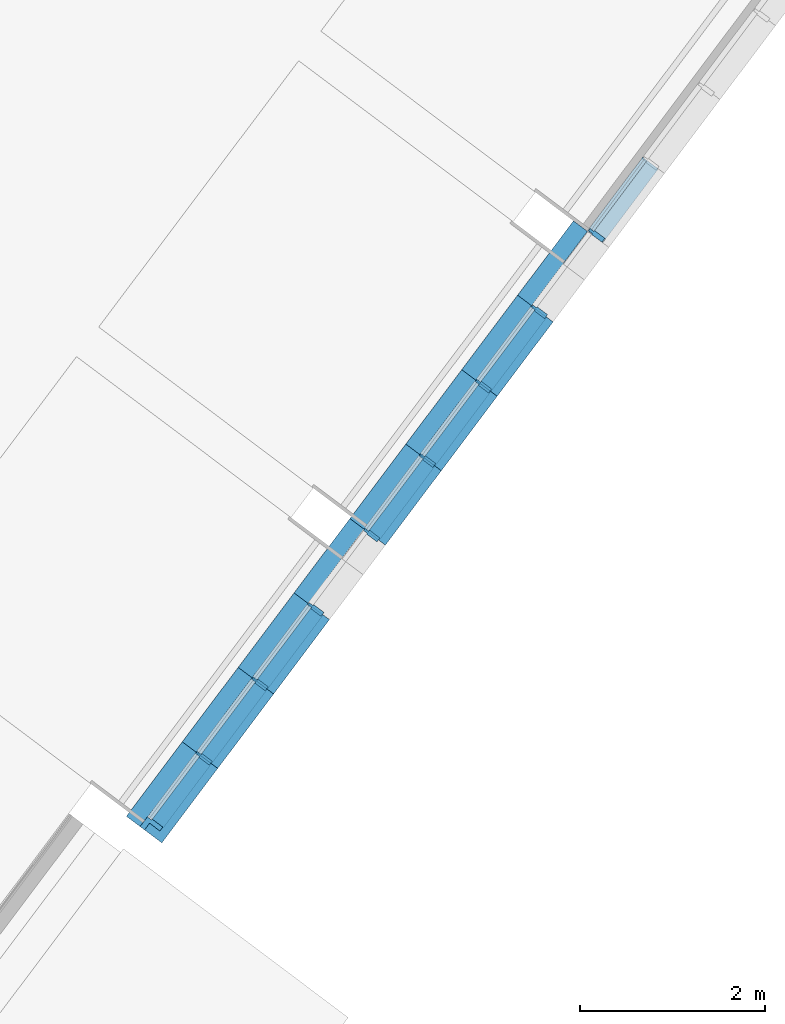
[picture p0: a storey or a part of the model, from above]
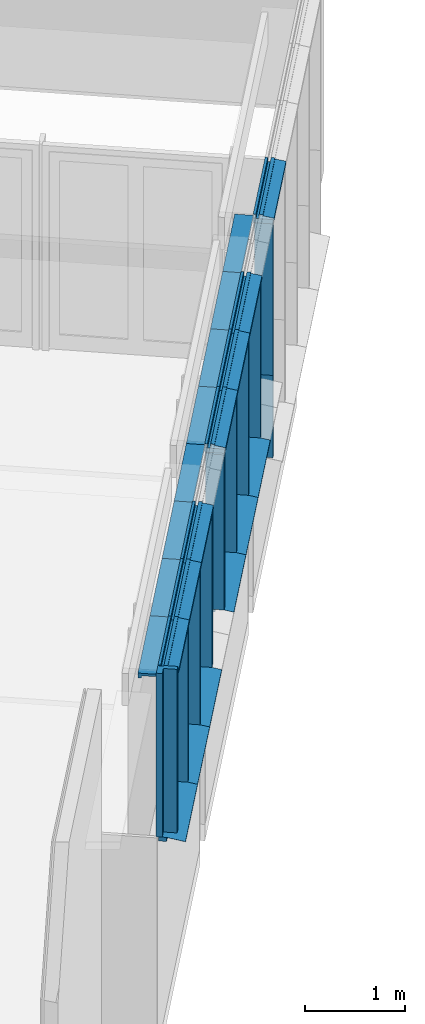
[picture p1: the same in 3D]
Properties of the parts of a building model (IFC2X3), part 1 of 6

# File
Description: ViewDefinition [CoordinationView_V2.0], RevitIdentifiers [VersionGUID: b3ee0134-e129-4b76-bc58-69f363ad4fec, NumberOfSaves: 221], CoordinateReference [CoordinateBase: Coordenadas compartidas, ProjectSite: Interna]
File name: 0001
Time: 2024-03-04T15:58:22
Written by: ODA IFC SDK 22.8
Made in: 22.1.50.17 - Exporter 22.6.2.0 - IU alternativa 22.6.2.0

# IfcProject, 0001
LongName: TÍTOL DEL PROJECTE; Phase: Estado de proyecto

# IfcSite, Default
RefLatitude: 40, 24, 0, 5493; RefLongitude: -3, -40, -59, -880065; RefElevation: 0 m

# IfcBuilding
Pset_BuildingCommon - NumberOfStoreys: 4

# IfcBuildingStorey: Nivel:A- Nivell (4)
Name | LongName | Elevation (m)
PS1- Gimnàs | PS1- Gimnàs | -5.45
PS1- Vestuari | PS1- Vestuari | -4.46
P0- Escola | P0- Escola | 0
PC- Coberta STR | PC- Coberta STR | 3.4

# IfcBeam: STR- V- Acer- RHS- Rectangular- T1:100x50RHS (57)
In: PC- Coberta STR
Type - Pset_BeamCommon - IsExternal: no; LoadBearing: yes
Material: Metal - Acero - 345 MPa
Pset_BeamCommon - Reference: 100x50RHS
Pset_QuantityTakeOff - Reference: 100x50RHS; sets with these values: 2
Name (STR- V- Acer- RHS- Rectangular- T1:100x50RHS:...) | Span (m) | Slope (deg) | Group
5302511 | 1.26 | 0 | Grupo de modelo:BADALOT 1 (elementos excluidos):5302593
5302515 | 0.454 | 0 | Grupo de modelo:BADALOT 1 (elementos excluidos):5302593
5302517 | 1.26 | 0 | Grupo de modelo:BADALOT 1 (elementos excluidos):5302593
5302522 | 0.454 | 0 | Grupo de modelo:BADALOT 1 (elementos excluidos):5302593
5302526 | 1.26 | 0 | Grupo de modelo:BADALOT 1 (elementos excluidos):5302593
5302528 | 0.454 | 0 | Grupo de modelo:BADALOT 1 (elementos excluidos):5302593
5302530 | 0.454 | 0 | Grupo de modelo:BADALOT 1 (elementos excluidos):5302593
5302534 | 1.479 | 0 | Grupo de modelo:BADALOT 1 (elementos excluidos):5302593
5307034 | 1.26 | 0 | Grupo de modelo:BADALOT 1 (elementos excluidos):5302593
5309079 | 1.26 | 0 | Grupo de modelo:BADALOT 2:5309104
5309083 | 0.454 | 0 | Grupo de modelo:BADALOT 2:5309104
5309085 | 1.279 | 0 | Grupo de modelo:BADALOT 2:5309104
5309090 | 0.454 | 0 | Grupo de modelo:BADALOT 2:5309104
5309094 | 1.26 | 0 | Grupo de modelo:BADALOT 2:5309104
5309096 | 0.454 | 0 | Grupo de modelo:BADALOT 2:5309104
5309098 | 0.454 | 0 | Grupo de modelo:BADALOT 2:5309104
5309102 | 1.26 | 0 | Grupo de modelo:BADALOT 2:5309104
5309427 | 1.26 | 0 | Grupo de modelo:BADALOT 2:5309452
5309431 | 0.454 | 0 | Grupo de modelo:BADALOT 2:5309452
5309433 | 1.279 | 0 | Grupo de modelo:BADALOT 2:5309452
5309438 | 0.454 | 0 | Grupo de modelo:BADALOT 2:5309452
5309442 | 1.26 | 0 | Grupo de modelo:BADALOT 2:5309452
5309444 | 0.454 | 0 | Grupo de modelo:BADALOT 2:5309452
5309446 | 0.454 | 0 | Grupo de modelo:BADALOT 2:5309452
5309450 | 1.26 | 0 | Grupo de modelo:BADALOT 2:5309452
5309613 | 1.26 | 0 | Grupo de modelo:BADALOT 2:5309638
5309617 | 0.454 | 0 | Grupo de modelo:BADALOT 2:5309638
5309619 | 1.279 | 0 | Grupo de modelo:BADALOT 2:5309638
5309624 | 0.454 | 0 | Grupo de modelo:BADALOT 2:5309638
5309628 | 1.26 | 0 | Grupo de modelo:BADALOT 2:5309638
5309630 | 0.454 | 0 | Grupo de modelo:BADALOT 2:5309638
5309632 | 0.454 | 0 | Grupo de modelo:BADALOT 2:5309638
5309636 | 1.26 | 0 | Grupo de modelo:BADALOT 2:5309638
5310923 | 1.26 | 0 | Grupo de modelo:BADALOT 2:5309104
5311217 | 1.26 | 0 | Grupo de modelo:BADALOT 2:5309452
5311237 | 1.26 | 0 | Grupo de modelo:BADALOT 2:5309638
5425147 | 1.26 | 0 | Grupo de modelo:BADALOT 3:5425172
5425151 | 0.454 | 0 | Grupo de modelo:BADALOT 3:5425172
5425153 | 1.26 | 0 | Grupo de modelo:BADALOT 3:5425172
5425158 | 0.454 | 0 | Grupo de modelo:BADALOT 3:5425172
5425162 | 1.26 | 0 | Grupo de modelo:BADALOT 3:5425172
5425164 | 0.454 | 0 | Grupo de modelo:BADALOT 3:5425172
5425166 | 0.454 | 0 | Grupo de modelo:BADALOT 3:5425172
5425170 | 1.479 | 0 | Grupo de modelo:BADALOT 3:5425172
5425182 | 1.26 | 0 | Grupo de modelo:BADALOT 3:5425172
5440108 | 4.097 | 0
5440140 | 3.139 | 3.653
5440886 | 5.24 | 2.08348
5440999 | 0.872 | 3.68981
5441164 | 2.229 | 3.68964
5442137 | 1.552 | 3.68611
5442275 | 3.734 | 0
5442300 | 3.535 | 3.24312
5442342 | 5.241 | 2.08871
5442374 | 0.986 | 3.27685
5442399 | 1.752 | 3.27625
5442435 | 2.518 | 3.27601

# IfcBuildingElementProxy: SER- Xemeneia revestiment:SER- Xemeneia revestiment (2)
In: PC- Coberta STR
Type - Material: <Unnamed>
Pset_BuildingElementProxyCommon - Reference: SER- Xemeneia revestiment; sets with these values: 2
Name (SER- Xemeneia revestiment:SER- Xemeneia revestiment:...)
5313121
5313976

# IfcBuildingElementProxy: SOS- fals sostre biblio:SOS- fals sostre biblio, SOS- fals sostre biblio:SOS- fals sostre biblio:4920332
In: P0- Escola
Type - Material: <Unnamed>
Pset_BuildingElementProxyCommon - Reference: SOS- fals sostre biblio; sets with these values: 2

# IfcColumn: STR- P- Acer- RHS- Rectangular- T1:100 x 50RHS (84)
In: PC- Coberta STR
Type - PredefinedType: COLUMN; Material: Metal - Acero - 345 MPa
Type - Pset_ColumnCommon - IsExternal: no; LoadBearing: yes
Pset_ColumnCommon - Reference: 100 x 50RHS
Pset_QuantityTakeOff - Reference: 100 x 50RHS; sets with these values: 2
Name (STR- P- Acer- RHS- Rectangular- T1:100 x 50RHS:...) | Group
5302475 | Grupo de modelo:BADALOT 1 (elementos excluidos):5302593
5302477 | Grupo de modelo:BADALOT 1 (elementos excluidos):5302593
5302479 | Grupo de modelo:BADALOT 1 (elementos excluidos):5302593
5302481 | Grupo de modelo:BADALOT 1 (elementos excluidos):5302593
5302483 | Grupo de modelo:BADALOT 1 (elementos excluidos):5302593
5302485 | Grupo de modelo:BADALOT 1 (elementos excluidos):5302593
5302487 | Grupo de modelo:BADALOT 1 (elementos excluidos):5302593
5302489 | Grupo de modelo:BADALOT 1 (elementos excluidos):5302593
5302491 | Grupo de modelo:BADALOT 1 (elementos excluidos):5302593
5302493 | Grupo de modelo:BADALOT 1 (elementos excluidos):5302593
5302495 | Grupo de modelo:BADALOT 1 (elementos excluidos):5302593
5302497 | Grupo de modelo:BADALOT 1 (elementos excluidos):5302593
5302499 | Grupo de modelo:BADALOT 1 (elementos excluidos):5302593
5302501 | Grupo de modelo:BADALOT 1 (elementos excluidos):5302593
5302503 | Grupo de modelo:BADALOT 1 (elementos excluidos):5302593
5302505 | Grupo de modelo:BADALOT 1 (elementos excluidos):5302593
5302507 | Grupo de modelo:BADALOT 1 (elementos excluidos):5302593
5302509 | Grupo de modelo:BADALOT 1 (elementos excluidos):5302593
5309047 | Grupo de modelo:BADALOT 2:5309104
5309049 | Grupo de modelo:BADALOT 2:5309104
5309051 | Grupo de modelo:BADALOT 2:5309104
5309053 | Grupo de modelo:BADALOT 2:5309104
5309055 | Grupo de modelo:BADALOT 2:5309104
5309057 | Grupo de modelo:BADALOT 2:5309104
5309059 | Grupo de modelo:BADALOT 2:5309104
5309061 | Grupo de modelo:BADALOT 2:5309104
5309063 | Grupo de modelo:BADALOT 2:5309104
5309065 | Grupo de modelo:BADALOT 2:5309104
5309067 | Grupo de modelo:BADALOT 2:5309104
5309069 | Grupo de modelo:BADALOT 2:5309104
5309071 | Grupo de modelo:BADALOT 2:5309104
5309073 | Grupo de modelo:BADALOT 2:5309104
5309075 | Grupo de modelo:BADALOT 2:5309104
5309077 | Grupo de modelo:BADALOT 2:5309104
5309395 | Grupo de modelo:BADALOT 2:5309452
5309397 | Grupo de modelo:BADALOT 2:5309452
5309399 | Grupo de modelo:BADALOT 2:5309452
5309401 | Grupo de modelo:BADALOT 2:5309452
5309403 | Grupo de modelo:BADALOT 2:5309452
5309405 | Grupo de modelo:BADALOT 2:5309452
5309407 | Grupo de modelo:BADALOT 2:5309452
5309409 | Grupo de modelo:BADALOT 2:5309452
5309411 | Grupo de modelo:BADALOT 2:5309452
5309413 | Grupo de modelo:BADALOT 2:5309452
5309415 | Grupo de modelo:BADALOT 2:5309452
5309417 | Grupo de modelo:BADALOT 2:5309452
5309419 | Grupo de modelo:BADALOT 2:5309452
5309421 | Grupo de modelo:BADALOT 2:5309452
5309423 | Grupo de modelo:BADALOT 2:5309452
5309425 | Grupo de modelo:BADALOT 2:5309452
5309581 | Grupo de modelo:BADALOT 2:5309638
5309583 | Grupo de modelo:BADALOT 2:5309638
5309585 | Grupo de modelo:BADALOT 2:5309638
5309587 | Grupo de modelo:BADALOT 2:5309638
5309589 | Grupo de modelo:BADALOT 2:5309638
5309591 | Grupo de modelo:BADALOT 2:5309638
5309593 | Grupo de modelo:BADALOT 2:5309638
5309595 | Grupo de modelo:BADALOT 2:5309638
5309597 | Grupo de modelo:BADALOT 2:5309638
5309599 | Grupo de modelo:BADALOT 2:5309638
5309601 | Grupo de modelo:BADALOT 2:5309638
5309603 | Grupo de modelo:BADALOT 2:5309638
5309605 | Grupo de modelo:BADALOT 2:5309638
5309607 | Grupo de modelo:BADALOT 2:5309638
5309609 | Grupo de modelo:BADALOT 2:5309638
5309611 | Grupo de modelo:BADALOT 2:5309638
5425111 | Grupo de modelo:BADALOT 3:5425172
5425113 | Grupo de modelo:BADALOT 3:5425172
5425115 | Grupo de modelo:BADALOT 3:5425172
5425117 | Grupo de modelo:BADALOT 3:5425172
5425119 | Grupo de modelo:BADALOT 3:5425172
5425121 | Grupo de modelo:BADALOT 3:5425172
5425123 | Grupo de modelo:BADALOT 3:5425172
5425125 | Grupo de modelo:BADALOT 3:5425172
5425127 | Grupo de modelo:BADALOT 3:5425172
5425129 | Grupo de modelo:BADALOT 3:5425172
5425131 | Grupo de modelo:BADALOT 3:5425172
5425133 | Grupo de modelo:BADALOT 3:5425172
5425135 | Grupo de modelo:BADALOT 3:5425172
5425137 | Grupo de modelo:BADALOT 3:5425172
5425139 | Grupo de modelo:BADALOT 3:5425172
5425141 | Grupo de modelo:BADALOT 3:5425172
5425143 | Grupo de modelo:BADALOT 3:5425172
5425145 | Grupo de modelo:BADALOT 3:5425172

# IfcCovering: Techo compuesto:SOS- Fusta- Revestiment- 6 cm (16)
In: P0- Escola
Type - PredefinedType: CEILING
Type - Pset_CoveringCommon - TotalThickness: 0.06 m
Material: _Fusta massisa- T1 0.06 m
Pset_CoveringCommon - Reference: SOS- Fusta- Revestiment- 6 cm; sets with these values: 2
Name (Techo compuesto:SOS- Fusta- Revestiment- 6 cm:...) | Group
102032
102040
102047 | Grupo de modelo:FUS- Conjunt divisoria aules infantil:337545
102054
115284 | Grupo de modelo:SOS- fusta- despatxos:115317
115290 | Grupo de modelo:SOS- fusta- despatxos:115317
115297 | Grupo de modelo:SOS- fusta- despatxos:115317
115304 | Grupo de modelo:SOS- fusta- despatxos:115317
115311 | Grupo de modelo:SOS- fusta- despatxos:115317
342692 | Grupo de modelo:FUS- Conjunt divisoria aules infantil:337581
470245 | Grupo de modelo:Grup aula:4934097
3335595 | Grupo de modelo:Grup aula:4934097
4940526 | Grupo de modelo:Grup aula:4940566
4940549 | Grupo de modelo:Grup aula:4940566
4940782 | Grupo de modelo:Grup aula:4940822
4940805 | Grupo de modelo:Grup aula:4940822

# IfcCovering: Techo compuesto:SOS- Guix Laminat Acústic- Aillament- 6,5 cm 2 (9)
Type - PredefinedType: CEILING
Type - Pset_CoveringCommon - TotalThickness: 0.065 m
Material: _Aillament 0.05 m, _PYL- SOS 0.015 m
Pset_CoveringCommon - Reference: SOS- Guix Laminat Acústic- Aillament- 6,5 cm 2; sets with these values: 2
Name (Techo compuesto:SOS- Guix Laminat Acústic- Aillament- 6,5 cm 2:...) | In | Group
101186 | PS1- Gimnàs | Grupo de modelo:SOS- grup sostre i tabica gimnàs:101203
101219 | PS1- Gimnàs | Grupo de modelo:SOS- grup sostre i tabica gimnàs:101232
101235 | PS1- Gimnàs | Grupo de modelo:SOS- grup sostre i tabica gimnàs:101248
101253 | PS1- Gimnàs
114977 | PS1- Vestuari | Grupo de modelo:SOS- Planta pista:115104
115002 | PS1- Vestuari | Grupo de modelo:SOS- Planta pista:115104
115026 | PS1- Vestuari | Grupo de modelo:SOS- Planta pista:115104
115050 | PS1- Vestuari | Grupo de modelo:SOS- Planta pista:115104
115074 | PS1- Vestuari | Grupo de modelo:SOS- Planta pista:115104

# IfcCovering: Techo compuesto:SOS- Guix Laminat- Aillament- 10 cm (2)
In: P0- Escola
Type - PredefinedType: CEILING
Type - Pset_CoveringCommon - TotalThickness: 0.1 m
Material: _Aillament 0.085 m, _PYL- SOS 0.015 m
Pset_CoveringCommon - Reference: SOS- Guix Laminat- Aillament- 10 cm; sets with these values: 2
Name (Techo compuesto:SOS- Guix Laminat- Aillament- 10 cm:...)
4915247
4915999

# IfcCovering: Techo compuesto:SOS- Guix Laminat- Aillament- 3,5 cm (13)
Type - PredefinedType: CEILING
Type - Pset_CoveringCommon - TotalThickness: 0.035 m
Material: _Aillament 0.02 m, _PYL- SOS 0.015 m
Pset_CoveringCommon - Reference: SOS- Guix Laminat- Aillament- 3,5 cm; sets with these values: 2
Name (Techo compuesto:SOS- Guix Laminat- Aillament- 3,5 cm:...) | In | Group
101071 | P0- Escola
101078 | P0- Escola | Grupo de modelo:REV- Acabats interiors modul:100748
101085 | P0- Escola | Grupo de modelo:REV- Acabats interiors modul:100819
114992 | PS1- Vestuari | Grupo de modelo:SOS- Planta pista:115104
115017 | PS1- Vestuari | Grupo de modelo:SOS- Planta pista:115104
115041 | PS1- Vestuari | Grupo de modelo:SOS- Planta pista:115104
115065 | PS1- Vestuari | Grupo de modelo:SOS- Planta pista:115104
115089 | PS1- Vestuari | Grupo de modelo:SOS- Planta pista:115104
115220 | P0- Escola | Grupo de modelo:SOS- MODUL INFAINTIL I MENJADOR:115116
115227 | P0- Escola | Grupo de modelo:SOS- MODUL INFAINTIL I MENJADOR:115116
5387460 | P0- Escola
5403830 | P0- Escola
5404382 | P0- Escola

# IfcCovering: Techo compuesto:SOS- Guix Laminat- Aillament- 5 cm (5)
In: PS1- Gimnàs
Type - PredefinedType: CEILING
Type - Pset_CoveringCommon - TotalThickness: 0.05 m
Material: _Aillament 0.035 m, _PYL- SOS 0.015 m; Group: Grupo de modelo:SOS- Planta pista:115104
Pset_CoveringCommon - Reference: SOS- Guix Laminat- Aillament- 5 cm; sets with these values: 2
Name (Techo compuesto:SOS- Guix Laminat- Aillament- 5 cm:...)
114983
115008
115032
115056
115080

# IfcCovering: Techo compuesto:SOS- Guix Laminat- Aillament- 6,5 cm (57)
Type - PredefinedType: CEILING
Type - Pset_CoveringCommon - TotalThickness: 0.065 m
Material: _Aillament 0.05 m, _PYL- SOS 0.015 m
Pset_CoveringCommon - Reference: SOS- Guix Laminat- Aillament- 6,5 cm; sets with these values: 2
Name (Techo compuesto:SOS- Guix Laminat- Aillament- 6,5 cm:...) | In | Group
100559 | P0- Escola
100570 | P0- Escola
100695 | P0- Escola | Grupo de modelo:REV- Acabats interiors modul:100748
100705 | P0- Escola | Grupo de modelo:REV- Acabats interiors modul:100748
100766 | P0- Escola | Grupo de modelo:REV- Acabats interiors modul:100819
100776 | P0- Escola | Grupo de modelo:REV- Acabats interiors modul:100819
100856 | P0- Escola | Grupo de modelo:REV- Acabats interiors modul:100748
100863 | P0- Escola | Grupo de modelo:REV- Acabats interiors modul:100819
100945 | P0- Escola
100955 | P0- Escola
101018 | P0- Escola
101192 | PS1- Gimnàs | Grupo de modelo:SOS- grup sostre i tabica gimnàs:101203
101212 | PS1- Gimnàs
101225 | PS1- Gimnàs | Grupo de modelo:SOS- grup sostre i tabica gimnàs:101232
101241 | PS1- Gimnàs | Grupo de modelo:SOS- grup sostre i tabica gimnàs:101248
101367 | P0- Escola
101390 | P0- Escola
101583 | P0- Escola
101592 | P0- Escola
101599 | P0- Escola
101606 | P0- Escola
101613 | P0- Escola
101715 | P0- Escola
102026 | P0- Escola
115111 | P0- Escola | Grupo de modelo:SOS- MODUL INFAINTIL I MENJADOR:115116
115119 | P0- Escola | Grupo de modelo:SOS- MODUL INFAINTIL I MENJADOR:115116
115134 | P0- Escola | Grupo de modelo:SOS- MODUL INFAINTIL I MENJADOR:115116
115141 | P0- Escola | Grupo de modelo:SOS- MODUL INFAINTIL I MENJADOR:115116
115148 | P0- Escola | Grupo de modelo:SOS- MODUL INFAINTIL I MENJADOR:115116
115156 | P0- Escola | Grupo de modelo:SOS- MODUL INFAINTIL I MENJADOR:115116
115165 | P0- Escola | Grupo de modelo:SOS- MODUL INFAINTIL I MENJADOR:115116
115172 | P0- Escola | Grupo de modelo:SOS- MODUL INFAINTIL I MENJADOR:115116
115179 | P0- Escola | Grupo de modelo:SOS- MODUL INFAINTIL I MENJADOR:115116
115186 | P0- Escola | Grupo de modelo:SOS- MODUL INFAINTIL I MENJADOR:115116
115193 | P0- Escola | Grupo de modelo:SOS- MODUL INFAINTIL I MENJADOR:115116
115204 | P0- Escola | Grupo de modelo:SOS- MODUL INFAINTIL I MENJADOR:115116
115213 | P0- Escola | Grupo de modelo:SOS- MODUL INFAINTIL I MENJADOR:115116
115234 | P0- Escola | Grupo de modelo:SOS- MODUL INFAINTIL I MENJADOR:115116
115241 | P0- Escola | Grupo de modelo:SOS- MODUL INFAINTIL I MENJADOR:115116
115248 | P0- Escola | Grupo de modelo:SOS- MODUL INFAINTIL I MENJADOR:115116
115255 | P0- Escola | Grupo de modelo:SOS- MODUL INFAINTIL I MENJADOR:115116
115270 | P0- Escola | Grupo de modelo:SOS- MODUL INFAINTIL I MENJADOR:115116
115277 | P0- Escola | Grupo de modelo:SOS- MODUL INFAINTIL I MENJADOR:115116
1253167 | P0- Escola
1352866 | P0- Escola
4915733 | P0- Escola
4925135 | P0- Escola
4940842 | P0- Escola | Grupo de modelo:Grup aula:4934097
4941253 | P0- Escola | Grupo de modelo:Grup aula:4940566
4941303 | P0- Escola | Grupo de modelo:Grup aula:4940822
5389637 | P0- Escola
5406528 | P0- Escola | Grupo de modelo:Modul Banys 2:100913
5406683 | P0- Escola | Grupo de modelo:Modul Banys 2:100913
5406933 | P0- Escola | Grupo de modelo:Modul Banys (elementos excluidos):100597
5406947 | P0- Escola | Grupo de modelo:Modul Banys (elementos excluidos):100597
5413137 | P0- Escola | Grupo de modelo:SOS- MODUL INFAINTIL I MENJADOR:115116
5413163 | P0- Escola | Grupo de modelo:SOS- MODUL INFAINTIL I MENJADOR:115116

# IfcCurtainWall: Muro básico:ENV- Ceràmic- 9 cm (3)
In: P0- Escola
Type - Material: _Ceràmica- ENV 0.09 m
Type - Pset_CurtainWallCommon - IsExternal: yes
Pset_CurtainWallCommon - Reference: ENV- Ceràmic- 9 cm
Pset_QuantityTakeOff - Reference: ENV- Ceràmic- 9 cm
Name (Muro básico:ENV- Ceràmic- 9 cm:...) | Group
2141167 | Grupo de modelo:BANY1:2141168
2334015 | Grupo de modelo:BANY1:2334016
2334665 | Grupo de modelo:BANY1:2334666

# IfcCurtainWall: Muro básico:REV- Fusta- T1- 3,5 cm (11)
In: P0- Escola
Type - Material: _Fusta massisa- T1- REV- PAV 0.015 m, _Genèric perfils, muntants, rastrells 0.02 m
Type - Pset_CurtainWallCommon - IsExternal: no; ThermalTransmittance: 1.25 kg/K/s3
Pset_CurtainWallCommon - Reference: REV- Fusta- T1- 3,5 cm
Pset_QuantityTakeOff - Reference: REV- Fusta- T1- 3,5 cm
Name (Muro básico:REV- Fusta- T1- 3,5 cm:...) | Group
373448
373449
462916 | Grupo de modelo:Grup aula:4934097
2141159 | Grupo de modelo:BANY1:2141168
2141160 | Grupo de modelo:BANY1:2141168
2334007 | Grupo de modelo:BANY1:2334016
2334008 | Grupo de modelo:BANY1:2334016
2334657 | Grupo de modelo:BANY1:2334666
2334658 | Grupo de modelo:BANY1:2334666
4940524 | Grupo de modelo:Grup aula:4940566
4940780 | Grupo de modelo:Grup aula:4940822

# IfcCurtainWall: Muro cortina:MC- EXT- AL1- Fa porxo (9)
In: P0- Escola
Type - Pset_CurtainWallCommon - IsExternal: yes
Pset_CurtainWallCommon - Reference: MC- EXT- AL1- Fa porxo
Pset_QuantityTakeOff - Reference: MC- EXT- AL1- Fa porxo
Group: Grupo de modelo:Fa-:4013115
Name (Muro cortina:MC- EXT- AL1- Fa porxo:...)
4009178
4510528
4816952
4825851
4935185
4935323
4935594
4935732
4943344

# IfcCurtainWall: Muro cortina:MC- EXT- AL3 (3)
In: P0- Escola
Type - Pset_CurtainWallCommon - IsExternal: yes
Pset_CurtainWallCommon - Reference: MC- EXT- AL3
Pset_QuantityTakeOff - Reference: MC- EXT- AL3
Name (Muro cortina:MC- EXT- AL3:...)
895046
5131475
5410565

# IfcCurtainWall: Muro cortina:MC- EXT- AL4a (2)
In: P0- Escola
Type - Pset_CurtainWallCommon - IsExternal: yes
Pset_CurtainWallCommon - Reference: MC- EXT- AL4a
Pset_QuantityTakeOff - Reference: MC- EXT- AL4a
Name (Muro cortina:MC- EXT- AL4a:...)
4810601
4889902

# IfcCurtainWall: Muro cortina:MC- EXT- AL5b (2)
In: P0- Escola
Type - Pset_CurtainWallCommon - IsExternal: yes
Pset_CurtainWallCommon - Reference: MC- EXT- AL5b
Pset_QuantityTakeOff - Reference: MC- EXT- AL5b
Name (Muro cortina:MC- EXT- AL5b:...)
4898266
4899970

# IfcCurtainWall: Muro cortina:MC- EXT- AL6 (8)
In: PS1- Vestuari
Type - Pset_CurtainWallCommon - IsExternal: yes
Pset_CurtainWallCommon - Reference: MC- EXT- AL6
Pset_QuantityTakeOff - Reference: MC- EXT- AL6
Name (Muro cortina:MC- EXT- AL6:...)
102148
102313
102319
102326
102332
102338
5323810
5323961

# IfcCurtainWall: Muro cortina:MC- EXT- AL7a (3)
In: P0- Escola
Type - Pset_CurtainWallCommon - IsExternal: yes
Pset_CurtainWallCommon - Reference: MC- EXT- AL7a
Pset_QuantityTakeOff - Reference: MC- EXT- AL7a
Group: Grupo de modelo:Fa-:4013115
Name (Muro cortina:MC- EXT- AL7a:...)
5381533
5401885
5401914

# IfcCurtainWall: Muro cortina:MC- EXT- Al4b (3)
In: P0- Escola
Type - Pset_CurtainWallCommon - IsExternal: yes
Pset_CurtainWallCommon - Reference: MC- EXT- Al4b
Pset_QuantityTakeOff - Reference: MC- EXT- Al4b
Name (Muro cortina:MC- EXT- Al4b:...)
4792293
4809763
4810606

# IfcCurtainWall: Muro cortina:MC- EXT- MC2 (7)
In: P0- Escola
Type - Pset_CurtainWallCommon - IsExternal: yes
Pset_CurtainWallCommon - Reference: MC- EXT- MC2
Pset_QuantityTakeOff - Reference: MC- EXT- MC2
Group: Grupo de modelo:Fa-:4013115
Name (Muro cortina:MC- EXT- MC2:...)
2564638
3336758
4816830
4820767
4825035
6029251
6029575

# IfcCurtainWall: Muro cortina:MC- EXT- MC5 (4)
In: P0- Escola
Type - Pset_CurtainWallCommon - IsExternal: yes
Pset_CurtainWallCommon - Reference: MC- EXT- MC5
Pset_QuantityTakeOff - Reference: MC- EXT- MC5
Group: Grupo de modelo:Fa-:4013115
Name (Muro cortina:MC- EXT- MC5:...)
4468966
4935647
4943381
6029327

# IfcCurtainWall: Muro cortina:MC- EXT- MC6 (4)
In: P0- Escola
Type - Pset_CurtainWallCommon - IsExternal: yes
Pset_CurtainWallCommon - Reference: MC- EXT- MC6
Pset_QuantityTakeOff - Reference: MC- EXT- MC6
Name (Muro cortina:MC- EXT- MC6:...)
4774200
4791940
4865601
4873584

# IfcCurtainWall: Muro cortina:MC- EXT- MC7 (2)
In: P0- Escola
Type - Pset_CurtainWallCommon - IsExternal: yes
Pset_CurtainWallCommon - Reference: MC- EXT- MC7
Pset_QuantityTakeOff - Reference: MC- EXT- MC7
Name (Muro cortina:MC- EXT- MC7:...)
4908964
4909148

# IfcCurtainWall: Muro cortina:MC- EXT- MC8- Biblio, Muro cortina:MC- EXT- MC8- Biblio:4924527
In: PC- Coberta STR
Type - Pset_CurtainWallCommon - IsExternal: yes
Pset_CurtainWallCommon - Reference: MC- EXT- MC8- Biblio
Pset_QuantityTakeOff - Reference: MC- EXT- MC8- Biblio

# IfcCurtainWall: Muro cortina:MC- EXT- MC9, Muro cortina:MC- EXT- MC9:4868636
In: P0- Escola
Type - Pset_CurtainWallCommon - IsExternal: yes
Pset_CurtainWallCommon - Reference: MC- EXT- MC9
Pset_QuantityTakeOff - Reference: MC- EXT- MC9

# IfcCurtainWall: Muro cortina:MC- EXT- MCv1- Portes (4)
In: PS1- Gimnàs
Type - Pset_CurtainWallCommon - IsExternal: yes
Pset_CurtainWallCommon - Reference: MC- EXT- MCv1- Portes
Pset_QuantityTakeOff - Reference: MC- EXT- MCv1- Portes
Name (Muro cortina:MC- EXT- MCv1- Portes:...)
4666957
4685242
4704293
4718935

# IfcCurtainWall: Muro cortina:MC- EXT- MCv1- frontal, Muro cortina:MC- EXT- MCv1- frontal:4694275
In: PS1- Gimnàs
Type - Pset_CurtainWallCommon - IsExternal: yes
Pset_CurtainWallCommon - Reference: MC- EXT- MCv1- frontal
Pset_QuantityTakeOff - Reference: MC- EXT- MCv1- frontal

# IfcCurtainWall: Muro cortina:MC- EXT- MCv1- lateral (2)
In: PS1- Gimnàs
Type - Pset_CurtainWallCommon - IsExternal: yes
Pset_CurtainWallCommon - Reference: MC- EXT- MCv1- lateral
Pset_QuantityTakeOff - Reference: MC- EXT- MCv1- lateral
Name (Muro cortina:MC- EXT- MCv1- lateral:...)
4667045
4756194

# IfcCurtainWall: Muro cortina:MC- EXT- MCv1- lateral 2, Muro cortina:MC- EXT- MCv1- lateral 2:4667071
In: PS1- Gimnàs
Type - Pset_CurtainWallCommon - IsExternal: yes
Pset_CurtainWallCommon - Reference: MC- EXT- MCv1- lateral 2
Pset_QuantityTakeOff - Reference: MC- EXT- MCv1- lateral 2

# IfcCurtainWall: Muro cortina:MC- INT- C1, Muro cortina:MC- INT- C1:4901822
In: P0- Escola
Type - Pset_CurtainWallCommon - IsExternal: yes
Pset_CurtainWallCommon - Reference: MC- INT- C1
Pset_QuantityTakeOff - Reference: MC- INT- C1

# IfcCurtainWall: Muro cortina:MC- INT- C2, Muro cortina:MC- INT- C2:5092651
In: P0- Escola
Type - Pset_CurtainWallCommon - IsExternal: yes
Pset_CurtainWallCommon - Reference: MC- INT- C2
Pset_QuantityTakeOff - Reference: MC- INT- C2

# IfcCurtainWall: Muro cortina:MC- INT- Fa Pista (2)
In: P0- Escola
Type - Pset_CurtainWallCommon - IsExternal: yes
Pset_CurtainWallCommon - Reference: MC- INT- Fa Pista
Pset_QuantityTakeOff - Reference: MC- INT- Fa Pista
Name (Muro cortina:MC- INT- Fa Pista:...)
4865596
4868010

# IfcCurtainWall: Muro cortina:MC- INT- K3a- Fa Biblio (2)
In: P0- Escola
Type - Pset_CurtainWallCommon - IsExternal: yes
Pset_CurtainWallCommon - Reference: MC- INT- K3a- Fa Biblio
Pset_QuantityTakeOff - Reference: MC- INT- K3a- Fa Biblio
Name (Muro cortina:MC- INT- K3a- Fa Biblio:...)
4913482
4914954

# IfcCurtainWall: Muro cortina:MC- INT- K3a- Fa Pista (2)
In: P0- Escola
Type - Pset_CurtainWallCommon - IsExternal: yes
Pset_CurtainWallCommon - Reference: MC- INT- K3a- Fa Pista
Pset_QuantityTakeOff - Reference: MC- INT- K3a- Fa Pista
Name (Muro cortina:MC- INT- K3a- Fa Pista:...)
4892050
4928468

# IfcCurtainWall: Muro cortina:MC- INT- a1 (3)
In: P0- Escola
Type - Pset_CurtainWallCommon - IsExternal: yes
Pset_CurtainWallCommon - Reference: MC- INT- a1
Pset_QuantityTakeOff - Reference: MC- INT- a1
Name (Muro cortina:MC- INT- a1:...) | Group
462851 | Grupo de modelo:Grup aula:4934097
4940459 | Grupo de modelo:Grup aula:4940566
4940715 | Grupo de modelo:Grup aula:4940822

# IfcCurtainWall: Muro cortina:MC- INT- a2, Muro cortina:MC- INT- a2:360232
In: P0- Escola
Type - Pset_CurtainWallCommon - IsExternal: yes
Pset_CurtainWallCommon - Reference: MC- INT- a2
Pset_QuantityTakeOff - Reference: MC- INT- a2

# IfcCurtainWall: Muro cortina:MC- INT- a3, Muro cortina:MC- INT- a3:338958
In: P0- Escola
Type - Pset_CurtainWallCommon - IsExternal: yes
Pset_CurtainWallCommon - Reference: MC- INT- a3
Pset_QuantityTakeOff - Reference: MC- INT- a3

# IfcCurtainWall: Muro cortina:MC- INT- a4 (2)
In: P0- Escola
Type - Pset_CurtainWallCommon - IsExternal: yes
Pset_CurtainWallCommon - Reference: MC- INT- a4
Pset_QuantityTakeOff - Reference: MC- INT- a4
Name (Muro cortina:MC- INT- a4:...)
211473
369614

# IfcCurtainWall: Muro cortina:MC- INT- a4- 5cm (2)
In: P0- Escola
Type - Pset_CurtainWallCommon - IsExternal: yes
Pset_CurtainWallCommon - Reference: MC- INT- a4- 5cm
Pset_QuantityTakeOff - Reference: MC- INT- a4- 5cm
Name (Muro cortina:MC- INT- a4- 5cm:...)
371275
372966

# IfcCurtainWall: Muro cortina:MC- INT- b3, Muro cortina:MC- INT- b3:5100338
In: P0- Escola
Type - Pset_CurtainWallCommon - IsExternal: yes
Pset_CurtainWallCommon - Reference: MC- INT- b3
Pset_QuantityTakeOff - Reference: MC- INT- b3

# IfcCurtainWall: Muro cortina:MC- INT- k1- Bany infantil (3)
In: P0- Escola
Type - Pset_CurtainWallCommon - IsExternal: yes
Pset_CurtainWallCommon - Reference: MC- INT- k1- Bany infantil
Pset_QuantityTakeOff - Reference: MC- INT- k1- Bany infantil
Name (Muro cortina:MC- INT- k1- Bany infantil:...) | Group
2141140 | Grupo de modelo:BANY1:2141168
2333993 | Grupo de modelo:BANY1:2334016
2334643 | Grupo de modelo:BANY1:2334666

# IfcCurtainWall: Muro cortina:MC- INT- k1- Bany infantil- Peprendicular (3)
In: P0- Escola
Type - Pset_CurtainWallCommon - IsExternal: yes
Pset_CurtainWallCommon - Reference: MC- INT- k1- Bany infantil- Peprendicular
Pset_QuantityTakeOff - Reference: MC- INT- k1- Bany infantil- Peprendicular
Name (Muro cortina:MC- INT- k1- Bany infantil- Peprendicular:...) | Group
2141161 | Grupo de modelo:BANY1:2141168
2334009 | Grupo de modelo:BANY1:2334016
2334659 | Grupo de modelo:BANY1:2334666

# IfcCurtainWall: Muro cortina:MC- INT- k10- Pati passadís (2)
In: P0- Escola
Type - Pset_CurtainWallCommon - IsExternal: yes
Pset_CurtainWallCommon - Reference: MC- INT- k10- Pati passadís
Pset_QuantityTakeOff - Reference: MC- INT- k10- Pati passadís
Group: Grupo de modelo:Fusteries interior (elementos excluidos):3262893
Name (Muro cortina:MC- INT- k10- Pati passadís:...)
3299908
3300245

# IfcCurtainWall: Muro cortina:MC- INT- k2- Pati passadís (4)
In: P0- Escola
Type - Pset_CurtainWallCommon - IsExternal: yes
Pset_CurtainWallCommon - Reference: MC- INT- k2- Pati passadís
Pset_QuantityTakeOff - Reference: MC- INT- k2- Pati passadís
Group: Grupo de modelo:Fusteries interior (elementos excluidos):3262893
Name (Muro cortina:MC- INT- k2- Pati passadís:...)
3283211
3283535
5393540
5405264

# IfcCurtainWall: Muro cortina:MC- INT- k2- Pati passadís curt (3)
In: P0- Escola
Type - Pset_CurtainWallCommon - IsExternal: yes
Pset_CurtainWallCommon - Reference: MC- INT- k2- Pati passadís curt
Pset_QuantityTakeOff - Reference: MC- INT- k2- Pati passadís curt
Group: Grupo de modelo:Fusteries interior (elementos excluidos):3262893
Name (Muro cortina:MC- INT- k2- Pati passadís curt:...)
5379421
5393649
5405373

# IfcCurtainWall: Muro cortina:MC- INT- k7- Aules infantil (9)
In: P0- Escola
Type - Pset_CurtainWallCommon - IsExternal: yes
Pset_CurtainWallCommon - Reference: MC- INT- k7- Aules infantil
Pset_QuantityTakeOff - Reference: MC- INT- k7- Aules infantil
Name (Muro cortina:MC- INT- k7- Aules infantil:...) | Group
2564810
3277907 | Grupo de modelo:Fusteries interior (elementos excluidos):3262893
3278063 | Grupo de modelo:Fusteries interior (elementos excluidos):3262893
3298244 | Grupo de modelo:Fusteries interior (elementos excluidos):3262893
3298452 | Grupo de modelo:Fusteries interior (elementos excluidos):3262893
3298845 | Grupo de modelo:Fusteries interior (elementos excluidos):3262893
3299130 | Grupo de modelo:Fusteries interior (elementos excluidos):3262893
5256155 | Grupo de modelo:Fusteries interior (elementos excluidos):3262893
5256242 | Grupo de modelo:Fusteries interior (elementos excluidos):3262893

# IfcCurtainWall: Muro cortina:MC- fusta- prestage gimnàs (3)
In: PS1- Vestuari
Type - Pset_CurtainWallCommon - IsExternal: yes
Pset_CurtainWallCommon - Reference: MC- fusta- prestage gimnàs
Pset_QuantityTakeOff - Reference: MC- fusta- prestage gimnàs
Name (Muro cortina:MC- fusta- prestage gimnàs:...)
4768717
4768722
4768898

# IfcDoor: EnvaMobil_AulaInfantil_F1:EnvaMobil_AulaInfantil_F1 (2)
In: P0- Escola
Type - ParameterTakesPrecedence: no; Sizeable: no; Material: _Vidre, _Fusta massisa- T1
Type - Pset_DoorCommon - IsExternal: no
OverallHeight: 2.565 m; OverallWidth: 3.258 m
Pset_DoorCommon - Reference: EnvaMobil_AulaInfantil_F1
Pset_QuantityTakeOff - Reference: EnvaMobil_AulaInfantil_F1
Name (EnvaMobil_AulaInfantil_F1:EnvaMobil_AulaInfantil_F1:...) | Group
139861 | Grupo de modelo:FUS- Conjunt divisoria aules infantil:337545
337577 | Grupo de modelo:FUS- Conjunt divisoria aules infantil:337581

# IfcDoor: FUS- Alu- Fulla porta opaca:FUS- Alu- Fulla porta opaca- 2,505X0,85, FUS- Alu- Fulla porta opaca:FUS- Alu- Fulla porta opaca- 2,505X0,85:5135024
In: P0- Escola
Type - ParameterTakesPrecedence: no; Sizeable: no; Material: _Alumini- T1- Perfil
Type - Pset_DoorCommon - IsExternal: no
OverallHeight: 2.574 m; OverallWidth: 0.9966 m
Pset_DoorCommon - Reference: FUS- Alu- Fulla porta opaca- 2,505X0,85
Pset_QuantityTakeOff - Reference: FUS- Alu- Fulla porta opaca- 2,505X0,85

# IfcDoor: FUS- Cancela- C3:FUS- Cancela- C3, FUS- Cancela- C3:FUS- Cancela- C3:5541895
In: P0- Escola
Type - ParameterTakesPrecedence: no; Sizeable: no; Material: _Fusta massisa- T1- REV- PAV, _Vidre
Type - Pset_DoorCommon - IsExternal: no
OverallHeight: 2.505 m; OverallWidth: 2.382 m
Pset_DoorCommon - Reference: FUS- Cancela- C3
Pset_QuantityTakeOff - Reference: FUS- Cancela- C3

# IfcDoor: FUS- Fusta- Porta corredera aules:FUS- Fusta- Porta corredera aules (3)
In: P0- Escola
Type - ParameterTakesPrecedence: no; Sizeable: no; Material: _Genèric perfils, muntants, rastrells, _Fusta massisa- T1
Type - Pset_DoorCommon - IsExternal: no
OverallHeight: 2.56 m; OverallWidth: 5.48161 m
Pset_DoorCommon - Reference: FUS- Fusta- Porta corredera aules
Pset_QuantityTakeOff - Reference: FUS- Fusta- Porta corredera aules
Name (FUS- Fusta- Porta corredera aules:FUS- Fusta- Porta corredera aules:...) | Group
5240804 | Grupo de modelo:Grup aula:4940566
5245991 | Grupo de modelo:Grup aula:4934097
5245995 | Grupo de modelo:Grup aula:4940822

# IfcDoor: FUS- Fusta- envà mobil 3 fulles:FUS- Fusta- envà mobil 3 fulles, FUS- Fusta- envà mobil 3 fulles:FUS- Fusta- envà mobil 3 fulles:5295227
In: P0- Escola
Type - ParameterTakesPrecedence: no; Sizeable: no; Material: _Fusta massisa- T1
Type - Pset_DoorCommon - IsExternal: no
OverallHeight: 2.56 m; OverallWidth: 6.108 m
Pset_DoorCommon - Reference: FUS- Fusta- envà mobil 3 fulles
Pset_QuantityTakeOff - Reference: FUS- Fusta- envà mobil 3 fulles

# IfcDoor: FUS- Marc Fusta- marc ocult variable- remat ascensor:FUS- Porta Fusta- marc ocult- 90x250,5 cm, FUS- Marc Fusta- marc ocult variable- remat ascensor:FUS- Porta Fusta- marc ocult- 90x250,5 cm:5371570
In: P0- Escola
Type - ParameterTakesPrecedence: no; Sizeable: no; Material: _Fusta massisa- T1
Type - Pset_DoorCommon - IsExternal: no
OverallHeight: 2.545 m; OverallWidth: 0.98 m; Group: Grupo de modelo:REV- MODUL Magatzem+ ascensor:101023
Pset_DoorCommon - Reference: FUS- Porta Fusta- marc ocult- 90x250,5 cm
Pset_QuantityTakeOff - Reference: FUS- Porta Fusta- marc ocult- 90x250,5 cm

# IfcDoor: FUS- Porta Fusta- Tancament passadis:FUS- Porta Fusta- Tancament passadis, FUS- Porta Fusta- Tancament passadis:FUS- Porta Fusta- Tancament passadis:5390933
In: P0- Escola
Type - OperationType: SINGLE_SWING_LEFT; ParameterTakesPrecedence: no; Sizeable: no; Material: _Fusta massisa- T1
Type - FUS- Porta Fusta- Tancament passadis:FUS- Porta Fusta- Tancament passadis:5390933:1 - PanelOperation: SWINGING
Type - Pset_DoorCommon - IsExternal: no
OverallHeight: 2.565 m; OverallWidth: 1.83862 m
Pset_DoorCommon - Reference: FUS- Porta Fusta- Tancament passadis
Pset_QuantityTakeOff - Reference: FUS- Porta Fusta- Tancament passadis

# IfcDoor: FUS- Porta Fusta- Tancament passadis:FUS- Porta Fusta- Tancament passadis, FUS- Porta Fusta- Tancament passadis:FUS- Porta Fusta- Tancament passadis:5403311
In: P0- Escola
Type - OperationType: SINGLE_SWING_LEFT; ParameterTakesPrecedence: no; Sizeable: no; Material: _Fusta massisa- T1
Type - FUS- Porta Fusta- Tancament passadis:FUS- Porta Fusta- Tancament passadis:5403311:1 - PanelOperation: SWINGING
Type - Pset_DoorCommon - IsExternal: no
OverallHeight: 2.505 m; OverallWidth: 1.83862 m
Pset_DoorCommon - Reference: FUS- Porta Fusta- Tancament passadis
Pset_QuantityTakeOff - Reference: FUS- Porta Fusta- Tancament passadis

# IfcDoor: FUS- Porta Fusta- Tancament passadis:FUS- Porta Fusta- Tancament passadis, FUS- Porta Fusta- Tancament passadis:FUS- Porta Fusta- Tancament passadis:5404703
In: P0- Escola
Type - OperationType: SINGLE_SWING_LEFT; ParameterTakesPrecedence: no; Sizeable: no; Material: _Fusta massisa- T1
Type - FUS- Porta Fusta- Tancament passadis:FUS- Porta Fusta- Tancament passadis:5404703:1 - PanelOperation: SWINGING
Type - Pset_DoorCommon - IsExternal: no
OverallHeight: 2.505 m; OverallWidth: 1.51312 m
Pset_DoorCommon - Reference: FUS- Porta Fusta- Tancament passadis
Pset_QuantityTakeOff - Reference: FUS- Porta Fusta- Tancament passadis

# IfcDoor: FUS- Porta Fusta- marc ocult variable- obertura interior:FUS- Porta Fusta- marc ocult- 90x250,5 cm, FUS- Porta Fusta- marc ocult variable- obertura interior:FUS- Porta Fusta- marc ocult- 90x250,5 cm:5367172
In: P0- Escola
Type - ParameterTakesPrecedence: no; Sizeable: no; Material: _Fusta massisa- T1
Type - Pset_DoorCommon - IsExternal: no
OverallHeight: 2.545 m; OverallWidth: 0.87 m; Group: Grupo de modelo:REV- MODUL Magatzem+ ascensor:101023
Pset_DoorCommon - Reference: FUS- Porta Fusta- marc ocult- 90x250,5 cm
Pset_QuantityTakeOff - Reference: FUS- Porta Fusta- marc ocult- 90x250,5 cm

# IfcDoor: FUS- Porta Fusta- marc ocult- obertura corredera:FUS- Porta Fusta- marc ocult- 90x250,5 cm (2)
In: P0- Escola
Type - ParameterTakesPrecedence: no; Sizeable: no; Material: _Fusta tecnològica- REV- PAV, _Fusta massisa- T1- REV- PAV
Type - Pset_DoorCommon - IsExternal: no
OverallHeight: 2.545 m; OverallWidth: 1.02 m
Pset_DoorCommon - Reference: FUS- Porta Fusta- marc ocult- 90x250,5 cm
Pset_QuantityTakeOff - Reference: FUS- Porta Fusta- marc ocult- 90x250,5 cm
Name (FUS- Porta Fusta- marc ocult- obertura corredera:FUS- Porta Fusta- marc ocult- 90x250,5 cm:...) | Group
811527 | Grupo de modelo:Modul Banys (elementos excluidos):100597
811775 | Grupo de modelo:Modul Banys 2:100913

# IfcDoor: FUS- Porta Fusta- marc ocult- obertura exterior:FUS- Porta Fusta- marc ocult- 90x250,5 cm, FUS- Porta Fusta- marc ocult- obertura exterior:FUS- Porta Fusta- marc ocult- 90x250,5 cm:5089163
In: P0- Escola
Type - OperationType: SINGLE_SWING_LEFT; ParameterTakesPrecedence: no; Sizeable: no; Material: _Fusta massisa- T1- REV- PAV
Type - FUS- Porta Fusta- marc ocult- obertura exterior:FUS- Porta Fusta- marc ocult- 90x250,5 cm:5089163:1 - PanelOperation: SWINGING
Type - Pset_DoorCommon - IsExternal: no
OverallHeight: 2.545 m; OverallWidth: 1.02 m
Pset_DoorCommon - Reference: FUS- Porta Fusta- marc ocult- 90x250,5 cm
Pset_QuantityTakeOff - Reference: FUS- Porta Fusta- marc ocult- 90x250,5 cm

# IfcDoor: FUS- Porta Fusta- marc ocult- obertura exterior:FUS- Porta Fusta- marc ocult- 90x250,5 cm, FUS- Porta Fusta- marc ocult- obertura exterior:FUS- Porta Fusta- marc ocult- 90x250,5 cm:5093221
In: P0- Escola
Type - OperationType: SINGLE_SWING_RIGHT; ParameterTakesPrecedence: no; Sizeable: no; Material: _Fusta massisa- T1- REV- PAV
Type - FUS- Porta Fusta- marc ocult- obertura exterior:FUS- Porta Fusta- marc ocult- 90x250,5 cm:5093221:1 - PanelOperation: SWINGING
Type - Pset_DoorCommon - IsExternal: no
OverallHeight: 2.545 m; OverallWidth: 1.02 m
Pset_DoorCommon - Reference: FUS- Porta Fusta- marc ocult- 90x250,5 cm
Pset_QuantityTakeOff - Reference: FUS- Porta Fusta- marc ocult- 90x250,5 cm

# IfcDoor: FUS- Porta Fusta- marc ocult- obertura interior:FUS- Porta Fusta- marc ocult- 90x250,5 cm (2)
In: P0- Escola
Type - ParameterTakesPrecedence: no; Sizeable: no; Material: _Fusta massisa- T1
Type - Pset_DoorCommon - IsExternal: no
OverallHeight: 2.545 m; OverallWidth: 1.02 m
Pset_DoorCommon - Reference: FUS- Porta Fusta- marc ocult- 90x250,5 cm
Pset_QuantityTakeOff - Reference: FUS- Porta Fusta- marc ocult- 90x250,5 cm
Name (FUS- Porta Fusta- marc ocult- obertura interior:FUS- Porta Fusta- marc ocult- 90x250,5 cm:...) | Group
5402705 | Grupo de modelo:Modul Banys (elementos excluidos):100597
5403009 | Grupo de modelo:Modul Banys 2:100913

# IfcDoor: FUS- Porta Fusta- marc ocult- obertura interior:FUS- Porta Fusta- marc ocult- 90x250,5 cm (9)
In: P0- Escola
Type - ParameterTakesPrecedence: no; Sizeable: no; Material: _Fusta massisa- T1- REV- PAV
Type - Pset_DoorCommon - IsExternal: no
OverallHeight: 2.545 m; OverallWidth: 1.02 m
Pset_DoorCommon - Reference: FUS- Porta Fusta- marc ocult- 90x250,5 cm
Pset_QuantityTakeOff - Reference: FUS- Porta Fusta- marc ocult- 90x250,5 cm
Name (FUS- Porta Fusta- marc ocult- obertura interior:FUS- Porta Fusta- marc ocult- 90x250,5 cm:...)
777949
778104
778155
810852 | Group: Grupo de modelo:REV- MODUL Magatzem+ ascensor:101023
811238 | Group: Grupo de modelo:REV- MODUL Magatzem+ ascensor:101023
812424
5094717
5096547
5096606

# IfcDoor: FUS- Porta fusta- Corredera- 3 fulles:FUS- Porta fusta- Corredera- 3 fulles (3)
In: P0- Escola
Type - ParameterTakesPrecedence: no; Sizeable: no; Material: _Fusta massisa- T1
Type - Pset_DoorCommon - IsExternal: no
OverallHeight: 2.56 m; OverallWidth: 5.81517 m
Pset_DoorCommon - Reference: FUS- Porta fusta- Corredera- 3 fulles
Pset_QuantityTakeOff - Reference: FUS- Porta fusta- Corredera- 3 fulles
Name (FUS- Porta fusta- Corredera- 3 fulles:FUS- Porta fusta- Corredera- 3 fulles:...) | Group
5110538 | Grupo de modelo:Grup aula:4934097
6043367 | Grupo de modelo:Grup aula:4940566
6043380 | Grupo de modelo:Grup aula:4940822

# IfcDoor: MC- Alu- Conjunt doble porta- 70x60 cm- +15cm- obertura ext- amplada variable:MC- Alu- Conjunt doble porta- 70x60 cm- +15cm- obertura ext- amplada variable, MC- Alu- Conjunt doble porta- 70x60 cm- +15cm- obertura ext- amplada variable:MC- Alu- Conjunt doble porta- 70x60 cm- +15cm- obertura ext- amplada variable:5131476
In: P0- Escola
Type - OperationType: DOUBLE_DOOR_SINGLE_SWING; ParameterTakesPrecedence: no; Sizeable: no; Material: _Vidre, _Alumini- T1- Perfil
Type - MC- Alu- Conjunt doble porta- 70x60 cm- +15cm- obertura ext- amplada variable:MC- Alu- Conjunt doble porta- 70x60 cm- +15cm- obertura ext- amplada variable:5131476:1 - PanelOperation: SWINGING
Type - Pset_DoorCommon - IsExternal: no
OverallHeight: 2.4175 m; OverallWidth: 1.709 m
Pset_DoorCommon - Reference: MC- Alu- Conjunt doble porta- 70x60 cm- +15cm- obertura ext- amplada variable
Pset_QuantityTakeOff - Reference: MC- Alu- Conjunt doble porta- 70x60 cm- +15cm- obertura ext- amplada variable

# IfcDoor: MC- Alu- Conjunt doble porta- 70x60 cm- +15cm- obertura ext:MC- Alu- Conjunt doble porta- 70x60 cm- +15cm- obertura ext, MC- Alu- Conjunt doble porta- 70x60 cm- +15cm- obertura ext:MC- Alu- Conjunt doble porta- 70x60 cm- +15cm- obertura ext:4687989
In: PS1- Gimnàs
Type - OperationType: DOUBLE_DOOR_SINGLE_SWING; ParameterTakesPrecedence: no; Sizeable: no; Material: _Alumini- T1- Perfil, _Vidre
Type - MC- Alu- Conjunt doble porta- 70x60 cm- +15cm- obertura ext:MC- Alu- Conjunt doble porta- 70x60 cm- +15cm- obertura ext:4687989:1 - PanelOperation: SWINGING
Type - Pset_DoorCommon - IsExternal: no
OverallHeight: 2.5 m; OverallWidth: 2.32599 m
Pset_DoorCommon - Reference: MC- Alu- Conjunt doble porta- 70x60 cm- +15cm- obertura ext
Pset_QuantityTakeOff - Reference: MC- Alu- Conjunt doble porta- 70x60 cm- +15cm- obertura ext

# IfcDoor: MC- Alu- Conjunt doble porta- 70x60 cm- +15cm- obertura ext:MC- Alu- Conjunt doble porta- 70x60 cm- +15cm- obertura ext, MC- Alu- Conjunt doble porta- 70x60 cm- +15cm- obertura ext:MC- Alu- Conjunt doble porta- 70x60 cm- +15cm- obertura ext:4718936
In: PS1- Gimnàs
Type - OperationType: DOUBLE_DOOR_SINGLE_SWING; ParameterTakesPrecedence: no; Sizeable: no; Material: _Alumini- T1- Perfil, _Vidre
Type - MC- Alu- Conjunt doble porta- 70x60 cm- +15cm- obertura ext:MC- Alu- Conjunt doble porta- 70x60 cm- +15cm- obertura ext:4718936:1 - PanelOperation: SWINGING
Type - Pset_DoorCommon - IsExternal: no
OverallHeight: 2.5 m; OverallWidth: 1.76786 m
Pset_DoorCommon - Reference: MC- Alu- Conjunt doble porta- 70x60 cm- +15cm- obertura ext
Pset_QuantityTakeOff - Reference: MC- Alu- Conjunt doble porta- 70x60 cm- +15cm- obertura ext

# IfcDoor: MC- Alu- Conjunt doble porta- 70x60 cm- +15cm- obertura ext:MC- Alu- Conjunt doble porta- 70x60 cm- +15cm- obertura ext, MC- Alu- Conjunt doble porta- 70x60 cm- +15cm- obertura ext:MC- Alu- Conjunt doble porta- 70x60 cm- +15cm- obertura ext:4719261
In: PS1- Gimnàs
Type - OperationType: DOUBLE_DOOR_SINGLE_SWING; ParameterTakesPrecedence: no; Sizeable: no; Material: _Alumini- T1- Perfil, _Vidre
Type - MC- Alu- Conjunt doble porta- 70x60 cm- +15cm- obertura ext:MC- Alu- Conjunt doble porta- 70x60 cm- +15cm- obertura ext:4719261:1 - PanelOperation: SWINGING
Type - Pset_DoorCommon - IsExternal: no
OverallHeight: 2.5 m; OverallWidth: 1.87989 m
Pset_DoorCommon - Reference: MC- Alu- Conjunt doble porta- 70x60 cm- +15cm- obertura ext
Pset_QuantityTakeOff - Reference: MC- Alu- Conjunt doble porta- 70x60 cm- +15cm- obertura ext

# IfcDoor: MC- Alu- Conjunt doble porta- 70x60 cm- +15cm- obertura ext:MC- Alu- Conjunt doble porta- 70x60 cm- +15cm- obertura ext, MC- Alu- Conjunt doble porta- 70x60 cm- +15cm- obertura ext:MC- Alu- Conjunt doble porta- 70x60 cm- +15cm- obertura ext:4719442
In: PS1- Gimnàs
Type - OperationType: DOUBLE_DOOR_SINGLE_SWING; ParameterTakesPrecedence: no; Sizeable: no; Material: _Alumini- T1- Perfil, _Vidre
Type - MC- Alu- Conjunt doble porta- 70x60 cm- +15cm- obertura ext:MC- Alu- Conjunt doble porta- 70x60 cm- +15cm- obertura ext:4719442:1 - PanelOperation: SWINGING
Type - Pset_DoorCommon - IsExternal: no
OverallHeight: 2.5 m; OverallWidth: 1.882 m
Pset_DoorCommon - Reference: MC- Alu- Conjunt doble porta- 70x60 cm- +15cm- obertura ext
Pset_QuantityTakeOff - Reference: MC- Alu- Conjunt doble porta- 70x60 cm- +15cm- obertura ext

# IfcDoor: MC- Alu- Conjunt doble porta- 70x60 cm- +15cm- obertura int:MC- Alu- Conjunt doble porta- 70x60 cm- +15cm- obertura int (2)
In: P0- Escola
Type - ParameterTakesPrecedence: no; Sizeable: no; Material: _Alumini- T1- Perfil, _Vidre
Type - Pset_DoorCommon - IsExternal: no
OverallHeight: 2.5843 m; OverallWidth: 2.1315 m
Pset_DoorCommon - Reference: MC- Alu- Conjunt doble porta- 70x60 cm- +15cm- obertura int
Pset_QuantityTakeOff - Reference: MC- Alu- Conjunt doble porta- 70x60 cm- +15cm- obertura int
Name (MC- Alu- Conjunt doble porta- 70x60 cm- +15cm- obertura int:MC- Alu- Conjunt doble porta- 70x60 cm- +15cm- obertura int:...)
4810602
4889903

# IfcDoor: MC- Alu- Conjunt doble porta- 70x60 cm- opaca- obertura ext:MC- Alu- Conjunt doble porta- 70x60 cm- opaca- obertura ext, MC- Alu- Conjunt doble porta- 70x60 cm- opaca- obertura ext:MC- Alu- Conjunt doble porta- 70x60 cm- opaca- obertura ext:5323811
In: PS1- Vestuari
Type - OperationType: DOUBLE_DOOR_SINGLE_SWING; ParameterTakesPrecedence: no; Sizeable: no; Material: _Alumini- T1- Perfil
Type - MC- Alu- Conjunt doble porta- 70x60 cm- opaca- obertura ext:MC- Alu- Conjunt doble porta- 70x60 cm- opaca- obertura ext:5323811:1 - PanelOperation: SWINGING
Type - Pset_DoorCommon - IsExternal: no
OverallHeight: 2.22994 m; OverallWidth: 1.9 m
Pset_DoorCommon - Reference: MC- Alu- Conjunt doble porta- 70x60 cm- opaca- obertura ext
Pset_QuantityTakeOff - Reference: MC- Alu- Conjunt doble porta- 70x60 cm- opaca- obertura ext

# IfcDoor: MC- Alu- Conjunt porta- 70x60 cm- +15cm- obertura int:MC- Alu- Conjunt porta- 70x60 cm- +15cm- obertura int (22)
In: P0- Escola
Type - ParameterTakesPrecedence: no; Sizeable: no; Material: _Alumini- T1- Perfil, _Vidre
Type - Pset_DoorCommon - IsExternal: no
Pset_DoorCommon - Reference: MC- Alu- Conjunt porta- 70x60 cm- +15cm- obertura int
Pset_QuantityTakeOff - Reference: MC- Alu- Conjunt porta- 70x60 cm- +15cm- obertura int
Group: Grupo de modelo:Fa-:4013115
Name (MC- Alu- Conjunt porta- 70x60 cm- +15cm- obertura int:MC- Alu- Conjunt porta- 70x60 cm- +15cm- obertura int:...) | OverallHeight (m) | OverallWidth (m)
2564642 | 2.46375 | 0.97
2564648 | 2.45145 | 0.97
2564680 | 2.46375 | 0.97
2564690 | 2.45145 | 0.97
2564720 | 2.46375 | 0.97
2564730 | 2.45145 | 0.97
6022584 | 2.48375 | 0.97
4451385 | 2.48375 | 0.97
3336815 | 2.48375 | 0.97
4011779 | 2.47125 | 0.9435
4820833 | 2.48375 | 0.97
4821425 | 2.47145 | 0.97
4825876 | 2.47125 | 1.1985
4935210 | 2.47125 | 0.9435
4935619 | 2.47125 | 0.9435
4943369 | 2.47125 | 0.9435
6029514 | 2.48375 | 0.97
6029317 | 2.48375 | 0.97
6029303 | 2.48375 | 0.97
6029730 | 2.48375 | 0.97
6029641 | 2.48375 | 0.97
6029627 | 2.48375 | 0.97

# IfcDoor: MC- Alu- Conjunt porta- 70x60 cm- +15cm:MC- Alu- Conjunt porta- 70x60 cm- +15cm, MC- Alu- Conjunt porta- 70x60 cm- +15cm:MC- Alu- Conjunt porta- 70x60 cm- +15cm:4899971
In: P0- Escola
Type - OperationType: SINGLE_SWING_LEFT; ParameterTakesPrecedence: no; Sizeable: no; Material: _Vidre, _Alumini- T1- Perfil
Type - MC- Alu- Conjunt porta- 70x60 cm- +15cm:MC- Alu- Conjunt porta- 70x60 cm- +15cm:4899971:1 - PanelOperation: SWINGING
Type - Pset_DoorCommon - IsExternal: no
OverallHeight: 2.4175 m; OverallWidth: 0.879998 m
Pset_DoorCommon - Reference: MC- Alu- Conjunt porta- 70x60 cm- +15cm
Pset_QuantityTakeOff - Reference: MC- Alu- Conjunt porta- 70x60 cm- +15cm

# IfcDoor: MC- Alu- Conjunt porta- 70x60 cm- +15cm:MC- Alu- Conjunt porta- 70x60 cm- +15cm (2)
In: P0- Escola
Type - OperationType: SINGLE_SWING_RIGHT; ParameterTakesPrecedence: no; Sizeable: no; Material: _Alumini- T1- Perfil, _Vidre
Type - MC- Alu- Conjunt porta- 70x60 cm- +15cm:MC- Alu- Conjunt porta- 70x60 cm- +15cm:4469028:1 - PanelOperation: SWINGING
Type - Pset_DoorCommon - IsExternal: no
OverallHeight: 2.48375 m; OverallWidth: 0.969948 m; Group: Grupo de modelo:Fa-:4013115
Pset_DoorCommon - Reference: MC- Alu- Conjunt porta- 70x60 cm- +15cm
Pset_QuantityTakeOff - Reference: MC- Alu- Conjunt porta- 70x60 cm- +15cm
Name (MC- Alu- Conjunt porta- 70x60 cm- +15cm:MC- Alu- Conjunt porta- 70x60 cm- +15cm:...)
4469028
6029385

# IfcDoor: MC- Alu- Conjunt porta- 70x60 cm- +15cm:MC- Alu- Conjunt porta- 70x60 cm- +15cm, MC- Alu- Conjunt porta- 70x60 cm- +15cm:MC- Alu- Conjunt porta- 70x60 cm- +15cm:4943442
In: P0- Escola
Type - OperationType: SINGLE_SWING_RIGHT; ParameterTakesPrecedence: no; Sizeable: no; Material: _Alumini- T1- Perfil, _Vidre
Type - MC- Alu- Conjunt porta- 70x60 cm- +15cm:MC- Alu- Conjunt porta- 70x60 cm- +15cm:4943442:1 - PanelOperation: SWINGING
Type - Pset_DoorCommon - IsExternal: no
OverallHeight: 2.48375 m; OverallWidth: 0.969948 m; Group: Grupo de modelo:Fa-:4013115
Pset_DoorCommon - Reference: MC- Alu- Conjunt porta- 70x60 cm- +15cm
Pset_QuantityTakeOff - Reference: MC- Alu- Conjunt porta- 70x60 cm- +15cm

# IfcDoor: MC- Alu- Conjunt porta- 70x60 cm- opacat:MC- Alu- Conjunt porta- 70x60 cm- opacat (6)
In: PS1- Vestuari
Type - ParameterTakesPrecedence: no; Sizeable: no; Material: _Alumini- T1- Perfil
Type - Pset_DoorCommon - IsExternal: no
OverallHeight: 2.20994 m
Pset_DoorCommon - Reference: MC- Alu- Conjunt porta- 70x60 cm- opacat
Pset_QuantityTakeOff - Reference: MC- Alu- Conjunt porta- 70x60 cm- opacat
Name (MC- Alu- Conjunt porta- 70x60 cm- opacat:MC- Alu- Conjunt porta- 70x60 cm- opacat:...) | OverallWidth (m)
102314 | 0.99755
102320 | 0.99755
102330 | 0.907
102336 | 0.876
102342 | 0.979
5323962 | 0.97

# IfcDoor: MC- Alu- Remats panell opac sostre:MC- Alu- Remats panell opac sostre, MC- Alu- Remats panell opac sostre:MC- Alu- Remats panell opac sostre:4717619
In: PS1- Vestuari
Type - ParameterTakesPrecedence: no; Sizeable: no; Material: _Aillament, _Alumini- T1- Perfil
Type - Pset_DoorCommon - IsExternal: no
OverallHeight: 2.71478 m; OverallWidth: 6.446 m
Pset_DoorCommon - Reference: MC- Alu- Remats panell opac sostre
Pset_QuantityTakeOff - Reference: MC- Alu- Remats panell opac sostre

# IfcDoor: MC- Alu- Remats panell opac:MC- Alu- Remats panell opac (2)
In: PS1- Gimnàs
Type - ParameterTakesPrecedence: no; Sizeable: no; Material: _Aillament, _Alumini- T1- Perfil
Type - Pset_DoorCommon - IsExternal: no
OverallWidth: 0.09 m
Pset_DoorCommon - Reference: MC- Alu- Remats panell opac
Pset_QuantityTakeOff - Reference: MC- Alu- Remats panell opac
Name (MC- Alu- Remats panell opac:MC- Alu- Remats panell opac:...) | OverallHeight (m)
4712601 | 5.03
4718145 | 3.01

# IfcDoor: MC- Alu- panell especific cuina:MC- Alu- panell especific cuina, MC- Alu- panell especific cuina:MC- Alu- panell especific cuina:4825852
In: P0- Escola
Type - ParameterTakesPrecedence: no; Sizeable: no; Material: _Fusta massisa- T1, _Aillament, _Alumini- T1- Perfil
Type - Pset_DoorCommon - IsExternal: no
OverallHeight: 2.47125 m; OverallWidth: 0.7795 m; Group: Grupo de modelo:Fa-:4013115
Pset_DoorCommon - IsExternal: yes; Reference: MC- Alu- panell especific cuina
Pset_QuantityTakeOff - Reference: MC- Alu- panell especific cuina

# IfcDoor: MC- Alu- panell especific xapa:MC- Alu- panell especific xapa (38)
Type - ParameterTakesPrecedence: no; Sizeable: no; Material: _Alumini- T1- Perfil, _Aillament
Type - Pset_DoorCommon - IsExternal: no
Pset_DoorCommon - Reference: MC- Alu- panell especific xapa
Pset_QuantityTakeOff - Reference: MC- Alu- panell especific xapa
Name (MC- Alu- panell especific xapa:MC- Alu- panell especific xapa:...) | In | OverallHeight (m) | OverallWidth (m) | Group
102268 | PS1- Vestuari | 1.5475 | 0.306 | Pset_DoorCommon - IsExternal: yes
102223 | PS1- Vestuari | 1.5475 | 0.3 | Pset_DoorCommon - IsExternal: yes
102208 | PS1- Vestuari | 1.5475 | 0.14 | Pset_DoorCommon - IsExternal: yes
5318209 | PS1- Vestuari | 1.5475 | 0.3 | Pset_DoorCommon - IsExternal: yes
6034516 | P0- Escola | 2.45145 | 0.345417 | Grupo de modelo:Fa-:4013115
6034517 | P0- Escola | 2.45145 | 0.435 | Grupo de modelo:Fa-:4013115
6034518 | P0- Escola | 2.45145 | 0.38285 | Grupo de modelo:Fa-:4013115
5786645 | P0- Escola | 2.47145 | 0.324126 | Grupo de modelo:Fa-:4013115
5786328 | P0- Escola | 2.47145 | 0.47695 | Grupo de modelo:Fa-:4013115
4510529 | P0- Escola | 2.47125 | 0.253 | Grupo de modelo:Fa-:4013115
4809764 | P0- Escola | 0.6 | 0.15
4810607 | P0- Escola | 0.6 | 0.15
5784900 | P0- Escola | 2.47145 | 0.350532 | Grupo de modelo:Fa-:4013115
5784904 | P0- Escola | 2.47145 | 0.328333 | Grupo de modelo:Fa-:4013115
5784908 | P0- Escola | 2.47145 | 0.318333 | Grupo de modelo:Fa-:4013115
5785789 | P0- Escola | 2.47145 | 0.3735 | Grupo de modelo:Fa-:4013115
5784915 | P0- Escola | 2.47145 | 0.3465 | Grupo de modelo:Fa-:4013115
4816953 | P0- Escola | 2.47125 | 0.253 | Grupo de modelo:Fa-:4013115
4820851 | P0- Escola | 2.47145 | 0.97 | Grupo de modelo:Fa-:4013115
4820773 | P0- Escola | 2.47145 | 0.97 | Grupo de modelo:Fa-:4013115
4820778 | P0- Escola | 2.47145 | 0.97 | Grupo de modelo:Fa-:4013115
4820783 | P0- Escola | 2.47145 | 0.97 | Grupo de modelo:Fa-:4013115
4820838 | P0- Escola | 1.9227 | 0.97 | Grupo de modelo:Fa-:4013115
4820793 | P0- Escola | 1.9227 | 0.97 | Grupo de modelo:Fa-:4013115
4820798 | P0- Escola | 1.9227 | 0.97 | Grupo de modelo:Fa-:4013115
4820803 | P0- Escola | 1.9227 | 0.97 | Grupo de modelo:Fa-:4013115
4821627 | P0- Escola | 2.47145 | 0.972796 | Grupo de modelo:Fa-:4013115
4898267 | P0- Escola | 1.3 | 1.141
4898919 | P0- Escola | 1.3 | 1.102
4898968 | P0- Escola | 1.3 | 0.607651
6042351 | P0- Escola | 1.0875 | 0.607651
4900862 | P0- Escola | 2.4175 | 0.579945
4935324 | P0- Escola | 2.47125 | 0.253 | Grupo de modelo:Fa-:4013115
4935733 | P0- Escola | 2.47125 | 0.253 | Grupo de modelo:Fa-:4013115
6029441 | P0- Escola | 2.47145 | 0.324126 | Grupo de modelo:Fa-:4013115
6029438 | P0- Escola | 2.47145 | 0.47695 | Grupo de modelo:Fa-:4013115
6029693 | P0- Escola | 2.47145 | 0.324126 | Grupo de modelo:Fa-:4013115
6029690 | P0- Escola | 2.47145 | 0.47695 | Grupo de modelo:Fa-:4013115

# IfcDoor: MC- Alu- panell especific:MC- Alu- panell especific (4)
In: P0- Escola
Type - ParameterTakesPrecedence: no; Sizeable: no; Material: _Fusta massisa- T1, _Aillament, _Alumini- T1- Perfil
Type - Pset_DoorCommon - IsExternal: no
OverallHeight: 2.47125 m; OverallWidth: 0.7385 m; Group: Grupo de modelo:Fa-:4013115
Pset_DoorCommon - Reference: MC- Alu- panell especific
Pset_QuantityTakeOff - Reference: MC- Alu- panell especific
Name (MC- Alu- panell especific:MC- Alu- panell especific:...)
4009179 | Pset_DoorCommon - IsExternal: yes
4935186
4935595
4943345

# IfcDoor: MC- Fusta- Finestra ventilacio interior- Enva:MC- Fusta- Finestra ventilacio interior- Enva (3)
In: P0- Escola
Type - ParameterTakesPrecedence: no; Sizeable: no; Material: _Fusta massisa- T1- REV- PAV, _Aillament
Type - Pset_DoorCommon - IsExternal: no
OverallHeight: 2.505 m; OverallWidth: 0.94 m
Pset_DoorCommon - Reference: MC- Fusta- Finestra ventilacio interior- Enva
Pset_QuantityTakeOff - Reference: MC- Fusta- Finestra ventilacio interior- Enva
Name (MC- Fusta- Finestra ventilacio interior- Enva:MC- Fusta- Finestra ventilacio interior- Enva:...) | Group
462905 | Grupo de modelo:Grup aula:4934097 | Pset_DoorCommon - IsExternal: yes
4940513 | Grupo de modelo:Grup aula:4940566
4940769 | Grupo de modelo:Grup aula:4940822

# IfcDoor: MC- Fusta- conjunt porta:MC- Fusta- conjunt Porta aules (21)
In: P0- Escola
Type - ParameterTakesPrecedence: no; Sizeable: no; Material: _Fusta massisa- T1, _Vidre
Type - Pset_DoorCommon - IsExternal: no
Pset_DoorCommon - Reference: MC- Fusta- conjunt Porta aules
Pset_QuantityTakeOff - Reference: MC- Fusta- conjunt Porta aules
Name (MC- Fusta- conjunt porta:MC- Fusta- conjunt Porta aules:...) | OverallHeight (m) | OverallWidth (m)
211474 | 2.52 | 0.9425
364837 | 2.505 | 0.94
365275 | 2.505 | 0.94
365713 | 2.505 | 0.94
361710 | 2.505 | 0.94
361880 | 2.505 | 0.94
362007 | 2.505 | 0.94
362091 | 2.505 | 0.94
362213 | 2.505 | 0.94
369911 | 2.505 | 0.942501
462909 | 2.505 | 0.94 | Group: Grupo de modelo:Grup aula:4934097
462897 | 2.52 | 0.94 | Group: Grupo de modelo:Grup aula:4934097
462865 | 2.505 | 0.94 | Group: Grupo de modelo:Grup aula:4934097
4902320 | 2.47726 | 1.01
4940517 | 2.505 | 0.94 | Group: Grupo de modelo:Grup aula:4940566
4940505 | 2.52 | 0.94 | Group: Grupo de modelo:Grup aula:4940566
4940473 | 2.505 | 0.94 | Group: Grupo de modelo:Grup aula:4940566
4940773 | 2.505 | 0.94 | Group: Grupo de modelo:Grup aula:4940822
4940761 | 2.52 | 0.94 | Group: Grupo de modelo:Grup aula:4940822
4940729 | 2.505 | 0.94 | Group: Grupo de modelo:Grup aula:4940822
5092652 | 2.52 | 0.97

# IfcDoor: Ser Ext- Porta i Fix- Barana:Ser Ext- Porta i Fix- Barana, Ser Ext- Porta i Fix- Barana:Ser Ext- Porta i Fix- Barana:5899559
In: P0- Escola
Type - ParameterTakesPrecedence: no; Sizeable: no; Material: <Unnamed>
Type - Pset_DoorCommon - IsExternal: no
OverallHeight: 2.6 m; OverallWidth: 2.73 m
Pset_DoorCommon - Reference: Ser Ext- Porta i Fix- Barana
Pset_QuantityTakeOff - Reference: Ser Ext- Porta i Fix- Barana

# IfcFlowSegment: Canalón:COB- Remat xapa coberta- Mur Installacions:5417239 (13)
In: PC- Coberta STR
Type - ElementType: Canalón:COB- Remat xapa coberta- Mur Installacions:5417239; PredefinedType: GUTTER
Pset_DistributionFlowElementCommon - Reference: COB- Remat xapa coberta- Mur Installacions; sets with these values: 2
Pset_PipeSegmentTypeGutter - Slope: 3.97236 deg
Name (Canalón:COB- Remat xapa coberta- Mur Installacions:...) | Group
5416826 | Grupo de modelo:BADALOT 1 (elementos excluidos):5302593
5418225 | Grupo de modelo:BADALOT 1 (elementos excluidos):5302593 | Pset_FlowSegmentDuctSegment - Length: 2.687 m; sets with these values: 2
5419155 | Grupo de modelo:BADALOT 2:5309104
5419159 | Grupo de modelo:BADALOT 2:5309104 | Pset_FlowSegmentDuctSegment - Length: 2.687 m; sets with these values: 2
5419526 | Grupo de modelo:BADALOT 2:5309452
5419529 | Grupo de modelo:BADALOT 2:5309452 | Pset_FlowSegmentDuctSegment - Length: 2.687 m; sets with these values: 2
5419542 | Grupo de modelo:BADALOT 2:5309638
5419545 | Grupo de modelo:BADALOT 2:5309638 | Pset_FlowSegmentDuctSegment - Length: 2.687 m; sets with these values: 2
5423096 | Grupo de modelo:BADALOT 2:5309104
5423227 | Grupo de modelo:BADALOT 2:5309452
5423233 | Grupo de modelo:BADALOT 2:5309638
5425203 | Grupo de modelo:BADALOT 3:5425172
5425208 | Grupo de modelo:BADALOT 3:5425172 | Pset_FlowSegmentDuctSegment - Length: 2.687 m; sets with these values: 2

# IfcFlowSegment: Canalón:COB- Remat xapa coberta- Remats 15 cm:5423606 (2)
In: PC- Coberta STR
Type - ElementType: Canalón:COB- Remat xapa coberta- Remats 15 cm:5423606; PredefinedType: GUTTER
Pset_DistributionFlowElementCommon - Reference: COB- Remat xapa coberta- Remats 15 cm; sets with these values: 2
Pset_PipeSegmentTypeGutter - Slope: 3.97236 deg
Name (Canalón:COB- Remat xapa coberta- Remats 15 cm:...) | Group
5424867 | Grupo de modelo:BADALOT 1 (elementos excluidos):5302593
5425236 | Grupo de modelo:BADALOT 3:5425172

# IfcFlowSegment: Canalón:COB- Remat xapa coberta:5414553 (2)
In: PC- Coberta STR
Type - ElementType: Canalón:COB- Remat xapa coberta:5414553; PredefinedType: GUTTER
Pset_DistributionFlowElementCommon - Reference: COB- Remat xapa coberta; sets with these values: 2
Pset_PipeSegmentTypeGutter - Slope: 3.97236 deg
Group: Grupo de modelo:REMATS COBERTA:5414998
Name (Canalón:COB- Remat xapa coberta:...)
5415017
6095239

# IfcFurnishingElement: Mobiliario 1:Mobiliario 3, Mobiliario 1:Mobiliario 3:4940423
In: P0- Escola
Type - Material: _Fusta massisa- T1
Pset_QuantityTakeOff - Reference: Mobiliario 3

# IfcFurnishingElement: Mobiliario 3:Mobiliario 3, Mobiliario 3:Mobiliario 3:462679
In: P0- Escola
Type - Material: _Fusta massisa- T1
Pset_QuantityTakeOff - Reference: Mobiliario 3

# IfcFurnishingElement: Mobiliario 4:Mobiliario 3, Mobiliario 4:Mobiliario 3:4940679
In: P0- Escola
Type - Material: _Fusta massisa- T1
Pset_QuantityTakeOff - Reference: Mobiliario 3

# IfcFurnishingElement: Mobiliario 6:Mobiliario 3, Mobiliario 6:Mobiliario 3:5096007
In: P0- Escola
Type - Material: _Fusta massisa- T1
Pset_QuantityTakeOff - Reference: Mobiliario 3

# IfcFurnishingElement: Prestatge banys:Prestatge banys (9)
In: P0- Escola
Type - Material: _silestone
Pset_QuantityTakeOff - Reference: Prestatge banys
Name (Prestatge banys:Prestatge banys:...)
2328911 | Group: Grupo de modelo:BANY PRESTATGE (elementos excluidos):2334870
2335965 | Group: Grupo de modelo:BANY PRESTATGE (elementos excluidos):2334870
2337257 | Group: Grupo de modelo:BANY PRESTATGE (elementos excluidos):2334870
5411354
5411357
5411359
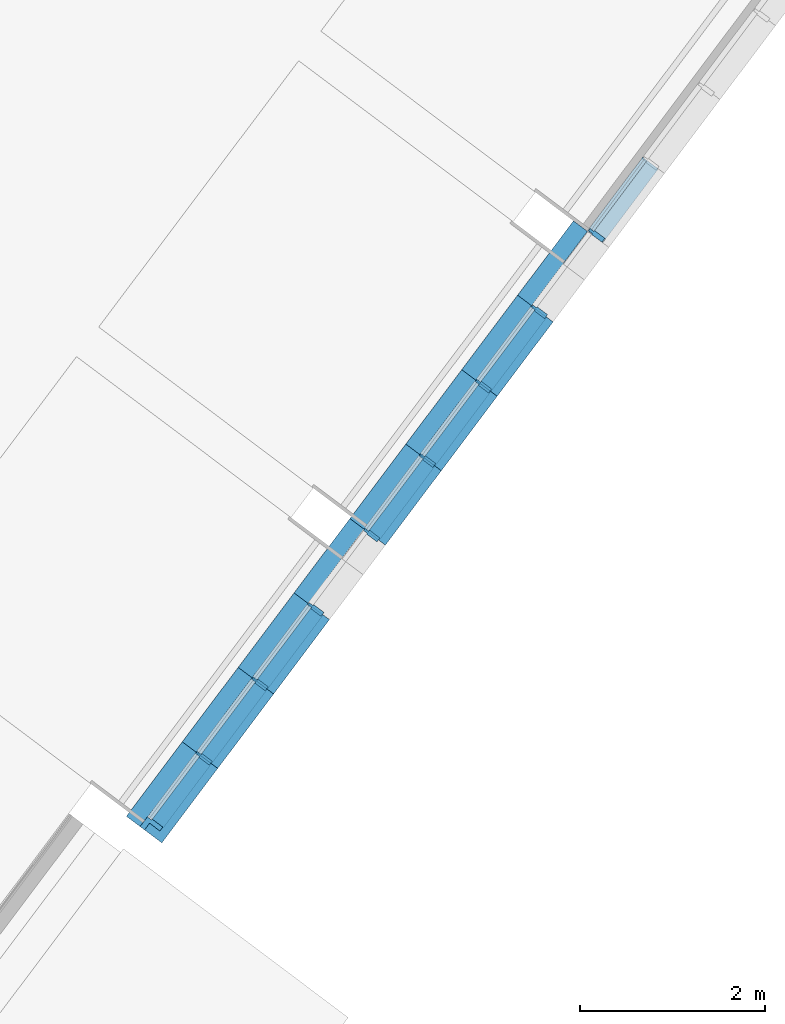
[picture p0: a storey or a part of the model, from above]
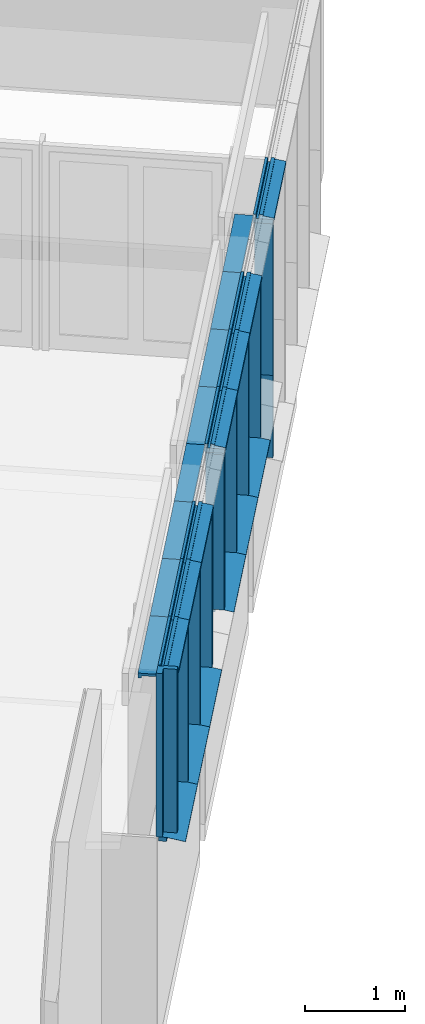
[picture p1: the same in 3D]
Properties of the parts of a building model (IFC2X3), part 2 of 6

# IfcFurnishingElement: Prestatge banys:Prestatge banys (9)
Name (Prestatge banys:Prestatge banys:...)
5411597
5411600
5411602

# IfcFurnishingElement: SIMPLE HANDWASH:PICA- (3)
In: P0- Escola
Type - Material: <Unnamed>
Pset_QuantityTakeOff - Reference: PICA-
Name (SIMPLE HANDWASH:PICA-:...)
2484678 | Group: Grupo de modelo:BANY PRESTATGE (elementos excluidos):2334870
5411362
5411605

# IfcFurnishingElement: prestatge fusta remat:prestatge fusta remat (2)
In: P0- Escola
Type - Material: _Fusta massisa- T1
Pset_QuantityTakeOff - Reference: prestatge fusta remat
Name (prestatge fusta remat:prestatge fusta remat:...)
4896476
4897498

# IfcMember: Montante rectangular:MC- Alu- 140x52,5 cm- Fa patis- Cantonada (25)
In: P0- Escola
Type - PredefinedType: MULLION; Material: _Alumini- T1- Perfil
Type - Pset_MemberCommon - IsExternal: no
Pset_MemberCommon - Reference: MC- Alu- 140x52,5 cm- Fa patis- Cantonada
Pset_QuantityTakeOff - Reference: MC- Alu- 140x52,5 cm- Fa patis- Cantonada
Group: Grupo de modelo:Fa-:4013115
Name (Montante rectangular:MC- Alu- 140x52,5 cm- Fa patis- Cantonada:...) | Span (m)
5786599 | 0.84 | Pset_MemberCommon - IsExternal: yes
5786600 | 0.7975 | Pset_MemberCommon - IsExternal: yes
6018079 | 0.875 | Pset_MemberCommon - IsExternal: yes
5792271 | 0.84
5792272 | 0.7975
6028728 | 0.875
5785500 | 0.84
5785501 | 0.7975
6008277 | 0.875
4820770 | 0.5375
4824552 | 1.975
5791461 | 0.84
5791462 | 0.7975
6032875 | 0.875
5793219 | 1
5793220 | 1.5125
6029439 | 0.84
6029440 | 0.7975
6029498 | 0.875
6029476 | 0.84
6029477 | 0.7975
6029548 | 0.875
6029691 | 0.84
6029692 | 0.7975
6029714 | 0.875

# IfcMember: Montante rectangular:MC- Alu- 140x52,5 cm- Fa patis- Centre (533)
Type - PredefinedType: MULLION; Material: _Alumini- T1- Perfil
Type - Pset_MemberCommon - IsExternal: no
Pset_MemberCommon - Reference: MC- Alu- 140x52,5 cm- Fa patis- Centre
Pset_QuantityTakeOff - Reference: MC- Alu- 140x52,5 cm- Fa patis- Centre
Name (Montante rectangular:MC- Alu- 140x52,5 cm- Fa patis- Centre:...) | In | Span (m) | Group
2564662 | P0- Escola | 0.84 | Grupo de modelo:Fa-:4013115 | Pset_MemberCommon - IsExternal: yes
2564663 | P0- Escola | 0.84 | Grupo de modelo:Fa-:4013115 | Pset_MemberCommon - IsExternal: yes
2564664 | P0- Escola | 0.785 | Grupo de modelo:Fa-:4013115 | Pset_MemberCommon - IsExternal: yes
2564665 | P0- Escola | 0.785 | Grupo de modelo:Fa-:4013115 | Pset_MemberCommon - IsExternal: yes
2564666 | P0- Escola | 0.785 | Grupo de modelo:Fa-:4013115 | Pset_MemberCommon - IsExternal: yes
2564667 | P0- Escola | 0.785 | Grupo de modelo:Fa-:4013115 | Pset_MemberCommon - IsExternal: yes
2564668 | P0- Escola | 0.785 | Grupo de modelo:Fa-:4013115 | Pset_MemberCommon - IsExternal: yes
2564677 | P0- Escola | 0.7775 | Grupo de modelo:Fa-:4013115 | Pset_MemberCommon - IsExternal: yes
2564678 | P0- Escola | 0.785 | Grupo de modelo:Fa-:4013115 | Pset_MemberCommon - IsExternal: yes
2564683 | P0- Escola | 0.84 | Grupo de modelo:Fa-:4013115 | Pset_MemberCommon - IsExternal: yes
2564688 | P0- Escola | 0.84 | Grupo de modelo:Fa-:4013115 | Pset_MemberCommon - IsExternal: yes
2564693 | P0- Escola | 0.785 | Grupo de modelo:Fa-:4013115 | Pset_MemberCommon - IsExternal: yes
2564698 | P0- Escola | 0.785 | Grupo de modelo:Fa-:4013115 | Pset_MemberCommon - IsExternal: yes
2564703 | P0- Escola | 0.785 | Grupo de modelo:Fa-:4013115 | Pset_MemberCommon - IsExternal: yes
2564708 | P0- Escola | 0.785 | Grupo de modelo:Fa-:4013115 | Pset_MemberCommon - IsExternal: yes
2564713 | P0- Escola | 0.785 | Grupo de modelo:Fa-:4013115 | Pset_MemberCommon - IsExternal: yes
2564718 | P0- Escola | 0.785 | Grupo de modelo:Fa-:4013115 | Pset_MemberCommon - IsExternal: yes
2564723 | P0- Escola | 0.84 | Grupo de modelo:Fa-:4013115 | Pset_MemberCommon - IsExternal: yes
2564728 | P0- Escola | 0.84 | Grupo de modelo:Fa-:4013115 | Pset_MemberCommon - IsExternal: yes
2564733 | P0- Escola | 0.785 | Grupo de modelo:Fa-:4013115 | Pset_MemberCommon - IsExternal: yes
2564738 | P0- Escola | 0.785 | Grupo de modelo:Fa-:4013115 | Pset_MemberCommon - IsExternal: yes
2564743 | P0- Escola | 0.785 | Grupo de modelo:Fa-:4013115 | Pset_MemberCommon - IsExternal: yes
2564748 | P0- Escola | 0.785 | Grupo de modelo:Fa-:4013115 | Pset_MemberCommon - IsExternal: yes
2564801 | P0- Escola | 0.785 | Grupo de modelo:Fa-:4013115 | Pset_MemberCommon - IsExternal: yes
2564808 | P0- Escola | 0.785 | Grupo de modelo:Fa-:4013115 | Pset_MemberCommon - IsExternal: yes
5780784 | P0- Escola | 0.83 | Grupo de modelo:Fa-:4013115 | Pset_MemberCommon - IsExternal: yes
5780785 | P0- Escola | 0.875 | Grupo de modelo:Fa-:4013115 | Pset_MemberCommon - IsExternal: yes
5780787 | P0- Escola | 0.7775 | Grupo de modelo:Fa-:4013115 | Pset_MemberCommon - IsExternal: yes
5780788 | P0- Escola | 0.7775 | Grupo de modelo:Fa-:4013115 | Pset_MemberCommon - IsExternal: yes
5780789 | P0- Escola | 0.7775 | Grupo de modelo:Fa-:4013115 | Pset_MemberCommon - IsExternal: yes
5780790 | P0- Escola | 0.7775 | Grupo de modelo:Fa-:4013115 | Pset_MemberCommon - IsExternal: yes
5780791 | P0- Escola | 0.7775 | Grupo de modelo:Fa-:4013115 | Pset_MemberCommon - IsExternal: yes
5780792 | P0- Escola | 0.7775 | Grupo de modelo:Fa-:4013115 | Pset_MemberCommon - IsExternal: yes
5780793 | P0- Escola | 0.7775 | Grupo de modelo:Fa-:4013115 | Pset_MemberCommon - IsExternal: yes
5780794 | P0- Escola | 0.7775 | Grupo de modelo:Fa-:4013115 | Pset_MemberCommon - IsExternal: yes
5780796 | P0- Escola | 0.7775 | Grupo de modelo:Fa-:4013115 | Pset_MemberCommon - IsExternal: yes
5780797 | P0- Escola | 0.7775 | Grupo de modelo:Fa-:4013115 | Pset_MemberCommon - IsExternal: yes
5780798 | P0- Escola | 0.7775 | Grupo de modelo:Fa-:4013115 | Pset_MemberCommon - IsExternal: yes
5780799 | P0- Escola | 0.7775 | Grupo de modelo:Fa-:4013115 | Pset_MemberCommon - IsExternal: yes
5780800 | P0- Escola | 0.7775 | Grupo de modelo:Fa-:4013115 | Pset_MemberCommon - IsExternal: yes
5780801 | P0- Escola | 0.7775 | Grupo de modelo:Fa-:4013115 | Pset_MemberCommon - IsExternal: yes
5780802 | P0- Escola | 0.7775 | Grupo de modelo:Fa-:4013115 | Pset_MemberCommon - IsExternal: yes
5780803 | P0- Escola | 0.7775 | Grupo de modelo:Fa-:4013115 | Pset_MemberCommon - IsExternal: yes
5780805 | P0- Escola | 0.7775 | Grupo de modelo:Fa-:4013115 | Pset_MemberCommon - IsExternal: yes
5780806 | P0- Escola | 0.7775 | Grupo de modelo:Fa-:4013115 | Pset_MemberCommon - IsExternal: yes
5780807 | P0- Escola | 0.7775 | Grupo de modelo:Fa-:4013115 | Pset_MemberCommon - IsExternal: yes
5780808 | P0- Escola | 0.7775 | Grupo de modelo:Fa-:4013115 | Pset_MemberCommon - IsExternal: yes
5780809 | P0- Escola | 0.7775 | Grupo de modelo:Fa-:4013115 | Pset_MemberCommon - IsExternal: yes
5780810 | P0- Escola | 0.7775 | Grupo de modelo:Fa-:4013115 | Pset_MemberCommon - IsExternal: yes
5780811 | P0- Escola | 0.7775 | Grupo de modelo:Fa-:4013115 | Pset_MemberCommon - IsExternal: yes
6034468 | P0- Escola | 0.875 | Grupo de modelo:Fa-:4013115 | Pset_MemberCommon - IsExternal: yes
6034469 | P0- Escola | 0.875 | Grupo de modelo:Fa-:4013115 | Pset_MemberCommon - IsExternal: yes
6034470 | P0- Escola | 0.875 | Grupo de modelo:Fa-:4013115 | Pset_MemberCommon - IsExternal: yes
6034471 | P0- Escola | 0.875 | Grupo de modelo:Fa-:4013115 | Pset_MemberCommon - IsExternal: yes
6034472 | P0- Escola | 0.875 | Grupo de modelo:Fa-:4013115 | Pset_MemberCommon - IsExternal: yes
6034473 | P0- Escola | 0.875 | Grupo de modelo:Fa-:4013115 | Pset_MemberCommon - IsExternal: yes
6034474 | P0- Escola | 0.875 | Grupo de modelo:Fa-:4013115 | Pset_MemberCommon - IsExternal: yes
6034475 | P0- Escola | 0.875 | Grupo de modelo:Fa-:4013115 | Pset_MemberCommon - IsExternal: yes
6034476 | P0- Escola | 0.875 | Grupo de modelo:Fa-:4013115 | Pset_MemberCommon - IsExternal: yes
6034477 | P0- Escola | 0.875 | Grupo de modelo:Fa-:4013115 | Pset_MemberCommon - IsExternal: yes
6034478 | P0- Escola | 0.875 | Grupo de modelo:Fa-:4013115 | Pset_MemberCommon - IsExternal: yes
6034479 | P0- Escola | 0.875 | Grupo de modelo:Fa-:4013115 | Pset_MemberCommon - IsExternal: yes
6034480 | P0- Escola | 0.875 | Grupo de modelo:Fa-:4013115 | Pset_MemberCommon - IsExternal: yes
6034481 | P0- Escola | 0.875 | Grupo de modelo:Fa-:4013115 | Pset_MemberCommon - IsExternal: yes
6034482 | P0- Escola | 0.875 | Grupo de modelo:Fa-:4013115 | Pset_MemberCommon - IsExternal: yes
6034483 | P0- Escola | 0.875 | Grupo de modelo:Fa-:4013115 | Pset_MemberCommon - IsExternal: yes
6034484 | P0- Escola | 0.875 | Grupo de modelo:Fa-:4013115 | Pset_MemberCommon - IsExternal: yes
6034485 | P0- Escola | 0.875 | Grupo de modelo:Fa-:4013115 | Pset_MemberCommon - IsExternal: yes
6034486 | P0- Escola | 0.875 | Grupo de modelo:Fa-:4013115 | Pset_MemberCommon - IsExternal: yes
6034487 | P0- Escola | 0.875 | Grupo de modelo:Fa-:4013115 | Pset_MemberCommon - IsExternal: yes
6034488 | P0- Escola | 0.875 | Grupo de modelo:Fa-:4013115 | Pset_MemberCommon - IsExternal: yes
6034489 | P0- Escola | 0.875 | Grupo de modelo:Fa-:4013115 | Pset_MemberCommon - IsExternal: yes
6034490 | P0- Escola | 0.875 | Grupo de modelo:Fa-:4013115 | Pset_MemberCommon - IsExternal: yes
6034491 | P0- Escola | 0.875 | Grupo de modelo:Fa-:4013115 | Pset_MemberCommon - IsExternal: yes
6034492 | P0- Escola | 0.84 | Grupo de modelo:Fa-:4013115 | Pset_MemberCommon - IsExternal: yes
3336761 | P0- Escola | 0.785 | Grupo de modelo:Fa-:4013115
3336768 | P0- Escola | 0.84 | Grupo de modelo:Fa-:4013115
3336773 | P0- Escola | 0.785 | Grupo de modelo:Fa-:4013115
3336778 | P0- Escola | 0.785 | Grupo de modelo:Fa-:4013115
3336783 | P0- Escola | 0.84 | Grupo de modelo:Fa-:4013115
3336788 | P0- Escola | 0.84 | Grupo de modelo:Fa-:4013115
3336793 | P0- Escola | 0.785 | Grupo de modelo:Fa-:4013115
3336798 | P0- Escola | 0.785 | Grupo de modelo:Fa-:4013115
3336803 | P0- Escola | 0.84 | Grupo de modelo:Fa-:4013115
3336808 | P0- Escola | 0.84 | Grupo de modelo:Fa-:4013115
3336813 | P0- Escola | 0.785 | Grupo de modelo:Fa-:4013115
3336818 | P0- Escola | 0.785 | Grupo de modelo:Fa-:4013115
3336823 | P0- Escola | 0.84 | Grupo de modelo:Fa-:4013115
3336828 | P0- Escola | 0.84 | Grupo de modelo:Fa-:4013115
4451396 | P0- Escola | 0.84 | Grupo de modelo:Fa-:4013115
4459702 | P0- Escola | 0.84 | Grupo de modelo:Fa-:4013115
5786230 | P0- Escola | 0.875 | Grupo de modelo:Fa-:4013115
5786232 | P0- Escola | 0.875 | Grupo de modelo:Fa-:4013115
5786233 | P0- Escola | 0.875 | Grupo de modelo:Fa-:4013115
5786234 | P0- Escola | 0.875 | Grupo de modelo:Fa-:4013115
5786236 | P0- Escola | 0.875 | Grupo de modelo:Fa-:4013115
5786237 | P0- Escola | 0.875 | Grupo de modelo:Fa-:4013115
5786238 | P0- Escola | 0.875 | Grupo de modelo:Fa-:4013115
5786239 | P0- Escola | 0.875 | Grupo de modelo:Fa-:4013115
5786240 | P0- Escola | 0.875 | Grupo de modelo:Fa-:4013115
5786241 | P0- Escola | 0.875 | Grupo de modelo:Fa-:4013115
5786242 | P0- Escola | 0.875 | Grupo de modelo:Fa-:4013115
5786243 | P0- Escola | 0.875 | Grupo de modelo:Fa-:4013115
5786244 | P0- Escola | 0.875 | Grupo de modelo:Fa-:4013115
5786245 | P0- Escola | 0.875 | Grupo de modelo:Fa-:4013115
5786246 | P0- Escola | 0.875 | Grupo de modelo:Fa-:4013115
5786247 | P0- Escola | 0.875 | Grupo de modelo:Fa-:4013115
6018078 | P0- Escola | 0.7975 | Grupo de modelo:Fa-:4013115
6018080 | P0- Escola | 0.7975 | Grupo de modelo:Fa-:4013115
6018081 | P0- Escola | 0.7975 | Grupo de modelo:Fa-:4013115
6018082 | P0- Escola | 0.7975 | Grupo de modelo:Fa-:4013115
6018084 | P0- Escola | 0.7975 | Grupo de modelo:Fa-:4013115
6018085 | P0- Escola | 0.7975 | Grupo de modelo:Fa-:4013115
6018086 | P0- Escola | 0.7975 | Grupo de modelo:Fa-:4013115
6018087 | P0- Escola | 0.7975 | Grupo de modelo:Fa-:4013115
6018088 | P0- Escola | 0.7975 | Grupo de modelo:Fa-:4013115
6018089 | P0- Escola | 0.7975 | Grupo de modelo:Fa-:4013115
6018090 | P0- Escola | 0.7975 | Grupo de modelo:Fa-:4013115
6018091 | P0- Escola | 0.7975 | Grupo de modelo:Fa-:4013115
6018092 | P0- Escola | 0.7975 | Grupo de modelo:Fa-:4013115
6018093 | P0- Escola | 0.7975 | Grupo de modelo:Fa-:4013115
6018094 | P0- Escola | 0.7975 | Grupo de modelo:Fa-:4013115
6018095 | P0- Escola | 0.7975 | Grupo de modelo:Fa-:4013115
4468969 | P0- Escola | 0.84 | Grupo de modelo:Fa-:4013115
4468976 | P0- Escola | 0.84 | Grupo de modelo:Fa-:4013115
4468981 | P0- Escola | 0.785 | Grupo de modelo:Fa-:4013115
4468986 | P0- Escola | 0.785 | Grupo de modelo:Fa-:4013115
4468991 | P0- Escola | 0.84 | Grupo de modelo:Fa-:4013115
4468996 | P0- Escola | 0.84 | Grupo de modelo:Fa-:4013115
4469001 | P0- Escola | 0.785 | Grupo de modelo:Fa-:4013115
4469006 | P0- Escola | 0.785 | Grupo de modelo:Fa-:4013115
4469011 | P0- Escola | 0.84 | Grupo de modelo:Fa-:4013115
4469016 | P0- Escola | 0.84 | Grupo de modelo:Fa-:4013115
4469021 | P0- Escola | 0.785 | Grupo de modelo:Fa-:4013115
4469026 | P0- Escola | 0.785 | Grupo de modelo:Fa-:4013115
4469036 | P0- Escola | 0.84 | Grupo de modelo:Fa-:4013115
4469041 | P0- Escola | 0.84 | Grupo de modelo:Fa-:4013115
4469046 | P0- Escola | 0.84 | Grupo de modelo:Fa-:4013115
5792077 | P0- Escola | 0.875 | Grupo de modelo:Fa-:4013115
5792080 | P0- Escola | 0.875 | Grupo de modelo:Fa-:4013115
5792081 | P0- Escola | 0.875 | Grupo de modelo:Fa-:4013115
5792082 | P0- Escola | 0.875 | Grupo de modelo:Fa-:4013115
5792083 | P0- Escola | 0.875 | Grupo de modelo:Fa-:4013115
5792084 | P0- Escola | 0.875 | Grupo de modelo:Fa-:4013115
5792085 | P0- Escola | 0.875 | Grupo de modelo:Fa-:4013115
5792086 | P0- Escola | 0.875 | Grupo de modelo:Fa-:4013115
5792087 | P0- Escola | 0.875 | Grupo de modelo:Fa-:4013115
5792088 | P0- Escola | 0.875 | Grupo de modelo:Fa-:4013115
5792089 | P0- Escola | 0.875 | Grupo de modelo:Fa-:4013115
5792090 | P0- Escola | 0.875 | Grupo de modelo:Fa-:4013115
5792091 | P0- Escola | 0.875 | Grupo de modelo:Fa-:4013115
5792092 | P0- Escola | 0.875 | Grupo de modelo:Fa-:4013115
5792093 | P0- Escola | 0.875 | Grupo de modelo:Fa-:4013115
5792189 | P0- Escola | 0.875 | Grupo de modelo:Fa-:4013115
5792190 | P0- Escola | 0.84 | Grupo de modelo:Fa-:4013115
6028712 | P0- Escola | 0.7975 | Grupo de modelo:Fa-:4013115
6028713 | P0- Escola | 0.7975 | Grupo de modelo:Fa-:4013115
6028714 | P0- Escola | 0.7975 | Grupo de modelo:Fa-:4013115
6028715 | P0- Escola | 0.7975 | Grupo de modelo:Fa-:4013115
6028716 | P0- Escola | 0.7975 | Grupo de modelo:Fa-:4013115
6028717 | P0- Escola | 0.7975 | Grupo de modelo:Fa-:4013115
6028718 | P0- Escola | 0.7975 | Grupo de modelo:Fa-:4013115
6028719 | P0- Escola | 0.7975 | Grupo de modelo:Fa-:4013115
6028720 | P0- Escola | 0.7975 | Grupo de modelo:Fa-:4013115
6028721 | P0- Escola | 0.7975 | Grupo de modelo:Fa-:4013115
6028722 | P0- Escola | 0.7975 | Grupo de modelo:Fa-:4013115
6028723 | P0- Escola | 0.7975 | Grupo de modelo:Fa-:4013115
6028724 | P0- Escola | 0.7975 | Grupo de modelo:Fa-:4013115
6028725 | P0- Escola | 0.7975 | Grupo de modelo:Fa-:4013115
6028726 | P0- Escola | 0.7975 | Grupo de modelo:Fa-:4013115
6028727 | P0- Escola | 0.7975 | Grupo de modelo:Fa-:4013115
4667151 | PS1- Gimnàs | 1.8915
4667152 | PS1- Gimnàs | 1.8915
4667153 | PS1- Gimnàs | 1.8915
4667154 | PS1- Gimnàs | 1.8915
4667155 | PS1- Gimnàs | 1.8915
4667156 | PS1- Gimnàs | 1.8915
4667157 | PS1- Gimnàs | 1.8915
4696978 | PS1- Gimnàs | 2.33125
4697187 | PS1- Gimnàs | 2.33125
4697263 | PS1- Gimnàs | 2.33125
4697345 | PS1- Gimnàs | 2.33125
4697421 | PS1- Gimnàs | 2.33125
4697956 | PS1- Gimnàs | 2.49145
4698031 | PS1- Gimnàs | 1.1685
4698032 | PS1- Gimnàs | 0.7745
4698033 | PS1- Gimnàs | 0.98
4698034 | PS1- Gimnàs | 0.98
4698035 | PS1- Gimnàs | 0.98
4698036 | PS1- Gimnàs | 0.98
4756199 | PS1- Gimnàs | 1.004
4763322 | PS1- Gimnàs | 1.004
4763955 | PS1- Gimnàs | 1.004
4764308 | PS1- Gimnàs | 1.004
4766220 | PS1- Gimnàs | 1.8475
4766226 | PS1- Gimnàs | 1.8475
4766227 | PS1- Gimnàs | 1.8475
4766228 | PS1- Gimnàs | 1.8475
4816833 | P0- Escola | 0.84 | Grupo de modelo:Fa-:4013115
4816840 | P0- Escola | 0.84 | Grupo de modelo:Fa-:4013115
4816845 | P0- Escola | 0.785 | Grupo de modelo:Fa-:4013115
4816850 | P0- Escola | 0.785 | Grupo de modelo:Fa-:4013115
4816855 | P0- Escola | 0.84 | Grupo de modelo:Fa-:4013115
4816860 | P0- Escola | 0.785 | Grupo de modelo:Fa-:4013115
4816865 | P0- Escola | 0.785 | Grupo de modelo:Fa-:4013115
4816870 | P0- Escola | 0.785 | Grupo de modelo:Fa-:4013115
4816875 | P0- Escola | 0.84 | Grupo de modelo:Fa-:4013115
4816880 | P0- Escola | 0.785 | Grupo de modelo:Fa-:4013115
4816885 | P0- Escola | 0.785 | Grupo de modelo:Fa-:4013115
4816890 | P0- Escola | 0.785 | Grupo de modelo:Fa-:4013115
4816895 | P0- Escola | 0.84 | Grupo de modelo:Fa-:4013115
4816900 | P0- Escola | 0.84 | Grupo de modelo:Fa-:4013115
4816905 | P0- Escola | 0.84 | Grupo de modelo:Fa-:4013115
4816910 | P0- Escola | 0.84 | Grupo de modelo:Fa-:4013115
4816915 | P0- Escola | 0.785 | Grupo de modelo:Fa-:4013115
5784723 | P0- Escola | 0.875 | Grupo de modelo:Fa-:4013115
5784725 | P0- Escola | 0.875 | Grupo de modelo:Fa-:4013115
5784726 | P0- Escola | 0.875 | Grupo de modelo:Fa-:4013115
5784728 | P0- Escola | 0.875 | Grupo de modelo:Fa-:4013115
5784729 | P0- Escola | 0.875 | Grupo de modelo:Fa-:4013115
5784730 | P0- Escola | 0.875 | Grupo de modelo:Fa-:4013115
5784731 | P0- Escola | 0.875 | Grupo de modelo:Fa-:4013115
5784732 | P0- Escola | 0.875 | Grupo de modelo:Fa-:4013115
5784734 | P0- Escola | 0.875 | Grupo de modelo:Fa-:4013115
5784735 | P0- Escola | 0.875 | Grupo de modelo:Fa-:4013115
5784736 | P0- Escola | 0.875 | Grupo de modelo:Fa-:4013115
5784738 | P0- Escola | 0.875 | Grupo de modelo:Fa-:4013115
5784740 | P0- Escola | 0.875 | Grupo de modelo:Fa-:4013115
5784741 | P0- Escola | 0.875 | Grupo de modelo:Fa-:4013115
5784742 | P0- Escola | 0.875 | Grupo de modelo:Fa-:4013115
5784743 | P0- Escola | 0.875 | Grupo de modelo:Fa-:4013115
5784744 | P0- Escola | 0.875 | Grupo de modelo:Fa-:4013115
6008276 | P0- Escola | 0.7975 | Grupo de modelo:Fa-:4013115
6008278 | P0- Escola | 0.7975 | Grupo de modelo:Fa-:4013115
6008279 | P0- Escola | 0.7975 | Grupo de modelo:Fa-:4013115
6008281 | P0- Escola | 0.7975 | Grupo de modelo:Fa-:4013115
6008282 | P0- Escola | 0.7975 | Grupo de modelo:Fa-:4013115
6008283 | P0- Escola | 0.7975 | Grupo de modelo:Fa-:4013115
6008284 | P0- Escola | 0.7975 | Grupo de modelo:Fa-:4013115
6008285 | P0- Escola | 0.7975 | Grupo de modelo:Fa-:4013115
6008287 | P0- Escola | 0.7975 | Grupo de modelo:Fa-:4013115
6008288 | P0- Escola | 0.7975 | Grupo de modelo:Fa-:4013115
6008289 | P0- Escola | 0.7975 | Grupo de modelo:Fa-:4013115
6008291 | P0- Escola | 0.7975 | Grupo de modelo:Fa-:4013115
6008293 | P0- Escola | 0.7975 | Grupo de modelo:Fa-:4013115
6008294 | P0- Escola | 0.7975 | Grupo de modelo:Fa-:4013115
6008295 | P0- Escola | 0.7975 | Grupo de modelo:Fa-:4013115
6008296 | P0- Escola | 0.7975 | Grupo de modelo:Fa-:4013115
6008297 | P0- Escola | 0.7975 | Grupo de modelo:Fa-:4013115
4820776 | P0- Escola | 1.975 | Grupo de modelo:Fa-:4013115
4820781 | P0- Escola | 1.92 | Grupo de modelo:Fa-:4013115
4820786 | P0- Escola | 1.92 | Grupo de modelo:Fa-:4013115
4820791 | P0- Escola | 1.92 | Grupo de modelo:Fa-:4013115
4820796 | P0- Escola | 1.975 | Grupo de modelo:Fa-:4013115
4820801 | P0- Escola | 1.92 | Grupo de modelo:Fa-:4013115
4820806 | P0- Escola | 1.92 | Grupo de modelo:Fa-:4013115
4820841 | P0- Escola | 1.975 | Grupo de modelo:Fa-:4013115
4824554 | P0- Escola | 0.5375 | Grupo de modelo:Fa-:4013115
4824555 | P0- Escola | 0.5375 | Grupo de modelo:Fa-:4013115
4824556 | P0- Escola | 0.5375 | Grupo de modelo:Fa-:4013115
4824557 | P0- Escola | 0.5375 | Grupo de modelo:Fa-:4013115
4824558 | P0- Escola | 0.5375 | Grupo de modelo:Fa-:4013115
4824559 | P0- Escola | 0.5375 | Grupo de modelo:Fa-:4013115
4824560 | P0- Escola | 0.5375 | Grupo de modelo:Fa-:4013115
4824561 | P0- Escola | 0.5375 | Grupo de modelo:Fa-:4013115
4825502 | P0- Escola | 1.92 | Grupo de modelo:Fa-:4013115
4825503 | P0- Escola | 0.5375 | Grupo de modelo:Fa-:4013115
4820769 | P0- Escola | 0.84 | Grupo de modelo:Fa-:4013115
4820816 | P0- Escola | 0.84 | Grupo de modelo:Fa-:4013115
4820821 | P0- Escola | 0.785 | Grupo de modelo:Fa-:4013115
4820826 | P0- Escola | 0.785 | Grupo de modelo:Fa-:4013115
4820831 | P0- Escola | 0.785 | Grupo de modelo:Fa-:4013115
4820836 | P0- Escola | 0.84 | Grupo de modelo:Fa-:4013115
4820846 | P0- Escola | 0.84 | Grupo de modelo:Fa-:4013115
4821436 | P0- Escola | 0.785 | Grupo de modelo:Fa-:4013115
4821527 | P0- Escola | 0.785 | Grupo de modelo:Fa-:4013115
4821634 | P0- Escola | 0.785 | Grupo de modelo:Fa-:4013115
5783975 | P0- Escola | 0.875 | Grupo de modelo:Fa-:4013115
5783977 | P0- Escola | 0.875 | Grupo de modelo:Fa-:4013115
5783978 | P0- Escola | 0.875 | Grupo de modelo:Fa-:4013115
5783979 | P0- Escola | 0.875 | Grupo de modelo:Fa-:4013115
5783980 | P0- Escola | 0.875 | Grupo de modelo:Fa-:4013115
5783981 | P0- Escola | 0.875 | Grupo de modelo:Fa-:4013115
5783982 | P0- Escola | 0.875 | Grupo de modelo:Fa-:4013115
5783983 | P0- Escola | 0.875 | Grupo de modelo:Fa-:4013115
5783984 | P0- Escola | 0.875 | Grupo de modelo:Fa-:4013115
5783985 | P0- Escola | 0.875 | Grupo de modelo:Fa-:4013115
6036082 | P0- Escola | 0.7975 | Grupo de modelo:Fa-:4013115
6036083 | P0- Escola | 0.7975 | Grupo de modelo:Fa-:4013115
6036084 | P0- Escola | 0.7975 | Grupo de modelo:Fa-:4013115
6036085 | P0- Escola | 0.7975 | Grupo de modelo:Fa-:4013115
6036086 | P0- Escola | 0.7975 | Grupo de modelo:Fa-:4013115
6036087 | P0- Escola | 0.7975 | Grupo de modelo:Fa-:4013115
6036088 | P0- Escola | 0.7975 | Grupo de modelo:Fa-:4013115
6036089 | P0- Escola | 0.7975 | Grupo de modelo:Fa-:4013115
6036090 | P0- Escola | 0.7975 | Grupo de modelo:Fa-:4013115
6036091 | P0- Escola | 0.7975 | Grupo de modelo:Fa-:4013115
6042454 | P0- Escola | 0.607651
6042455 | P0- Escola | 1.102
6042456 | P0- Escola | 1.141
4935649 | P0- Escola | 0.785 | Grupo de modelo:Fa-:4013115
4935656 | P0- Escola | 0.84 | Grupo de modelo:Fa-:4013115
4935661 | P0- Escola | 0.785 | Grupo de modelo:Fa-:4013115
4935666 | P0- Escola | 0.785 | Grupo de modelo:Fa-:4013115
4935671 | P0- Escola | 0.84 | Grupo de modelo:Fa-:4013115
4935676 | P0- Escola | 0.84 | Grupo de modelo:Fa-:4013115
4935681 | P0- Escola | 0.785 | Grupo de modelo:Fa-:4013115
4935686 | P0- Escola | 0.785 | Grupo de modelo:Fa-:4013115
4935691 | P0- Escola | 0.84 | Grupo de modelo:Fa-:4013115
4935696 | P0- Escola | 0.84 | Grupo de modelo:Fa-:4013115
4935701 | P0- Escola | 0.785 | Grupo de modelo:Fa-:4013115
4935706 | P0- Escola | 0.785 | Grupo de modelo:Fa-:4013115
4935711 | P0- Escola | 0.84 | Grupo de modelo:Fa-:4013115
4935716 | P0- Escola | 0.84 | Grupo de modelo:Fa-:4013115
4935721 | P0- Escola | 0.84 | Grupo de modelo:Fa-:4013115
4935726 | P0- Escola | 0.84 | Grupo de modelo:Fa-:4013115
4937872 | P0- Escola | 0.785 | Grupo de modelo:Fa-:4013115
4937974 | P0- Escola | 0.785 | Grupo de modelo:Fa-:4013115
4938056 | P0- Escola | 0.785 | Grupo de modelo:Fa-:4013115
5791271 | P0- Escola | 0.875 | Grupo de modelo:Fa-:4013115
5791274 | P0- Escola | 0.875 | Grupo de modelo:Fa-:4013115
5791275 | P0- Escola | 0.875 | Grupo de modelo:Fa-:4013115
5791276 | P0- Escola | 0.875 | Grupo de modelo:Fa-:4013115
5791277 | P0- Escola | 0.875 | Grupo de modelo:Fa-:4013115
5791278 | P0- Escola | 0.875 | Grupo de modelo:Fa-:4013115
5791279 | P0- Escola | 0.875 | Grupo de modelo:Fa-:4013115
5791280 | P0- Escola | 0.875 | Grupo de modelo:Fa-:4013115
5791281 | P0- Escola | 0.875 | Grupo de modelo:Fa-:4013115
5791282 | P0- Escola | 0.875 | Grupo de modelo:Fa-:4013115
5791283 | P0- Escola | 0.875 | Grupo de modelo:Fa-:4013115
5791284 | P0- Escola | 0.875 | Grupo de modelo:Fa-:4013115
5791285 | P0- Escola | 0.875 | Grupo de modelo:Fa-:4013115
5791286 | P0- Escola | 0.875 | Grupo de modelo:Fa-:4013115
5791287 | P0- Escola | 0.875 | Grupo de modelo:Fa-:4013115
5791288 | P0- Escola | 0.875 | Grupo de modelo:Fa-:4013115
5791289 | P0- Escola | 0.875 | Grupo de modelo:Fa-:4013115
5791290 | P0- Escola | 0.875 | Grupo de modelo:Fa-:4013115
5791291 | P0- Escola | 0.875 | Grupo de modelo:Fa-:4013115
6032856 | P0- Escola | 0.7975 | Grupo de modelo:Fa-:4013115
6032857 | P0- Escola | 0.7975 | Grupo de modelo:Fa-:4013115
6032858 | P0- Escola | 0.7975 | Grupo de modelo:Fa-:4013115
6032859 | P0- Escola | 0.7975 | Grupo de modelo:Fa-:4013115
6032860 | P0- Escola | 0.7975 | Grupo de modelo:Fa-:4013115
6032861 | P0- Escola | 0.7975 | Grupo de modelo:Fa-:4013115
6032862 | P0- Escola | 0.7975 | Grupo de modelo:Fa-:4013115
6032863 | P0- Escola | 0.7975 | Grupo de modelo:Fa-:4013115
6032864 | P0- Escola | 0.7975 | Grupo de modelo:Fa-:4013115
6032865 | P0- Escola | 0.7975 | Grupo de modelo:Fa-:4013115
6032866 | P0- Escola | 0.7975 | Grupo de modelo:Fa-:4013115
6032867 | P0- Escola | 0.7975 | Grupo de modelo:Fa-:4013115
6032868 | P0- Escola | 0.7975 | Grupo de modelo:Fa-:4013115
6032869 | P0- Escola | 0.7975 | Grupo de modelo:Fa-:4013115
6032870 | P0- Escola | 0.7975 | Grupo de modelo:Fa-:4013115
6032871 | P0- Escola | 0.7975 | Grupo de modelo:Fa-:4013115
6032872 | P0- Escola | 0.7975 | Grupo de modelo:Fa-:4013115
6032873 | P0- Escola | 0.7975 | Grupo de modelo:Fa-:4013115
6032874 | P0- Escola | 0.7975 | Grupo de modelo:Fa-:4013115
4943383 | P0- Escola | 1 | Grupo de modelo:Fa-:4013115
4943390 | P0- Escola | 1 | Grupo de modelo:Fa-:4013115
4943395 | P0- Escola | 0.945 | Grupo de modelo:Fa-:4013115
4943400 | P0- Escola | 0.945 | Grupo de modelo:Fa-:4013115
4943405 | P0- Escola | 1 | Grupo de modelo:Fa-:4013115
4943410 | P0- Escola | 1 | Grupo de modelo:Fa-:4013115
4943415 | P0- Escola | 0.945 | Grupo de modelo:Fa-:4013115
4943420 | P0- Escola | 0.945 | Grupo de modelo:Fa-:4013115
4943425 | P0- Escola | 1 | Grupo de modelo:Fa-:4013115
4943430 | P0- Escola | 1 | Grupo de modelo:Fa-:4013115
4943435 | P0- Escola | 0.945 | Grupo de modelo:Fa-:4013115
4943440 | P0- Escola | 0.945 | Grupo de modelo:Fa-:4013115
4943450 | P0- Escola | 1 | Grupo de modelo:Fa-:4013115
4943455 | P0- Escola | 1 | Grupo de modelo:Fa-:4013115
4943460 | P0- Escola | 1 | Grupo de modelo:Fa-:4013115
5793099 | P0- Escola | 1.5125 | Grupo de modelo:Fa-:4013115
5793102 | P0- Escola | 1.5125 | Grupo de modelo:Fa-:4013115
5793103 | P0- Escola | 1.5125 | Grupo de modelo:Fa-:4013115
5793104 | P0- Escola | 1.5125 | Grupo de modelo:Fa-:4013115
5793105 | P0- Escola | 1.5125 | Grupo de modelo:Fa-:4013115
5793106 | P0- Escola | 1.5125 | Grupo de modelo:Fa-:4013115
5793107 | P0- Escola | 1.5125 | Grupo de modelo:Fa-:4013115
5793108 | P0- Escola | 1.5125 | Grupo de modelo:Fa-:4013115
5793109 | P0- Escola | 1.5125 | Grupo de modelo:Fa-:4013115
5793110 | P0- Escola | 1.5125 | Grupo de modelo:Fa-:4013115
5793111 | P0- Escola | 1.5125 | Grupo de modelo:Fa-:4013115
5793112 | P0- Escola | 1.5125 | Grupo de modelo:Fa-:4013115
5793113 | P0- Escola | 1.5125 | Grupo de modelo:Fa-:4013115
5793114 | P0- Escola | 1.5125 | Grupo de modelo:Fa-:4013115
5793115 | P0- Escola | 1.5125 | Grupo de modelo:Fa-:4013115
5793269 | P0- Escola | 1.5125 | Grupo de modelo:Fa-:4013115
5793270 | P0- Escola | 1 | Grupo de modelo:Fa-:4013115
6029253 | P0- Escola | 0.785 | Grupo de modelo:Fa-:4013115
6029259 | P0- Escola | 0.84 | Grupo de modelo:Fa-:4013115
6029264 | P0- Escola | 0.785 | Grupo de modelo:Fa-:4013115
6029268 | P0- Escola | 0.785 | Grupo de modelo:Fa-:4013115
6029272 | P0- Escola | 0.84 | Grupo de modelo:Fa-:4013115
6029277 | P0- Escola | 0.84 | Grupo de modelo:Fa-:4013115
6029282 | P0- Escola | 0.785 | Grupo de modelo:Fa-:4013115
6029287 | P0- Escola | 0.785 | Grupo de modelo:Fa-:4013115
6029291 | P0- Escola | 0.84 | Grupo de modelo:Fa-:4013115
6029296 | P0- Escola | 0.84 | Grupo de modelo:Fa-:4013115
6029301 | P0- Escola | 0.785 | Grupo de modelo:Fa-:4013115
6029306 | P0- Escola | 0.785 | Grupo de modelo:Fa-:4013115
6029311 | P0- Escola | 0.84 | Grupo de modelo:Fa-:4013115
6029315 | P0- Escola | 0.84 | Grupo de modelo:Fa-:4013115
6029319 | P0- Escola | 0.84 | Grupo de modelo:Fa-:4013115
6029323 | P0- Escola | 0.84 | Grupo de modelo:Fa-:4013115
6029422 | P0- Escola | 0.875 | Grupo de modelo:Fa-:4013115
6029423 | P0- Escola | 0.875 | Grupo de modelo:Fa-:4013115
6029424 | P0- Escola | 0.875 | Grupo de modelo:Fa-:4013115
6029425 | P0- Escola | 0.875 | Grupo de modelo:Fa-:4013115
6029426 | P0- Escola | 0.875 | Grupo de modelo:Fa-:4013115
6029427 | P0- Escola | 0.875 | Grupo de modelo:Fa-:4013115
6029428 | P0- Escola | 0.875 | Grupo de modelo:Fa-:4013115
6029429 | P0- Escola | 0.875 | Grupo de modelo:Fa-:4013115
6029430 | P0- Escola | 0.875 | Grupo de modelo:Fa-:4013115
6029431 | P0- Escola | 0.875 | Grupo de modelo:Fa-:4013115
6029432 | P0- Escola | 0.875 | Grupo de modelo:Fa-:4013115
6029433 | P0- Escola | 0.875 | Grupo de modelo:Fa-:4013115
6029434 | P0- Escola | 0.875 | Grupo de modelo:Fa-:4013115
6029435 | P0- Escola | 0.875 | Grupo de modelo:Fa-:4013115
6029436 | P0- Escola | 0.875 | Grupo de modelo:Fa-:4013115
6029437 | P0- Escola | 0.875 | Grupo de modelo:Fa-:4013115
6029497 | P0- Escola | 0.7975 | Grupo de modelo:Fa-:4013115
6029499 | P0- Escola | 0.7975 | Grupo de modelo:Fa-:4013115
6029500 | P0- Escola | 0.7975 | Grupo de modelo:Fa-:4013115
6029501 | P0- Escola | 0.7975 | Grupo de modelo:Fa-:4013115
6029502 | P0- Escola | 0.7975 | Grupo de modelo:Fa-:4013115
6029503 | P0- Escola | 0.7975 | Grupo de modelo:Fa-:4013115
6029504 | P0- Escola | 0.7975 | Grupo de modelo:Fa-:4013115
6029505 | P0- Escola | 0.7975 | Grupo de modelo:Fa-:4013115
6029506 | P0- Escola | 0.7975 | Grupo de modelo:Fa-:4013115
6029507 | P0- Escola | 0.7975 | Grupo de modelo:Fa-:4013115
6029508 | P0- Escola | 0.7975 | Grupo de modelo:Fa-:4013115
6029509 | P0- Escola | 0.7975 | Grupo de modelo:Fa-:4013115
6029510 | P0- Escola | 0.7975 | Grupo de modelo:Fa-:4013115
6029511 | P0- Escola | 0.7975 | Grupo de modelo:Fa-:4013115
6029512 | P0- Escola | 0.7975 | Grupo de modelo:Fa-:4013115
6029513 | P0- Escola | 0.7975 | Grupo de modelo:Fa-:4013115
6029329 | P0- Escola | 0.84 | Grupo de modelo:Fa-:4013115
6029335 | P0- Escola | 0.84 | Grupo de modelo:Fa-:4013115
6029340 | P0- Escola | 0.785 | Grupo de modelo:Fa-:4013115
6029345 | P0- Escola | 0.785 | Grupo de modelo:Fa-:4013115
6029349 | P0- Escola | 0.84 | Grupo de modelo:Fa-:4013115
6029354 | P0- Escola | 0.84 | Grupo de modelo:Fa-:4013115
6029359 | P0- Escola | 0.785 | Grupo de modelo:Fa-:4013115
6029364 | P0- Escola | 0.785 | Grupo de modelo:Fa-:4013115
6029368 | P0- Escola | 0.84 | Grupo de modelo:Fa-:4013115
6029373 | P0- Escola | 0.84 | Grupo de modelo:Fa-:4013115
6029378 | P0- Escola | 0.785 | Grupo de modelo:Fa-:4013115
6029383 | P0- Escola | 0.785 | Grupo de modelo:Fa-:4013115
6029390 | P0- Escola | 0.84 | Grupo de modelo:Fa-:4013115
6029394 | P0- Escola | 0.84 | Grupo de modelo:Fa-:4013115
6029398 | P0- Escola | 0.84 | Grupo de modelo:Fa-:4013115
6029459 | P0- Escola | 0.875 | Grupo de modelo:Fa-:4013115
6029460 | P0- Escola | 0.875 | Grupo de modelo:Fa-:4013115
6029461 | P0- Escola | 0.875 | Grupo de modelo:Fa-:4013115
6029462 | P0- Escola | 0.875 | Grupo de modelo:Fa-:4013115
6029463 | P0- Escola | 0.875 | Grupo de modelo:Fa-:4013115
6029464 | P0- Escola | 0.875 | Grupo de modelo:Fa-:4013115
6029465 | P0- Escola | 0.875 | Grupo de modelo:Fa-:4013115
6029466 | P0- Escola | 0.875 | Grupo de modelo:Fa-:4013115
6029467 | P0- Escola | 0.875 | Grupo de modelo:Fa-:4013115
6029468 | P0- Escola | 0.875 | Grupo de modelo:Fa-:4013115
6029469 | P0- Escola | 0.875 | Grupo de modelo:Fa-:4013115
6029470 | P0- Escola | 0.875 | Grupo de modelo:Fa-:4013115
6029471 | P0- Escola | 0.875 | Grupo de modelo:Fa-:4013115
6029472 | P0- Escola | 0.875 | Grupo de modelo:Fa-:4013115
6029473 | P0- Escola | 0.875 | Grupo de modelo:Fa-:4013115
6029474 | P0- Escola | 0.875 | Grupo de modelo:Fa-:4013115
6029475 | P0- Escola | 0.84 | Grupo de modelo:Fa-:4013115
6029532 | P0- Escola | 0.7975 | Grupo de modelo:Fa-:4013115
6029533 | P0- Escola | 0.7975 | Grupo de modelo:Fa-:4013115
6029534 | P0- Escola | 0.7975 | Grupo de modelo:Fa-:4013115
6029535 | P0- Escola | 0.7975 | Grupo de modelo:Fa-:4013115
6029536 | P0- Escola | 0.7975 | Grupo de modelo:Fa-:4013115
6029537 | P0- Escola | 0.7975 | Grupo de modelo:Fa-:4013115
6029538 | P0- Escola | 0.7975 | Grupo de modelo:Fa-:4013115
6029539 | P0- Escola | 0.7975 | Grupo de modelo:Fa-:4013115
6029540 | P0- Escola | 0.7975 | Grupo de modelo:Fa-:4013115
6029541 | P0- Escola | 0.7975 | Grupo de modelo:Fa-:4013115
6029542 | P0- Escola | 0.7975 | Grupo de modelo:Fa-:4013115
6029543 | P0- Escola | 0.7975 | Grupo de modelo:Fa-:4013115
6029544 | P0- Escola | 0.7975 | Grupo de modelo:Fa-:4013115
6029545 | P0- Escola | 0.7975 | Grupo de modelo:Fa-:4013115
6029546 | P0- Escola | 0.7975 | Grupo de modelo:Fa-:4013115
6029547 | P0- Escola | 0.7975 | Grupo de modelo:Fa-:4013115
6029577 | P0- Escola | 0.785 | Grupo de modelo:Fa-:4013115
6029583 | P0- Escola | 0.84 | Grupo de modelo:Fa-:4013115
6029588 | P0- Escola | 0.785 | Grupo de modelo:Fa-:4013115
6029592 | P0- Escola | 0.785 | Grupo de modelo:Fa-:4013115
6029596 | P0- Escola | 0.84 | Grupo de modelo:Fa-:4013115
6029601 | P0- Escola | 0.84 | Grupo de modelo:Fa-:4013115
6029606 | P0- Escola | 0.785 | Grupo de modelo:Fa-:4013115
6029611 | P0- Escola | 0.785 | Grupo de modelo:Fa-:4013115
6029615 | P0- Escola | 0.84 | Grupo de modelo:Fa-:4013115
6029620 | P0- Escola | 0.84 | Grupo de modelo:Fa-:4013115
6029625 | P0- Escola | 0.785 | Grupo de modelo:Fa-:4013115
6029630 | P0- Escola | 0.785 | Grupo de modelo:Fa-:4013115
6029635 | P0- Escola | 0.84 | Grupo de modelo:Fa-:4013115
6029639 | P0- Escola | 0.84 | Grupo de modelo:Fa-:4013115
6029643 | P0- Escola | 0.84 | Grupo de modelo:Fa-:4013115
6029647 | P0- Escola | 0.84 | Grupo de modelo:Fa-:4013115
6029674 | P0- Escola | 0.875 | Grupo de modelo:Fa-:4013115
6029675 | P0- Escola | 0.875 | Grupo de modelo:Fa-:4013115
6029676 | P0- Escola | 0.875 | Grupo de modelo:Fa-:4013115
6029677 | P0- Escola | 0.875 | Grupo de modelo:Fa-:4013115
6029678 | P0- Escola | 0.875 | Grupo de modelo:Fa-:4013115
6029679 | P0- Escola | 0.875 | Grupo de modelo:Fa-:4013115
6029680 | P0- Escola | 0.875 | Grupo de modelo:Fa-:4013115
6029681 | P0- Escola | 0.875 | Grupo de modelo:Fa-:4013115
6029682 | P0- Escola | 0.875 | Grupo de modelo:Fa-:4013115
6029683 | P0- Escola | 0.875 | Grupo de modelo:Fa-:4013115
6029684 | P0- Escola | 0.875 | Grupo de modelo:Fa-:4013115
6029685 | P0- Escola | 0.875 | Grupo de modelo:Fa-:4013115
6029686 | P0- Escola | 0.875 | Grupo de modelo:Fa-:4013115
6029687 | P0- Escola | 0.875 | Grupo de modelo:Fa-:4013115
6029688 | P0- Escola | 0.875 | Grupo de modelo:Fa-:4013115
6029689 | P0- Escola | 0.875 | Grupo de modelo:Fa-:4013115
6029713 | P0- Escola | 0.7975 | Grupo de modelo:Fa-:4013115
6029715 | P0- Escola | 0.7975 | Grupo de modelo:Fa-:4013115
6029716 | P0- Escola | 0.7975 | Grupo de modelo:Fa-:4013115
6029717 | P0- Escola | 0.7975 | Grupo de modelo:Fa-:4013115
6029718 | P0- Escola | 0.7975 | Grupo de modelo:Fa-:4013115
6029719 | P0- Escola | 0.7975 | Grupo de modelo:Fa-:4013115
6029720 | P0- Escola | 0.7975 | Grupo de modelo:Fa-:4013115
6029721 | P0- Escola | 0.7975 | Grupo de modelo:Fa-:4013115
6029722 | P0- Escola | 0.7975 | Grupo de modelo:Fa-:4013115
6029723 | P0- Escola | 0.7975 | Grupo de modelo:Fa-:4013115
6029724 | P0- Escola | 0.7975 | Grupo de modelo:Fa-:4013115
6029725 | P0- Escola | 0.7975 | Grupo de modelo:Fa-:4013115
6029726 | P0- Escola | 0.7975 | Grupo de modelo:Fa-:4013115
6029727 | P0- Escola | 0.7975 | Grupo de modelo:Fa-:4013115
6029728 | P0- Escola | 0.7975 | Grupo de modelo:Fa-:4013115
6029729 | P0- Escola | 0.7975 | Grupo de modelo:Fa-:4013115

# IfcMember: Montante rectangular:MC- Alu- 140x52,5 cm- Fa patis- Superior (183)
In: P0- Escola
Type - PredefinedType: MULLION; Material: _Alumini- T1- Perfil
Type - Pset_MemberCommon - IsExternal: no
Pset_MemberCommon - Reference: MC- Alu- 140x52,5 cm- Fa patis- Superior
Pset_QuantityTakeOff - Reference: MC- Alu- 140x52,5 cm- Fa patis- Superior
Group: Grupo de modelo:Fa-:4013115
Name (Montante rectangular:MC- Alu- 140x52,5 cm- Fa patis- Superior:...) | Span (m)
2564640 | 0.937498 | Pset_MemberCommon - IsExternal: yes
2564643 | 0.563335 | Pset_MemberCommon - IsExternal: yes
2564646 | 1 | Pset_MemberCommon - IsExternal: yes
2564649 | 1 | Pset_MemberCommon - IsExternal: yes
2564652 | 1 | Pset_MemberCommon - IsExternal: yes
2564655 | 1 | Pset_MemberCommon - IsExternal: yes
2564658 | 1 | Pset_MemberCommon - IsExternal: yes
2564661 | 1 | Pset_MemberCommon - IsExternal: yes
2564681 | 0.55 | Pset_MemberCommon - IsExternal: yes
2564686 | 1 | Pset_MemberCommon - IsExternal: yes
2564691 | 1 | Pset_MemberCommon - IsExternal: yes
2564696 | 1 | Pset_MemberCommon - IsExternal: yes
2564701 | 1 | Pset_MemberCommon - IsExternal: yes
2564706 | 1 | Pset_MemberCommon - IsExternal: yes
2564711 | 1 | Pset_MemberCommon - IsExternal: yes
2564716 | 1 | Pset_MemberCommon - IsExternal: yes
2564721 | 0.60215 | Pset_MemberCommon - IsExternal: yes
2564726 | 1 | Pset_MemberCommon - IsExternal: yes
2564731 | 1 | Pset_MemberCommon - IsExternal: yes
2564736 | 1 | Pset_MemberCommon - IsExternal: yes
2564741 | 1 | Pset_MemberCommon - IsExternal: yes
2564746 | 1 | Pset_MemberCommon - IsExternal: yes
2564799 | 1 | Pset_MemberCommon - IsExternal: yes
2564806 | 1 | Pset_MemberCommon - IsExternal: yes
4643001 | 0.39785 | Pset_MemberCommon - IsExternal: yes
4643402 | 0.45 | Pset_MemberCommon - IsExternal: yes
4643806 | 0.386667 | Pset_MemberCommon - IsExternal: yes
3336760 | 0.5182
3336766 | 1.12625
3336771 | 1
3336776 | 1
3336781 | 0.687124
3336786 | 1.02625
3336791 | 1
3336796 | 1
3336801 | 1.02625
3336806 | 1.02625
3336811 | 1
3336816 | 1
3336821 | 1
4459700 | 1
4459764 | 0.507998
4587344 | 0.339126
4468968 | 1.05245
4468974 | 1.12625
4468979 | 1
4468984 | 1
4468989 | 1.02625
4468994 | 1.02625
4468999 | 1
4469004 | 1
4469009 | 1.02625
4469014 | 1.02625
4469019 | 1
4469024 | 1
4469044 | 1.02625
4816832 | 0.38775
4816838 | 1.12625
4816843 | 1
4816848 | 0.634468
4816853 | 1.02625
4816858 | 1.02625
4816863 | 1
4816868 | 0.656667
4816873 | 1.02625
4816878 | 0.333333
4816883 | 0.6115
4816888 | 1
4816908 | 1.02625
4816913 | 1.02549
4817106 | 0.639264
4817686 | 0.692917
4817827 | 0.3885
4817953 | 0.343333
4819023 | 0.365532
4820774 | 1.12625
4820779 | 1
4820784 | 1
4820789 | 1.02625
4820794 | 1.02625
4820799 | 1
4820804 | 1
4825442 | 1.02625
4820768 | 1.02625
4820814 | 1.02625
4820819 | 1
4820824 | 1
4820829 | 1.02905
4820844 | 1.02625
4821434 | 1
4821525 | 0.997204
4935648 | 0.9
4935654 | 1.12625
4935659 | 1
4935664 | 1
4935669 | 1.02625
4935674 | 1.02625
4935679 | 1
4935684 | 1
4935689 | 1.02625
4935694 | 1.02625
4935699 | 1
4935704 | 1
4935724 | 1.02625
4937870 | 1.02625
4937972 | 1
4938054 | 1
4943382 | 1.02625
4943388 | 1.12625
4943393 | 1
4943398 | 1
4943403 | 1
4943408 | 1
4943413 | 1
4943418 | 1
4943423 | 1
4943428 | 1
4943433 | 1
4943438 | 1
4943443 | 1
4943448 | 1
4943453 | 1
4943458 | 1
5381535 | 0.8858
5385695 | 0.8858
5385696 | 0.8328
5385697 | 0.8328
5385698 | 0.8328
5401887 | 0.8858
5401899 | 0.8858
5401900 | 0.8328
5401901 | 0.8328
5401902 | 0.8328
5401916 | 0.8858
5401928 | 0.8858
5401929 | 0.8328
5401930 | 0.8328
5401931 | 0.8328
6029252 | 0.5182
6029257 | 1.12625
6029262 | 1
6029266 | 1
6029271 | 0.687124
6029275 | 1.02625
6029280 | 1
6029285 | 1
6029290 | 1.02625
6029294 | 1.02625
6029299 | 1
6029304 | 1
6029309 | 1
6029322 | 1
6029325 | 0.507998
6029401 | 0.339126
6029328 | 1.05245
6029333 | 1.12625
6029338 | 1
6029343 | 1
6029348 | 1.02625
6029352 | 1.02625
6029357 | 1
6029362 | 1
6029367 | 1.02625
6029371 | 1.02625
6029376 | 1
6029381 | 1
6029397 | 1.02625
6029576 | 0.5182
6029581 | 1.12625
6029586 | 1
6029590 | 1
6029595 | 0.687124
6029599 | 1.02625
6029604 | 1
6029609 | 1
6029614 | 1.02625
6029618 | 1.02625
6029623 | 1
6029628 | 1
6029633 | 1
6029646 | 1
6029649 | 0.507998
6029653 | 0.339126

# IfcMember: Montante rectangular:MC- Alu- 140x52,5 cm- Fa patis- inferior (148)
In: P0- Escola
Type - PredefinedType: MULLION; Material: _Alumini- T1- Perfil
Type - Pset_MemberCommon - IsExternal: no
Pset_MemberCommon - Reference: MC- Alu- 140x52,5 cm- Fa patis- inferior
Pset_QuantityTakeOff - Reference: MC- Alu- 140x52,5 cm- Fa patis- inferior
Group: Grupo de modelo:Fa-:4013115
Name (Montante rectangular:MC- Alu- 140x52,5 cm- Fa patis- inferior:...) | Span (m)
2564669 | 0.334167 | Pset_MemberCommon - IsExternal: yes
2564671 | 0.97375 | Pset_MemberCommon - IsExternal: yes
2564672 | 1 | Pset_MemberCommon - IsExternal: yes
2564673 | 1 | Pset_MemberCommon - IsExternal: yes
2564674 | 1 | Pset_MemberCommon - IsExternal: yes
2564675 | 1 | Pset_MemberCommon - IsExternal: yes
2564676 | 0.45 | Pset_MemberCommon - IsExternal: yes
2564687 | 0.97375 | Pset_MemberCommon - IsExternal: yes
2564692 | 1 | Pset_MemberCommon - IsExternal: yes
2564697 | 1 | Pset_MemberCommon - IsExternal: yes
2564702 | 1 | Pset_MemberCommon - IsExternal: yes
2564707 | 1 | Pset_MemberCommon - IsExternal: yes
2564712 | 1 | Pset_MemberCommon - IsExternal: yes
2564717 | 0.39785 | Pset_MemberCommon - IsExternal: yes
2564727 | 0.97375 | Pset_MemberCommon - IsExternal: yes
2564732 | 1 | Pset_MemberCommon - IsExternal: yes
2564737 | 1 | Pset_MemberCommon - IsExternal: yes
2564742 | 1 | Pset_MemberCommon - IsExternal: yes
2564747 | 1 | Pset_MemberCommon - IsExternal: yes
2564800 | 0.989998 | Pset_MemberCommon - IsExternal: yes
2564807 | 1 | Pset_MemberCommon - IsExternal: yes
4643002 | 0.5759 | Pset_MemberCommon - IsExternal: yes
4643403 | 0.52375 | Pset_MemberCommon - IsExternal: yes
4643807 | 0.537085 | Pset_MemberCommon - IsExternal: yes
3336767 | 0.97375
3336772 | 1
3336777 | 0.339126
3336787 | 0.97375
3336792 | 1
3336797 | 0.97375
3336807 | 0.97375
3336812 | 1
3336822 | 0.481748
3336827 | 0.9475
4459765 | 0.5182
4587345 | 0.634624
4468971 | 0.9475
4468975 | 0.97375
4468980 | 1
4468985 | 0.97375
4468995 | 0.97375
4469000 | 1
4469005 | 0.97375
4469015 | 0.97375
4469020 | 1
4469025 | 0.97375
4469035 | 0.9475
4469040 | 0.9475
4816835 | 0.9475
4816839 | 0.97375
4816844 | 0.365532
4816849 | 0.97375
4816859 | 1
4816864 | 0.343333
4816869 | 0.97375
4816874 | 0.9475
4816879 | 0.3885
4816884 | 1
4816889 | 0.97375
4816894 | 0.972986
4816899 | 0.640417
4816904 | 0.97375
4816909 | 0.9475
4816914 | 0.639264
4817107 | 0.33525
4817687 | 0.333333
4817828 | 0.6115
4817954 | 0.656667
4819024 | 0.634468
4820771 | 0.9475
4820775 | 0.97375
4820780 | 1
4820785 | 1.02625
4820795 | 0.97375
4820800 | 1
4820805 | 1.02625
4820840 | 0.9475
4820815 | 0.97375
4820820 | 1
4820825 | 0.97375
4820830 | 0.997204
4821435 | 0.97375
4821526 | 1
4821633 | 1.02905
4935651 | 0.9475
4935655 | 0.97375
4935660 | 1
4935665 | 0.97375
4935675 | 0.97375
4935680 | 1
4935685 | 0.97375
4935695 | 0.97375
4935700 | 1
4935705 | 0.97375
4935710 | 0.97375
4935715 | 0.9475
4935720 | 0.9475
4937871 | 1
4937973 | 1
4938055 | 0.9
4943385 | 0.9475
4943389 | 0.97375
4943394 | 1
4943399 | 0.97375
4943409 | 0.97375
4943414 | 1
4943419 | 0.97375
4943429 | 0.97375
4943434 | 1
4943439 | 0.97375
4943449 | 0.9475
4943454 | 0.9475
6029258 | 0.97375
6029263 | 1
6029267 | 0.339126
6029276 | 0.97375
6029281 | 1
6029286 | 0.97375
6029295 | 0.97375
6029300 | 1
6029310 | 0.481748
6029314 | 0.9475
6029326 | 0.5182
6029402 | 0.634624
6029330 | 0.9475
6029334 | 0.97375
6029339 | 1
6029344 | 0.97375
6029353 | 0.97375
6029358 | 1
6029363 | 0.97375
6029372 | 0.97375
6029377 | 1
6029382 | 0.97375
6029389 | 0.9475
6029393 | 0.9475
6029582 | 0.97375
6029587 | 1
6029591 | 0.339126
6029600 | 0.97375
6029605 | 1
6029610 | 0.97375
6029619 | 0.97375
6029624 | 1
6029634 | 0.481748
6029638 | 0.9475
6029650 | 0.5182
6029654 | 0.634624

# IfcMember: Montante rectangular:MC- Alu- 140x52,5 cm- Fa patis- inferior porta (12)
In: P0- Escola
Type - PredefinedType: MULLION; Material: _Alumini- T1- Perfil
Type - Pset_MemberCommon - IsExternal: no
Pset_MemberCommon - Reference: MC- Alu- 140x52,5 cm- Fa patis- inferior porta
Pset_QuantityTakeOff - Reference: MC- Alu- 140x52,5 cm- Fa patis- inferior porta
Group: Grupo de modelo:Fa-:4013115
Name (Montante rectangular:MC- Alu- 140x52,5 cm- Fa patis- inferior porta:...) | Span (m)
3336763 | 0.9475 | Pset_MemberCommon - IsExternal: yes
3336817 | 0.97375 | Pset_MemberCommon - IsExternal: yes
4451395 | 0.9475 | Pset_MemberCommon - IsExternal: yes
4469030 | 0.947448
4943444 | 0.947448
6029254 | 0.9475
6029305 | 0.97375
6029318 | 0.9475
6029386 | 0.947448
6029578 | 0.9475
6029629 | 0.97375
6029642 | 0.9475

# IfcMember: Montante rectangular:MC- Alu- 140x52,5 cm- Fa patis- inferior porta reixa (4)
In: P0- Escola
Type - PredefinedType: MULLION; Material: _Alumini- T1- Perfil
Type - Pset_MemberCommon - IsExternal: no
Pset_MemberCommon - Reference: MC- Alu- 140x52,5 cm- Fa patis- inferior porta reixa; Span: 0.9475 m
Pset_QuantityTakeOff - Reference: MC- Alu- 140x52,5 cm- Fa patis- inferior porta reixa
Group: Grupo de modelo:Fa-:4013115
Name (Montante rectangular:MC- Alu- 140x52,5 cm- Fa patis- inferior porta reixa:...) | IsExternal
2564670 | yes
2564682 | yes
2564722 | yes
4820835

# IfcMember: Montante rectangular:MC- Alu- 140x52,5 cm- Fa pista- Superior (89)
Type - PredefinedType: MULLION; Material: _Alumini- T1- Perfil
Type - Pset_MemberCommon - IsExternal: no
Pset_MemberCommon - Reference: MC- Alu- 140x52,5 cm- Fa pista- Superior
Pset_QuantityTakeOff - Reference: MC- Alu- 140x52,5 cm- Fa pista- Superior
Name (Montante rectangular:MC- Alu- 140x52,5 cm- Fa pista- Superior:...) | In | Span (m)
102150 | PS1- Vestuari | 0.985 | Pset_MemberCommon - IsExternal: yes
102153 | PS1- Vestuari | 0.966 | Pset_MemberCommon - IsExternal: yes
102157 | PS1- Vestuari | 0.954 | Pset_MemberCommon - IsExternal: yes
102161 | PS1- Vestuari | 0.954 | Pset_MemberCommon - IsExternal: yes
102170 | PS1- Vestuari | 0.954 | Pset_MemberCommon - IsExternal: yes
102176 | PS1- Vestuari | 0.954 | Pset_MemberCommon - IsExternal: yes
102181 | PS1- Vestuari | 0.954 | Pset_MemberCommon - IsExternal: yes
102186 | PS1- Vestuari | 0.954 | Pset_MemberCommon - IsExternal: yes
102201 | PS1- Vestuari | 1.04 | Pset_MemberCommon - IsExternal: yes
102206 | PS1- Vestuari | 0.19 | Pset_MemberCommon - IsExternal: yes
102211 | PS1- Vestuari | 1.05 | Pset_MemberCommon - IsExternal: yes
102215 | PS1- Vestuari | 1.03 | Pset_MemberCommon - IsExternal: yes
102220 | PS1- Vestuari | 0.35 | Pset_MemberCommon - IsExternal: yes
102225 | PS1- Vestuari | 0.966 | Pset_MemberCommon - IsExternal: yes
102230 | PS1- Vestuari | 0.954 | Pset_MemberCommon - IsExternal: yes
102235 | PS1- Vestuari | 0.954 | Pset_MemberCommon - IsExternal: yes
102240 | PS1- Vestuari | 0.954 | Pset_MemberCommon - IsExternal: yes
102245 | PS1- Vestuari | 0.954 | Pset_MemberCommon - IsExternal: yes
102250 | PS1- Vestuari | 0.954 | Pset_MemberCommon - IsExternal: yes
102255 | PS1- Vestuari | 0.954 | Pset_MemberCommon - IsExternal: yes
102260 | PS1- Vestuari | 0.954 | Pset_MemberCommon - IsExternal: yes
102265 | PS1- Vestuari | 0.356 | Pset_MemberCommon - IsExternal: yes
102270 | PS1- Vestuari | 0.957 | Pset_MemberCommon - IsExternal: yes
102275 | PS1- Vestuari | 0.84 | Pset_MemberCommon - IsExternal: yes
102279 | PS1- Vestuari | 0.982 | Pset_MemberCommon - IsExternal: yes
102285 | PS1- Vestuari | 0.929 | Pset_MemberCommon - IsExternal: yes
102290 | PS1- Vestuari | 0.642 | Pset_MemberCommon - IsExternal: yes
102295 | PS1- Vestuari | 0.35 | Pset_MemberCommon - IsExternal: yes
102300 | PS1- Vestuari | 0.642 | Pset_MemberCommon - IsExternal: yes
102305 | PS1- Vestuari | 1.0275 | Pset_MemberCommon - IsExternal: yes
102310 | PS1- Vestuari | 6.3355 | Pset_MemberCommon - IsExternal: yes
5318218 | PS1- Vestuari | 1.04 | Pset_MemberCommon - IsExternal: yes
5318340 | PS1- Vestuari | 0.35 | Pset_MemberCommon - IsExternal: yes
895048 | P0- Escola | 0.8
6040137 | P0- Escola | 1.384
6041667 | P0- Escola | 1.384
4774204 | P0- Escola | 2.06434
4776984 | P0- Escola | 2.117
4783343 | P0- Escola | 2.117
4784052 | P0- Escola | 2.117
4784195 | P0- Escola | 2.117
4784306 | P0- Escola | 2.117
4784390 | P0- Escola | 2.117
4784466 | P0- Escola | 2.117
4784528 | P0- Escola | 2.117
4784600 | P0- Escola | 2.117
4784728 | P0- Escola | 2.117
4784872 | P0- Escola | 2.171
4791946 | P0- Escola | 2.09
4865603 | P0- Escola | 0.32
4865609 | P0- Escola | 2.117
4865614 | P0- Escola | 2.117
4865619 | P0- Escola | 2.15936
4865634 | P0- Escola | 3.22628
4866121 | P0- Escola | 1.62
4868298 | P0- Escola | 2.34036
4868641 | P0- Escola | 2.083
4869252 | P0- Escola | 1.909
4869363 | P0- Escola | 2.177
4869435 | P0- Escola | 2.177
4869478 | P0- Escola | 2.177
4869517 | P0- Escola | 2.177
4873586 | P0- Escola | 1.24659
4873632 | P0- Escola | 2.117
4873637 | P0- Escola | 2.117
4873642 | P0- Escola | 2.52641
4898270 | P0- Escola | 0.657651
4898928 | P0- Escola | 1.191
4898977 | P0- Escola | 1.102
4899972 | P0- Escola | 0.654945
4899978 | P0- Escola | 0.954998
4899983 | P0- Escola | 1.432
4900869 | P0- Escola | 1.402
4908970 | P0- Escola | 1.44
4909153 | P0- Escola | 0.634
4911246 | P0- Escola | 1.219
4911298 | P0- Escola | 1.218
4911352 | P0- Escola | 1.218
4911430 | P0- Escola | 1.218
4911488 | P0- Escola | 1.243
4924533 | PC- Coberta STR | 1.2
5316596 | PC- Coberta STR | 1.175
5316597 | PC- Coberta STR | 1.175
5316598 | PC- Coberta STR | 1.175
5316599 | PC- Coberta STR | 1.175
5316684 | PC- Coberta STR | 1.2
5131480 | P0- Escola | 1.809
5410570 | P0- Escola | 1.5
6041491 | P0- Escola | 1.55

# IfcMember: Montante rectangular:MC- Alu- 140x52,5 cm- Fa pista- Superior simple (7)
In: P0- Escola
Type - PredefinedType: MULLION; Material: _Alumini- T1- Perfil
Type - Pset_MemberCommon - IsExternal: no
Pset_MemberCommon - Reference: MC- Alu- 140x52,5 cm- Fa pista- Superior simple
Pset_QuantityTakeOff - Reference: MC- Alu- 140x52,5 cm- Fa pista- Superior simple
Name (Montante rectangular:MC- Alu- 140x52,5 cm- Fa pista- Superior simple:...) | Span (m)
4792298 | 1.2575 | Pset_MemberCommon - IsExternal: yes
4804575 | 2.56 | Pset_MemberCommon - IsExternal: yes
4865357 | 1.2575 | Pset_MemberCommon - IsExternal: yes
4809767 | 0.24
5989858 | 0.15
4810608 | 0.24
5990244 | 0.15

# IfcMember: Montante rectangular:MC- Alu- 140x52,5 cm- Gimnas- Inferior (6)
In: PS1- Gimnàs
Type - PredefinedType: MULLION; Material: _Alumini- T1- Perfil
Type - Pset_MemberCommon - IsExternal: no
Pset_MemberCommon - IsExternal: yes; Reference: MC- Alu- 140x52,5 cm- Gimnas- Inferior
Pset_QuantityTakeOff - Reference: MC- Alu- 140x52,5 cm- Gimnas- Inferior
Name (Montante rectangular:MC- Alu- 140x52,5 cm- Gimnas- Inferior:...) | Span (m)
4694279 | 1.1685
4696976 | 0.7745
4697185 | 0.98
4697261 | 0.98
4697343 | 0.98
4697419 | 0.98

# IfcMember: Montante rectangular:MC- Alu- 140x52,5 cm- Porta- Esquerra (4)
In: P0- Escola
Type - PredefinedType: MULLION; Material: _Alumini- T1- Perfil
Type - Pset_MemberCommon - IsExternal: no
Pset_MemberCommon - Reference: MC- Alu- 140x52,5 cm- Porta- Esquerra
Pset_QuantityTakeOff - Reference: MC- Alu- 140x52,5 cm- Porta- Esquerra
Name (Montante rectangular:MC- Alu- 140x52,5 cm- Porta- Esquerra:...) | Span (m)
4810605 | 0.592 | Pset_MemberCommon - IsExternal: yes
4874242 | 2.505 | Pset_MemberCommon - IsExternal: yes
4889906 | 0.592
4889924 | 2.505

# IfcMember: Montante rectangular:MC- Alu- 140x52,5 cm- Porta- dreta (4)
In: P0- Escola
Type - PredefinedType: MULLION; Material: _Alumini- T1- Perfil
Type - Pset_MemberCommon - IsExternal: no
Pset_MemberCommon - Reference: MC- Alu- 140x52,5 cm- Porta- dreta
Pset_QuantityTakeOff - Reference: MC- Alu- 140x52,5 cm- Porta- dreta
Name (Montante rectangular:MC- Alu- 140x52,5 cm- Porta- dreta:...) | Span (m)
4810604 | 2.505 | Pset_MemberCommon - IsExternal: yes
4874241 | 0.592 | Pset_MemberCommon - IsExternal: yes
4889905 | 2.505
4889923 | 0.592

# IfcMember: Montante rectangular:MC- Alu- 210x50 cm- Gimnas- Cantonada (2)
In: PS1- Gimnàs
Type - PredefinedType: MULLION; Material: _Alumini- T1- Perfil
Type - Pset_MemberCommon - IsExternal: no
Pset_MemberCommon - IsExternal: yes; Reference: MC- Alu- 210x50 cm- Gimnas- Cantonada
Pset_QuantityTakeOff - Reference: MC- Alu- 210x50 cm- Gimnas- Cantonada
Name (Montante rectangular:MC- Alu- 210x50 cm- Gimnas- Cantonada:...) | Span (m)
4694280 | 2.55
4696818 | 2.46

# IfcMember: Montante rectangular:MC- Alu- 210x50 cm- Gimnas- Centre (7)
In: PS1- Gimnàs
Type - PredefinedType: MULLION; Material: _Alumini- T1- Perfil
Type - Pset_MemberCommon - IsExternal: no
Pset_MemberCommon - Reference: MC- Alu- 210x50 cm- Gimnas- Centre
Pset_QuantityTakeOff - Reference: MC- Alu- 210x50 cm- Gimnas- Centre
Name (Montante rectangular:MC- Alu- 210x50 cm- Gimnas- Centre:...) | Span (m)
4687998 | 2.5 | Pset_MemberCommon - IsExternal: yes
4691701 | 1.54556 | Pset_MemberCommon - IsExternal: yes
4694281 | 2.46
4696819 | 2.55
4719264 | 2.5
4719445 | 2.5
4719491 | 2.5

# IfcMember: Montante rectangular:MC- Alu- 210x50 cm- Gimnas- Centre inferior (6)
In: PS1- Gimnàs
Type - PredefinedType: MULLION; Material: _Alumini- T1- Perfil
Type - Pset_MemberCommon - IsExternal: no
Pset_MemberCommon - Reference: MC- Alu- 210x50 cm- Gimnas- Centre inferior
Pset_QuantityTakeOff - Reference: MC- Alu- 210x50 cm- Gimnas- Centre inferior
Name (Montante rectangular:MC- Alu- 210x50 cm- Gimnas- Centre inferior:...) | Span (m)
4666959 | 2.946 | Pset_MemberCommon - IsExternal: yes
4704450 | 2.946 | Pset_MemberCommon - IsExternal: yes
4704295 | 3.504
4704312 | 3.504
4756200 | 1.8475
4766221 | 1.054

# IfcMember: Montante rectangular:MC- Alu- 210x50 cm- Gimnas- Dreta (3)
In: PS1- Gimnàs
Type - PredefinedType: MULLION; Material: _Alumini- T1- Perfil
Type - Pset_MemberCommon - IsExternal: no
Pset_MemberCommon - Reference: MC- Alu- 210x50 cm- Gimnas- Dreta
Pset_QuantityTakeOff - Reference: MC- Alu- 210x50 cm- Gimnas- Dreta
Name (Montante rectangular:MC- Alu- 210x50 cm- Gimnas- Dreta:...) | IsExternal | Span (m)
4685248 | yes | 1.54556
4691700 | yes | 2.5
4718941 |  | 2.5

# IfcMember: Montante rectangular:MC- Alu- 210x50 cm- Gimnas- Esquerra (4)
In: PS1- Gimnàs
Type - PredefinedType: MULLION; Material: _Alumini- T1- Perfil
Type - Pset_MemberCommon - IsExternal: no
Pset_MemberCommon - Reference: MC- Alu- 210x50 cm- Gimnas- Esquerra
Pset_QuantityTakeOff - Reference: MC- Alu- 210x50 cm- Gimnas- Esquerra
Name (Montante rectangular:MC- Alu- 210x50 cm- Gimnas- Esquerra:...) | Span (m)
4667172 | 1.994 | Pset_MemberCommon - IsExternal: yes
4685247 | 2.5
4691699 | 1.54556
4718940 | 2.5

# IfcMember: Montante rectangular:MC- Alu- 210x50 cm- Gimnas- Superior (20)
In: PS1- Gimnàs
Type - PredefinedType: MULLION; Material: _Alumini- T1- Perfil
Type - Pset_MemberCommon - IsExternal: no
Pset_MemberCommon - Reference: MC- Alu- 210x50 cm- Gimnas- Superior
Pset_QuantityTakeOff - Reference: MC- Alu- 210x50 cm- Gimnas- Superior
Name (Montante rectangular:MC- Alu- 210x50 cm- Gimnas- Superior:...) | Span (m)
4667047 | 0.863775 | Pset_MemberCommon - IsExternal: yes
4667050 | 1.00628 | Pset_MemberCommon - IsExternal: yes
4667053 | 1.00628 | Pset_MemberCommon - IsExternal: yes
4667056 | 1.00628 | Pset_MemberCommon - IsExternal: yes
4667060 | 1.00628 | Pset_MemberCommon - IsExternal: yes
4667063 | 0.606275 | Pset_MemberCommon - IsExternal: yes
4667066 | 1.00628 | Pset_MemberCommon - IsExternal: yes
4667069 | 0.566275 | Pset_MemberCommon - IsExternal: yes
4762236 | 0.4925 | Pset_MemberCommon - IsExternal: yes
4762496 | 0.4 | Pset_MemberCommon - IsExternal: yes
4694278 | 0.7745
4696975 | 0.98
4697184 | 0.98
4697260 | 0.98
4697342 | 0.98
4697418 | 1.1685
4756197 | 1
4763320 | 0.999519
4763953 | 0.999519
4764306 | 0.999519

# IfcMember: Montante rectangular:MC- Alu- 50x60 cm- Fa pista- Centre (162)
Type - PredefinedType: MULLION; Material: _Alumini- T1- Perfil
Type - Pset_MemberCommon - IsExternal: no
Pset_MemberCommon - Reference: MC- Alu- 50x60 cm- Fa pista- Centre
Pset_QuantityTakeOff - Reference: MC- Alu- 50x60 cm- Fa pista- Centre
Name (Montante rectangular:MC- Alu- 50x60 cm- Fa pista- Centre:...) | In | Span (m)
102154 | PS1- Vestuari | 1.5475 | Pset_MemberCommon - IsExternal: yes
102158 | PS1- Vestuari | 1.5475 | Pset_MemberCommon - IsExternal: yes
102162 | PS1- Vestuari | 1.5475 | Pset_MemberCommon - IsExternal: yes
102169 | PS1- Vestuari | 1.5475 | Pset_MemberCommon - IsExternal: yes
102174 | PS1- Vestuari | 1.5475 | Pset_MemberCommon - IsExternal: yes
102179 | PS1- Vestuari | 1.5475 | Pset_MemberCommon - IsExternal: yes
102184 | PS1- Vestuari | 1.5475 | Pset_MemberCommon - IsExternal: yes
102199 | PS1- Vestuari | 1.5475 | Pset_MemberCommon - IsExternal: yes
102204 | PS1- Vestuari | 1.5475 | Pset_MemberCommon - IsExternal: yes
102209 | PS1- Vestuari | 1.5475 | Pset_MemberCommon - IsExternal: yes
102216 | PS1- Vestuari | 1.5475 | Pset_MemberCommon - IsExternal: yes
102221 | PS1- Vestuari | 1.5475 | Pset_MemberCommon - IsExternal: yes
102226 | PS1- Vestuari | 1.5475 | Pset_MemberCommon - IsExternal: yes
102231 | PS1- Vestuari | 1.5475 | Pset_MemberCommon - IsExternal: yes
102236 | PS1- Vestuari | 1.5475 | Pset_MemberCommon - IsExternal: yes
102241 | PS1- Vestuari | 1.5475 | Pset_MemberCommon - IsExternal: yes
102246 | PS1- Vestuari | 1.5475 | Pset_MemberCommon - IsExternal: yes
102251 | PS1- Vestuari | 1.5475 | Pset_MemberCommon - IsExternal: yes
102256 | PS1- Vestuari | 1.5475 | Pset_MemberCommon - IsExternal: yes
102261 | PS1- Vestuari | 1.5475 | Pset_MemberCommon - IsExternal: yes
102266 | PS1- Vestuari | 1.5475 | Pset_MemberCommon - IsExternal: yes
102271 | PS1- Vestuari | 1.5475 | Pset_MemberCommon - IsExternal: yes
102276 | PS1- Vestuari | 1.5475 | Pset_MemberCommon - IsExternal: yes
102281 | PS1- Vestuari | 1.5475 | Pset_MemberCommon - IsExternal: yes
102286 | PS1- Vestuari | 1.5475 | Pset_MemberCommon - IsExternal: yes
102291 | PS1- Vestuari | 1.5475 | Pset_MemberCommon - IsExternal: yes
102296 | PS1- Vestuari | 1.5475 | Pset_MemberCommon - IsExternal: yes
102301 | PS1- Vestuari | 1.5475 | Pset_MemberCommon - IsExternal: yes
102306 | PS1- Vestuari | 1.5475 | Pset_MemberCommon - IsExternal: yes
102311 | PS1- Vestuari | 1.5475 | Pset_MemberCommon - IsExternal: yes
102312 | PS1- Vestuari | 1.5475 | Pset_MemberCommon - IsExternal: yes
5316947 | PS1- Vestuari | 1.5475 | Pset_MemberCommon - IsExternal: yes
5318220 | PS1- Vestuari | 1.5475 | Pset_MemberCommon - IsExternal: yes
5318342 | PS1- Vestuari | 1.5475 | Pset_MemberCommon - IsExternal: yes
102318 | PS1- Vestuari | 2.20994
5318631 | PS1- Vestuari | 2.20994
102324 | PS1- Vestuari | 2.20994
5323544 | PS1- Vestuari | 2.20994
102328 | PS1- Vestuari | 2.20994
102331 | PS1- Vestuari | 2.20994
5323631 | PS1- Vestuari | 2.20994
102337 | PS1- Vestuari | 2.20994
5323646 | PS1- Vestuari | 2.20994
102340 | PS1- Vestuari | 2.20994
102343 | PS1- Vestuari | 2.20994
5323658 | PS1- Vestuari | 2.20994
895050 | P0- Escola | 0.735
895051 | P0- Escola | 1.2525
6040749 | P0- Escola | 0.735
6041107 | P0- Escola | 1.2525
6041108 | P0- Escola | 0.735
6041109 | P0- Escola | 1.2525
6041669 | P0- Escola | 0.735
6041670 | P0- Escola | 1.2525
4774206 | P0- Escola | 0.77
4774207 | P0- Escola | 1.0475
4776986 | P0- Escola | 0.77
4783345 | P0- Escola | 0.77
4784054 | P0- Escola | 0.77
4784197 | P0- Escola | 0.77
4784308 | P0- Escola | 0.77
4784392 | P0- Escola | 0.77
4784468 | P0- Escola | 0.77
4784530 | P0- Escola | 0.77
4784602 | P0- Escola | 0.77
4784730 | P0- Escola | 0.77
4784874 | P0- Escola | 0.77
4791373 | P0- Escola | 1.0475
4791374 | P0- Escola | 0.77
4791376 | P0- Escola | 1.0475
4791377 | P0- Escola | 1.0475
4791378 | P0- Escola | 1.0475
4791379 | P0- Escola | 1.0475
4791380 | P0- Escola | 1.0475
4791381 | P0- Escola | 1.0475
4791382 | P0- Escola | 1.0475
4791383 | P0- Escola | 1.0475
4791384 | P0- Escola | 1.0475
4791385 | P0- Escola | 1.0475
4791386 | P0- Escola | 1.0475
4791948 | P0- Escola | 1.9025
4791949 | P0- Escola | 2
4792300 | P0- Escola | 2.415
4792301 | P0- Escola | 2.415
4804577 | P0- Escola | 2.415
4865359 | P0- Escola | 2.415
4865605 | P0- Escola | 0.77
4865606 | P0- Escola | 1.0475
4865611 | P0- Escola | 0.77
4865616 | P0- Escola | 0.77
4865621 | P0- Escola | 0.77
4865626 | P0- Escola | 0.77
4865636 | P0- Escola | 0.77
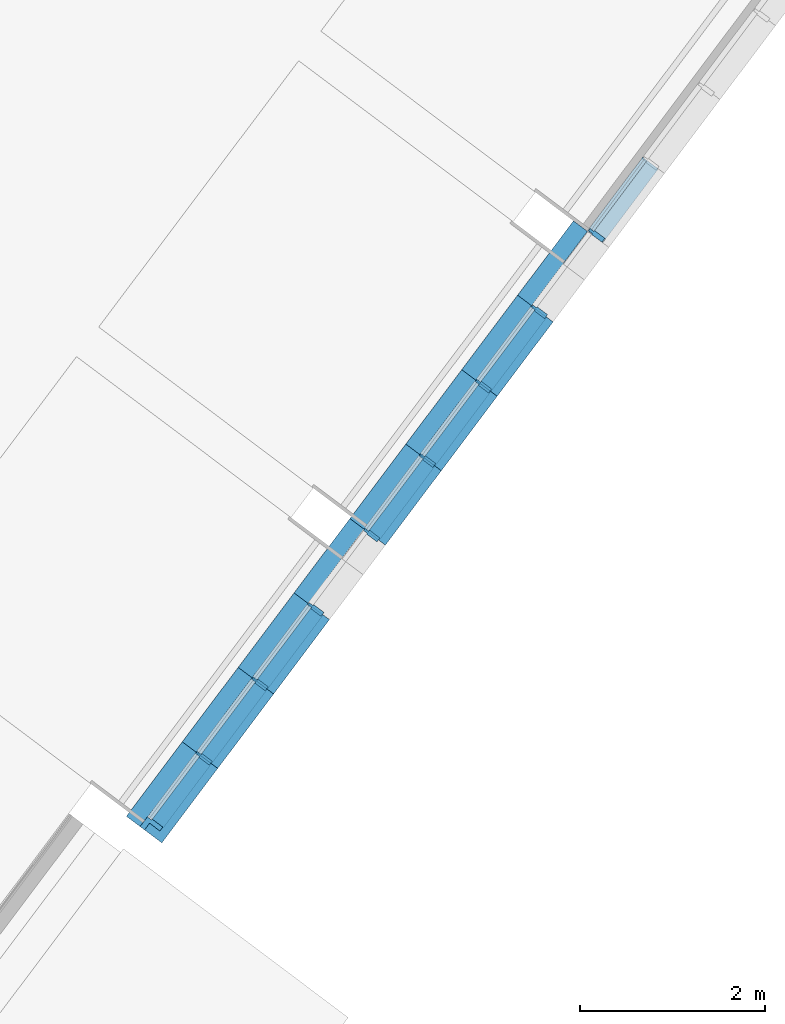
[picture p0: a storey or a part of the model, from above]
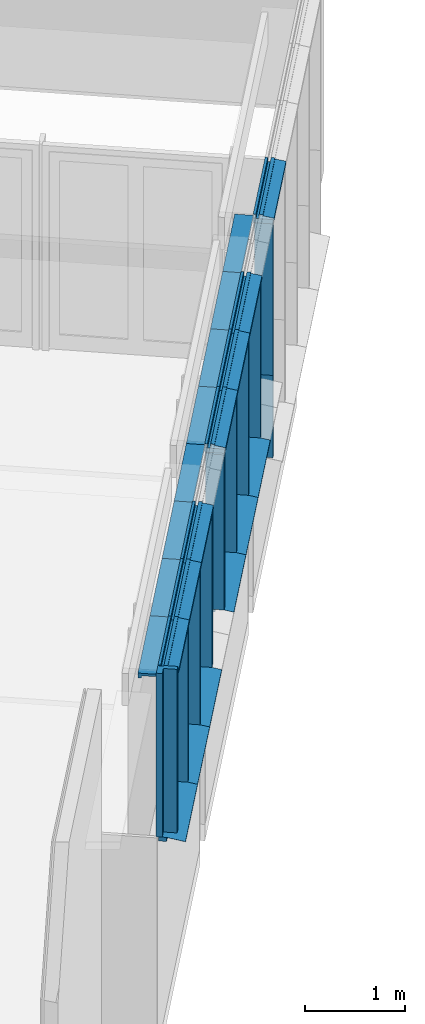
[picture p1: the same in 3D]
Properties of the parts of a building model (IFC2X3), part 3 of 6

# IfcMember: Montante rectangular:MC- Alu- 50x60 cm- Fa pista- Centre (162)
Name (Montante rectangular:MC- Alu- 50x60 cm- Fa pista- Centre:...) | In | Span (m)
4865681 | P0- Escola | 1.0475
4865682 | P0- Escola | 0.77
4865689 | P0- Escola | 1.0475
4865691 | P0- Escola | 1.0475
4865692 | P0- Escola | 1.0475
4865693 | P0- Escola | 1.0475
4865694 | P0- Escola | 1.0475
4866123 | P0- Escola | 0.77
4866124 | P0- Escola | 1.0475
4868643 | P0- Escola | 0.765
4868644 | P0- Escola | 1.0525
4869254 | P0- Escola | 0.765
4869365 | P0- Escola | 0.765
4869437 | P0- Escola | 0.765
4869480 | P0- Escola | 0.765
4869519 | P0- Escola | 0.765
4869685 | P0- Escola | 1.0525
4869686 | P0- Escola | 0.765
4869687 | P0- Escola | 1.0525
4869688 | P0- Escola | 1.0525
4869689 | P0- Escola | 1.0525
4869690 | P0- Escola | 1.0525
4869691 | P0- Escola | 1.0525
4873588 | P0- Escola | 0.77
4873589 | P0- Escola | 1.0475
4873634 | P0- Escola | 0.77
4873639 | P0- Escola | 0.77
4873644 | P0- Escola | 0.77
4873664 | P0- Escola | 1.0475
4873665 | P0- Escola | 0.77
4873667 | P0- Escola | 1.0475
4873668 | P0- Escola | 1.0475
4873669 | P0- Escola | 1.0475
4898272 | P0- Escola | 1.315
4898273 | P0- Escola | 1.1025
6042365 | P0- Escola | 1.1025
6042366 | P0- Escola | 1.315
4899974 | P0- Escola | 2.4175
4899975 | P0- Escola | 2.4175
4899980 | P0- Escola | 2.4175
4899985 | P0- Escola | 2.4175
4900871 | P0- Escola | 2.4175
4908973 | P0- Escola | 1.0525
4909155 | P0- Escola | 0.9675
4909156 | P0- Escola | 0.9675
4911248 | P0- Escola | 0.9675
4911300 | P0- Escola | 0.9675
4911354 | P0- Escola | 0.9675
4911432 | P0- Escola | 0.9675
4911490 | P0- Escola | 0.9675
4924535 | PC- Coberta STR | 1.8675
4924536 | PC- Coberta STR | 1.8675
5316604 | PC- Coberta STR | 1.8675
5316605 | PC- Coberta STR | 1.8675
5316606 | PC- Coberta STR | 1.8675
5316607 | PC- Coberta STR | 1.8675
5316685 | PC- Coberta STR | 1.8675
5131482 | P0- Escola | 2.5025
5131483 | P0- Escola | 2.5025
5323812 | PS1- Vestuari | 2.22994
5323817 | PS1- Vestuari | 2.22994
5323963 | PS1- Vestuari | 2.20994
5323966 | PS1- Vestuari | 2.20994
5410572 | P0- Escola | 0.735
5410573 | P0- Escola | 1.6825
6040576 | P0- Escola | 1.78
6040577 | P0- Escola | 0.82
6041493 | P0- Escola | 0.735
6041494 | P0- Escola | 1.6825

# IfcMember: Montante rectangular:MC- Alu- 52x80 cm- Fa pista- inferior (107)
Type - PredefinedType: MULLION; Material: _Alumini- T1- Perfil
Type - Pset_MemberCommon - IsExternal: no
Pset_MemberCommon - Reference: MC- Alu- 52x80 cm- Fa pista- inferior
Pset_QuantityTakeOff - Reference: MC- Alu- 52x80 cm- Fa pista- inferior
Name (Montante rectangular:MC- Alu- 52x80 cm- Fa pista- inferior:...) | In | Span (m)
102163 | PS1- Vestuari | 6.3355 | Pset_MemberCommon - IsExternal: yes
102164 | PS1- Vestuari | 0.954 | Pset_MemberCommon - IsExternal: yes
102165 | PS1- Vestuari | 0.954 | Pset_MemberCommon - IsExternal: yes
102166 | PS1- Vestuari | 0.954 | Pset_MemberCommon - IsExternal: yes
102171 | PS1- Vestuari | 0.985 | Pset_MemberCommon - IsExternal: yes
102175 | PS1- Vestuari | 0.954 | Pset_MemberCommon - IsExternal: yes
102180 | PS1- Vestuari | 0.954 | Pset_MemberCommon - IsExternal: yes
102185 | PS1- Vestuari | 0.954 | Pset_MemberCommon - IsExternal: yes
102200 | PS1- Vestuari | 1.04 | Pset_MemberCommon - IsExternal: yes
102205 | PS1- Vestuari | 1.04 | Pset_MemberCommon - IsExternal: yes
102210 | PS1- Vestuari | 0.19 | Pset_MemberCommon - IsExternal: yes
102214 | PS1- Vestuari | 1.05 | Pset_MemberCommon - IsExternal: yes
102219 | PS1- Vestuari | 1.03 | Pset_MemberCommon - IsExternal: yes
102224 | PS1- Vestuari | 0.35 | Pset_MemberCommon - IsExternal: yes
102229 | PS1- Vestuari | 0.966 | Pset_MemberCommon - IsExternal: yes
102234 | PS1- Vestuari | 0.954 | Pset_MemberCommon - IsExternal: yes
102239 | PS1- Vestuari | 0.954 | Pset_MemberCommon - IsExternal: yes
102244 | PS1- Vestuari | 0.954 | Pset_MemberCommon - IsExternal: yes
102249 | PS1- Vestuari | 0.954 | Pset_MemberCommon - IsExternal: yes
102254 | PS1- Vestuari | 0.954 | Pset_MemberCommon - IsExternal: yes
102259 | PS1- Vestuari | 0.954 | Pset_MemberCommon - IsExternal: yes
102264 | PS1- Vestuari | 0.954 | Pset_MemberCommon - IsExternal: yes
102269 | PS1- Vestuari | 0.356 | Pset_MemberCommon - IsExternal: yes
102274 | PS1- Vestuari | 0.982 | Pset_MemberCommon - IsExternal: yes
102280 | PS1- Vestuari | 0.957 | Pset_MemberCommon - IsExternal: yes
102284 | PS1- Vestuari | 0.84 | Pset_MemberCommon - IsExternal: yes
102289 | PS1- Vestuari | 0.929 | Pset_MemberCommon - IsExternal: yes
102294 | PS1- Vestuari | 0.642 | Pset_MemberCommon - IsExternal: yes
102299 | PS1- Vestuari | 0.35 | Pset_MemberCommon - IsExternal: yes
102304 | PS1- Vestuari | 0.642 | Pset_MemberCommon - IsExternal: yes
102309 | PS1- Vestuari | 1.0275 | Pset_MemberCommon - IsExternal: yes
5318219 | PS1- Vestuari | 0.35 | Pset_MemberCommon - IsExternal: yes
5318341 | PS1- Vestuari | 0.966 | Pset_MemberCommon - IsExternal: yes
895049 | P0- Escola | 1.384
6040138 | P0- Escola | 0.8
6041668 | P0- Escola | 1.384
4774205 | P0- Escola | 2.171
4776985 | P0- Escola | 2.06434
4783344 | P0- Escola | 2.117
4784053 | P0- Escola | 2.117
4784196 | P0- Escola | 2.117
4784307 | P0- Escola | 2.117
4784391 | P0- Escola | 2.117
4784467 | P0- Escola | 2.117
4784529 | P0- Escola | 2.117
4784601 | P0- Escola | 2.117
4784729 | P0- Escola | 2.117
4784873 | P0- Escola | 2.117
4791947 | P0- Escola | 2.04
4792299 | P0- Escola | 2.56
4804576 | P0- Escola | 1.2575
4865358 | P0- Escola | 1.2575
4865604 | P0- Escola | 3.22628
4865610 | P0- Escola | 1.62
4865615 | P0- Escola | 2.117
4865620 | P0- Escola | 2.117
4865625 | P0- Escola | 2.15936
4865635 | P0- Escola | 2.34036
4866122 | P0- Escola | 0.32
4868642 | P0- Escola | 1.909
4869253 | P0- Escola | 2.177
4869364 | P0- Escola | 2.177
4869436 | P0- Escola | 2.177
4869479 | P0- Escola | 2.177
4869518 | P0- Escola | 2.083
4873587 | P0- Escola | 2.52641
4873633 | P0- Escola | 1.24659
4873638 | P0- Escola | 2.117
4873643 | P0- Escola | 2.117
4898271 | P0- Escola | 1.191
4898929 | P0- Escola | 1.102
4898978 | P0- Escola | 0.657651
4899973 | P0- Escola | 0.954998
4899979 | P0- Escola | 1.432
4899984 | P0- Escola | 1.402
4900870 | P0- Escola | 0.654945
4908971 | P0- Escola | 1.39
4909154 | P0- Escola | 1.243
4911247 | P0- Escola | 0.634
4911299 | P0- Escola | 1.219
4911353 | P0- Escola | 1.218
4911431 | P0- Escola | 1.218
4911489 | P0- Escola | 1.218
4924534 | PC- Coberta STR | 1.2
5316600 | PC- Coberta STR | 1.175
5316601 | PC- Coberta STR | 1.175
5316602 | PC- Coberta STR | 1.175
5316603 | PC- Coberta STR | 1.2
5316683 | PC- Coberta STR | 1.175
5131481 | P0- Escola | 1.709
5381536 | P0- Escola | 0.8858 | Group: Grupo de modelo:Fa-:4013115
5385699 | P0- Escola | 0.8328 | Group: Grupo de modelo:Fa-:4013115
5385700 | P0- Escola | 0.8328 | Group: Grupo de modelo:Fa-:4013115
5385701 | P0- Escola | 0.8328 | Group: Grupo de modelo:Fa-:4013115
5385702 | P0- Escola | 0.8858 | Group: Grupo de modelo:Fa-:4013115
5401888 | P0- Escola | 0.8858 | Group: Grupo de modelo:Fa-:4013115
5401903 | P0- Escola | 0.8328 | Group: Grupo de modelo:Fa-:4013115
5401904 | P0- Escola | 0.8328 | Group: Grupo de modelo:Fa-:4013115
5401905 | P0- Escola | 0.8328 | Group: Grupo de modelo:Fa-:4013115
5401906 | P0- Escola | 0.8858 | Group: Grupo de modelo:Fa-:4013115
5401917 | P0- Escola | 0.8858 | Group: Grupo de modelo:Fa-:4013115
5401932 | P0- Escola | 0.8328 | Group: Grupo de modelo:Fa-:4013115
5401933 | P0- Escola | 0.8328 | Group: Grupo de modelo:Fa-:4013115
5401934 | P0- Escola | 0.8328 | Group: Grupo de modelo:Fa-:4013115
5401935 | P0- Escola | 0.8858 | Group: Grupo de modelo:Fa-:4013115
5410571 | P0- Escola | 1.5
6041492 | P0- Escola | 1.55

# IfcMember: Montante rectangular:MC- Alu- 65x41 cm- Fa Porxo- Centre (89)
In: P0- Escola
Type - PredefinedType: MULLION; Material: _Alumini- T1- Perfil
Type - Pset_MemberCommon - IsExternal: no
Pset_MemberCommon - Reference: MC- Alu- 65x41 cm- Fa Porxo- Centre
Pset_QuantityTakeOff - Reference: MC- Alu- 65x41 cm- Fa Porxo- Centre
Group: Grupo de modelo:Fa-:4013115
Name (Montante rectangular:MC- Alu- 65x41 cm- Fa Porxo- Centre:...) | Span (m)
4009184 | 0.964 | Pset_MemberCommon - IsExternal: yes
4009185 | 0.225667 | Pset_MemberCommon - IsExternal: yes
4009186 | 2.49775 | Pset_MemberCommon - IsExternal: yes
4011577 | 0.63125 | Pset_MemberCommon - IsExternal: yes
4011578 | 2.51225 | Pset_MemberCommon - IsExternal: yes
4011803 | 0.553833 | Pset_MemberCommon - IsExternal: yes
4011804 | 1.005 | Pset_MemberCommon - IsExternal: yes
4011806 | 2.47125 | Pset_MemberCommon - IsExternal: yes
4012166 | 0.533333 | Pset_MemberCommon - IsExternal: yes
4012169 | 0.56375 | Pset_MemberCommon - IsExternal: yes
4510530 | 1.5145
4510531 | 0.225667
4510532 | 2.49775
4510549 | 0.63125
4510550 | 2.51225
4510555 | 0.0683333
4510556 | 1.5555
4510558 | 2.47125
4510562 | 0.0478333
4510564 | 0.56375
4816954 | 1.5145
4816955 | 0.225667
4816956 | 2.49775
4816973 | 0.63125
4816974 | 2.51225
4816979 | 0.0683333
4816980 | 1.5555
4816982 | 2.47125
4816986 | 0.0478333
4816988 | 0.56375
4825853 | 1.219
4825854 | 0.266667
4825855 | 2.49775
4825872 | 0.63125
4825878 | 0.553833
4825879 | 1.26
4825881 | 2.47125
4825885 | 0.533333
4825887 | 0.56375
4935187 | 0.964
4935188 | 0.225667
4935189 | 2.49775
4935206 | 0.63125
4935207 | 2.51225
4935212 | 0.553833
4935213 | 1.005
4935215 | 2.47125
4935219 | 0.533333
4935221 | 0.56375
4935325 | 1.5145
4935326 | 0.225667
4935327 | 2.49775
4935344 | 0.63125
4935345 | 2.51225
4935350 | 0.0683333
4935351 | 1.5555
4935353 | 2.47125
4935357 | 0.0478333
4935359 | 0.56375
4935596 | 0.964
4935597 | 0.225667
4935598 | 2.49775
4935615 | 0.63125
4935616 | 2.51225
4935621 | 0.553833
4935622 | 1.005
4935624 | 2.47125
4935628 | 0.533333
4935630 | 0.56375
4935734 | 1.5145
4935735 | 0.225667
4935736 | 2.49775
4935753 | 0.63125
4935754 | 2.51225
4935759 | 0.0683333
4935760 | 1.5555
4935762 | 2.47125
4935766 | 0.0478333
4935768 | 0.56375
4943346 | 0.964
4943347 | 0.225667
4943348 | 2.49775
4943365 | 0.63125
4943366 | 2.51225
4943371 | 0.553833
4943372 | 1.005
4943374 | 2.47125
4943378 | 0.533333
4943380 | 0.56375

# IfcMember: Montante rectangular:MC- Alu- 65x52,5 cm- Fa Pati- Porta (6)
In: P0- Escola
Type - PredefinedType: MULLION; Material: _Alumini- T1- Perfil
Type - Pset_MemberCommon - IsExternal: no
Pset_MemberCommon - Reference: MC- Alu- 65x52,5 cm- Fa Pati- Porta; Span: 2.4275 m
Pset_QuantityTakeOff - Reference: MC- Alu- 65x52,5 cm- Fa Pati- Porta
Group: Grupo de modelo:Fa-:4013115
Name (Montante rectangular:MC- Alu- 65x52,5 cm- Fa Pati- Porta:...)
5381537 | Pset_MemberCommon - IsExternal: yes
5381538 | Pset_MemberCommon - IsExternal: yes
5401889
5401890
5401918
5401919

# IfcMember: Montante rectangular:MC- Alu- 65x52,5 cm- Fa Porxo- Centre (29)
In: P0- Escola
Type - PredefinedType: MULLION; Material: _Alumini- T1- Perfil
Type - Pset_MemberCommon - IsExternal: no
Pset_MemberCommon - Reference: MC- Alu- 65x52,5 cm- Fa Porxo- Centre
Pset_QuantityTakeOff - Reference: MC- Alu- 65x52,5 cm- Fa Porxo- Centre
Name (Montante rectangular:MC- Alu- 65x52,5 cm- Fa Porxo- Centre:...) | Span (m) | Group
4011579 | 0.266667 | Grupo de modelo:Fa-:4013115 | Pset_MemberCommon - IsExternal: yes
4011805 | 0.964 | Grupo de modelo:Fa-:4013115 | Pset_MemberCommon - IsExternal: yes
4012167 | 0.533333 | Grupo de modelo:Fa-:4013115 | Pset_MemberCommon - IsExternal: yes
4510551 | 0.266667 | Grupo de modelo:Fa-:4013115
4510557 | 1.5145 | Grupo de modelo:Fa-:4013115
4510563 | 0.0478333 | Grupo de modelo:Fa-:4013115
4810603 | 2.334
4816975 | 0.266667 | Grupo de modelo:Fa-:4013115
4816981 | 1.5145 | Grupo de modelo:Fa-:4013115
4816987 | 0.0478333 | Grupo de modelo:Fa-:4013115
4825874 | 0.266667 | Grupo de modelo:Fa-:4013115
4825880 | 1.219 | Grupo de modelo:Fa-:4013115
4825886 | 0.533333 | Grupo de modelo:Fa-:4013115
4889904 | 2.334
4935208 | 0.266667 | Grupo de modelo:Fa-:4013115
4935214 | 0.964 | Grupo de modelo:Fa-:4013115
4935220 | 0.533333 | Grupo de modelo:Fa-:4013115
4935346 | 0.266667 | Grupo de modelo:Fa-:4013115
4935352 | 1.5145 | Grupo de modelo:Fa-:4013115
4935358 | 0.0478333 | Grupo de modelo:Fa-:4013115
4935617 | 0.266667 | Grupo de modelo:Fa-:4013115
4935623 | 0.964 | Grupo de modelo:Fa-:4013115
4935629 | 0.533333 | Grupo de modelo:Fa-:4013115
4935755 | 0.266667 | Grupo de modelo:Fa-:4013115
4935761 | 1.5145 | Grupo de modelo:Fa-:4013115
4935767 | 0.0478333 | Grupo de modelo:Fa-:4013115
4943367 | 0.266667 | Grupo de modelo:Fa-:4013115
4943373 | 0.964 | Grupo de modelo:Fa-:4013115
4943379 | 0.533333 | Grupo de modelo:Fa-:4013115

# IfcMember: Montante rectangular:MC- Alu- gimnàs inferior lateral (14)
In: PS1- Gimnàs
Type - PredefinedType: MULLION; Material: _Alumini- T1- Perfil
Type - Pset_MemberCommon - IsExternal: no
Pset_MemberCommon - Reference: MC- Alu- gimnàs inferior lateral
Pset_QuantityTakeOff - Reference: MC- Alu- gimnàs inferior lateral
Name (Montante rectangular:MC- Alu- gimnàs inferior lateral:...) | IsExternal | Span (m)
4667162 | yes | 0.44
4667163 | yes | 1.00628
4667164 | yes | 0.4
4667165 | yes | 1.00628
4667166 | yes | 1.00628
4667167 | yes | 1.00628
4667168 | yes | 1.00628
4667169 | yes | 1.00628
4762237 | yes | 0.566275
4762497 | yes | 0.606275
4756198 |  | 0.947019
4763321 |  | 1
4763954 |  | 0.999519
4764307 |  | 0.999519

# IfcMember: Montante rectangular:MC- Fusta- 15x6 cm- Neutre (4)
In: P0- Escola
Type - PredefinedType: MULLION; Material: _Fusta massisa- T1
Type - Pset_MemberCommon - IsExternal: no
Pset_MemberCommon - Reference: MC- Fusta- 15x6 cm- Neutre
Pset_QuantityTakeOff - Reference: MC- Fusta- 15x6 cm- Neutre
Name (Montante rectangular:MC- Fusta- 15x6 cm- Neutre:...) | Span (m)
371278 | 1.285 | Pset_MemberCommon - IsExternal: yes
1355197 | 10.6925 | Pset_MemberCommon - IsExternal: yes
372969 | 1.945
5447471 | 0.35

# IfcMember: Montante rectangular:MC- Fusta- 15x7- Esquerra (3)
In: P0- Escola
Type - PredefinedType: MULLION; Material: _Fusta massisa- T1
Type - Pset_MemberCommon - IsExternal: no
Pset_MemberCommon - Reference: MC- Fusta- 15x7- Esquerra; Span: 1.665 m
Pset_QuantityTakeOff - Reference: MC- Fusta- 15x7- Esquerra
Name (Montante rectangular:MC- Fusta- 15x7- Esquerra:...) | Group
2141166 | Grupo de modelo:BANY1:2141168 | Pset_MemberCommon - IsExternal: yes
2334014 | Grupo de modelo:BANY1:2334016
2334664 | Grupo de modelo:BANY1:2334666

# IfcMember: Montante rectangular:MC- Fusta- 15x7- Neutre (3)
In: P0- Escola
Type - PredefinedType: MULLION; Material: _Fusta massisa- T1
Type - Pset_MemberCommon - IsExternal: no
Pset_MemberCommon - Reference: MC- Fusta- 15x7- Neutre; Span: 0.84 m
Pset_QuantityTakeOff - Reference: MC- Fusta- 15x7- Neutre
Name (Montante rectangular:MC- Fusta- 15x7- Neutre:...) | Group
2141163 | Grupo de modelo:BANY1:2141168 | Pset_MemberCommon - IsExternal: yes
2334011 | Grupo de modelo:BANY1:2334016
2334661 | Grupo de modelo:BANY1:2334666

# IfcMember: Montante rectangular:MC- Fusta- 20x6 cm- Centre (24)
In: P0- Escola
Type - PredefinedType: MULLION; Material: _Fusta massisa- T1
Type - Pset_MemberCommon - IsExternal: no
Pset_MemberCommon - Reference: MC- Fusta- 20x6 cm- Centre; Span: 2.505 m
Pset_QuantityTakeOff - Reference: MC- Fusta- 20x6 cm- Centre
Name (Montante rectangular:MC- Fusta- 20x6 cm- Centre:...)
364691 | Pset_MemberCommon - IsExternal: yes
364756 | Pset_MemberCommon - IsExternal: yes
364904 | Pset_MemberCommon - IsExternal: yes
364963 | Pset_MemberCommon - IsExternal: yes
365105 | Pset_MemberCommon - IsExternal: yes
365154 | Pset_MemberCommon - IsExternal: yes
365189 | Pset_MemberCommon - IsExternal: yes
365454 | Pset_MemberCommon - IsExternal: yes
365493 | Pset_MemberCommon - IsExternal: yes
365530 | Pset_MemberCommon - IsExternal: yes
365579 | Pset_MemberCommon - IsExternal: yes
361665
462871 | Group: Grupo de modelo:Grup aula:4934097
462875 | Group: Grupo de modelo:Grup aula:4934097
462887 | Group: Grupo de modelo:Grup aula:4934097
462891 | Group: Grupo de modelo:Grup aula:4934097
4940479 | Group: Grupo de modelo:Grup aula:4940566
4940483 | Group: Grupo de modelo:Grup aula:4940566
4940495 | Group: Grupo de modelo:Grup aula:4940566
4940499 | Group: Grupo de modelo:Grup aula:4940566
4940735 | Group: Grupo de modelo:Grup aula:4940822
4940739 | Group: Grupo de modelo:Grup aula:4940822
4940751 | Group: Grupo de modelo:Grup aula:4940822
4940755 | Group: Grupo de modelo:Grup aula:4940822

# IfcMember: Montante rectangular:MC- Fusta- 20x6 cm- Dreta (17)
In: P0- Escola
Type - PredefinedType: MULLION; Material: _Fusta massisa- T1
Type - Pset_MemberCommon - IsExternal: no
Pset_MemberCommon - Reference: MC- Fusta- 20x6 cm- Dreta; Span: 2.505 m
Pset_QuantityTakeOff - Reference: MC- Fusta- 20x6 cm- Dreta
Name (Montante rectangular:MC- Fusta- 20x6 cm- Dreta:...) | Group
365391 | Pset_MemberCommon - IsExternal: yes
360249
361764
361927
362152
462863 | Grupo de modelo:Grup aula:4934097
462879 | Grupo de modelo:Grup aula:4934097
462895 | Grupo de modelo:Grup aula:4934097
462915 | Grupo de modelo:Grup aula:4934097
4940471 | Grupo de modelo:Grup aula:4940566
4940487 | Grupo de modelo:Grup aula:4940566
4940503 | Grupo de modelo:Grup aula:4940566
4940523 | Grupo de modelo:Grup aula:4940566
4940727 | Grupo de modelo:Grup aula:4940822
4940743 | Grupo de modelo:Grup aula:4940822
4940759 | Grupo de modelo:Grup aula:4940822
4940779 | Grupo de modelo:Grup aula:4940822

# IfcMember: Montante rectangular:MC- Fusta- 20x6 cm- Esquerra (75)
In: P0- Escola
Type - PredefinedType: MULLION; Material: _Fusta massisa- T1
Type - Pset_MemberCommon - IsExternal: no
Pset_MemberCommon - Reference: MC- Fusta- 20x6 cm- Esquerra
Pset_QuantityTakeOff - Reference: MC- Fusta- 20x6 cm- Esquerra
Name (Montante rectangular:MC- Fusta- 20x6 cm- Esquerra:...) | Span (m) | Group
364690 | 1.03 | Pset_MemberCommon - IsExternal: yes
364755 | 1 | Pset_MemberCommon - IsExternal: yes
364805 | 1 | Pset_MemberCommon - IsExternal: yes
364806 | 2.505 | Pset_MemberCommon - IsExternal: yes
364842 | 1 | Pset_MemberCommon - IsExternal: yes
364903 | 1 | Pset_MemberCommon - IsExternal: yes
364962 | 1 | Pset_MemberCommon - IsExternal: yes
365104 | 1 | Pset_MemberCommon - IsExternal: yes
365153 | 1 | Pset_MemberCommon - IsExternal: yes
365188 | 1 | Pset_MemberCommon - IsExternal: yes
365245 | 1 | Pset_MemberCommon - IsExternal: yes
365246 | 2.505 | Pset_MemberCommon - IsExternal: yes
365280 | 1 | Pset_MemberCommon - IsExternal: yes
365453 | 1 | Pset_MemberCommon - IsExternal: yes
365492 | 1 | Pset_MemberCommon - IsExternal: yes
365529 | 1 | Pset_MemberCommon - IsExternal: yes
365578 | 1 | Pset_MemberCommon - IsExternal: yes
365645 | 1 | Pset_MemberCommon - IsExternal: yes
365646 | 2.505 | Pset_MemberCommon - IsExternal: yes
365718 | 1 | Pset_MemberCommon - IsExternal: yes
360248 | 2.505
360693 | 1.03
361664 | 1.03
361715 | 1
361716 | 2.505
361846 | 1
361885 | 1
361886 | 2.505
361969 | 1
362012 | 1
362013 | 2.505
362096 | 1
362218 | 1
462858 | 1 | Grupo de modelo:Grup aula:4934097
462859 | 2.505 | Grupo de modelo:Grup aula:4934097
462866 | 1 | Grupo de modelo:Grup aula:4934097
462867 | 2.505 | Grupo de modelo:Grup aula:4934097
462870 | 1 | Grupo de modelo:Grup aula:4934097
462874 | 1 | Grupo de modelo:Grup aula:4934097
462882 | 1 | Grupo de modelo:Grup aula:4934097
462883 | 2.505 | Grupo de modelo:Grup aula:4934097
462886 | 1 | Grupo de modelo:Grup aula:4934097
462894 | 1 | Grupo de modelo:Grup aula:4934097
462899 | 2.505 | Grupo de modelo:Grup aula:4934097
462910 | 1 | Grupo de modelo:Grup aula:4934097
462911 | 2.505 | Grupo de modelo:Grup aula:4934097
462914 | 1.03 | Grupo de modelo:Grup aula:4934097
4940466 | 1 | Grupo de modelo:Grup aula:4940566
4940467 | 2.505 | Grupo de modelo:Grup aula:4940566
4940474 | 1 | Grupo de modelo:Grup aula:4940566
4940475 | 2.505 | Grupo de modelo:Grup aula:4940566
4940478 | 1 | Grupo de modelo:Grup aula:4940566
4940482 | 1 | Grupo de modelo:Grup aula:4940566
4940490 | 1 | Grupo de modelo:Grup aula:4940566
4940491 | 2.505 | Grupo de modelo:Grup aula:4940566
4940494 | 1 | Grupo de modelo:Grup aula:4940566
4940502 | 1 | Grupo de modelo:Grup aula:4940566
4940507 | 2.505 | Grupo de modelo:Grup aula:4940566
4940518 | 1 | Grupo de modelo:Grup aula:4940566
4940519 | 2.505 | Grupo de modelo:Grup aula:4940566
4940522 | 1.03 | Grupo de modelo:Grup aula:4940566
4940722 | 1 | Grupo de modelo:Grup aula:4940822
4940723 | 2.505 | Grupo de modelo:Grup aula:4940822
4940730 | 1 | Grupo de modelo:Grup aula:4940822
4940731 | 2.505 | Grupo de modelo:Grup aula:4940822
4940734 | 1 | Grupo de modelo:Grup aula:4940822
4940738 | 1 | Grupo de modelo:Grup aula:4940822
4940746 | 1 | Grupo de modelo:Grup aula:4940822
4940747 | 2.505 | Grupo de modelo:Grup aula:4940822
4940750 | 1 | Grupo de modelo:Grup aula:4940822
4940758 | 1 | Grupo de modelo:Grup aula:4940822
4940763 | 2.505 | Grupo de modelo:Grup aula:4940822
4940774 | 1 | Grupo de modelo:Grup aula:4940822
4940775 | 2.505 | Grupo de modelo:Grup aula:4940822
4940778 | 1.03 | Grupo de modelo:Grup aula:4940822

# IfcMember: Montante rectangular:MC- Fusta- 20x6 cm- Inferior (46)
In: P0- Escola
Type - PredefinedType: MULLION; Material: _Fusta massisa- T1
Type - Pset_MemberCommon - IsExternal: no
Pset_MemberCommon - Reference: MC- Fusta- 20x6 cm- Inferior; Span: 0.94 m
Pset_QuantityTakeOff - Reference: MC- Fusta- 20x6 cm- Inferior
Name (Montante rectangular:MC- Fusta- 20x6 cm- Inferior:...) | Group
5444381 | Pset_MemberCommon - IsExternal: yes
5444382 | Pset_MemberCommon - IsExternal: yes
5444385 | Pset_MemberCommon - IsExternal: yes
5444386 | Pset_MemberCommon - IsExternal: yes
5444388 | Pset_MemberCommon - IsExternal: yes
5444389 | Pset_MemberCommon - IsExternal: yes
5444390 | Pset_MemberCommon - IsExternal: yes
5444394 | Pset_MemberCommon - IsExternal: yes
5444395 | Pset_MemberCommon - IsExternal: yes
5444396 | Pset_MemberCommon - IsExternal: yes
5444397 | Pset_MemberCommon - IsExternal: yes
5444398 | Pset_MemberCommon - IsExternal: yes
5444470 | Pset_MemberCommon - IsExternal: yes
5444738
5444739
5444744
5444745
5444749
5444751
5446180 | Grupo de modelo:Grup aula:4934097
5446182 | Grupo de modelo:Grup aula:4934097
5446183 | Grupo de modelo:Grup aula:4934097
5446184 | Grupo de modelo:Grup aula:4934097
5446186 | Grupo de modelo:Grup aula:4934097
5446187 | Grupo de modelo:Grup aula:4934097
5446188 | Grupo de modelo:Grup aula:4934097
5446190 | Grupo de modelo:Grup aula:4934097
5446193 | Grupo de modelo:Grup aula:4934097
5446197 | Grupo de modelo:Grup aula:4940566
5446199 | Grupo de modelo:Grup aula:4940566
5446200 | Grupo de modelo:Grup aula:4940566
5446201 | Grupo de modelo:Grup aula:4940566
5446203 | Grupo de modelo:Grup aula:4940566
5446204 | Grupo de modelo:Grup aula:4940566
5446205 | Grupo de modelo:Grup aula:4940566
5446207 | Grupo de modelo:Grup aula:4940566
5446210 | Grupo de modelo:Grup aula:4940566
5446214 | Grupo de modelo:Grup aula:4940822
5446216 | Grupo de modelo:Grup aula:4940822
5446217 | Grupo de modelo:Grup aula:4940822
5446218 | Grupo de modelo:Grup aula:4940822
5446220 | Grupo de modelo:Grup aula:4940822
5446221 | Grupo de modelo:Grup aula:4940822
5446222 | Grupo de modelo:Grup aula:4940822
5446224 | Grupo de modelo:Grup aula:4940822
5446227 | Grupo de modelo:Grup aula:4940822

# IfcMember: Montante rectangular:MC- Fusta- 20x6 cm- Neutre (64)
In: P0- Escola
Type - PredefinedType: MULLION; Material: _Fusta massisa- T1
Type - Pset_MemberCommon - IsExternal: no
Pset_MemberCommon - Reference: MC- Fusta- 20x6 cm- Neutre
Pset_QuantityTakeOff - Reference: MC- Fusta- 20x6 cm- Neutre
Name (Montante rectangular:MC- Fusta- 20x6 cm- Neutre:...) | Span (m) | Group
338960 | 2.505 | Pset_MemberCommon - IsExternal: yes
338961 | 2.505 | Pset_MemberCommon - IsExternal: yes
338986 | 1.03 | Pset_MemberCommon - IsExternal: yes
364843 | 2.505 | Pset_MemberCommon - IsExternal: yes
365011 | 1 | Pset_MemberCommon - IsExternal: yes
365012 | 2.505 | Pset_MemberCommon - IsExternal: yes
365281 | 2.505 | Pset_MemberCommon - IsExternal: yes
365323 | 1 | Pset_MemberCommon - IsExternal: yes
365324 | 2.505 | Pset_MemberCommon - IsExternal: yes
365390 | 1 | Pset_MemberCommon - IsExternal: yes
365719 | 2.505 | Pset_MemberCommon - IsExternal: yes
5444383 | 0.94 | Pset_MemberCommon - IsExternal: yes
5444391 | 0.94 | Pset_MemberCommon - IsExternal: yes
5893621 | 0.94 | Pset_MemberCommon - IsExternal: yes
361763 | 1
361847 | 2.505
361926 | 1
361970 | 2.505
362067 | 1
362068 | 2.505
362097 | 2.505
362151 | 1
362219 | 2.505
362275 | 1
362276 | 2.505
5444741 | 0.94
5444742 | 0.94
5444747 | 0.94
462853 | 0.805 | Grupo de modelo:Grup aula:4934097
462854 | 2.505 | Grupo de modelo:Grup aula:4934097
462855 | 2.505 | Grupo de modelo:Grup aula:4934097
462862 | 1 | Grupo de modelo:Grup aula:4934097
462878 | 1 | Grupo de modelo:Grup aula:4934097
462890 | 1 | Grupo de modelo:Grup aula:4934097
462898 | 1 | Grupo de modelo:Grup aula:4934097
462902 | 1 | Grupo de modelo:Grup aula:4934097
462903 | 2.505 | Grupo de modelo:Grup aula:4934097
462906 | 1 | Grupo de modelo:Grup aula:4934097
462907 | 2.505 | Grupo de modelo:Grup aula:4934097
5446178 | 0.939998 | Grupo de modelo:Grup aula:4934097
4940461 | 0.805 | Grupo de modelo:Grup aula:4940566
4940462 | 2.505 | Grupo de modelo:Grup aula:4940566
4940463 | 2.505 | Grupo de modelo:Grup aula:4940566
4940470 | 1 | Grupo de modelo:Grup aula:4940566
4940486 | 1 | Grupo de modelo:Grup aula:4940566
4940498 | 1 | Grupo de modelo:Grup aula:4940566
4940506 | 1 | Grupo de modelo:Grup aula:4940566
4940510 | 1 | Grupo de modelo:Grup aula:4940566
4940511 | 2.505 | Grupo de modelo:Grup aula:4940566
4940514 | 1 | Grupo de modelo:Grup aula:4940566
4940515 | 2.505 | Grupo de modelo:Grup aula:4940566
5446195 | 0.939998 | Grupo de modelo:Grup aula:4940566
4940717 | 0.805 | Grupo de modelo:Grup aula:4940822
4940718 | 2.505 | Grupo de modelo:Grup aula:4940822
4940719 | 2.505 | Grupo de modelo:Grup aula:4940822
4940726 | 1 | Grupo de modelo:Grup aula:4940822
4940742 | 1 | Grupo de modelo:Grup aula:4940822
4940754 | 1 | Grupo de modelo:Grup aula:4940822
4940762 | 1 | Grupo de modelo:Grup aula:4940822
4940766 | 1 | Grupo de modelo:Grup aula:4940822
4940767 | 2.505 | Grupo de modelo:Grup aula:4940822
4940770 | 1 | Grupo de modelo:Grup aula:4940822
4940771 | 2.505 | Grupo de modelo:Grup aula:4940822
5446212 | 0.939998 | Grupo de modelo:Grup aula:4940822

# IfcMember: Montante rectangular:MC- Fusta- 21,4x7 cm- Esquerra- Bany infantil (6)
In: P0- Escola
Type - PredefinedType: MULLION; Material: _Fusta massisa- T1
Type - Pset_MemberCommon - IsExternal: no
Pset_MemberCommon - Reference: MC- Fusta- 21,4x7 cm- Esquerra- Bany infantil
Pset_QuantityTakeOff - Reference: MC- Fusta- 21,4x7 cm- Esquerra- Bany infantil
Name (Montante rectangular:MC- Fusta- 21,4x7 cm- Esquerra- Bany infantil:...) | Span (m) | Group
2141150 | 0.345 | Grupo de modelo:BANY1:2141168 | Pset_MemberCommon - IsExternal: yes
2263437 | 1.305 | Grupo de modelo:BANY1:2141168 | Pset_MemberCommon - IsExternal: yes
2334000 | 0.345 | Grupo de modelo:BANY1:2334016
2334023 | 1.305 | Grupo de modelo:BANY1:2334016
2334650 | 0.345 | Grupo de modelo:BANY1:2334666
2334673 | 1.305 | Grupo de modelo:BANY1:2334666

# IfcMember: Montante rectangular:MC- Fusta- 21,4x7 cm- Neutre- Bany infantil (12)
In: P0- Escola
Type - PredefinedType: MULLION; Material: _Fusta massisa- T1
Type - Pset_MemberCommon - IsExternal: no
Pset_MemberCommon - Reference: MC- Fusta- 21,4x7 cm- Neutre- Bany infantil
Pset_QuantityTakeOff - Reference: MC- Fusta- 21,4x7 cm- Neutre- Bany infantil
Name (Montante rectangular:MC- Fusta- 21,4x7 cm- Neutre- Bany infantil:...) | Span (m) | Group
2141144 | 0.785 | Grupo de modelo:BANY1:2141168 | Pset_MemberCommon - IsExternal: yes
2141149 | 0.785 | Grupo de modelo:BANY1:2141168 | Pset_MemberCommon - IsExternal: yes
2141153 | 0.455 | Grupo de modelo:BANY1:2141168 | Pset_MemberCommon - IsExternal: yes
2141158 | 1.801 | Grupo de modelo:BANY1:2141168 | Pset_MemberCommon - IsExternal: yes
2333996 | 0.785 | Grupo de modelo:BANY1:2334016
2333999 | 0.785 | Grupo de modelo:BANY1:2334016
2334002 | 0.455 | Grupo de modelo:BANY1:2334016
2334006 | 1.801 | Grupo de modelo:BANY1:2334016
2334646 | 0.785 | Grupo de modelo:BANY1:2334666
2334649 | 0.785 | Grupo de modelo:BANY1:2334666
2334652 | 0.455 | Grupo de modelo:BANY1:2334666
2334656 | 1.801 | Grupo de modelo:BANY1:2334666

# IfcMember: Montante rectangular:MC- Fusta- 28x3 cm- Biblio- Dreta (4)
In: P0- Escola
Type - PredefinedType: MULLION; Material: _Fusta massisa- T1
Type - Pset_MemberCommon - IsExternal: no
Pset_MemberCommon - Reference: MC- Fusta- 28x3 cm- Biblio- Dreta
Pset_QuantityTakeOff - Reference: MC- Fusta- 28x3 cm- Biblio- Dreta
Name (Montante rectangular:MC- Fusta- 28x3 cm- Biblio- Dreta:...) | Span (m)
4913484 | 6.652 | Pset_MemberCommon - IsExternal: yes
4913485 | 1.15 | Pset_MemberCommon - IsExternal: yes
4914958 | 1.402
4914959 | 1.15

# IfcMember: Montante rectangular:MC- Fusta- 28x3 cm- Biblio- Esquerra (2)
In: P0- Escola
Type - PredefinedType: MULLION; Material: _Fusta massisa- T1
Type - Pset_MemberCommon - IsExternal: no
Pset_MemberCommon - Reference: MC- Fusta- 28x3 cm- Biblio- Esquerra
Pset_QuantityTakeOff - Reference: MC- Fusta- 28x3 cm- Biblio- Esquerra
Name (Montante rectangular:MC- Fusta- 28x3 cm- Biblio- Esquerra:...) | Span (m)
4913487 | 6.652 | Pset_MemberCommon - IsExternal: yes
4915056 | 1.402

# IfcMember: Montante rectangular:MC- Fusta- 34x3 cm- Fa Pista- Pota taula (14)
In: P0- Escola
Type - PredefinedType: MULLION; Material: _Fusta massisa- T1
Type - Pset_MemberCommon - IsExternal: no
Pset_MemberCommon - Reference: MC- Fusta- 34x3 cm- Fa Pista- Pota taula; Span: 0.655 m
Pset_QuantityTakeOff - Reference: MC- Fusta- 34x3 cm- Fa Pista- Pota taula
Name (Montante rectangular:MC- Fusta- 34x3 cm- Fa Pista- Pota taula:...) | IsExternal
4892064 | yes
4892070 | yes
4892076 | yes
4892082 | yes
4892088 | yes
4892094 | yes
4892100 | yes
4892106 | yes
4892112 | yes
4892118 | yes
4892124 | yes
4928481
4928487
4928493

# IfcMember: Montante rectangular:MC- Fusta- 34x3 cm- Fa Pista- Remat Inferior (20)
In: P0- Escola
Type - PredefinedType: MULLION; Material: _Fusta massisa- T1
Type - Pset_MemberCommon - IsExternal: no
Pset_MemberCommon - Reference: MC- Fusta- 34x3 cm- Fa Pista- Remat Inferior
Pset_QuantityTakeOff - Reference: MC- Fusta- 34x3 cm- Fa Pista- Remat Inferior
Name (Montante rectangular:MC- Fusta- 34x3 cm- Fa Pista- Remat Inferior:...) | Span (m)
4865599 | 3.205 | Pset_MemberCommon - IsExternal: yes
4868012 | 7.89446
4892058 | 2.161
4892063 | 2.117
4892069 | 2.117
4892075 | 2.09434
4892081 | 2.117
4892087 | 2.117
4892093 | 2.117
4892099 | 2.117
4892105 | 2.117
4892111 | 2.117
4892117 | 2.117
4892123 | 2.117
4928480 | 2.117
4928486 | 2.117
4928492 | 2.09434
4928634 | 1.63166
4928711 | 0.655
4928712 | 1.85

# IfcMember: Montante rectangular:MC- Fusta- 34x3 cm- Fa Pista- Remat Superior (18)
In: P0- Escola
Type - PredefinedType: MULLION; Material: _Fusta massisa- T1
Type - Pset_MemberCommon - IsExternal: no
Pset_MemberCommon - Reference: MC- Fusta- 34x3 cm- Fa Pista- Remat Superior
Pset_QuantityTakeOff - Reference: MC- Fusta- 34x3 cm- Fa Pista- Remat Superior
Name (Montante rectangular:MC- Fusta- 34x3 cm- Fa Pista- Remat Superior:...) | Span (m)
4866917 | 3.205 | Pset_MemberCommon - IsExternal: yes
4868014 | 7.89446
4892052 | 2.09434
4892062 | 2.117
4892068 | 2.117
4892074 | 2.117
4892080 | 2.117
4892086 | 2.117
4892092 | 2.117
4892098 | 2.117
4892104 | 2.117
4892110 | 2.117
4892116 | 2.117
4892122 | 2.161
4928470 | 2.09434
4928479 | 1.66166
4928485 | 2.117
4928491 | 2.117

# IfcMember: Montante rectangular:MC- Fusta- 34x3 cm- Fa Pista- Remat dreta (3)
In: P0- Escola
Type - PredefinedType: MULLION; Material: _Fusta massisa- T1
Type - Pset_MemberCommon - IsExternal: no
Pset_MemberCommon - Reference: MC- Fusta- 34x3 cm- Fa Pista- Remat dreta; Span: 1.91 m
Pset_QuantityTakeOff - Reference: MC- Fusta- 34x3 cm- Fa Pista- Remat dreta
Name (Montante rectangular:MC- Fusta- 34x3 cm- Fa Pista- Remat dreta:...)
4867074 | Pset_MemberCommon - IsExternal: yes
4892056
4928474

# IfcMember: Montante rectangular:MC- Fusta- 34x3 cm- Fa Pista- Remat esquerra (3)
In: P0- Escola
Type - PredefinedType: MULLION; Material: _Fusta massisa- T1
Type - Pset_MemberCommon - IsExternal: no
Pset_MemberCommon - Reference: MC- Fusta- 34x3 cm- Fa Pista- Remat esquerra
Pset_QuantityTakeOff - Reference: MC- Fusta- 34x3 cm- Fa Pista- Remat esquerra
Name (Montante rectangular:MC- Fusta- 34x3 cm- Fa Pista- Remat esquerra:...) | IsExternal | Span (m) | Group
3283578 | yes | 1 | Grupo de modelo:Fusteries interior (elementos excluidos):3262893
3283638 | yes | 1.505 | Grupo de modelo:Fusteries interior (elementos excluidos):3262893
4866817 |  | 1.82

# IfcMember: Montante rectangular:MC- Fusta- 35x3 cm- Centre (123)
In: P0- Escola
Type - PredefinedType: MULLION; Material: _Fusta massisa- T1
Type - Pset_MemberCommon - IsExternal: no
Pset_MemberCommon - Reference: MC- Fusta- 35x3 cm- Centre
Pset_QuantityTakeOff - Reference: MC- Fusta- 35x3 cm- Centre
Name (Montante rectangular:MC- Fusta- 35x3 cm- Centre:...) | Span (m) | Group
2564818 | 2.54 | Pset_MemberCommon - IsExternal: yes
2564822 | 2.54 | Pset_MemberCommon - IsExternal: yes
2564826 | 2.54 | Pset_MemberCommon - IsExternal: yes
2564830 | 2.54 | Pset_MemberCommon - IsExternal: yes
2564834 | 2.54 | Pset_MemberCommon - IsExternal: yes
2564838 | 2.54 | Pset_MemberCommon - IsExternal: yes
2564842 | 2.54 | Pset_MemberCommon - IsExternal: yes
2564846 | 2.54 | Pset_MemberCommon - IsExternal: yes
2564850 | 2.54 | Pset_MemberCommon - IsExternal: yes
2564854 | 2.54 | Pset_MemberCommon - IsExternal: yes
2564858 | 2.54 | Pset_MemberCommon - IsExternal: yes
2564862 | 2.54 | Pset_MemberCommon - IsExternal: yes
2564866 | 2.54 | Pset_MemberCommon - IsExternal: yes
2564870 | 2.54 | Pset_MemberCommon - IsExternal: yes
2564874 | 2.54 | Pset_MemberCommon - IsExternal: yes
2564878 | 2.54 | Pset_MemberCommon - IsExternal: yes
2564882 | 2.54 | Pset_MemberCommon - IsExternal: yes
2564886 | 2.54 | Pset_MemberCommon - IsExternal: yes
2564890 | 2.54 | Pset_MemberCommon - IsExternal: yes
2564894 | 2.54 | Pset_MemberCommon - IsExternal: yes
2564898 | 2.54 | Pset_MemberCommon - IsExternal: yes
3277914 | 2.505 | Grupo de modelo:Fusteries interior (elementos excluidos):3262893
3277918 | 2.505 | Grupo de modelo:Fusteries interior (elementos excluidos):3262893
3277934 | 2.505 | Grupo de modelo:Fusteries interior (elementos excluidos):3262893
3277938 | 2.505 | Grupo de modelo:Fusteries interior (elementos excluidos):3262893
3277942 | 2.505 | Grupo de modelo:Fusteries interior (elementos excluidos):3262893
3277954 | 2.505 | Grupo de modelo:Fusteries interior (elementos excluidos):3262893
3277958 | 2.505 | Grupo de modelo:Fusteries interior (elementos excluidos):3262893
3277962 | 2.505 | Grupo de modelo:Fusteries interior (elementos excluidos):3262893
3283218 | 1 | Grupo de modelo:Fusteries interior (elementos excluidos):3262893
3283222 | 1 | Grupo de modelo:Fusteries interior (elementos excluidos):3262893
3283226 | 1 | Grupo de modelo:Fusteries interior (elementos excluidos):3262893
3283238 | 1 | Grupo de modelo:Fusteries interior (elementos excluidos):3262893
3283242 | 1 | Grupo de modelo:Fusteries interior (elementos excluidos):3262893
3283246 | 1 | Grupo de modelo:Fusteries interior (elementos excluidos):3262893
3283258 | 1 | Grupo de modelo:Fusteries interior (elementos excluidos):3262893
3283262 | 1 | Grupo de modelo:Fusteries interior (elementos excluidos):3262893
3283266 | 1 | Grupo de modelo:Fusteries interior (elementos excluidos):3262893
3283305 | 1.505 | Grupo de modelo:Fusteries interior (elementos excluidos):3262893
3283306 | 1.505 | Grupo de modelo:Fusteries interior (elementos excluidos):3262893
3283307 | 1.505 | Grupo de modelo:Fusteries interior (elementos excluidos):3262893
3283310 | 1.505 | Grupo de modelo:Fusteries interior (elementos excluidos):3262893
3283311 | 1.505 | Grupo de modelo:Fusteries interior (elementos excluidos):3262893
3283312 | 1.505 | Grupo de modelo:Fusteries interior (elementos excluidos):3262893
3283315 | 1.505 | Grupo de modelo:Fusteries interior (elementos excluidos):3262893
3283316 | 1.505 | Grupo de modelo:Fusteries interior (elementos excluidos):3262893
3283317 | 1.505 | Grupo de modelo:Fusteries interior (elementos excluidos):3262893
3283542 | 1 | Grupo de modelo:Fusteries interior (elementos excluidos):3262893
3283546 | 1 | Grupo de modelo:Fusteries interior (elementos excluidos):3262893
3283550 | 1 | Grupo de modelo:Fusteries interior (elementos excluidos):3262893
3283562 | 1 | Grupo de modelo:Fusteries interior (elementos excluidos):3262893
3283566 | 1 | Grupo de modelo:Fusteries interior (elementos excluidos):3262893
3283570 | 1 | Grupo de modelo:Fusteries interior (elementos excluidos):3262893
3283582 | 1 | Grupo de modelo:Fusteries interior (elementos excluidos):3262893
3283586 | 1 | Grupo de modelo:Fusteries interior (elementos excluidos):3262893
3283590 | 1 | Grupo de modelo:Fusteries interior (elementos excluidos):3262893
3283629 | 1.505 | Grupo de modelo:Fusteries interior (elementos excluidos):3262893
3283630 | 1.505 | Grupo de modelo:Fusteries interior (elementos excluidos):3262893
3283631 | 1.505 | Grupo de modelo:Fusteries interior (elementos excluidos):3262893
3283634 | 1.505 | Grupo de modelo:Fusteries interior (elementos excluidos):3262893
3283635 | 1.505 | Grupo de modelo:Fusteries interior (elementos excluidos):3262893
3283636 | 1.505 | Grupo de modelo:Fusteries interior (elementos excluidos):3262893
3283639 | 1.505 | Grupo de modelo:Fusteries interior (elementos excluidos):3262893
3283640 | 1.505 | Grupo de modelo:Fusteries interior (elementos excluidos):3262893
3283641 | 1.505 | Grupo de modelo:Fusteries interior (elementos excluidos):3262893
3294840 | 1 | Grupo de modelo:Fusteries interior (elementos excluidos):3262893
3294841 | 1.505 | Grupo de modelo:Fusteries interior (elementos excluidos):3262893
3296085 | 1 | Grupo de modelo:Fusteries interior (elementos excluidos):3262893
3296086 | 1.505 | Grupo de modelo:Fusteries interior (elementos excluidos):3262893
3296153 | 1 | Grupo de modelo:Fusteries interior (elementos excluidos):3262893
3296154 | 1.505 | Grupo de modelo:Fusteries interior (elementos excluidos):3262893
5256162 | 2.505 | Grupo de modelo:Fusteries interior (elementos excluidos):3262893
5256166 | 2.505 | Grupo de modelo:Fusteries interior (elementos excluidos):3262893
5256182 | 2.505 | Grupo de modelo:Fusteries interior (elementos excluidos):3262893
5256186 | 2.505 | Grupo de modelo:Fusteries interior (elementos excluidos):3262893
5256190 | 2.505 | Grupo de modelo:Fusteries interior (elementos excluidos):3262893
5256202 | 2.505 | Grupo de modelo:Fusteries interior (elementos excluidos):3262893
5256206 | 2.505 | Grupo de modelo:Fusteries interior (elementos excluidos):3262893
5256210 | 2.505 | Grupo de modelo:Fusteries interior (elementos excluidos):3262893
5256249 | 2.505 | Grupo de modelo:Fusteries interior (elementos excluidos):3262893
5256253 | 2.505 | Grupo de modelo:Fusteries interior (elementos excluidos):3262893
5256269 | 2.505 | Grupo de modelo:Fusteries interior (elementos excluidos):3262893
5256273 | 2.505 | Grupo de modelo:Fusteries interior (elementos excluidos):3262893
5256277 | 2.505 | Grupo de modelo:Fusteries interior (elementos excluidos):3262893
5256289 | 2.505 | Grupo de modelo:Fusteries interior (elementos excluidos):3262893
5256293 | 2.505 | Grupo de modelo:Fusteries interior (elementos excluidos):3262893
5256297 | 2.505 | Grupo de modelo:Fusteries interior (elementos excluidos):3262893
5393547 | 1 | Grupo de modelo:Fusteries interior (elementos excluidos):3262893
5393551 | 1 | Grupo de modelo:Fusteries interior (elementos excluidos):3262893
5393555 | 1 | Grupo de modelo:Fusteries interior (elementos excluidos):3262893
5393567 | 1 | Grupo de modelo:Fusteries interior (elementos excluidos):3262893
5393571 | 1 | Grupo de modelo:Fusteries interior (elementos excluidos):3262893
5393575 | 1 | Grupo de modelo:Fusteries interior (elementos excluidos):3262893
5393587 | 1 | Grupo de modelo:Fusteries interior (elementos excluidos):3262893
5393591 | 1 | Grupo de modelo:Fusteries interior (elementos excluidos):3262893
5393595 | 1 | Grupo de modelo:Fusteries interior (elementos excluidos):3262893
5393634 | 1.505 | Grupo de modelo:Fusteries interior (elementos excluidos):3262893
5393635 | 1.505 | Grupo de modelo:Fusteries interior (elementos excluidos):3262893
5393636 | 1.505 | Grupo de modelo:Fusteries interior (elementos excluidos):3262893
5393639 | 1.505 | Grupo de modelo:Fusteries interior (elementos excluidos):3262893
5393640 | 1.505 | Grupo de modelo:Fusteries interior (elementos excluidos):3262893
5393641 | 1.505 | Grupo de modelo:Fusteries interior (elementos excluidos):3262893
5393644 | 1.505 | Grupo de modelo:Fusteries interior (elementos excluidos):3262893
5393645 | 1.505 | Grupo de modelo:Fusteries interior (elementos excluidos):3262893
5393646 | 1.505 | Grupo de modelo:Fusteries interior (elementos excluidos):3262893
5405271 | 1 | Grupo de modelo:Fusteries interior (elementos excluidos):3262893
5405275 | 1 | Grupo de modelo:Fusteries interior (elementos excluidos):3262893
5405279 | 1 | Grupo de modelo:Fusteries interior (elementos excluidos):3262893
5405291 | 1 | Grupo de modelo:Fusteries interior (elementos excluidos):3262893
5405295 | 1 | Grupo de modelo:Fusteries interior (elementos excluidos):3262893
5405299 | 1 | Grupo de modelo:Fusteries interior (elementos excluidos):3262893
5405311 | 1 | Grupo de modelo:Fusteries interior (elementos excluidos):3262893
5405315 | 1 | Grupo de modelo:Fusteries interior (elementos excluidos):3262893
5405319 | 1 | Grupo de modelo:Fusteries interior (elementos excluidos):3262893
5405358 | 1.505 | Grupo de modelo:Fusteries interior (elementos excluidos):3262893
5405359 | 1.505 | Grupo de modelo:Fusteries interior (elementos excluidos):3262893
5405360 | 1.505 | Grupo de modelo:Fusteries interior (elementos excluidos):3262893
5405363 | 1.505 | Grupo de modelo:Fusteries interior (elementos excluidos):3262893
5405364 | 1.505 | Grupo de modelo:Fusteries interior (elementos excluidos):3262893
5405365 | 1.505 | Grupo de modelo:Fusteries interior (elementos excluidos):3262893
5405368 | 1.505 | Grupo de modelo:Fusteries interior (elementos excluidos):3262893
5405369 | 1.505 | Grupo de modelo:Fusteries interior (elementos excluidos):3262893
5405370 | 1.505 | Grupo de modelo:Fusteries interior (elementos excluidos):3262893

# IfcMember: Montante rectangular:MC- Fusta- 35x3 cm- Pati aules- Prestatge (52)
In: P0- Escola
Type - PredefinedType: MULLION; Material: _Fusta massisa- T1
Type - Pset_MemberCommon - IsExternal: no
Pset_MemberCommon - Reference: MC- Fusta- 35x3 cm- Pati aules- Prestatge
Pset_QuantityTakeOff - Reference: MC- Fusta- 35x3 cm- Pati aules- Prestatge
Group: Grupo de modelo:Fusteries interior (elementos excluidos):3262893
Name (Montante rectangular:MC- Fusta- 35x3 cm- Pati aules- Prestatge:...) | Span (m)
3283293 | 0.955 | Pset_MemberCommon - IsExternal: yes
3283294 | 0.97 | Pset_MemberCommon - IsExternal: yes
3283295 | 0.97 | Pset_MemberCommon - IsExternal: yes
3283296 | 0.97 | Pset_MemberCommon - IsExternal: yes
3283297 | 0.97 | Pset_MemberCommon - IsExternal: yes
3283298 | 0.97 | Pset_MemberCommon - IsExternal: yes
3283299 | 0.97 | Pset_MemberCommon - IsExternal: yes
3283300 | 0.97 | Pset_MemberCommon - IsExternal: yes
3283301 | 0.97 | Pset_MemberCommon - IsExternal: yes
3283302 | 0.97 | Pset_MemberCommon - IsExternal: yes
3283303 | 0.97 | Pset_MemberCommon - IsExternal: yes
3283304 | 0.97 | Pset_MemberCommon - IsExternal: yes
3283617 | 0.955
3283618 | 0.97
3283619 | 0.97
3283620 | 0.97
3283621 | 0.97
3283622 | 0.97
3283623 | 0.97
3283624 | 0.97
3283625 | 0.97
3283626 | 0.97
3283627 | 0.97
3283628 | 0.97
3294839 | 0.97
3296084 | 0.97
3296152 | 0.855
3296437 | 0.97
5393622 | 0.955
5393623 | 0.97
5393624 | 0.97
5393625 | 0.97
5393626 | 0.97
5393627 | 0.97
5393628 | 0.97
5393629 | 0.97
5393630 | 0.97
5393631 | 0.97
5393632 | 0.97
5393633 | 0.97
5405346 | 0.955
5405347 | 0.97
5405348 | 0.97
5405349 | 0.97
5405350 | 0.97
5405351 | 0.97
5405352 | 0.97
5405353 | 0.97
5405354 | 0.97
5405355 | 0.97
5405356 | 0.97
5405357 | 0.97

# IfcMember: Montante rectangular:MC- Fusta- 35x3 cm- Pati aules- Remat dreta (51)
In: P0- Escola
Type - PredefinedType: MULLION; Material: _Fusta massisa- T1
Type - Pset_MemberCommon - IsExternal: no
Pset_MemberCommon - Reference: MC- Fusta- 35x3 cm- Pati aules- Remat dreta
Pset_QuantityTakeOff - Reference: MC- Fusta- 35x3 cm- Pati aules- Remat dreta
Name (Montante rectangular:MC- Fusta- 35x3 cm- Pati aules- Remat dreta:...) | Span (m) | Group
2564813 | 2.54 | Pset_MemberCommon - IsExternal: yes
3277922 | 2.505 | Grupo de modelo:Fusteries interior (elementos excluidos):3262893
3277926 | 2.505 | Grupo de modelo:Fusteries interior (elementos excluidos):3262893
3277946 | 2.505 | Grupo de modelo:Fusteries interior (elementos excluidos):3262893
3277966 | 2.505 | Grupo de modelo:Fusteries interior (elementos excluidos):3262893
5408390 | 2.505 | Grupo de modelo:Fusteries interior (elementos excluidos):3262893
3299160 | 2.565 | Grupo de modelo:Fusteries interior (elementos excluidos):3262893
3283230 | 1 | Grupo de modelo:Fusteries interior (elementos excluidos):3262893
3283250 | 1 | Grupo de modelo:Fusteries interior (elementos excluidos):3262893
3283270 | 1 | Grupo de modelo:Fusteries interior (elementos excluidos):3262893
3283308 | 1.505 | Grupo de modelo:Fusteries interior (elementos excluidos):3262893
3283313 | 1.505 | Grupo de modelo:Fusteries interior (elementos excluidos):3262893
3283318 | 1.505 | Grupo de modelo:Fusteries interior (elementos excluidos):3262893
3283554 | 1 | Grupo de modelo:Fusteries interior (elementos excluidos):3262893
3283574 | 1 | Grupo de modelo:Fusteries interior (elementos excluidos):3262893
3283594 | 1 | Grupo de modelo:Fusteries interior (elementos excluidos):3262893
3283632 | 1.505 | Grupo de modelo:Fusteries interior (elementos excluidos):3262893
3283637 | 1.505 | Grupo de modelo:Fusteries interior (elementos excluidos):3262893
3283642 | 1.505 | Grupo de modelo:Fusteries interior (elementos excluidos):3262893
3296408 | 1.505 | Grupo de modelo:Fusteries interior (elementos excluidos):3262893
3296409 | 1 | Grupo de modelo:Fusteries interior (elementos excluidos):3262893
3278122 | 2.505 | Grupo de modelo:Fusteries interior (elementos excluidos):3262893
3298285 | 2.505 | Grupo de modelo:Fusteries interior (elementos excluidos):3262893
3278102 | 2.505 | Grupo de modelo:Fusteries interior (elementos excluidos):3262893
3298509 | 2.505 | Grupo de modelo:Fusteries interior (elementos excluidos):3262893
3298784 | 2.565 | Grupo de modelo:Fusteries interior (elementos excluidos):3262893
3298934 | 2.565 | Grupo de modelo:Fusteries interior (elementos excluidos):3262893
3300293 | 2.565 | Grupo de modelo:Fusteries interior (elementos excluidos):3262893
3299909 | 2.565 | Grupo de modelo:Fusteries interior (elementos excluidos):3262893
5256170 | 2.505 | Grupo de modelo:Fusteries interior (elementos excluidos):3262893
5256174 | 2.505 | Grupo de modelo:Fusteries interior (elementos excluidos):3262893
5256194 | 2.505 | Grupo de modelo:Fusteries interior (elementos excluidos):3262893
5256214 | 2.505 | Grupo de modelo:Fusteries interior (elementos excluidos):3262893
5408287 | 2.505 | Grupo de modelo:Fusteries interior (elementos excluidos):3262893
5256257 | 2.505 | Grupo de modelo:Fusteries interior (elementos excluidos):3262893
5256261 | 2.505 | Grupo de modelo:Fusteries interior (elementos excluidos):3262893
5256281 | 2.505 | Grupo de modelo:Fusteries interior (elementos excluidos):3262893
5256301 | 2.505 | Grupo de modelo:Fusteries interior (elementos excluidos):3262893
5408834 | 2.505 | Grupo de modelo:Fusteries interior (elementos excluidos):3262893
5393559 | 1 | Grupo de modelo:Fusteries interior (elementos excluidos):3262893
5393579 | 1 | Grupo de modelo:Fusteries interior (elementos excluidos):3262893
5393599 | 1 | Grupo de modelo:Fusteries interior (elementos excluidos):3262893
5393637 | 1.505 | Grupo de modelo:Fusteries interior (elementos excluidos):3262893
5393642 | 1.505 | Grupo de modelo:Fusteries interior (elementos excluidos):3262893
5393647 | 1.505 | Grupo de modelo:Fusteries interior (elementos excluidos):3262893
5405283 | 1 | Grupo de modelo:Fusteries interior (elementos excluidos):3262893
5405303 | 1 | Grupo de modelo:Fusteries interior (elementos excluidos):3262893
5405323 | 1 | Grupo de modelo:Fusteries interior (elementos excluidos):3262893
5405361 | 1.505 | Grupo de modelo:Fusteries interior (elementos excluidos):3262893
5405366 | 1.505 | Grupo de modelo:Fusteries interior (elementos excluidos):3262893
5405371 | 1.505 | Grupo de modelo:Fusteries interior (elementos excluidos):3262893

# IfcMember: Montante rectangular:MC- Fusta- 35x3 cm- Pati aules- Remat esquerra (55)
In: P0- Escola
Type - PredefinedType: MULLION; Material: _Fusta massisa- T1
Type - Pset_MemberCommon - IsExternal: no
Pset_MemberCommon - Reference: MC- Fusta- 35x3 cm- Pati aules- Remat esquerra
Pset_QuantityTakeOff - Reference: MC- Fusta- 35x3 cm- Pati aules- Remat esquerra
Name (Montante rectangular:MC- Fusta- 35x3 cm- Pati aules- Remat esquerra:...) | Span (m) | Group
2564814 | 2.54 | Pset_MemberCommon - IsExternal: yes
3277910 | 2.505 | Grupo de modelo:Fusteries interior (elementos excluidos):3262893
3277930 | 2.505 | Grupo de modelo:Fusteries interior (elementos excluidos):3262893
3277950 | 2.505 | Grupo de modelo:Fusteries interior (elementos excluidos):3262893
3277970 | 2.505 | Grupo de modelo:Fusteries interior (elementos excluidos):3262893
4587137 | 2.505 | Grupo de modelo:Fusteries interior (elementos excluidos):3262893
3278066 | 2.565 | Grupo de modelo:Fusteries interior (elementos excluidos):3262893
3283214 | 1.505 | Grupo de modelo:Fusteries interior (elementos excluidos):3262893
3283234 | 1 | Grupo de modelo:Fusteries interior (elementos excluidos):3262893
3283254 | 1 | Grupo de modelo:Fusteries interior (elementos excluidos):3262893
3283274 | 1 | Grupo de modelo:Fusteries interior (elementos excluidos):3262893
3283292 | 1 | Grupo de modelo:Fusteries interior (elementos excluidos):3262893
3283309 | 1.505 | Grupo de modelo:Fusteries interior (elementos excluidos):3262893
3283314 | 1.505 | Grupo de modelo:Fusteries interior (elementos excluidos):3262893
3283319 | 1.505 | Grupo de modelo:Fusteries interior (elementos excluidos):3262893
3283538 | 1.505 | Grupo de modelo:Fusteries interior (elementos excluidos):3262893
3283558 | 1 | Grupo de modelo:Fusteries interior (elementos excluidos):3262893
3283598 | 1 | Grupo de modelo:Fusteries interior (elementos excluidos):3262893
3283616 | 1 | Grupo de modelo:Fusteries interior (elementos excluidos):3262893
3283633 | 1.505 | Grupo de modelo:Fusteries interior (elementos excluidos):3262893
3283643 | 1.505 | Grupo de modelo:Fusteries interior (elementos excluidos):3262893
3278126 | 2.505 | Grupo de modelo:Fusteries interior (elementos excluidos):3262893
3298286 | 2.505 | Grupo de modelo:Fusteries interior (elementos excluidos):3262893
3278106 | 2.505 | Grupo de modelo:Fusteries interior (elementos excluidos):3262893
3298510 | 2.505 | Grupo de modelo:Fusteries interior (elementos excluidos):3262893
3298916 | 2.565 | Grupo de modelo:Fusteries interior (elementos excluidos):3262893
3299161 | 2.565 | Grupo de modelo:Fusteries interior (elementos excluidos):3262893
3299910 | 2.565 | Grupo de modelo:Fusteries interior (elementos excluidos):3262893
3300310 | 2.565 | Grupo de modelo:Fusteries interior (elementos excluidos):3262893
5256158 | 2.505 | Grupo de modelo:Fusteries interior (elementos excluidos):3262893
5256178 | 2.505 | Grupo de modelo:Fusteries interior (elementos excluidos):3262893
5256198 | 2.505 | Grupo de modelo:Fusteries interior (elementos excluidos):3262893
5256218 | 2.505 | Grupo de modelo:Fusteries interior (elementos excluidos):3262893
5256222 | 2.505 | Grupo de modelo:Fusteries interior (elementos excluidos):3262893
5256245 | 2.505 | Grupo de modelo:Fusteries interior (elementos excluidos):3262893
5256265 | 2.505 | Grupo de modelo:Fusteries interior (elementos excluidos):3262893
5256285 | 2.505 | Grupo de modelo:Fusteries interior (elementos excluidos):3262893
5256305 | 2.505 | Grupo de modelo:Fusteries interior (elementos excluidos):3262893
5256309 | 2.505 | Grupo de modelo:Fusteries interior (elementos excluidos):3262893
5393543 | 1.505 | Grupo de modelo:Fusteries interior (elementos excluidos):3262893
5393563 | 1 | Grupo de modelo:Fusteries interior (elementos excluidos):3262893
5393583 | 1 | Grupo de modelo:Fusteries interior (elementos excluidos):3262893
5393603 | 1 | Grupo de modelo:Fusteries interior (elementos excluidos):3262893
5393621 | 1 | Grupo de modelo:Fusteries interior (elementos excluidos):3262893
5393638 | 1.505 | Grupo de modelo:Fusteries interior (elementos excluidos):3262893
5393643 | 1.505 | Grupo de modelo:Fusteries interior (elementos excluidos):3262893
5393648 | 1.505 | Grupo de modelo:Fusteries interior (elementos excluidos):3262893
5405267 | 1.505 | Grupo de modelo:Fusteries interior (elementos excluidos):3262893
5405287 | 1 | Grupo de modelo:Fusteries interior (elementos excluidos):3262893
5405307 | 1 | Grupo de modelo:Fusteries interior (elementos excluidos):3262893
5405327 | 1 | Grupo de modelo:Fusteries interior (elementos excluidos):3262893
5405345 | 1 | Grupo de modelo:Fusteries interior (elementos excluidos):3262893
5405362 | 1.505 | Grupo de modelo:Fusteries interior (elementos excluidos):3262893
5405367 | 1.505 | Grupo de modelo:Fusteries interior (elementos excluidos):3262893
5405372 | 1.505 | Grupo de modelo:Fusteries interior (elementos excluidos):3262893

# IfcMember: Montante rectangular:MC- Fusta- 35x3 cm- Pati aules- Remat superior (134)
In: P0- Escola
Type - PredefinedType: MULLION; Material: _Fusta massisa- T1
Type - Pset_MemberCommon - IsExternal: no
Pset_MemberCommon - Reference: MC- Fusta- 35x3 cm- Pati aules- Remat superior
Pset_QuantityTakeOff - Reference: MC- Fusta- 35x3 cm- Pati aules- Remat superior
Name (Montante rectangular:MC- Fusta- 35x3 cm- Pati aules- Remat superior:...) | Span (m) | Group
2564812 | 0.985 | Pset_MemberCommon - IsExternal: yes
2564817 | 1 | Pset_MemberCommon - IsExternal: yes
2564821 | 1 | Pset_MemberCommon - IsExternal: yes
2564825 | 1 | Pset_MemberCommon - IsExternal: yes
2564829 | 1 | Pset_MemberCommon - IsExternal: yes
2564833 | 1 | Pset_MemberCommon - IsExternal: yes
2564837 | 1 | Pset_MemberCommon - IsExternal: yes
2564841 | 2 | Pset_MemberCommon - IsExternal: yes
2564845 | 1 | Pset_MemberCommon - IsExternal: yes
2564849 | 1 | Pset_MemberCommon - IsExternal: yes
2564853 | 1 | Pset_MemberCommon - IsExternal: yes
2564857 | 1 | Pset_MemberCommon - IsExternal: yes
2564861 | 1 | Pset_MemberCommon - IsExternal: yes
2564865 | 1 | Pset_MemberCommon - IsExternal: yes
2564869 | 2 | Pset_MemberCommon - IsExternal: yes
2564873 | 1 | Pset_MemberCommon - IsExternal: yes
2564877 | 1 | Pset_MemberCommon - IsExternal: yes
2564881 | 1 | Pset_MemberCommon - IsExternal: yes
2564885 | 1 | Pset_MemberCommon - IsExternal: yes
2564889 | 1 | Pset_MemberCommon - IsExternal: yes
2564893 | 1 | Pset_MemberCommon - IsExternal: yes
2564897 | 0.6275 | Pset_MemberCommon - IsExternal: yes
3277909 | 0.537998 | Grupo de modelo:Fusteries interior (elementos excluidos):3262893
3277913 | 1.01 | Grupo de modelo:Fusteries interior (elementos excluidos):3262893
3277917 | 1 | Grupo de modelo:Fusteries interior (elementos excluidos):3262893
3277921 | 1 | Grupo de modelo:Fusteries interior (elementos excluidos):3262893
3277925 | 0.7 | Grupo de modelo:Fusteries interior (elementos excluidos):3262893
3277933 | 1 | Grupo de modelo:Fusteries interior (elementos excluidos):3262893
3277937 | 1 | Grupo de modelo:Fusteries interior (elementos excluidos):3262893
3277941 | 1 | Grupo de modelo:Fusteries interior (elementos excluidos):3262893
3277945 | 1 | Grupo de modelo:Fusteries interior (elementos excluidos):3262893
3277953 | 1 | Grupo de modelo:Fusteries interior (elementos excluidos):3262893
3277957 | 1 | Grupo de modelo:Fusteries interior (elementos excluidos):3262893
3277961 | 1 | Grupo de modelo:Fusteries interior (elementos excluidos):3262893
3277965 | 1 | Grupo de modelo:Fusteries interior (elementos excluidos):3262893
4587136 | 0.3 | Grupo de modelo:Fusteries interior (elementos excluidos):3262893
3299228 | 1.93 | Grupo de modelo:Fusteries interior (elementos excluidos):3262893
3283213 | 1.465 | Grupo de modelo:Fusteries interior (elementos excluidos):3262893
3283217 | 1 | Grupo de modelo:Fusteries interior (elementos excluidos):3262893
3283221 | 1 | Grupo de modelo:Fusteries interior (elementos excluidos):3262893
3283225 | 1 | Grupo de modelo:Fusteries interior (elementos excluidos):3262893
3283229 | 1 | Grupo de modelo:Fusteries interior (elementos excluidos):3262893
3283237 | 1 | Grupo de modelo:Fusteries interior (elementos excluidos):3262893
3283241 | 1 | Grupo de modelo:Fusteries interior (elementos excluidos):3262893
3283245 | 1 | Grupo de modelo:Fusteries interior (elementos excluidos):3262893
3283249 | 1 | Grupo de modelo:Fusteries interior (elementos excluidos):3262893
3283257 | 1 | Grupo de modelo:Fusteries interior (elementos excluidos):3262893
3283261 | 1 | Grupo de modelo:Fusteries interior (elementos excluidos):3262893
3283265 | 1 | Grupo de modelo:Fusteries interior (elementos excluidos):3262893
3283269 | 1 | Grupo de modelo:Fusteries interior (elementos excluidos):3262893
3283537 | 0.9 | Grupo de modelo:Fusteries interior (elementos excluidos):3262893
3283541 | 1 | Grupo de modelo:Fusteries interior (elementos excluidos):3262893
3283545 | 1 | Grupo de modelo:Fusteries interior (elementos excluidos):3262893
3283549 | 1 | Grupo de modelo:Fusteries interior (elementos excluidos):3262893
3283553 | 1 | Grupo de modelo:Fusteries interior (elementos excluidos):3262893
3283561 | 1 | Grupo de modelo:Fusteries interior (elementos excluidos):3262893
3283565 | 1 | Grupo de modelo:Fusteries interior (elementos excluidos):3262893
3283569 | 1 | Grupo de modelo:Fusteries interior (elementos excluidos):3262893
3283573 | 1 | Grupo de modelo:Fusteries interior (elementos excluidos):3262893
3283581 | 1 | Grupo de modelo:Fusteries interior (elementos excluidos):3262893
3283585 | 1 | Grupo de modelo:Fusteries interior (elementos excluidos):3262893
3283589 | 1 | Grupo de modelo:Fusteries interior (elementos excluidos):3262893
3283593 | 1 | Grupo de modelo:Fusteries interior (elementos excluidos):3262893
3294838 | 1 | Grupo de modelo:Fusteries interior (elementos excluidos):3262893
3296083 | 1 | Grupo de modelo:Fusteries interior (elementos excluidos):3262893
3296151 | 1 | Grupo de modelo:Fusteries interior (elementos excluidos):3262893
3278065 | 1.669 | Grupo de modelo:Fusteries interior (elementos excluidos):3262893
3278121 | 2.6415 | Grupo de modelo:Fusteries interior (elementos excluidos):3262893
3278101 | 1.686 | Grupo de modelo:Fusteries interior (elementos excluidos):3262893
3298343 | 0.685 | Grupo de modelo:Fusteries interior (elementos excluidos):3262893
3298448 | 1.98 | Grupo de modelo:Fusteries interior (elementos excluidos):3262893
3298842 | 1.625 | Grupo de modelo:Fusteries interior (elementos excluidos):3262893
3300242 | 4.02 | Grupo de modelo:Fusteries interior (elementos excluidos):3262893
3299898 | 2.972 | Grupo de modelo:Fusteries interior (elementos excluidos):3262893
5256157 | 0.537998 | Grupo de modelo:Fusteries interior (elementos excluidos):3262893
5256161 | 1.01 | Grupo de modelo:Fusteries interior (elementos excluidos):3262893
5256165 | 1 | Grupo de modelo:Fusteries interior (elementos excluidos):3262893
5256169 | 1 | Grupo de modelo:Fusteries interior (elementos excluidos):3262893
5256173 | 0.7 | Grupo de modelo:Fusteries interior (elementos excluidos):3262893
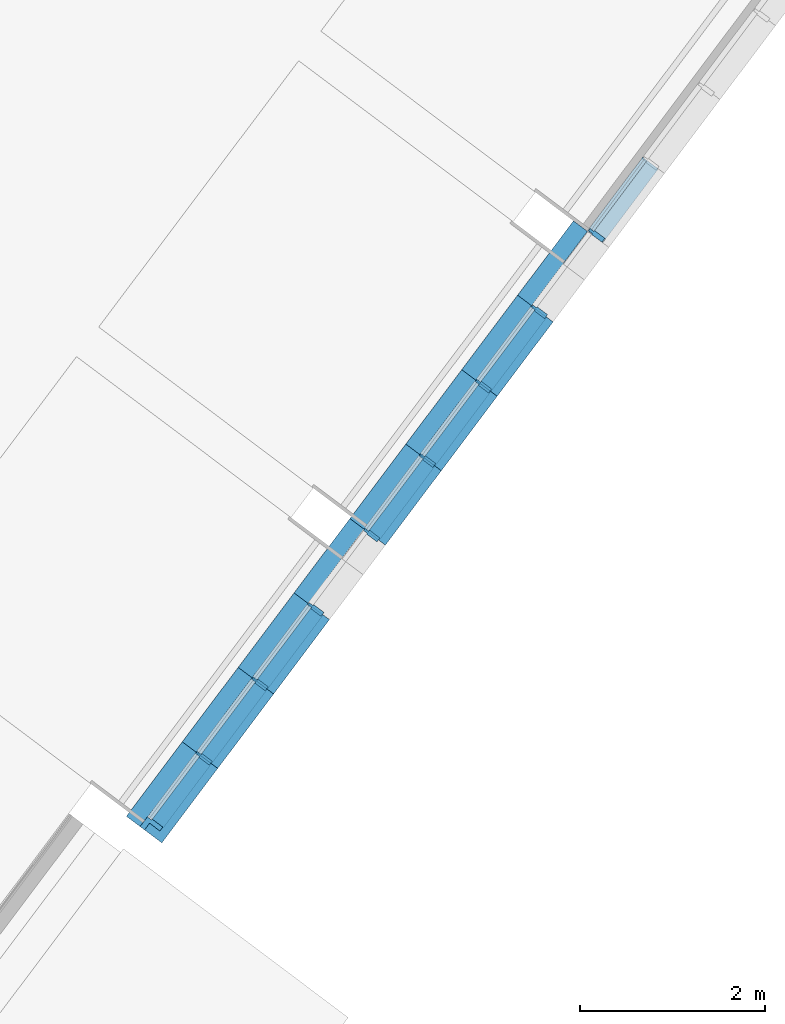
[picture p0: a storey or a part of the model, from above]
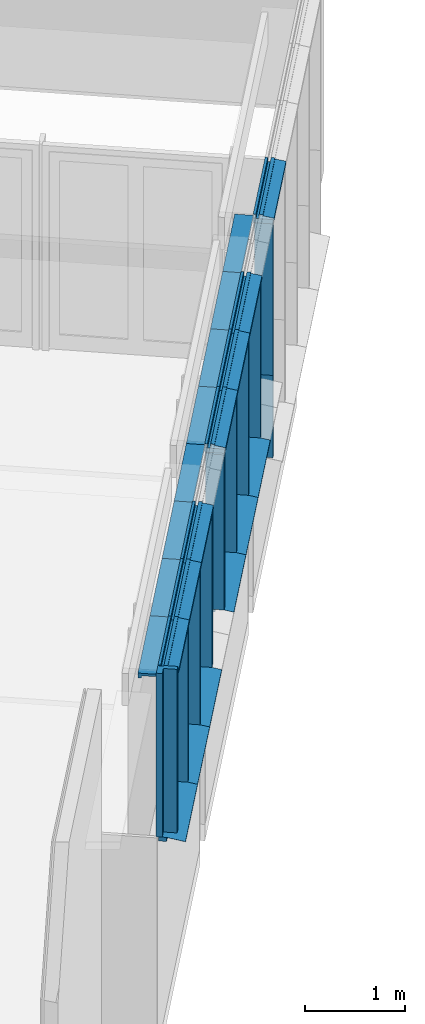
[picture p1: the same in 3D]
Properties of the parts of a building model (IFC2X3), part 4 of 6

# IfcMember: Montante rectangular:MC- Fusta- 35x3 cm- Pati aules- Remat superior (134)
Name (Montante rectangular:MC- Fusta- 35x3 cm- Pati aules- Remat superior:...) | Span (m) | Group
5256181 | 1 | Grupo de modelo:Fusteries interior (elementos excluidos):3262893
5256185 | 1 | Grupo de modelo:Fusteries interior (elementos excluidos):3262893
5256189 | 1 | Grupo de modelo:Fusteries interior (elementos excluidos):3262893
5256193 | 1 | Grupo de modelo:Fusteries interior (elementos excluidos):3262893
5256201 | 1 | Grupo de modelo:Fusteries interior (elementos excluidos):3262893
5256205 | 1 | Grupo de modelo:Fusteries interior (elementos excluidos):3262893
5256209 | 1 | Grupo de modelo:Fusteries interior (elementos excluidos):3262893
5256213 | 1 | Grupo de modelo:Fusteries interior (elementos excluidos):3262893
5256221 | 0.3 | Grupo de modelo:Fusteries interior (elementos excluidos):3262893
5256244 | 0.537998 | Grupo de modelo:Fusteries interior (elementos excluidos):3262893
5256248 | 1.01 | Grupo de modelo:Fusteries interior (elementos excluidos):3262893
5256252 | 1 | Grupo de modelo:Fusteries interior (elementos excluidos):3262893
5256256 | 1 | Grupo de modelo:Fusteries interior (elementos excluidos):3262893
5256260 | 0.7 | Grupo de modelo:Fusteries interior (elementos excluidos):3262893
5256268 | 1 | Grupo de modelo:Fusteries interior (elementos excluidos):3262893
5256272 | 1 | Grupo de modelo:Fusteries interior (elementos excluidos):3262893
5256276 | 1 | Grupo de modelo:Fusteries interior (elementos excluidos):3262893
5256280 | 1 | Grupo de modelo:Fusteries interior (elementos excluidos):3262893
5256288 | 1 | Grupo de modelo:Fusteries interior (elementos excluidos):3262893
5256292 | 1 | Grupo de modelo:Fusteries interior (elementos excluidos):3262893
5256296 | 1 | Grupo de modelo:Fusteries interior (elementos excluidos):3262893
5256300 | 1 | Grupo de modelo:Fusteries interior (elementos excluidos):3262893
5256308 | 0.3 | Grupo de modelo:Fusteries interior (elementos excluidos):3262893
5379426 | 4.39 | Grupo de modelo:Fusteries interior (elementos excluidos):3262893
5379813 | 0.34 | Grupo de modelo:Fusteries interior (elementos excluidos):3262893
5393542 | 1.465 | Grupo de modelo:Fusteries interior (elementos excluidos):3262893
5393546 | 1 | Grupo de modelo:Fusteries interior (elementos excluidos):3262893
5393550 | 1 | Grupo de modelo:Fusteries interior (elementos excluidos):3262893
5393554 | 1 | Grupo de modelo:Fusteries interior (elementos excluidos):3262893
5393558 | 1 | Grupo de modelo:Fusteries interior (elementos excluidos):3262893
5393566 | 1 | Grupo de modelo:Fusteries interior (elementos excluidos):3262893
5393570 | 1 | Grupo de modelo:Fusteries interior (elementos excluidos):3262893
5393574 | 1 | Grupo de modelo:Fusteries interior (elementos excluidos):3262893
5393578 | 1 | Grupo de modelo:Fusteries interior (elementos excluidos):3262893
5393586 | 1 | Grupo de modelo:Fusteries interior (elementos excluidos):3262893
5393590 | 1 | Grupo de modelo:Fusteries interior (elementos excluidos):3262893
5393594 | 1 | Grupo de modelo:Fusteries interior (elementos excluidos):3262893
5393598 | 1 | Grupo de modelo:Fusteries interior (elementos excluidos):3262893
5393651 | 4.39 | Grupo de modelo:Fusteries interior (elementos excluidos):3262893
5393654 | 0.34 | Grupo de modelo:Fusteries interior (elementos excluidos):3262893
5405266 | 1.465 | Grupo de modelo:Fusteries interior (elementos excluidos):3262893
5405270 | 1 | Grupo de modelo:Fusteries interior (elementos excluidos):3262893
5405274 | 1 | Grupo de modelo:Fusteries interior (elementos excluidos):3262893
5405278 | 1 | Grupo de modelo:Fusteries interior (elementos excluidos):3262893
5405282 | 1 | Grupo de modelo:Fusteries interior (elementos excluidos):3262893
5405290 | 1 | Grupo de modelo:Fusteries interior (elementos excluidos):3262893
5405294 | 1 | Grupo de modelo:Fusteries interior (elementos excluidos):3262893
5405298 | 1 | Grupo de modelo:Fusteries interior (elementos excluidos):3262893
5405302 | 1 | Grupo de modelo:Fusteries interior (elementos excluidos):3262893
5405310 | 1 | Grupo de modelo:Fusteries interior (elementos excluidos):3262893
5405314 | 1 | Grupo de modelo:Fusteries interior (elementos excluidos):3262893
5405318 | 1 | Grupo de modelo:Fusteries interior (elementos excluidos):3262893
5405322 | 1 | Grupo de modelo:Fusteries interior (elementos excluidos):3262893
5405375 | 4.39 | Grupo de modelo:Fusteries interior (elementos excluidos):3262893
5405378 | 0.34 | Grupo de modelo:Fusteries interior (elementos excluidos):3262893

# IfcMember: Montante rectangular:MC- Fusta- 35x3 cm- Pati aules- Remat superior pilar (23)
In: P0- Escola
Type - PredefinedType: MULLION; Material: _Fusta massisa- T1
Type - Pset_MemberCommon - IsExternal: no
Pset_MemberCommon - Reference: MC- Fusta- 35x3 cm- Pati aules- Remat superior pilar; Span: 1 m
Pset_QuantityTakeOff - Reference: MC- Fusta- 35x3 cm- Pati aules- Remat superior pilar
Group: Grupo de modelo:Fusteries interior (elementos excluidos):3262893
Name (Montante rectangular:MC- Fusta- 35x3 cm- Pati aules- Remat superior pilar:...)
3277929 | Pset_MemberCommon - IsExternal: yes
3277949 | Pset_MemberCommon - IsExternal: yes
3277969 | Pset_MemberCommon - IsExternal: yes
3283233
3283253
3283273
3283557
3283577
3283597
3278125
3278105
5256177
5256197
5256217
5256264
5256284
5256304
5393562
5393582
5393602
5405286
5405306
5405326

# IfcMember: Montante rectangular:MC- Fusta- 35x6 cm- Centre, Montante rectangular:MC- Fusta- 35x6 cm- Centre:369789
In: P0- Escola
Type - PredefinedType: MULLION; Material: _Fusta massisa- T1
Type - Pset_MemberCommon - IsExternal: no
Pset_MemberCommon - IsExternal: yes; Reference: MC- Fusta- 35x6 cm- Centre; Span: 2.505 m
Pset_QuantityTakeOff - Reference: MC- Fusta- 35x6 cm- Centre

# IfcMember: Montante rectangular:MC- Fusta- 35x6 cm- Dreta (2)
In: P0- Escola
Type - PredefinedType: MULLION; Material: _Fusta massisa- T1
Type - Pset_MemberCommon - IsExternal: no
Pset_MemberCommon - Reference: MC- Fusta- 35x6 cm- Dreta; Span: 2.505 m
Pset_QuantityTakeOff - Reference: MC- Fusta- 35x6 cm- Dreta
Name (Montante rectangular:MC- Fusta- 35x6 cm- Dreta:...)
369359 | Pset_MemberCommon - IsExternal: yes
369621

# IfcMember: Montante rectangular:MC- Fusta- 35x6 cm- Esquerra (2)
In: P0- Escola
Type - PredefinedType: MULLION; Material: _Fusta massisa- T1
Type - Pset_MemberCommon - IsExternal: no
Pset_MemberCommon - Reference: MC- Fusta- 35x6 cm- Esquerra; Span: 2.505 m
Pset_QuantityTakeOff - Reference: MC- Fusta- 35x6 cm- Esquerra
Name (Montante rectangular:MC- Fusta- 35x6 cm- Esquerra:...)
211497 | Pset_MemberCommon - IsExternal: yes
369838

# IfcMember: Montante rectangular:MC- Fusta- 35x6 cm- Inferior (3)
In: P0- Escola
Type - PredefinedType: MULLION; Material: _Fusta massisa- T1
Type - Pset_MemberCommon - IsExternal: no
Pset_MemberCommon - Reference: MC- Fusta- 35x6 cm- Inferior
Pset_QuantityTakeOff - Reference: MC- Fusta- 35x6 cm- Inferior
Name (Montante rectangular:MC- Fusta- 35x6 cm- Inferior:...) | Span (m)
5778923 | 0.9375 | Pset_MemberCommon - IsExternal: yes
5447013 | 0.91
5447014 | 0.967499

# IfcMember: Montante rectangular:MC- Fusta- 35x6 cm- Neutre (6)
In: P0- Escola
Type - PredefinedType: MULLION; Material: _Fusta massisa- T1
Type - Pset_MemberCommon - IsExternal: no
Pset_MemberCommon - Reference: MC- Fusta- 35x6 cm- Neutre
Pset_QuantityTakeOff - Reference: MC- Fusta- 35x6 cm- Neutre
Name (Montante rectangular:MC- Fusta- 35x6 cm- Neutre:...) | Span (m)
211498 | 2.505 | Pset_MemberCommon - IsExternal: yes
369298 | 2.505 | Pset_MemberCommon - IsExternal: yes
5447011 | 0.94 | Pset_MemberCommon - IsExternal: yes
369620 | 2.505
369917 | 2.505
5447015 | 0.94

# IfcMember: Montante rectangular:MC- Fusta- 38x5 cm- Menjador- neutre.rfa (8)
In: P0- Escola
Type - PredefinedType: MULLION; Material: _Fusta massisa- T1
Type - Pset_MemberCommon - IsExternal: no
Pset_MemberCommon - IsExternal: yes; Reference: MC- Fusta- 38x5 cm- Menjador- neutre.rfa
Pset_QuantityTakeOff - Reference: MC- Fusta- 38x5 cm- Menjador- neutre.rfa
Name (Montante rectangular:MC- Fusta- 38x5 cm- Menjador- neutre.rfa:...) | Span (m)
5100340 | 1.2425
5100343 | 2.409
5100344 | 0.855
5100347 | 2.3955
5100348 | 0.855
5100353 | 1.66
5100354 | 1.66
5100355 | 2.3455

# IfcMember: Montante rectangular:MC- Fusta- 45x3 cm- Pati aules- Cantonada (3)
In: P0- Escola
Type - PredefinedType: MULLION; Material: _Fusta massisa- T1
Type - Pset_MemberCommon - IsExternal: no
Pset_MemberCommon - Reference: MC- Fusta- 45x3 cm- Pati aules- Cantonada; Span: 2.505 m
Pset_QuantityTakeOff - Reference: MC- Fusta- 45x3 cm- Pati aules- Cantonada
Group: Grupo de modelo:Fusteries interior (elementos excluidos):3262893
Name (Montante rectangular:MC- Fusta- 45x3 cm- Pati aules- Cantonada:...)
5379814 | Pset_MemberCommon - IsExternal: yes
5393655
5405379

# IfcMember: Montante rectangular:MC- Fusta- 45x6 cm- Superior porta (2)
In: P0- Escola
Type - PredefinedType: MULLION; Material: _Fusta massisa- T1
Type - Pset_MemberCommon - IsExternal: no
Pset_MemberCommon - Reference: MC- Fusta- 45x6 cm- Superior porta
Pset_QuantityTakeOff - Reference: MC- Fusta- 45x6 cm- Superior porta
Name (Montante rectangular:MC- Fusta- 45x6 cm- Superior porta:...) | Span (m)
211487 | 1.0275 | Pset_MemberCommon - IsExternal: yes
369619 | 1.0325

# IfcMember: Montante rectangular:MC- Fusta- 45x6 cm- Superior vidre (5)
In: P0- Escola
Type - PredefinedType: MULLION; Material: _Fusta massisa- T1
Type - Pset_MemberCommon - IsExternal: no
Pset_MemberCommon - Reference: MC- Fusta- 45x6 cm- Superior vidre
Pset_QuantityTakeOff - Reference: MC- Fusta- 45x6 cm- Superior vidre
Name (Montante rectangular:MC- Fusta- 45x6 cm- Superior vidre:...) | Span (m)
369297 | 1.0325 | Pset_MemberCommon - IsExternal: yes
369358 | 1 | Pset_MemberCommon - IsExternal: yes
369788 | 1
369837 | 1.0275
369916 | 1

# IfcMember: Montante rectangular:MC- Fusta- 57,5x3 cm- Fa Pista- Remat extrem (4)
In: P0- Escola
Type - PredefinedType: MULLION; Material: _Fusta massisa- T1
Type - Pset_MemberCommon - IsExternal: no
Pset_MemberCommon - Reference: MC- Fusta- 57,5x3 cm- Fa Pista- Remat extrem
Pset_QuantityTakeOff - Reference: MC- Fusta- 57,5x3 cm- Fa Pista- Remat extrem
Name (Montante rectangular:MC- Fusta- 57,5x3 cm- Fa Pista- Remat extrem:...) | Span (m)
4868013 | 1.82 | Pset_MemberCommon - IsExternal: yes
4868015 | 1.91 | Pset_MemberCommon - IsExternal: yes
4892053 | 0.655
4928471 | 0.655

# IfcMember: Montante rectangular:MC- Fusta- 6,5x9- Biblio- Centre (2)
In: P0- Escola
Type - PredefinedType: MULLION; Material: _Fusta massisa- T1
Type - Pset_MemberCommon - IsExternal: no
Pset_MemberCommon - IsExternal: yes; Reference: MC- Fusta- 6,5x9- Biblio- Centre; Span: 2.47726 m
Pset_QuantityTakeOff - Reference: MC- Fusta- 6,5x9- Biblio- Centre
Name (Montante rectangular:MC- Fusta- 6,5x9- Biblio- Centre:...)
4907972
4908045

# IfcMember: Montante rectangular:MC- Fusta- 6,5x9- Biblio- Dreta (2)
In: P0- Escola
Type - PredefinedType: MULLION; Material: _Fusta massisa- T1
Type - Pset_MemberCommon - IsExternal: no
Pset_MemberCommon - Reference: MC- Fusta- 6,5x9- Biblio- Dreta
Pset_QuantityTakeOff - Reference: MC- Fusta- 6,5x9- Biblio- Dreta
Name (Montante rectangular:MC- Fusta- 6,5x9- Biblio- Dreta:...) | Span (m)
4901827 | 2.47726 | Pset_MemberCommon - IsExternal: yes
5092987 | 2.505

# IfcMember: Montante rectangular:MC- Fusta- 6,5x9- Biblio- Esquerra (7)
In: P0- Escola
Type - PredefinedType: MULLION; Material: _Fusta massisa- T1
Type - Pset_MemberCommon - IsExternal: no
Pset_MemberCommon - Reference: MC- Fusta- 6,5x9- Biblio- Esquerra
Pset_QuantityTakeOff - Reference: MC- Fusta- 6,5x9- Biblio- Esquerra
Name (Montante rectangular:MC- Fusta- 6,5x9- Biblio- Esquerra:...) | IsExternal | Span (m)
4902326 | yes | 1.08466
4902327 | yes | 2.47726
4907971 | yes | 1.07
4908044 | yes | 1.013
5092655 |  | 0.44
5092656 |  | 2.505
5092986 |  | 1.06

# IfcMember: Montante rectangular:MC- Fusta- 6,5x9- Biblio- Inferior (3)
In: P0- Escola
Type - PredefinedType: MULLION; Material: _Fusta massisa- T1
Type - Pset_MemberCommon - IsExternal: no
Pset_MemberCommon - IsExternal: yes; Reference: MC- Fusta- 6,5x9- Biblio- Inferior
Pset_QuantityTakeOff - Reference: MC- Fusta- 6,5x9- Biblio- Inferior
Name (Montante rectangular:MC- Fusta- 6,5x9- Biblio- Inferior:...) | Span (m)
5447205 | 0.98
5447207 | 0.953
5447208 | 1.02466

# IfcMember: Montante rectangular:MC- Fusta- 6,5x9- Biblio- Neutre (3)
In: P0- Escola
Type - PredefinedType: MULLION; Material: _Fusta massisa- T1
Type - Pset_MemberCommon - IsExternal: no
Pset_MemberCommon - Reference: MC- Fusta- 6,5x9- Biblio- Neutre
Pset_QuantityTakeOff - Reference: MC- Fusta- 6,5x9- Biblio- Neutre
Name (Montante rectangular:MC- Fusta- 6,5x9- Biblio- Neutre:...) | IsExternal | Span (m)
4901825 | yes | 1.1
4901826 | yes | 2.47726
5092657 |  | 2.505

# IfcMember: Montante rectangular:MC- Fusta- pefil prestatge gimnàs (3)
In: PS1- Vestuari
Type - PredefinedType: MULLION; Material: _Fusta massisa- T1
Type - Pset_MemberCommon - IsExternal: no
Pset_MemberCommon - Reference: MC- Fusta- pefil prestatge gimnàs
Pset_QuantityTakeOff - Reference: MC- Fusta- pefil prestatge gimnàs
Name (Montante rectangular:MC- Fusta- pefil prestatge gimnàs:...) | Span (m)
4768721 | 3.565 | Pset_MemberCommon - IsExternal: yes
4768726 | 3.6
4768902 | 3.565

# IfcMember: Montante rectangular:MC- fusta- prestage (8)
In: PS1- Gimnàs
Type - PredefinedType: MULLION; Material: _Fusta massisa- T1
Type - Pset_MemberCommon - IsExternal: no
Pset_MemberCommon - IsExternal: yes; Reference: MC- fusta- prestage; Span: 1.00628 m
Pset_QuantityTakeOff - Reference: MC- fusta- prestage
Name (Montante rectangular:MC- fusta- prestage:...)
4667075
4667079
4667083
4667087
4667092
4667096
4667100
4667104

# IfcMember: Montante rectangular:Muntant53x 60 mm (3)
In: PS1- Vestuari
Type - PredefinedType: MULLION; Material: _Alumini- T1- Perfil
Type - Pset_MemberCommon - IsExternal: no
Pset_MemberCommon - Reference: Muntant53x 60 mm; Span: 2.20994 m
Pset_QuantityTakeOff - Reference: Muntant53x 60 mm
Name (Montante rectangular:Muntant53x 60 mm:...)
102315 | Pset_MemberCommon - IsExternal: yes
102321
102334

# IfcMember: Montante rectangular:PerfilBany-Dreta (6)
In: P0- Escola
Type - PredefinedType: MULLION; Material: _Fusta massisa- T1
Type - Pset_MemberCommon - IsExternal: no
Pset_MemberCommon - Reference: PerfilBany-Dreta
Pset_QuantityTakeOff - Reference: PerfilBany-Dreta
Name (Montante rectangular:PerfilBany-Dreta:...) | Span (m) | Group
2141157 | 0.345 | Grupo de modelo:BANY1:2141168 | Pset_MemberCommon - IsExternal: yes
2263436 | 1.305 | Grupo de modelo:BANY1:2141168 | Pset_MemberCommon - IsExternal: yes
2334005 | 0.345 | Grupo de modelo:BANY1:2334016
2334022 | 1.305 | Grupo de modelo:BANY1:2334016
2334655 | 0.345 | Grupo de modelo:BANY1:2334666
2334672 | 1.305 | Grupo de modelo:BANY1:2334666

# IfcOpeningElement: Opening (51)
Name | In
Muro básico:REV- Guix Laminat Extradossat- Aillament- T1- 6,5 cm:101419:1 | P0- Escola | Pset_OpeningElementCommon - Reference: REV- Guix Laminat Extradossat- Aillament- T1- 6,5 cm; sets with these values: 2
Muro básico:ENV- Ceràmic- 14 cm:101977:1 | P0- Escola | Pset_OpeningElementCommon - Reference: ENV- Ceràmic- 14 cm; sets with these values: 2
Cubierta básica:COB- Coberta invertida- Graves- No transitable:5300306:1 | PC- Coberta STR | Pset_OpeningElementCommon - Reference: COB- Coberta invertida- Graves- No transitable; sets with these values: 2
Cubierta básica:COB- Coberta invertida- Graves- No transitable:5300306:2 | PC- Coberta STR | Pset_OpeningElementCommon - Reference: COB- Coberta invertida- Graves- No transitable; sets with these values: 2
Cubierta básica:COB- Coberta invertida- Graves- No transitable:5300306:3 | PC- Coberta STR | Pset_OpeningElementCommon - Reference: COB- Coberta invertida- Graves- No transitable; sets with these values: 2
Cubierta básica:COB- Coberta invertida- Graves- No transitable:5300306:4 | PC- Coberta STR | Pset_OpeningElementCommon - Reference: COB- Coberta invertida- Graves- No transitable; sets with these values: 2
Cubierta básica:COB- Coberta invertida- Graves- No transitable:5300306:5 | PC- Coberta STR | Pset_OpeningElementCommon - Reference: COB- Coberta invertida- Graves- No transitable; sets with these values: 2
Cubierta básica:COB- Coberta invertida- Graves- No transitable:5300306:6 | PC- Coberta STR | Pset_OpeningElementCommon - Reference: COB- Coberta invertida- Graves- No transitable; sets with these values: 2
Cubierta básica:COB- Coberta invertida- Graves- No transitable:5300306:7 | PC- Coberta STR | Pset_OpeningElementCommon - Reference: COB- Coberta invertida- Graves- No transitable; sets with these values: 2
Cubierta básica:COB- Coberta invertida- Formigó- Installacions:5419951:1 | PC- Coberta STR | Pset_OpeningElementCommon - Reference: COB- Coberta invertida- Formigó- Installacions; sets with these values: 2; Group: Grupo de modelo:BADALOT 2:5309104
Cubierta básica:COB- Coberta invertida- Formigó- Installacions:5420074:1 | PC- Coberta STR | Pset_OpeningElementCommon - Reference: COB- Coberta invertida- Formigó- Installacions; sets with these values: 2; Group: Grupo de modelo:BADALOT 2:5309452
Cubierta básica:COB- Coberta invertida- Formigó- Installacions:5420084:1 | PC- Coberta STR | Pset_OpeningElementCommon - Reference: COB- Coberta invertida- Formigó- Installacions; sets with these values: 2; Group: Grupo de modelo:BADALOT 2:5309638
Cubierta básica:COB- Coberta invertida- Formigó- Installacions:5420351:1 | PC- Coberta STR | Pset_OpeningElementCommon - Reference: COB- Coberta invertida- Formigó- Installacions; sets with these values: 2; Group: Grupo de modelo:BADALOT 1 (elementos excluidos):5302593
Cubierta básica:COB- Coberta invertida- Formigó- Installacions:5425218:1 | PC- Coberta STR | Pset_OpeningElementCommon - Reference: COB- Coberta invertida- Formigó- Installacions; sets with these values: 2; Group: Grupo de modelo:BADALOT 3:5425172
Muro básico:ENV- Ceràmic- 5,5 cm:5993233 | P0- Escola | Pset_OpeningElementCommon - Reference: FUS- Porta Fusta- marc ocult- 90x250,5 cm; sets with these values: 2; Group: Grupo de modelo:Modul Banys (elementos excluidos):100597
Muro básico:ENV- Ceràmic- 7 cm 3:6000048 | P0- Escola | Pset_OpeningElementCommon - Reference: FUS- Porta Fusta- marc ocult- 90x250,5 cm; sets with these values: 2; Group: Grupo de modelo:Modul Banys 2:100913
FUS- Porta Fusta- marc ocult- obertura interior:FUS- Porta Fusta- marc ocult- 90x250,5 cm:810852:1 | P0- Escola
FUS- Porta Fusta- marc ocult- obertura interior:FUS- Porta Fusta- marc ocult- 90x250,5 cm:811238:1 | P0- Escola
2 x Muro básico:REV- Fusta- T1- 3,5 cm:100498 | P0- Escola
2 x Muro básico:REV- Fusta- T1- 3,5 cm:100587 | P0- Escola
FUS- Porta Fusta- marc ocult variable- obertura interior:FUS- Porta Fusta- marc ocult- 90x250,5 cm:5367172:1 | P0- Escola
FUS- Marc Fusta- marc ocult variable- remat ascensor:FUS- Porta Fusta- marc ocult- 90x250,5 cm:5371570:1 | P0- Escola
Muro básico:REV- Fusta- T1- 13,5 cm:100603 | P0- Escola
FUS- Porta Fusta- marc ocult- obertura corredera:FUS- Porta Fusta- marc ocult- 90x250,5 cm:811527:1 | P0- Escola
FUS- Porta Fusta- marc ocult- obertura interior:FUS- Porta Fusta- marc ocult- 90x250,5 cm:5402705:1 | P0- Escola
2 x Muro básico:REV- Fusta- T1- 3,5 cm:100903 | P0- Escola
FUS- Porta Fusta- marc ocult- obertura corredera:FUS- Porta Fusta- marc ocult- 90x250,5 cm:811775:1 | P0- Escola
FUS- Porta Fusta- marc ocult- obertura interior:FUS- Porta Fusta- marc ocult- 90x250,5 cm:5403009:1 | P0- Escola
FUS- Alu- Fulla porta opaca:FUS- Alu- Fulla porta opaca- 2,505X0,85:5135024:1 | P0- Escola
Muro básico:REV- Guix Laminat Extradossat- Aillament- T1- 6,5 cm:101643 | P0- Escola
Muro básico:REV- Enrajolat peces pasta vitrea- T1- int- 2,5 cm:101644 | P0- Escola
FUS- Porta Fusta- marc ocult- obertura interior:FUS- Porta Fusta- marc ocult- 90x250,5 cm:777949:1 | P0- Escola
FUS- Porta Fusta- marc ocult- obertura interior:FUS- Porta Fusta- marc ocult- 90x250,5 cm:812424:1 | P0- Escola
Muro básico:ENV- REV- Ceràmic- 14 cm + peces pasta vitrea 2 caras:101670 | P0- Escola
FUS- Porta Fusta- marc ocult- obertura exterior:FUS- Porta Fusta- marc ocult- 90x250,5 cm:5093221:1 | P0- Escola
FUS- Porta Fusta- marc ocult- obertura interior:FUS- Porta Fusta- marc ocult- 90x250,5 cm:5094717:1 | P0- Escola
FUS- Porta Fusta- marc ocult- obertura interior:FUS- Porta Fusta- marc ocult- 90x250,5 cm:778104:1 | P0- Escola
FUS- Porta Fusta- marc ocult- obertura interior:FUS- Porta Fusta- marc ocult- 90x250,5 cm:778155:1 | P0- Escola
FUS- Porta Fusta- marc ocult- obertura interior:FUS- Porta Fusta- marc ocult- 90x250,5 cm:5096547:1 | P0- Escola
FUS- Porta Fusta- marc ocult- obertura interior:FUS- Porta Fusta- marc ocult- 90x250,5 cm:5096606:1 | P0- Escola
Muro básico:ENV- REV- Ceràmic- 14 cm + peces pasta vitrea:101705 | P0- Escola
FUS- Porta Fusta- marc ocult- obertura exterior:FUS- Porta Fusta- marc ocult- 90x250,5 cm:5089163:1 | P0- Escola
Muro básico:REV- Badalot- Xapa + Aillament:5305701 | PC- Coberta STR
Muro básico:REV- Badalot- Xapa + Aillament:5309109 | PC- Coberta STR
Muro básico:REV- Badalot- Xapa + Aillament:5309457 | PC- Coberta STR
Muro básico:REV- Badalot- Xapa + Aillament:5309643 | PC- Coberta STR
Muro básico:REV- Fusta- T1- 3,5 cm:5369419 | P0- Escola
Muro básico:REV- Badalot- Xapa + Aillament:5425174 | PC- Coberta STR

# IfcPlate: MC- Alu- Panell opac revestiment interior:MC- Alu panell revestiment xapa (4)
In: PS1- Gimnàs
Type - PredefinedType: CURTAIN_PANEL; Material: _Fusta massisa- T1, _Aillament, _HPL- T1- REV
Type - Pset_PlateCommon - IsExternal: no
Pset_PlateCommon - Reference: MC- Alu panell revestiment xapa
Pset_QuantityTakeOff - Reference: MC- Alu panell revestiment xapa
Name (MC- Alu- Panell opac revestiment interior:MC- Alu panell revestiment xapa:...)
4666958 | Pset_PlateCommon - IsExternal: yes
4666961 | Pset_PlateCommon - IsExternal: yes
4702271
4704294

# IfcPlate: Panel de sistema:FUS- Vidre- ext- T1 (3)
In: P0- Escola
Type - PredefinedType: CURTAIN_PANEL; Material: _Vidre
Type - Pset_PlateCommon - IsExternal: no
Pset_PlateCommon - Reference: FUS- Vidre- ext- T1
Pset_QuantityTakeOff - Reference: FUS- Vidre- ext- T1
Name (Panel de sistema:FUS- Vidre- ext- T1:...) | Group
2263464 | Grupo de modelo:BANY1:2141168 | Pset_PlateCommon - IsExternal: yes
2334025 | Grupo de modelo:BANY1:2334016
2334675 | Grupo de modelo:BANY1:2334666

# IfcPlate: PanellMurCortina_PortaInteriorVidre-infantil inf:PanellMurCortina_PortaInteriorVidre-infantil inf (3)
In: P0- Escola
Type - PredefinedType: CURTAIN_PANEL; Material: _Fusta massisa- T1, _Vidre
Type - Pset_PlateCommon - IsExternal: no
Pset_PlateCommon - Reference: PanellMurCortina_PortaInteriorVidre-infantil inf
Pset_QuantityTakeOff - Reference: PanellMurCortina_PortaInteriorVidre-infantil inf
Name (PanellMurCortina_PortaInteriorVidre-infantil inf:PanellMurCortina_PortaInteriorVidre-infantil inf:...) | Group
2263366 | Grupo de modelo:BANY1:2141168 | Pset_PlateCommon - IsExternal: yes
2334017 | Grupo de modelo:BANY1:2334016
2334667 | Grupo de modelo:BANY1:2334666

# IfcPlate: PanellMurCortina_PortaInteriorVidre-infantil sup:PanellMurCortina_PortaInteriorVidre-infantil sup (3)
In: P0- Escola
Type - PredefinedType: CURTAIN_PANEL; Material: _Fusta massisa- T1, _Vidre
Type - Pset_PlateCommon - IsExternal: no
Pset_PlateCommon - Reference: PanellMurCortina_PortaInteriorVidre-infantil sup
Pset_QuantityTakeOff - Reference: PanellMurCortina_PortaInteriorVidre-infantil sup
Name (PanellMurCortina_PortaInteriorVidre-infantil sup:PanellMurCortina_PortaInteriorVidre-infantil sup:...) | Group
2263421 | Grupo de modelo:BANY1:2141168 | Pset_PlateCommon - IsExternal: yes
2334021 | Grupo de modelo:BANY1:2334016
2334671 | Grupo de modelo:BANY1:2334666

# IfcPlate: PanellMurCortina_Revestiment_Vestuaris:PanellMurCortina_Revestiment_Vestuaris (2)
In: PS1- Vestuari
Type - PredefinedType: CURTAIN_PANEL; Material: _Alumini- T1- Perfil
Type - Pset_PlateCommon - IsExternal: no
Pset_PlateCommon - IsExternal: yes; Reference: PanellMurCortina_Revestiment_Vestuaris
Pset_QuantityTakeOff - Reference: PanellMurCortina_Revestiment_Vestuaris
Name (PanellMurCortina_Revestiment_Vestuaris:PanellMurCortina_Revestiment_Vestuaris:...)
102149
102298

# IfcPlate: PanellMurCortina_VidreInterior_EixCentral:MC- INT- Panell vidre (3)
In: P0- Escola
Type - PredefinedType: CURTAIN_PANEL; Material: _Vidre
Type - Pset_PlateCommon - IsExternal: no
Pset_PlateCommon - Reference: MC- INT- Panell vidre
Pset_QuantityTakeOff - Reference: MC- INT- Panell vidre
Name (PanellMurCortina_VidreInterior_EixCentral:MC- INT- Panell vidre:...) | Group
2141165 | Grupo de modelo:BANY1:2141168 | Pset_PlateCommon - IsExternal: yes
2334013 | Grupo de modelo:BANY1:2334016
2334663 | Grupo de modelo:BANY1:2334666

# IfcRailing: Barandilla:BaranaAlta_01, Barandilla:BaranaAlta_01:5428373
In: P0- Escola
Material: <Unnamed>
Pset_QuantityTakeOff - Reference: BaranaAlta_01
Pset_RailingCommon - IsExternal: no; Reference: BaranaAlta_01; Height: 0.81 m

# IfcRailing: Barandilla:BaranaAlta_02, Barandilla:BaranaAlta_02:5428381
In: P0- Escola
Material: <Unnamed>
Pset_QuantityTakeOff - Reference: BaranaAlta_02
Pset_RailingCommon - IsExternal: no; Reference: BaranaAlta_02; Height: 0.81 m

# IfcRailing: Barandilla:BaranaEscalaBiblioteca_NomesBarana (7)
In: P0- Escola
Material: <Unnamed>
Pset_QuantityTakeOff - Reference: BaranaEscalaBiblioteca_NomesBarana
Pset_RailingCommon - IsExternal: no; Reference: BaranaEscalaBiblioteca_NomesBarana; Height: 0.81 m
Name (Barandilla:BaranaEscalaBiblioteca_NomesBarana:...)
5427911
5427959
5428049
5428079
5428388
5428420
5428452

# IfcRailing: Barandilla:BaranaEscalaBiblioteca_NomesMuntants, Barandilla:BaranaEscalaBiblioteca_NomesMuntants:5427904
In: P0- Escola
Material: <Unnamed>
Pset_QuantityTakeOff - Reference: BaranaEscalaBiblioteca_NomesMuntants
Pset_RailingCommon - IsExternal: no; Reference: BaranaEscalaBiblioteca_NomesMuntants; Height: 0.81 m

# IfcRailing: Barandilla:BaranaEscalaBiblioteca_NomesMuntants_Cota0, Barandilla:BaranaEscalaBiblioteca_NomesMuntants_Cota0:5428028
In: P0- Escola
Material: <Unnamed>
Pset_QuantityTakeOff - Reference: BaranaEscalaBiblioteca_NomesMuntants_Cota0
Pset_RailingCommon - IsExternal: no; Reference: BaranaEscalaBiblioteca_NomesMuntants_Cota0; Height: 0.81 m

# IfcRailing: Barandilla:BaranaEscalaExteriorAules (2)
In: P0- Escola
Material: <Unnamed>
Pset_QuantityTakeOff - Reference: BaranaEscalaExteriorAules
Pset_RailingCommon - IsExternal: no; Reference: BaranaEscalaExteriorAules; Height: 0.81 m
Name (Barandilla:BaranaEscalaExteriorAules:...)
5428276
5428324

# IfcRailing: Barandilla:BaranaEscalaRampa, Barandilla:BaranaEscalaRampa:5427863
In: P0- Escola
Material: <Unnamed>
Pset_QuantityTakeOff - Reference: BaranaEscalaRampa
Pset_RailingCommon - IsExternal: no; Reference: BaranaEscalaRampa; Height: 0.81 m

# IfcRailing: Barandilla:BaranaPorxoBiblioteca_NomesMuntants (3)
In: P0- Escola
Material: <Unnamed>
Pset_QuantityTakeOff - Reference: BaranaPorxoBiblioteca_NomesMuntants
Pset_RailingCommon - IsExternal: no; Reference: BaranaPorxoBiblioteca_NomesMuntants; Height: 0.81 m
Name (Barandilla:BaranaPorxoBiblioteca_NomesMuntants:...)
5428042
5428113
5428484

# IfcRailing: Barandilla:BaranaPorxoNens, Barandilla:BaranaPorxoNens:5427852
In: P0- Escola
Material: <Unnamed>, _Formigó- Solera- T1- STR
Pset_QuantityTakeOff - Reference: BaranaPorxoNens
Pset_RailingCommon - IsExternal: no; Reference: BaranaPorxoNens; Height: 1.5 m

# IfcRailing: Barandilla:BaranaRampa (3)
In: P0- Escola
Material: <Unnamed>
Pset_QuantityTakeOff - Reference: BaranaRampa
Pset_RailingCommon - IsExternal: no; Reference: BaranaRampa; Height: 0.81 m
Name (Barandilla:BaranaRampa:...)
5428130
5428189
5428240

# IfcRailing: Barandilla:BaranaSotaBiblioteca, Barandilla:BaranaSotaBiblioteca:5428499
In: P0- Escola
Material: <Unnamed>
Pset_QuantityTakeOff - Reference: BaranaSotaBiblioteca
Pset_RailingCommon - IsExternal: no; Reference: BaranaSotaBiblioteca; Height: 0.81 m

# IfcRoof: Cubierta básica:COB- Coberta Xapa (4)
In: PC- Coberta STR
Material: _REV- Xapa minionda 0.01 m, _Genèric perfils, muntants, rastrells 0.01 m, _Aillament 0.08 m
Pset_QuantityTakeOff - Reference: COB- Coberta Xapa
Pset_RoofCommon - IsExternal: yes; Reference: COB- Coberta Xapa; ProjectedArea: 7.458 m2; TotalArea: 7.458 m2
Name (Cubierta básica:COB- Coberta Xapa:...) | Group
5307157 | Grupo de modelo:BADALOT 1 (elementos excluidos):5302593
5311050 | Grupo de modelo:BADALOT 2:5309104
5311221 | Grupo de modelo:BADALOT 2:5309452
5311241 | Grupo de modelo:BADALOT 2:5309638

# IfcRoof: Cubierta básica:COB- Coberta Xapa 2, Cubierta básica:COB- Coberta Xapa 2:5425186
In: PC- Coberta STR
Material: _REV- Xapa minionda 0.01 m, _Genèric perfils, muntants, rastrells 0.01 m, _Aillament 0.08 m; Group: Grupo de modelo:BADALOT 3:5425172
Pset_QuantityTakeOff - Reference: COB- Coberta Xapa 2
Pset_RoofCommon - IsExternal: yes; Reference: COB- Coberta Xapa 2; ProjectedArea: 7.458 m2; TotalArea: 7.458 m2

# IfcRoof: Cubierta básica:COB- Coberta invertida- Formigó- Biblio, Cubierta básica:COB- Coberta invertida- Formigó- Biblio:6039130
In: PC- Coberta STR
Material: _COB- Formigó antilliscant- T1 ext 0.2 m, _COB - Geotextil 0.01 m, _COB- Doble làmina asfàltica 0.01 m
Pset_QuantityTakeOff - Reference: COB- Coberta invertida- Formigó- Biblio
Pset_RoofCommon - IsExternal: yes; Reference: COB- Coberta invertida- Formigó- Biblio; ProjectedArea: 29.11 m2; TotalArea: 29.11 m2

# IfcRoof: Cubierta básica:COB- Coberta invertida- Formigó- Installacions (5)
In: PC- Coberta STR
Material: _COB- Formigó antilliscant- T1 ext 0.15 m, _COB - Geotextil 0.01 m, _Aillament 0.08 m, _COB- Doble làmina asfàltica 0.01 m, _COB- Formigó Cel·lular 0.12 m
Pset_QuantityTakeOff - Reference: COB- Coberta invertida- Formigó- Installacions
Pset_RoofCommon - IsExternal: yes; Reference: COB- Coberta invertida- Formigó- Installacions
Name (Cubierta básica:COB- Coberta invertida- Formigó- Installacions:...) | ProjectedArea (m2) | TotalArea (m2) | Group
5419951 | 17.7251 | 16.3523 | Grupo de modelo:BADALOT 2:5309104
5420074 | 17.7251 | 16.3523 | Grupo de modelo:BADALOT 2:5309452
5420084 | 17.7251 | 16.3523 | Grupo de modelo:BADALOT 2:5309638
5420351 | 21.4607 | 20.4851 | Grupo de modelo:BADALOT 1 (elementos excluidos):5302593
5425218 | 21.4607 | 20.4851 | Grupo de modelo:BADALOT 3:5425172

# IfcRoof: Cubierta básica:COB- Coberta invertida- Graves- No transitable (2)
In: PC- Coberta STR
Material: _COB- Grava 0.08 m, _COB - Geotextil 0.01 m, _Aillament 0.08 m, _COB- Doble làmina asfàltica 0.01 m, _COB- Formigó Cel·lular 0.12 m
Pset_QuantityTakeOff - Reference: COB- Coberta invertida- Graves- No transitable
Pset_RoofCommon - IsExternal: yes; Reference: COB- Coberta invertida- Graves- No transitable
Name (Cubierta básica:COB- Coberta invertida- Graves- No transitable:...) | ProjectedArea (m2) | TotalArea (m2)
5300306 | 1318.94 | 1222.27
6038933 | 14.91 | 14.91

# IfcSlab: Cubierta básica:COB- Coberta Xapa (4)
In: PC- Coberta STR
Type - PredefinedType: ROOF
Type - Pset_SlabCommon - IsExternal: yes; ThermalTransmittance: 2.49973 kg/K/s3
Material: _REV- Xapa minionda 0.01 m, _Genèric perfils, muntants, rastrells 0.01 m, _Aillament 0.08 m
Pset_QuantityTakeOff - Reference: COB- Coberta Xapa; sets with these values: 2
Pset_SlabCommon - PitchAngle: 0 deg; Reference: COB- Coberta Xapa
Name (Cubierta básica:COB- Coberta Xapa:...) | Group
5307157 | Grupo de modelo:BADALOT 1 (elementos excluidos):5302593
5311050 | Grupo de modelo:BADALOT 2:5309104
5311221 | Grupo de modelo:BADALOT 2:5309452
5311241 | Grupo de modelo:BADALOT 2:5309638

# IfcSlab: Cubierta básica:COB- Coberta Xapa 2, Cubierta básica:COB- Coberta Xapa 2:5425186
In: PC- Coberta STR
Type - PredefinedType: ROOF
Type - Pset_SlabCommon - IsExternal: yes; ThermalTransmittance: 2.49973 kg/K/s3
Material: _REV- Xapa minionda 0.01 m, _Genèric perfils, muntants, rastrells 0.01 m, _Aillament 0.08 m; Group: Grupo de modelo:BADALOT 3:5425172
Pset_QuantityTakeOff - Reference: COB- Coberta Xapa 2; sets with these values: 2
Pset_SlabCommon - PitchAngle: 0 deg; Reference: COB- Coberta Xapa 2

# IfcSlab: Cubierta básica:COB- Coberta invertida- Formigó- Biblio, Cubierta básica:COB- Coberta invertida- Formigó- Biblio:6039130
In: PC- Coberta STR
Type - PredefinedType: ROOF
Type - Pset_SlabCommon - IsExternal: yes; ThermalTransmittance: 13.8 kg/K/s3
Material: _COB- Formigó antilliscant- T1 ext 0.2 m, _COB - Geotextil 0.01 m, _COB- Doble làmina asfàltica 0.01 m
Pset_QuantityTakeOff - Reference: COB- Coberta invertida- Formigó- Biblio; sets with these values: 2
Pset_SlabCommon - PitchAngle: 0 deg; Reference: COB- Coberta invertida- Formigó- Biblio

# IfcSlab: Cubierta básica:COB- Coberta invertida- Formigó- Installacions (5)
In: PC- Coberta STR
Type - PredefinedType: ROOF
Type - Pset_SlabCommon - IsExternal: yes; ThermalTransmittance: 13.8 kg/K/s3
Pset_QuantityTakeOff - Reference: COB- Coberta invertida- Formigó- Installacions; sets with these values: 2
Pset_SlabCommon - PitchAngle: 0 deg; Reference: COB- Coberta invertida- Formigó- Installacions
Name (Cubierta básica:COB- Coberta invertida- Formigó- Installacions:...) | Group
5419951:1 | Grupo de modelo:BADALOT 2:5309104
5420074:1 | Grupo de modelo:BADALOT 2:5309452
5420084:1 | Grupo de modelo:BADALOT 2:5309638
5420351:1 | Grupo de modelo:BADALOT 1 (elementos excluidos):5302593
5425218:1 | Grupo de modelo:BADALOT 3:5425172

# IfcSlab: Cubierta básica:COB- Coberta invertida- Graves- No transitable (2)
In: PC- Coberta STR
Type - PredefinedType: ROOF
Type - Pset_SlabCommon - IsExternal: yes; ThermalTransmittance: 13.8 kg/K/s3
Pset_QuantityTakeOff - Reference: COB- Coberta invertida- Graves- No transitable; sets with these values: 2
Pset_SlabCommon - PitchAngle: 0 deg; Reference: COB- Coberta invertida- Graves- No transitable
Name (Cubierta básica:COB- Coberta invertida- Graves- No transitable:...)
5300306:1
6038933 | Material: _COB- Grava 0.08 m, _COB - Geotextil 0.01 m, _Aillament 0.08 m, _COB- Doble làmina asfàltica 0.01 m, _COB- Formigó Cel·lular 0.12 m

# IfcSlab: Suelo:PAV- Formigó Antilliscant + aillament- T1 ext- 20 cm (2)
In: P0- Escola
Type - PredefinedType: FLOOR; Material: _Formigó antilliscant- T1 ext- PAV 0.14 m, _Aillament 0.06 m
Type - Pset_SlabCommon - IsExternal: no
Pset_QuantityTakeOff - Reference: PAV- Formigó Antilliscant + aillament- T1 ext- 20 cm; sets with these values: 2
Pset_SlabCommon - LoadBearing: no; Reference: PAV- Formigó Antilliscant + aillament- T1 ext- 20 cm; PitchAngle: 0.385046 deg
Name (Suelo:PAV- Formigó Antilliscant + aillament- T1 ext- 20 cm:...)
87321
87332

# IfcSlab: Suelo:PAV- Formigó Antilliscant + aillament- T1- 20 cm (46)
Type - PredefinedType: FLOOR; Material: _Formigó antilliscant- T2- PAV 0.14 m, _Aillament 0.06 m
Type - Pset_SlabCommon - IsExternal: no
Pset_QuantityTakeOff - Reference: PAV- Formigó Antilliscant + aillament- T1- 20 cm; sets with these values: 2
Pset_SlabCommon - Reference: PAV- Formigó Antilliscant + aillament- T1- 20 cm; LoadBearing: no; PitchAngle: 0 deg
Name (Suelo:PAV- Formigó Antilliscant + aillament- T1- 20 cm:...) | In
87125 | P0- Escola
87141 | P0- Escola
87175 | PS1- Gimnàs
87200 | PS1- Gimnàs
87212 | PS1- Gimnàs
87226 | PS1- Vestuari
87238 | PS1- Vestuari
87250 | PS1- Vestuari
87261 | PS1- Vestuari
87268 | PS1- Vestuari
87279 | PS1- Vestuari
87290 | P0- Escola
87342 | P0- Escola
87349 | P0- Escola
87356 | P0- Escola
87363 | P0- Escola
87372 | P0- Escola
87394 | P0- Escola
87403 | P0- Escola
87412 | P0- Escola
87429 | P0- Escola
87436 | P0- Escola
87445 | P0- Escola
87453 | P0- Escola
87461 | P0- Escola
87468 | P0- Escola
87475 | P0- Escola
87484 | P0- Escola
87495 | P0- Escola
87502 | P0- Escola
87522 | P0- Escola
87531 | P0- Escola
87542 | P0- Escola
100511 | P0- Escola | Group: Grupo de modelo:REV- MODUL Magatzem+ ascensor:101023
100518 | P0- Escola | Group: Grupo de modelo:REV- MODUL Magatzem+ ascensor:101023
100525 | P0- Escola | Group: Grupo de modelo:REV- MODUL Magatzem+ ascensor:101023
462642 | P0- Escola | Group: Grupo de modelo:Grup aula:4934097
462696 | P0- Escola | Group: Grupo de modelo:Grup aula:4934097
462843 | P0- Escola | Group: Grupo de modelo:Grup aula:4934097
4901603 | P0- Escola
4940401 | P0- Escola | Group: Grupo de modelo:Grup aula:4940566
4940438 | P0- Escola | Group: Grupo de modelo:Grup aula:4940566
4940454 | P0- Escola | Group: Grupo de modelo:Grup aula:4940566
4940657 | P0- Escola | Group: Grupo de modelo:Grup aula:4940822
4940694 | P0- Escola | Group: Grupo de modelo:Grup aula:4940822
4940710 | P0- Escola | Group: Grupo de modelo:Grup aula:4940822

# IfcSlab: Suelo:PAV- Formigó Antilliscant- T1 ext- 10 cm (2)
In: P0- Escola
Type - PredefinedType: FLOOR; Material: _Formigó antilliscant- T1 ext- PAV 0.15 m
Type - Pset_SlabCommon - IsExternal: no
Pset_QuantityTakeOff - Reference: PAV- Formigó Antilliscant- T1 ext- 10 cm; sets with these values: 2
Pset_SlabCommon - LoadBearing: no; Reference: PAV- Formigó Antilliscant- T1 ext- 10 cm; PitchAngle: 1.3462 deg
Name (Suelo:PAV- Formigó Antilliscant- T1 ext- 10 cm:...)
87304
87314

# IfcSlab: Suelo:PAV- Formigó Antilliscant- T1 ext- 18 cm, Suelo:PAV- Formigó Antilliscant- T1 ext- 18 cm:4901210
In: P0- Escola
Type - PredefinedType: FLOOR; Material: _Formigó antilliscant- T1 ext- PAV 0.18 m
Type - Pset_SlabCommon - IsExternal: no
Pset_QuantityTakeOff - Reference: PAV- Formigó Antilliscant- T1 ext- 18 cm; sets with these values: 2
Pset_SlabCommon - LoadBearing: no; PitchAngle: 0 deg; Reference: PAV- Formigó Antilliscant- T1 ext- 18 cm

# IfcSlab: Suelo:PAV- Formigó Antilliscant- T1 ext- 7.5cm, Suelo:PAV- Formigó Antilliscant- T1 ext- 7.5cm:5899833
In: P0- Escola
Type - PredefinedType: FLOOR; Material: _Formigó antilliscant- T1 ext- PAV 0.075 m
Type - Pset_SlabCommon - IsExternal: no
Pset_QuantityTakeOff - Reference: PAV- Formigó Antilliscant- T1 ext- 7.5cm; sets with these values: 2
Pset_SlabCommon - LoadBearing: no; Reference: PAV- Formigó Antilliscant- T1 ext- 7.5cm; PitchAngle: 6.51807 deg

# IfcSlab: Suelo:PAV- Fusta tecnològica- T1- 10 cm, Suelo:PAV- Fusta tecnològica- T1- 10 cm:87551
In: P0- Escola
Type - PredefinedType: FLOOR; Material: _Fusta tecnològica- REV- PAV 0.023 m, _Genèric perfils, muntants, rastrells 0.077 m
Type - Pset_SlabCommon - IsExternal: no; ThermalTransmittance: 0.324675 kg/K/s3
Pset_QuantityTakeOff - Reference: PAV- Fusta tecnològica- T1- 10 cm; sets with these values: 2
Pset_SlabCommon - LoadBearing: no; PitchAngle: 0 deg; Reference: PAV- Fusta tecnològica- T1- 10 cm

# IfcSlab: Suelo:PAV- Paviment genèric tarima (2)
In: PS1- Gimnàs
Type - PredefinedType: FLOOR; Material: _Formigó antilliscant- T2- PAV 0.15 m
Type - Pset_SlabCommon - IsExternal: no
Pset_QuantityTakeOff - Reference: PAV- Paviment genèric tarima; sets with these values: 2
Pset_SlabCommon - LoadBearing: no; Reference: PAV- Paviment genèric tarima
Group: Grupo de modelo:Tabiques escenari:101294
Name (Suelo:PAV- Paviment genèric tarima:...) | PitchAngle (deg)
101141 | 0
101153 | 4.78847

# IfcSlab: Suelo:PAV- Pelfut + Formigó + aillament- T1- 20 cm, Suelo:PAV- Pelfut + Formigó + aillament- T1- 20 cm:87297
In: P0- Escola
Type - PredefinedType: FLOOR; Material: _Pelfut- PAV 0.02 m, _Formigó antilliscant- T2- PAV 0.12 m, _Aillament 0.06 m
Type - Pset_SlabCommon - IsExternal: no
Pset_QuantityTakeOff - Reference: PAV- Pelfut + Formigó + aillament- T1- 20 cm; sets with these values: 2
Pset_SlabCommon - LoadBearing: no; PitchAngle: 0 deg; Reference: PAV- Pelfut + Formigó + aillament- T1- 20 cm

# IfcSlab: Suelo:PAV- Vinilic antilliscant + Formigó + aillament- T1- 20 cm (2)
In: P0- Escola
Type - PredefinedType: FLOOR; Material: _Vinílic antilliscant- PAV 0.001 m, _Formigó antilliscant- T2- PAV 0.139 m, _Aillament 0.06 m
Type - Pset_SlabCommon - IsExternal: no
Pset_QuantityTakeOff - Reference: PAV- Vinilic antilliscant + Formigó + aillament- T1- 20 cm; sets with these values: 2
Pset_SlabCommon - LoadBearing: no; PitchAngle: 0 deg; Reference: PAV- Vinilic antilliscant + Formigó + aillament- T1- 20 cm
Name (Suelo:PAV- Vinilic antilliscant + Formigó + aillament- T1- 20 cm:...) | Group
100600 | Grupo de modelo:Modul Banys (elementos excluidos):100597
100916 | Grupo de modelo:Modul Banys 2:100913

# IfcSlab: Suelo:PAV- llosa formigó exterior (6)
In: PC- Coberta STR
Type - PredefinedType: FLOOR; Material: _Formigó- T1- STR 0.05 m, _Aillament 0.03 m
Type - Pset_SlabCommon - IsExternal: no
Pset_QuantityTakeOff - Reference: PAV- llosa formigó exterior; sets with these values: 2
Pset_SlabCommon - LoadBearing: no; PitchAngle: 0 deg; Reference: PAV- llosa formigó exterior
Name (Suelo:PAV- llosa formigó exterior:...)
5309754
5309754:2
5309754:3
5309754:4
5309754:5
5309754:6

# IfcSlab: Suelo:STR- L- Formigó- Llosa- T1- 14 cm, Suelo:STR- L- Formigó- Llosa- T1- 14 cm:87569
In: P0- Escola
Type - PredefinedType: FLOOR; Material: _Formigó- T1- STR 0.14 m
Type - Pset_SlabCommon - IsExternal: no
Pset_QuantityTakeOff - Reference: STR- L- Formigó- Llosa- T1- 14 cm; sets with these values: 2
Pset_SlabCommon - PitchAngle: 0 deg; Reference: STR- L- Formigó- Llosa- T1- 14 cm; LoadBearing: yes

# IfcStair: Escalera moldeada in situ:E-X1- Interior (2)
In: PS1- Gimnàs
ShapeType: STRAIGHT_RUN_STAIR; Group: Grupo de modelo:Tabiques escenari:101294
Pset_QuantityTakeOff - Reference: E-X1- Interior
Pset_StairCommon - IsExternal: yes; Reference: E-X1- Interior; NumberOfRiser: 3; NumberOfTreads: 2; RiserHeight: 0.16 m; TreadLength: 0.3 m
Name (Escalera moldeada in situ:Escalera:...)
101298
101314

# IfcStairFlight: Tramo monolítico:E00- STR- Ext (2)
In: PS1- Gimnàs
Type - PredefinedType: STRAIGHT
NumberOfRiser: 3; NumberOfTreads: 2; RiserHeight: 0.524934 m; TreadLength: 0.984252 m; Material: _Formigó- T1- STR; Group: Grupo de modelo:Tabiques escenari:101294
Pset_QuantityTakeOff - Reference: E00- STR- Ext
Pset_StairFlightCommon - Reference: E00- STR- Ext; NumberOfRiser: 3; NumberOfTreads: 2; RiserHeight: 0.16 m; TreadLength: 0.3 m; NosingLength: 0 m; TreadLengthAtOffset: 0.3 m; TreadLengthAtInnerSide: 0.3 m
Name (Escalera moldeada in situ:Escalera:...) | WalkingLineOffset (m)
101298 Run 1 | 1.47638
101314 Run 1 | 2.2472

# IfcWall: Muro básico:REV- Guix Laminat Extradossat- Aillament- T1- 6,5 cm (8)
In: P0- Escola
Type - PredefinedType: STANDARD; Material: _Guix laminat- ENV 0.02 m, _Aillament 0.045 m
Type - Pset_WallCommon - IsExternal: no
Pset_QuantityTakeOff - Reference: REV- Guix Laminat Extradossat- Aillament- T1- 6,5 cm; sets with these values: 2
Pset_WallCommon - LoadBearing: no; ExtendToStructure: no; Reference: REV- Guix Laminat Extradossat- Aillament- T1- 6,5 cm
Name (Muro básico:REV- Guix Laminat Extradossat- Aillament- T1- 6,5 cm:...)
100726 | Group: Grupo de modelo:REV- Acabats interiors modul:100748
100797 | Group: Grupo de modelo:REV- Acabats interiors modul:100819
100976
5387444
5403814
5403878
5404366
5404387

# IfcWallStandardCase: Muro básico:ENV- Ceràmic Replè- 23 cm (14)
In: P0- Escola
Type - PredefinedType: STANDARD; Material: _Ceràmica- ENV 0.23 m
Type - Pset_WallCommon - IsExternal: yes
Pset_QuantityTakeOff - Reference: ENV- Ceràmic Replè- 23 cm; sets with these values: 2
Pset_WallCommon - LoadBearing: no; ExtendToStructure: no; Reference: ENV- Ceràmic Replè- 23 cm
Name (Muro básico:ENV- Ceràmic Replè- 23 cm:...) | Group
100580 | Grupo de modelo:Modul Banys (elementos excluidos):100597
100601 | Grupo de modelo:REV- MODUL Magatzem+ ascensor:101023
100896 | Grupo de modelo:Modul Banys 2:100913
101437
101541
101979
462703 | Grupo de modelo:Grup aula:4934097
462751 | Grupo de modelo:Grup aula:4934097
4940445 | Grupo de modelo:Grup aula:4940566
4940447 | Grupo de modelo:Grup aula:4940566
4940701 | Grupo de modelo:Grup aula:4940822
4940703 | Grupo de modelo:Grup aula:4940822
5090535
5091749

# IfcWallStandardCase: Muro básico:ENV- Ceràmic- 14 cm (100)
Type - PredefinedType: STANDARD; Material: _Ceràmica- ENV 0.14 m
Type - Pset_WallCommon - IsExternal: yes
Pset_QuantityTakeOff - Reference: ENV- Ceràmic- 14 cm; sets with these values: 2
Pset_WallCommon - LoadBearing: no; ExtendToStructure: no; Reference: ENV- Ceràmic- 14 cm
Name (Muro básico:ENV- Ceràmic- 14 cm:...) | In
100492 | P0- Escola | Group: Grupo de modelo:REV- MODUL Magatzem+ ascensor:101023
100495 | P0- Escola | Group: Grupo de modelo:REV- MODUL Magatzem+ ascensor:101023
100496 | P0- Escola | Group: Grupo de modelo:REV- MODUL Magatzem+ ascensor:101023
100579 | P0- Escola | Group: Grupo de modelo:Modul Banys (elementos excluidos):100597
100602 | P0- Escola | Group: Grupo de modelo:REV- MODUL Magatzem+ ascensor:101023
100895 | P0- Escola | Group: Grupo de modelo:Modul Banys 2:100913
101160 | PS1- Gimnàs
101168 | PS1- Gimnàs
101181 | PS1- Gimnàs
101265 | PS1- Gimnàs | Group: Grupo de modelo:Tabiques escenari:101294
101266 | PS1- Gimnàs | Group: Grupo de modelo:Tabiques escenari:101294
101267 | PS1- Gimnàs | Group: Grupo de modelo:Tabiques escenari:101294
101268 | PS1- Gimnàs | Group: Grupo de modelo:Tabiques escenari:101294
101269 | PS1- Gimnàs | Group: Grupo de modelo:Tabiques escenari:101294
101270 | PS1- Gimnàs | Group: Grupo de modelo:Tabiques escenari:101294
101271 | PS1- Gimnàs | Group: Grupo de modelo:Tabiques escenari:101294
101272 | PS1- Gimnàs | Group: Grupo de modelo:Tabiques escenari:101294
101273 | PS1- Gimnàs | Group: Grupo de modelo:Tabiques escenari:101294
101274 | PS1- Gimnàs | Group: Grupo de modelo:Tabiques escenari:101294
101275 | PS1- Gimnàs | Group: Grupo de modelo:Tabiques escenari:101294
101276 | PS1- Gimnàs | Group: Grupo de modelo:Tabiques escenari:101294
101277 | PS1- Gimnàs | Group: Grupo de modelo:Tabiques escenari:101294
101278 | PS1- Gimnàs | Group: Grupo de modelo:Tabiques escenari:101294
101279 | PS1- Gimnàs | Group: Grupo de modelo:Tabiques escenari:101294
101280 | PS1- Gimnàs | Group: Grupo de modelo:Tabiques escenari:101294
101281 | PS1- Gimnàs | Group: Grupo de modelo:Tabiques escenari:101294
101282 | PS1- Gimnàs | Group: Grupo de modelo:Tabiques escenari:101294
101283 | PS1- Gimnàs | Group: Grupo de modelo:Tabiques escenari:101294
101301 | PS1- Gimnàs | Group: Grupo de modelo:Tabiques escenari:101294
101317 | PS1- Vestuari
101318 | PS1- Vestuari
101319 | PS1- Vestuari
101320 | PS1- Vestuari
101321 | PS1- Vestuari
101322 | PS1- Vestuari
101323 | PS1- Vestuari
101324 | PS1- Gimnàs
101325 | PS1- Vestuari
101326 | PS1- Vestuari
101327 | PS1- Vestuari
101328 | PS1- Vestuari
101329 | PS1- Vestuari
101330 | PS1- Vestuari
101331 | PS1- Vestuari
101332 | PS1- Vestuari
101333 | PS1- Vestuari
101334 | PS1- Vestuari
101335 | PS1- Vestuari
101336 | PS1- Vestuari
101337 | PS1- Vestuari
101338 | PS1- Gimnàs
101340 | PS1- Vestuari
101341 | PS1- Vestuari
101342 | PS1- Vestuari
101343 | PS1- Vestuari
101642 | P0- Escola
101668 | P0- Escola
101669 | P0- Escola
101675 | P0- Escola
101707 | P0- Escola
101970 | P0- Escola
101971 | P0- Escola
101972 | P0- Escola
101977 | P0- Escola
101978 | P0- Escola
101980 | P0- Escola
462476 | P0- Escola | Group: Grupo de modelo:Grup aula:4934097
1356209 | P0- Escola
1356364 | P0- Escola
1356414 | P0- Escola
4822400 | P0- Escola
4822443 | P0- Escola
4940398 | P0- Escola | Group: Grupo de modelo:Grup aula:4940566
4940654 | P0- Escola | Group: Grupo de modelo:Grup aula:4940822
5091660 | P0- Escola
5095476 | P0- Escola
5327330 | PS1- Vestuari
5375387 | P0- Escola | Group: Grupo de modelo:REV- MODUL Magatzem+ ascensor:101023
5422212 | PC- Coberta STR | Group: Grupo de modelo:BADALOT 2:5309104
5422252 | PC- Coberta STR | Group: Grupo de modelo:BADALOT 2:5309104
5422277 | PC- Coberta STR | Group: Grupo de modelo:BADALOT 2:5309104
5422315 | PC- Coberta STR | Group: Grupo de modelo:BADALOT 2:5309104
5422653 | PC- Coberta STR | Group: Grupo de modelo:BADALOT 2:5309452
5422654 | PC- Coberta STR | Group: Grupo de modelo:BADALOT 2:5309452
5422655 | PC- Coberta STR | Group: Grupo de modelo:BADALOT 2:5309452
5422656 | PC- Coberta STR | Group: Grupo de modelo:BADALOT 2:5309452
5422662 | PC- Coberta STR | Group: Grupo de modelo:BADALOT 2:5309638
5422663 | PC- Coberta STR | Group: Grupo de modelo:BADALOT 2:5309638
5422664 | PC- Coberta STR | Group: Grupo de modelo:BADALOT 2:5309638
5422665 | PC- Coberta STR | Group: Grupo de modelo:BADALOT 2:5309638
5423828 | PC- Coberta STR | Group: Grupo de modelo:BADALOT 1 (elementos excluidos):5302593
5423829 | PC- Coberta STR | Group: Grupo de modelo:BADALOT 1 (elementos excluidos):5302593
5423830 | PC- Coberta STR | Group: Grupo de modelo:BADALOT 1 (elementos excluidos):5302593
5423831 | PC- Coberta STR | Group: Grupo de modelo:BADALOT 1 (elementos excluidos):5302593
5425226 | PC- Coberta STR | Group: Grupo de modelo:BADALOT 3:5425172
5425227 | PC- Coberta STR | Group: Grupo de modelo:BADALOT 3:5425172
5425228 | PC- Coberta STR | Group: Grupo de modelo:BADALOT 3:5425172
5425229 | PC- Coberta STR | Group: Grupo de modelo:BADALOT 3:5425172
6037732 | PS1- Vestuari
6037960 | PS1- Gimnàs

# IfcWallStandardCase: Muro básico:ENV- Ceràmic- 5,5 cm, Muro básico:ENV- Ceràmic- 5,5 cm:5993233
In: P0- Escola
Type - PredefinedType: STANDARD; Material: _Ceràmica- ENV 0.055 m
Type - Pset_WallCommon - IsExternal: yes
Pset_QuantityTakeOff - Reference: ENV- Ceràmic- 5,5 cm; sets with these values: 2
Pset_WallCommon - LoadBearing: no; ExtendToStructure: no; Reference: ENV- Ceràmic- 5,5 cm
Group: Grupo de modelo:Modul Banys (elementos excluidos):100597

# IfcWallStandardCase: Muro básico:ENV- Ceràmic- 7 cm 3, Muro básico:ENV- Ceràmic- 7 cm 3:6000048
In: P0- Escola
Type - PredefinedType: STANDARD; Material: _Ceràmica- ENV 0.07 m
Type - Pset_WallCommon - IsExternal: yes
Pset_QuantityTakeOff - Reference: ENV- Ceràmic- 7 cm 3; sets with these values: 2
Pset_WallCommon - LoadBearing: no; ExtendToStructure: no; Reference: ENV- Ceràmic- 7 cm 3
Group: Grupo de modelo:Modul Banys 2:100913

# IfcWallStandardCase: Muro básico:ENV- Ceràmic- 9 cm (18)
In: P0- Escola
Type - PredefinedType: STANDARD; Material: _Ceràmica- ENV 0.09 m
Type - Pset_WallCommon - IsExternal: yes
Pset_QuantityTakeOff - Reference: ENV- Ceràmic- 9 cm; sets with these values: 2
Pset_WallCommon - LoadBearing: no; ExtendToStructure: no; Reference: ENV- Ceràmic- 9 cm
Name (Muro básico:ENV- Ceràmic- 9 cm:...) | Group
100497 | Grupo de modelo:REV- MODUL Magatzem+ ascensor:101023
100581 | Grupo de modelo:Modul Banys (elementos excluidos):100597
100584 | Grupo de modelo:Modul Banys (elementos excluidos):100597
100585 | Grupo de modelo:Modul Banys (elementos excluidos):100597
100596 | Grupo de modelo:Modul Banys (elementos excluidos):100597
100621 | Grupo de modelo:REV- MODUL Magatzem+ ascensor:101023
100669 | Grupo de modelo:Modul Banys (elementos excluidos):100597
100897 | Grupo de modelo:Modul Banys 2:100913
100900 | Grupo de modelo:Modul Banys 2:100913
100901 | Grupo de modelo:Modul Banys 2:100913
100912 | Grupo de modelo:Modul Banys 2:100913
100919 | Grupo de modelo:Modul Banys 2:100913
101436
101671
102064
102079
102094
5369925 | Grupo de modelo:REV- MODUL Magatzem+ ascensor:101023

# IfcWallStandardCase: Muro básico:ENV- Ceràmic- 9 cm + Arrebossat i pintat (3)
In: P0- Escola
Type - PredefinedType: STANDARD; Material: _Enguixat i pintat- REV 0.01 m, _Ceràmica- ENV 0.09 m
Type - Pset_WallCommon - IsExternal: yes
Pset_QuantityTakeOff - Reference: ENV- Ceràmic- 9 cm + Arrebossat i pintat; sets with these values: 2
Pset_WallCommon - LoadBearing: no; Reference: ENV- Ceràmic- 9 cm + Arrebossat i pintat; ExtendToStructure: no
Name (Muro básico:ENV- Ceràmic- 9 cm + Arrebossat i pintat:...) | Group
100491 | Grupo de modelo:REV- MODUL Magatzem+ ascensor:101023
100583 | Grupo de modelo:Modul Banys (elementos excluidos):100597
100899 | Grupo de modelo:Modul Banys 2:100913

# IfcWallStandardCase: Muro básico:ENV- Guix Laminat una cara- 7 cm (24)
In: P0- Escola
Type - PredefinedType: STANDARD; Material: _Guix laminat- ENV 0.015 m, _Genèric perfils, muntants, rastrells 0.055 m
Type - Pset_WallCommon - IsExternal: yes; ThermalTransmittance: 0.454545 kg/K/s3
Pset_QuantityTakeOff - Reference: ENV- Guix Laminat una cara- 7 cm; sets with these values: 2
Pset_WallCommon - LoadBearing: no; ExtendToStructure: no; Reference: ENV- Guix Laminat una cara- 7 cm
Name (Muro básico:ENV- Guix Laminat una cara- 7 cm:...) | Group
101650
101651
101652
101657
101658
101659
102061 | Grupo de modelo:FUS- Conjunt divisoria aules infantil:337545
336714 | Grupo de modelo:FUS- Conjunt divisoria aules infantil:337545
337004 | Grupo de modelo:FUS- Conjunt divisoria aules infantil:337545
337575 | Grupo de modelo:FUS- Conjunt divisoria aules infantil:337581
337578 | Grupo de modelo:FUS- Conjunt divisoria aules infantil:337581
337579 | Grupo de modelo:FUS- Conjunt divisoria aules infantil:337581
462687 | Grupo de modelo:Grup aula:4934097
462689 | Grupo de modelo:Grup aula:4934097
470713 | Grupo de modelo:Grup aula:4934097
470714 | Grupo de modelo:Grup aula:4934097
4940431 | Grupo de modelo:Grup aula:4940566
4940433 | Grupo de modelo:Grup aula:4940566
4940534 | Grupo de modelo:Grup aula:4940566
4940535 | Grupo de modelo:Grup aula:4940566
4940687 | Grupo de modelo:Grup aula:4940822
4940689 | Grupo de modelo:Grup aula:4940822
4940790 | Grupo de modelo:Grup aula:4940822
4940791 | Grupo de modelo:Grup aula:4940822

# IfcWallStandardCase: Muro básico:ENV- Guix Laminat- 10 cm, Muro básico:ENV- Guix Laminat- 10 cm:101655
In: P0- Escola
Type - PredefinedType: STANDARD; Material: _Guix laminat- ENV 0.015 m, _Genèric perfils, muntants, rastrells 0.07 m, _Guix laminat- ENV 0.015 m
Type - Pset_WallCommon - IsExternal: yes; ThermalTransmittance: 0.357143 kg/K/s3
Pset_QuantityTakeOff - Reference: ENV- Guix Laminat- 10 cm; sets with these values: 2
Pset_WallCommon - LoadBearing: no; ExtendToStructure: no; Reference: ENV- Guix Laminat- 10 cm

# IfcWallStandardCase: Muro básico:ENV- Guix Laminat- 13 cm (36)
In: P0- Escola
Type - PredefinedType: STANDARD; Material: _Guix laminat- ENV 0.03 m, _Genèric perfils, muntants, rastrells 0.07 m, _Guix laminat- ENV 0.03 m
Type - Pset_WallCommon - IsExternal: yes; ThermalTransmittance: 0.357143 kg/K/s3
Pset_QuantityTakeOff - Reference: ENV- Guix Laminat- 13 cm; sets with these values: 2
Pset_WallCommon - LoadBearing: no; ExtendToStructure: no; Reference: ENV- Guix Laminat- 13 cm
Name (Muro básico:ENV- Guix Laminat- 13 cm:...)
101373
101438
101502 | Group: Grupo de modelo:Grup aula:4934097
101517 | Group: Grupo de modelo:Grup aula:4934097
101566
101660
101663
101683
101696
101697
101698
101702
101703
101704
101706
101708
101711
101846
101863
101882
101899
101902
101904
102118
102129
338431
498811 | Group: Grupo de modelo:Grup aula:4934097
4867299
4867837
4940365 | Group: Grupo de modelo:Grup aula:4940566
4940380 | Group: Grupo de modelo:Grup aula:4940566
4940545 | Group: Grupo de modelo:Grup aula:4940566
4940622 | Group: Grupo de modelo:Grup aula:4940822
4940637 | Group: Grupo de modelo:Grup aula:4940822
4940801 | Group: Grupo de modelo:Grup aula:4940822
5383654

# IfcWallStandardCase: Muro básico:ENV- Guix Laminat- 17 cm (6)
In: P0- Escola
Type - PredefinedType: STANDARD; Material: _Guix laminat- ENV 0.03 m, _Genèric perfils, muntants, rastrells 0.046 m, _Guix laminat- ENV 0.025 m, _Genèric perfils, muntants, rastrells 0.046 m, _Guix laminat- ENV 0.03 m
Type - Pset_WallCommon - IsExternal: yes; ThermalTransmittance: 0.271739 kg/K/s3
Pset_QuantityTakeOff - Reference: ENV- Guix Laminat- 17 cm; sets with these values: 2
Pset_WallCommon - LoadBearing: no; ExtendToStructure: no; Reference: ENV- Guix Laminat- 17 cm
Name (Muro básico:ENV- Guix Laminat- 17 cm:...) | Group
462848 | Grupo de modelo:Grup aula:4934097
4940458 | Grupo de modelo:Grup aula:4940566
4940714 | Grupo de modelo:Grup aula:4940822
6043195 | Grupo de modelo:Grup aula:4934097
6043368 | Grupo de modelo:Grup aula:4940566
6043381 | Grupo de modelo:Grup aula:4940822

# IfcWallStandardCase: Muro básico:ENV- Guix Laminat- 18 cm (10)
In: P0- Escola
Type - PredefinedType: STANDARD; Material: _Guix laminat- ENV 0.03 m, _Genèric perfils, muntants, rastrells 0.055 m, _Guix laminat- ENV 0.015 m, _Genèric perfils, muntants, rastrells 0.05 m, _Guix laminat- ENV 0.03 m
Type - Pset_WallCommon - IsExternal: yes; ThermalTransmittance: 0.238095 kg/K/s3
Pset_QuantityTakeOff - Reference: ENV- Guix Laminat- 18 cm; sets with these values: 2
Pset_WallCommon - LoadBearing: no; ExtendToStructure: no; Reference: ENV- Guix Laminat- 18 cm
Name (Muro básico:ENV- Guix Laminat- 18 cm:...)
101536
101539
101540
101542
101543
101544
690551
690652
690774
5382989

# IfcWallStandardCase: Muro básico:ENV- Guix Laminat- 22 cm (3)
In: P0- Escola
Type - PredefinedType: STANDARD; Material: _Guix laminat- ENV 0.015 m, _Genèric perfils, muntants, rastrells 0.085 m, _Genèric perfils, muntants, rastrells 0.085 m, _Guix laminat- ENV 0.015 m
Type - Pset_WallCommon - IsExternal: yes; ThermalTransmittance: 0.147059 kg/K/s3
Pset_QuantityTakeOff - Reference: ENV- Guix Laminat- 22 cm; sets with these values: 2
Pset_WallCommon - LoadBearing: no; ExtendToStructure: no; Reference: ENV- Guix Laminat- 22 cm
Name (Muro básico:ENV- Guix Laminat- 22 cm:...)
101645
101653
692316

# IfcWallStandardCase: Muro básico:ENV- REV- Ceràmic- 14 cm + peces pasta vitrea (3)
In: P0- Escola
Type - PredefinedType: STANDARD; Material: _Enrajolat Gresite- REV- PAV 0.01 m, _Morter Base - REV 0.015 m, _Ceràmica- ENV 0.14 m
Type - Pset_WallCommon - IsExternal: yes
Pset_QuantityTakeOff - Reference: ENV- REV- Ceràmic- 14 cm + peces pasta vitrea; sets with these values: 2
Pset_WallCommon - LoadBearing: no; ExtendToStructure: no; Reference: ENV- REV- Ceràmic- 14 cm + peces pasta vitrea
Name (Muro básico:ENV- REV- Ceràmic- 14 cm + peces pasta vitrea:...)
101705
5095721
5098482

# IfcWallStandardCase: Muro básico:ENV- REV- Ceràmic- 14 cm + peces pasta vitrea 2 caras (7)
In: P0- Escola
Type - PredefinedType: STANDARD; Material: _Enrajolat Gresite- REV- PAV 0.01 m, _Morter Base - REV 0.015 m, _Ceràmica- ENV 0.14 m, _Morter Base - REV 0.015 m, _Enrajolat Gresite- REV- PAV 0.01 m
Type - Pset_WallCommon - IsExternal: yes
Pset_QuantityTakeOff - Reference: ENV- REV- Ceràmic- 14 cm + peces pasta vitrea 2 caras; sets with these values: 2
Pset_WallCommon - LoadBearing: no; ExtendToStructure: no; Reference: ENV- REV- Ceràmic- 14 cm + peces pasta vitrea 2 caras
Name (Muro básico:ENV- REV- Ceràmic- 14 cm + peces pasta vitrea 2 caras:...)
101670
101673
101676
5094137
5094355
5094854
5413706

# IfcWallStandardCase: Muro básico:REV- Alumini fusteries, Muro básico:REV- Alumini fusteries:102325
In: PS1- Vestuari
Type - PredefinedType: STANDARD; Material: _Alumini- T1- Perfil 0.001 m, _Genèric perfils, muntants, rastrells 0.024 m
Type - Pset_WallCommon - IsExternal: yes; ThermalTransmittance: 1.04166 kg/K/s3
Pset_QuantityTakeOff - Reference: REV- Alumini fusteries; sets with these values: 2
Pset_WallCommon - LoadBearing: no; ExtendToStructure: no; Reference: REV- Alumini fusteries

# IfcWallStandardCase: Muro básico:REV- Arrebossat- T1- 1,5 cm (2)
In: PS1- Gimnàs
Type - PredefinedType: STANDARD; Material: _Arrebossat- REV 0.015 m
Type - Pset_WallCommon - IsExternal: yes
Pset_QuantityTakeOff - Reference: REV- Arrebossat- T1- 1,5 cm; sets with these values: 2
Pset_WallCommon - LoadBearing: no; ExtendToStructure: no; Reference: REV- Arrebossat- T1- 1,5 cm
Name (Muro básico:REV- Arrebossat- T1- 1,5 cm:...)
101174
101180

# IfcWallStandardCase: Muro básico:REV- Badalot- Xapa + Aillament (40)
In: PC- Coberta STR
Type - PredefinedType: STANDARD; Material: _REV- Xapa minionda 0.01 m, _Genèric perfils, muntants, rastrells 0.02 m, _Aillament 0.07 m
Type - Pset_WallCommon - IsExternal: yes; ThermalTransmittance: 1.24993 kg/K/s3
Pset_QuantityTakeOff - Reference: REV- Badalot- Xapa + Aillament; sets with these values: 2
Pset_WallCommon - LoadBearing: no; ExtendToStructure: no; Reference: REV- Badalot- Xapa + Aillament
Name (Muro básico:REV- Badalot- Xapa + Aillament:...) | Group
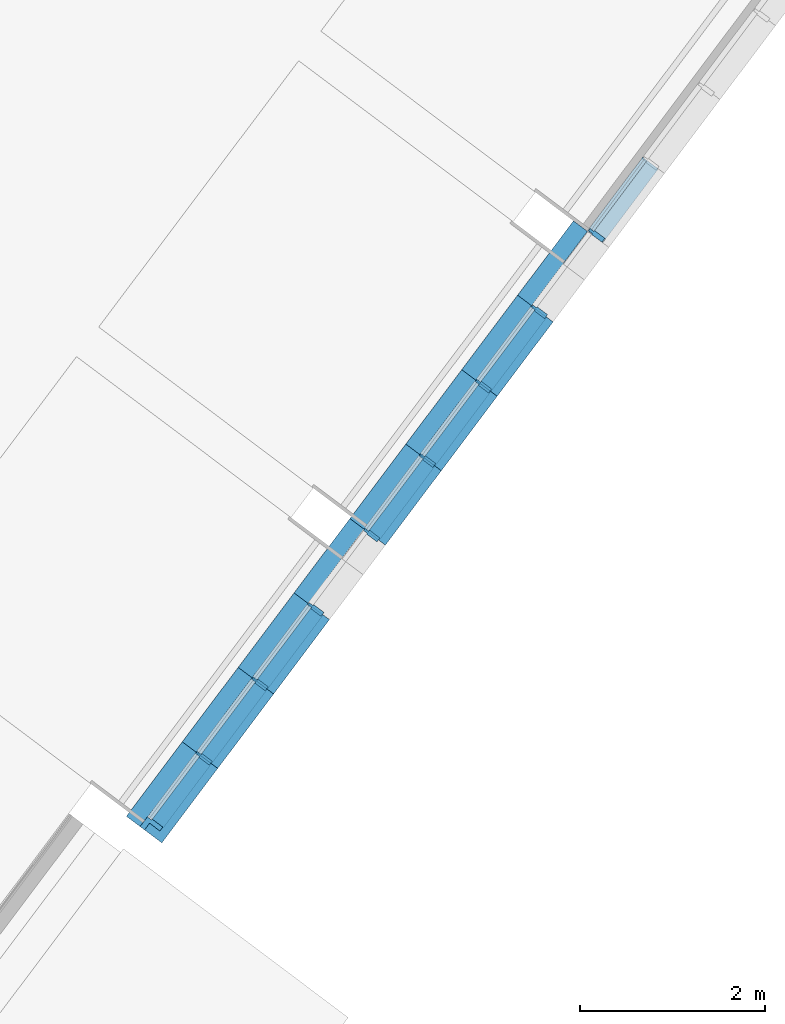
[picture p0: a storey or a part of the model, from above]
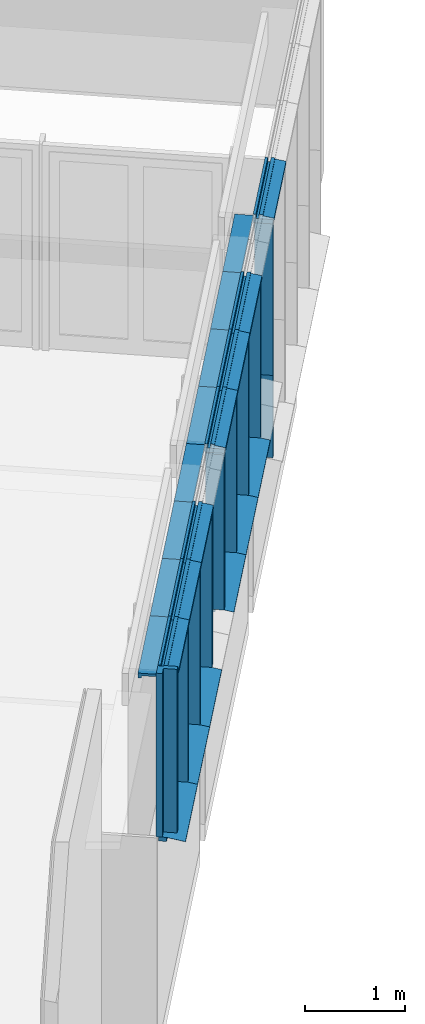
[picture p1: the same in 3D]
Properties of the parts of a building model (IFC2X3), part 5 of 6

# IfcWallStandardCase: Muro básico:REV- Badalot- Xapa + Aillament (40)
Name (Muro básico:REV- Badalot- Xapa + Aillament:...) | Group
5305478 | Grupo de modelo:BADALOT 1 (elementos excluidos):5302593
5305701 | Grupo de modelo:BADALOT 1 (elementos excluidos):5302593
5305773 | Grupo de modelo:BADALOT 1 (elementos excluidos):5302593
5305800 | Grupo de modelo:BADALOT 1 (elementos excluidos):5302593
5305823 | Grupo de modelo:BADALOT 1 (elementos excluidos):5302593
5306155 | Grupo de modelo:BADALOT 1 (elementos excluidos):5302593
5306156 | Grupo de modelo:BADALOT 1 (elementos excluidos):5302593
5306157 | Grupo de modelo:BADALOT 1 (elementos excluidos):5302593
5309105 | Grupo de modelo:BADALOT 2:5309104
5309106 | Grupo de modelo:BADALOT 2:5309104
5309107 | Grupo de modelo:BADALOT 2:5309104
5309108 | Grupo de modelo:BADALOT 2:5309104
5309109 | Grupo de modelo:BADALOT 2:5309104
5309110 | Grupo de modelo:BADALOT 2:5309104
5309111 | Grupo de modelo:BADALOT 2:5309104
5309112 | Grupo de modelo:BADALOT 2:5309104
5309453 | Grupo de modelo:BADALOT 2:5309452
5309454 | Grupo de modelo:BADALOT 2:5309452
5309455 | Grupo de modelo:BADALOT 2:5309452
5309456 | Grupo de modelo:BADALOT 2:5309452
5309457 | Grupo de modelo:BADALOT 2:5309452
5309458 | Grupo de modelo:BADALOT 2:5309452
5309459 | Grupo de modelo:BADALOT 2:5309452
5309460 | Grupo de modelo:BADALOT 2:5309452
5309639 | Grupo de modelo:BADALOT 2:5309638
5309640 | Grupo de modelo:BADALOT 2:5309638
5309641 | Grupo de modelo:BADALOT 2:5309638
5309642 | Grupo de modelo:BADALOT 2:5309638
5309643 | Grupo de modelo:BADALOT 2:5309638
5309644 | Grupo de modelo:BADALOT 2:5309638
5309645 | Grupo de modelo:BADALOT 2:5309638
5309646 | Grupo de modelo:BADALOT 2:5309638
5425173 | Grupo de modelo:BADALOT 3:5425172
5425174 | Grupo de modelo:BADALOT 3:5425172
5425175 | Grupo de modelo:BADALOT 3:5425172
5425176 | Grupo de modelo:BADALOT 3:5425172
5425177 | Grupo de modelo:BADALOT 3:5425172
5425179 | Grupo de modelo:BADALOT 3:5425172
5425180 | Grupo de modelo:BADALOT 3:5425172
5425181 | Grupo de modelo:BADALOT 3:5425172

# IfcWallStandardCase: Muro básico:REV- Enrajolat Gresite- T1- 2,5 cm (8)
In: PS1- Vestuari
Type - PredefinedType: STANDARD; Material: _Enrajolat Gresite- REV- PAV 0.01 m, _Morter Base - REV 0.015 m
Type - Pset_WallCommon - IsExternal: yes
Pset_QuantityTakeOff - Reference: REV- Enrajolat Gresite- T1- 2,5 cm; sets with these values: 2
Pset_WallCommon - LoadBearing: no; ExtendToStructure: no; Reference: REV- Enrajolat Gresite- T1- 2,5 cm
Name (Muro básico:REV- Enrajolat Gresite- T1- 2,5 cm:...)
101344
101345
101346
101347
101348
101349
5327194
6038118

# IfcWallStandardCase: Muro básico:REV- Enrajolat peces pasta vitrea- T1- int- 2,5 cm (25)
In: P0- Escola
Type - PredefinedType: STANDARD; Material: _Enrajolat Gresite- REV- PAV 0.01 m, _Morter Base - REV 0.015 m
Type - Pset_WallCommon - IsExternal: yes
Pset_QuantityTakeOff - Reference: REV- Enrajolat peces pasta vitrea- T1- int- 2,5 cm; sets with these values: 2
Pset_WallCommon - LoadBearing: no; ExtendToStructure: no; Reference: REV- Enrajolat peces pasta vitrea- T1- int- 2,5 cm
Name (Muro básico:REV- Enrajolat peces pasta vitrea- T1- int- 2,5 cm:...)
101644
101682
101694
101695
101973
101974
101975
101976
101981
102020
102021
1355790
1356755
4165669 | Group: Grupo de modelo:Grup aula:4934097
4165723 | Group: Grupo de modelo:Grup aula:4934097
4165751 | Group: Grupo de modelo:Grup aula:4934097
4940554 | Group: Grupo de modelo:Grup aula:4940566
4940555 | Group: Grupo de modelo:Grup aula:4940566
4940556 | Group: Grupo de modelo:Grup aula:4940566
4940810 | Group: Grupo de modelo:Grup aula:4940822
4940811 | Group: Grupo de modelo:Grup aula:4940822
4940812 | Group: Grupo de modelo:Grup aula:4940822
5091661
5091662
5091663

# IfcWallStandardCase: Muro básico:REV- Extradossat resines fenòliques- T1- 2,5 cm (2)
In: P0- Escola
Type - PredefinedType: STANDARD; Material: _HPL- T1- REV 0.012 m, _Genèric perfils, muntants, rastrells 0.008 m
Type - Pset_WallCommon - IsExternal: yes; ThermalTransmittance: 3.125 kg/K/s3
Pset_QuantityTakeOff - Reference: REV- Extradossat resines fenòliques- T1- 2,5 cm; sets with these values: 2
Pset_WallCommon - LoadBearing: no; ExtendToStructure: no; Reference: REV- Extradossat resines fenòliques- T1- 2,5 cm
Name (Muro básico:REV- Extradossat resines fenòliques- T1- 2,5 cm:...)
101664
101665

# IfcWallStandardCase: Muro básico:REV- Fusta + Guix Laminat Extradossat- Aillament- T1- 7,5 cm (12)
In: P0- Escola
Type - PredefinedType: STANDARD; Material: _Fusta massisa- T1 0.015 m, _Guix laminat- ENV 0.015 m, _Aillament 0.045 m
Type - Pset_WallCommon - IsExternal: no
Pset_QuantityTakeOff - Reference: REV- Fusta + Guix Laminat Extradossat- Aillament- T1- 7,5 cm; sets with these values: 2
Pset_WallCommon - LoadBearing: no; ExtendToStructure: no; Reference: REV- Fusta + Guix Laminat Extradossat- Aillament- T1- 7,5 cm
Name (Muro básico:REV- Fusta + Guix Laminat Extradossat- Aillament- T1- 7,5 cm:...)
4911767
4911854
4912005
4912082
4912133
4912337
4912392
4912620
4912690
4923421
4924244
4927017

# IfcWallStandardCase: Muro básico:REV- Fusta- T1- 1,5cm, Muro básico:REV- Fusta- T1- 1,5cm:6000472
In: P0- Escola
Type - PredefinedType: STANDARD; Material: _Fusta massisa- T1- REV- PAV 0.015 m
Type - Pset_WallCommon - IsExternal: no
Pset_QuantityTakeOff - Reference: REV- Fusta- T1- 1,5cm; sets with these values: 2
Pset_WallCommon - LoadBearing: no; ExtendToStructure: no; Reference: REV- Fusta- T1- 1,5cm
Group: Grupo de modelo:Modul Banys (elementos excluidos):100597

# IfcWallStandardCase: Muro básico:REV- Fusta- T1- 13,5 cm, Muro básico:REV- Fusta- T1- 13,5 cm:100603
In: P0- Escola
Type - PredefinedType: STANDARD; Material: _Fusta massisa- T1- REV- PAV 0.015 m, _Genèric perfils, muntants, rastrells 0.12 m
Type - Pset_WallCommon - IsExternal: no; ThermalTransmittance: 0.208333 kg/K/s3
Pset_QuantityTakeOff - Reference: REV- Fusta- T1- 13,5 cm; sets with these values: 2
Pset_WallCommon - LoadBearing: no; ExtendToStructure: no; Reference: REV- Fusta- T1- 13,5 cm
Group: Grupo de modelo:REV- MODUL Magatzem+ ascensor:101023

# IfcWallStandardCase: Muro básico:REV- Fusta- T1- 3,5 cm (34)
Type - PredefinedType: STANDARD; Material: _Fusta massisa- T1- REV- PAV 0.015 m, _Genèric perfils, muntants, rastrells 0.02 m
Type - Pset_WallCommon - IsExternal: no; ThermalTransmittance: 1.25 kg/K/s3
Pset_QuantityTakeOff - Reference: REV- Fusta- T1- 3,5 cm; sets with these values: 2
Pset_WallCommon - LoadBearing: no; ExtendToStructure: no; Reference: REV- Fusta- T1- 3,5 cm
Name (Muro básico:REV- Fusta- T1- 3,5 cm:...) | In
100498 | P0- Escola | Group: Grupo de modelo:REV- MODUL Magatzem+ ascensor:101023
100586 | P0- Escola | Group: Grupo de modelo:Modul Banys (elementos excluidos):100597
100587 | P0- Escola | Group: Grupo de modelo:Modul Banys (elementos excluidos):100597
100902 | P0- Escola | Group: Grupo de modelo:Modul Banys 2:100913
100903 | P0- Escola | Group: Grupo de modelo:Modul Banys 2:100913
101138 | PS1- Gimnàs
101145 | PS1- Gimnàs
101161 | PS1- Gimnàs
101162 | PS1- Gimnàs
101163 | PS1- Gimnàs
101164 | PS1- Gimnàs
101165 | PS1- Gimnàs
101166 | PS1- Gimnàs
101167 | PS1- Gimnàs
101173 | PS1- Gimnàs
101179 | PS1- Gimnàs
101297 | PS1- Gimnàs
101439 | P0- Escola
101440 | P0- Escola
101537 | P0- Escola
101701 | P0- Escola
101710 | P0- Escola
462474 | P0- Escola | Group: Grupo de modelo:Grup aula:4934097
498986 | P0- Escola | Group: Grupo de modelo:Grup aula:4934097
499243 | P0- Escola | Group: Grupo de modelo:Grup aula:4934097
4940396 | P0- Escola | Group: Grupo de modelo:Grup aula:4940566
4940546 | P0- Escola | Group: Grupo de modelo:Grup aula:4940566
4940547 | P0- Escola | Group: Grupo de modelo:Grup aula:4940566
4940652 | P0- Escola | Group: Grupo de modelo:Grup aula:4940822
4940802 | P0- Escola | Group: Grupo de modelo:Grup aula:4940822
4940803 | P0- Escola | Group: Grupo de modelo:Grup aula:4940822
5092237 | P0- Escola
5369419 | P0- Escola | Group: Grupo de modelo:REV- MODUL Magatzem+ ascensor:101023
5383943 | P0- Escola

# IfcWallStandardCase: Muro básico:REV- Fusta- T1- 5 cm (4)
In: P0- Escola
Type - PredefinedType: STANDARD; Material: _Fusta massisa- T1- REV- PAV 0.02 m, _Genèric perfils, muntants, rastrells 0.03 m
Type - Pset_WallCommon - IsExternal: no; ThermalTransmittance: 0.833333 kg/K/s3
Pset_QuantityTakeOff - Reference: REV- Fusta- T1- 5 cm; sets with these values: 2
Pset_WallCommon - LoadBearing: no; ExtendToStructure: no; Reference: REV- Fusta- T1- 5 cm
Name (Muro básico:REV- Fusta- T1- 5 cm:...)
101649
102019
4926207
4926676

# IfcWallStandardCase: Muro básico:REV- Fusta- T1- 6 cm (3)
In: P0- Escola
Type - PredefinedType: STANDARD; Material: _Fusta massisa- T1- REV- PAV 0.06 m
Type - Pset_WallCommon - IsExternal: no
Pset_QuantityTakeOff - Reference: REV- Fusta- T1- 6 cm; sets with these values: 2
Pset_WallCommon - LoadBearing: no; ExtendToStructure: no; Reference: REV- Fusta- T1- 6 cm
Name (Muro básico:REV- Fusta- T1- 6 cm:...) | Group
2141142 | Grupo de modelo:BANY1:2141168
2333994 | Grupo de modelo:BANY1:2334016
2334644 | Grupo de modelo:BANY1:2334666

# IfcWallStandardCase: Muro básico:REV- Fusta- T1- 6,5 cm (26)
In: P0- Escola
Type - PredefinedType: STANDARD; Material: _Fusta massisa- T1- REV- PAV 0.015 m, _Genèric perfils, muntants, rastrells 0.05 m
Type - Pset_WallCommon - IsExternal: no; ThermalTransmittance: 0.5 kg/K/s3
Pset_QuantityTakeOff - Reference: REV- Fusta- T1- 6,5 cm; sets with these values: 2
Pset_WallCommon - LoadBearing: no; ExtendToStructure: no; Reference: REV- Fusta- T1- 6,5 cm
Name (Muro básico:REV- Fusta- T1- 6,5 cm:...) | Group
100494 | Grupo de modelo:REV- MODUL Magatzem+ ascensor:101023
100667
100828 | Grupo de modelo:REV- grup revestiment pilar:100838
100834 | Grupo de modelo:REV- grup revestiment pilar:100838
100836 | Grupo de modelo:REV- grup revestiment pilar:100838
100837 | Grupo de modelo:REV- grup revestiment pilar:100838
100843 | Grupo de modelo:REV- grup revestiment pilar:100853
100849 | Grupo de modelo:REV- grup revestiment pilar:100853
100851 | Grupo de modelo:REV- grup revestiment pilar:100853
100852 | Grupo de modelo:REV- grup revestiment pilar:100853
100917
101005 | Grupo de modelo:REV- grup revestiment pilar:101015
101011 | Grupo de modelo:REV- grup revestiment pilar:101015
101013 | Grupo de modelo:REV- grup revestiment pilar:101015
101014 | Grupo de modelo:REV- grup revestiment pilar:101015
115712 | Grupo de modelo:REV- grup revestiment pilar:114974
115718 | Grupo de modelo:REV- grup revestiment pilar:114974
115720 | Grupo de modelo:REV- grup revestiment pilar:114974
115721 | Grupo de modelo:REV- grup revestiment pilar:114974
115731 | Grupo de modelo:REV- grup revestiment pilar:114959
115737 | Grupo de modelo:REV- grup revestiment pilar:114959
115739 | Grupo de modelo:REV- grup revestiment pilar:114959
115740 | Grupo de modelo:REV- grup revestiment pilar:114959
5387739
5387745
5387747

# IfcWallStandardCase: Muro básico:REV- Guix Laminat Extradossat + acabat de fusta- T1- 8 cm (3)
In: PS1- Gimnàs
Type - PredefinedType: STANDARD; Material: _Fusta massisa- T1- REV- PAV 0.015 m, _Guix laminat- ENV 0.02 m, _Genèric perfils, muntants, rastrells 0.045 m
Type - Pset_WallCommon - IsExternal: no; ThermalTransmittance: 0.555556 kg/K/s3
Pset_QuantityTakeOff - Reference: REV- Guix Laminat Extradossat + acabat de fusta- T1- 8 cm; sets with these values: 2
Pset_WallCommon - LoadBearing: no; ExtendToStructure: no; Reference: REV- Guix Laminat Extradossat + acabat de fusta- T1- 8 cm
Name (Muro básico:REV- Guix Laminat Extradossat + acabat de fusta- T1- 8 cm:...)
101262
101263
101264

# IfcWallStandardCase: Muro básico:REV- Guix Laminat Extradossat- Acabat Vinilic- T1- 5 cm (5)
In: P0- Escola
Type - PredefinedType: STANDARD; Material: _Vinílic- REV 0.005 m, _Guix laminat- ENV 0.015 m, _Aillament 0.03 m
Type - Pset_WallCommon - IsExternal: no
Pset_QuantityTakeOff - Reference: REV- Guix Laminat Extradossat- Acabat Vinilic- T1- 5 cm; sets with these values: 2
Pset_WallCommon - LoadBearing: no; ExtendToStructure: no; Reference: REV- Guix Laminat Extradossat- Acabat Vinilic- T1- 5 cm
Group: Grupo de modelo:BANY PRESTATGE (elementos excluidos):2334870
Name (Muro básico:REV- Guix Laminat Extradossat- Acabat Vinilic- T1- 5 cm:...)
341974
2327238
2327315
2327395
2328023

# IfcWallStandardCase: Muro básico:REV- Guix Laminat Extradossat- Acabat Vinilic- T1- 5 cm 2 (5)
In: P0- Escola
Type - PredefinedType: STANDARD; Material: _Vinílic- REV 0.005 m, _Guix laminat- ENV 0.015 m, _Aillament 0.03 m
Type - Pset_WallCommon - IsExternal: no
Pset_QuantityTakeOff - Reference: REV- Guix Laminat Extradossat- Acabat Vinilic- T1- 5 cm 2; sets with these values: 2
Pset_WallCommon - LoadBearing: no; ExtendToStructure: no; Reference: REV- Guix Laminat Extradossat- Acabat Vinilic- T1- 5 cm 2
Name (Muro básico:REV- Guix Laminat Extradossat- Acabat Vinilic- T1- 5 cm 2:...)
5411348
5411350
5411351
5411352
5411353

# IfcWallStandardCase: Muro básico:REV- Guix Laminat Extradossat- Acabat Vinilic- T1- 6,5 cm, Muro básico:REV- Guix Laminat Extradossat- Acabat Vinilic- T1- 6,5 cm:5410382
In: P0- Escola
Type - PredefinedType: STANDARD; Material: _Vinílic- REV 0.005 m, _Guix laminat- ENV 0.015 m, _Aillament 0.045 m
Type - Pset_WallCommon - IsExternal: no
Pset_QuantityTakeOff - Reference: REV- Guix Laminat Extradossat- Acabat Vinilic- T1- 6,5 cm; sets with these values: 2
Pset_WallCommon - LoadBearing: no; ExtendToStructure: no; Reference: REV- Guix Laminat Extradossat- Acabat Vinilic- T1- 6,5 cm

# IfcWallStandardCase: Muro básico:REV- Guix Laminat Extradossat- Aillament- T1- 3,5 cm (6)
In: P0- Escola
Type - PredefinedType: STANDARD; Material: _Guix laminat- ENV 0.02 m, _Aillament 0.015 m
Type - Pset_WallCommon - IsExternal: no
Pset_QuantityTakeOff - Reference: REV- Guix Laminat Extradossat- Aillament- T1- 3,5 cm; sets with these values: 2
Pset_WallCommon - LoadBearing: no; ExtendToStructure: no; Reference: REV- Guix Laminat Extradossat- Aillament- T1- 3,5 cm
Name (Muro básico:REV- Guix Laminat Extradossat- Aillament- T1- 3,5 cm:...)
100701 | Group: Grupo de modelo:REV- Acabats interiors modul:100748
100772 | Group: Grupo de modelo:REV- Acabats interiors modul:100819
100951
101815
101982
102000

# IfcWallStandardCase: Muro básico:REV- Guix Laminat Extradossat- Aillament- T1- 6,5 cm (112)
Type - PredefinedType: STANDARD; Material: _Guix laminat- ENV 0.02 m, _Aillament 0.045 m
Type - Pset_WallCommon - IsExternal: no
Pset_QuantityTakeOff - Reference: REV- Guix Laminat Extradossat- Aillament- T1- 6,5 cm; sets with these values: 2
Pset_WallCommon - LoadBearing: no; ExtendToStructure: no; Reference: REV- Guix Laminat Extradossat- Aillament- T1- 6,5 cm
Name (Muro básico:REV- Guix Laminat Extradossat- Aillament- T1- 6,5 cm:...) | In
100530 | P0- Escola
100588 | P0- Escola | Group: Grupo de modelo:Modul Banys (elementos excluidos):100597
100589 | P0- Escola | Group: Grupo de modelo:Modul Banys (elementos excluidos):100597
100590 | P0- Escola | Group: Grupo de modelo:Modul Banys (elementos excluidos):100597
100591 | P0- Escola | Group: Grupo de modelo:Modul Banys (elementos excluidos):100597
100592 | P0- Escola | Group: Grupo de modelo:Modul Banys (elementos excluidos):100597
100593 | P0- Escola | Group: Grupo de modelo:Modul Banys (elementos excluidos):100597
100710 | P0- Escola | Group: Grupo de modelo:REV- Acabats interiors modul:100748
100711 | P0- Escola | Group: Grupo de modelo:REV- Acabats interiors modul:100748
100741 | P0- Escola
100781 | P0- Escola | Group: Grupo de modelo:REV- Acabats interiors modul:100819
100782 | P0- Escola | Group: Grupo de modelo:REV- Acabats interiors modul:100819
100812 | P0- Escola
100904 | P0- Escola | Group: Grupo de modelo:Modul Banys 2:100913
100905 | P0- Escola | Group: Grupo de modelo:Modul Banys 2:100913
100906 | P0- Escola | Group: Grupo de modelo:Modul Banys 2:100913
100907 | P0- Escola | Group: Grupo de modelo:Modul Banys 2:100913
100908 | P0- Escola | Group: Grupo de modelo:Modul Banys 2:100913
100909 | P0- Escola | Group: Grupo de modelo:Modul Banys 2:100913
100960 | P0- Escola
100961 | P0- Escola
100991 | P0- Escola
101090 | P0- Escola | Group: Grupo de modelo:Grup aula:4934097
101202 | PS1- Gimnàs | Group: Grupo de modelo:SOS- grup sostre i tabica gimnàs:101203
101231 | PS1- Gimnàs | Group: Grupo de modelo:SOS- grup sostre i tabica gimnàs:101232
101247 | PS1- Gimnàs | Group: Grupo de modelo:SOS- grup sostre i tabica gimnàs:101248
101395 | P0- Escola
101419 | P0- Escola
101538 | P0- Escola
101643 | P0- Escola
101646 | P0- Escola
101647 | P0- Escola
101648 | P0- Escola
101654 | P0- Escola
101656 | P0- Escola
101722 | P0- Escola
101737 | P0- Escola
101738 | P0- Escola
101739 | P0- Escola
101740 | P0- Escola
101755 | P0- Escola
101770 | P0- Escola
101785 | P0- Escola
101830 | P0- Escola
101845 | P0- Escola
101861 | P0- Escola
101862 | P0- Escola
101878 | P0- Escola
101879 | P0- Escola
101880 | P0- Escola
101881 | P0- Escola
101897 | P0- Escola
101898 | P0- Escola
101903 | P0- Escola
101905 | P0- Escola
101920 | P0- Escola
101935 | P0- Escola
101969 | P0- Escola
101997 | P0- Escola
101998 | P0- Escola
101999 | P0- Escola
102015 | P0- Escola
102016 | P0- Escola
102017 | P0- Escola
462692 | P0- Escola | Group: Grupo de modelo:Grup aula:4934097
462693 | P0- Escola | Group: Grupo de modelo:Grup aula:4934097
462701 | P0- Escola | Group: Grupo de modelo:Grup aula:4934097
462702 | P0- Escola | Group: Grupo de modelo:Grup aula:4934097
462704 | P0- Escola | Group: Grupo de modelo:Grup aula:4934097
462752 | P0- Escola | Group: Grupo de modelo:Grup aula:4934097
462753 | P0- Escola | Group: Grupo de modelo:Grup aula:4934097
462755 | P0- Escola | Group: Grupo de modelo:Grup aula:4934097
4166022 | P0- Escola | Group: Grupo de modelo:Grup aula:4934097
4867485 | P0- Escola
4867582 | P0- Escola
4894141 | P0- Escola
4915320 | P0- Escola
4940350 | P0- Escola | Group: Grupo de modelo:Grup aula:4940566
4940434 | P0- Escola | Group: Grupo de modelo:Grup aula:4940566
4940435 | P0- Escola | Group: Grupo de modelo:Grup aula:4940566
4940443 | P0- Escola | Group: Grupo de modelo:Grup aula:4940566
4940444 | P0- Escola | Group: Grupo de modelo:Grup aula:4940566
4940446 | P0- Escola | Group: Grupo de modelo:Grup aula:4940566
4940448 | P0- Escola | Group: Grupo de modelo:Grup aula:4940566
4940449 | P0- Escola | Group: Grupo de modelo:Grup aula:4940566
4940450 | P0- Escola | Group: Grupo de modelo:Grup aula:4940566
4940557 | P0- Escola | Group: Grupo de modelo:Grup aula:4940566
4940607 | P0- Escola | Group: Grupo de modelo:Grup aula:4940822
4940690 | P0- Escola | Group: Grupo de modelo:Grup aula:4940822
4940691 | P0- Escola | Group: Grupo de modelo:Grup aula:4940822
4940699 | P0- Escola | Group: Grupo de modelo:Grup aula:4940822
4940700 | P0- Escola | Group: Grupo de modelo:Grup aula:4940822
4940702 | P0- Escola | Group: Grupo de modelo:Grup aula:4940822
4940704 | P0- Escola | Group: Grupo de modelo:Grup aula:4940822
4940705 | P0- Escola | Group: Grupo de modelo:Grup aula:4940822
4940706 | P0- Escola | Group: Grupo de modelo:Grup aula:4940822
4940813 | P0- Escola | Group: Grupo de modelo:Grup aula:4940822
5089692 | P0- Escola
5089893 | P0- Escola
5090163 | P0- Escola
5090801 | P0- Escola
5091003 | P0- Escola
5091664 | P0- Escola
5091750 | P0- Escola
5387569 | P0- Escola
5389860 | P0- Escola
5406175 | P0- Escola | Group: Grupo de modelo:Modul Banys (elementos excluidos):100597
5406243 | P0- Escola | Group: Grupo de modelo:Modul Banys 2:100913
5407746 | P0- Escola
5411048 | P0- Escola
5411849 | P0- Escola
5426272 | P0- Escola

# IfcWallStandardCase: Muro básico:REV- Guix Laminat Extradossat- Aillament- T1- 7,5 cm (3)
In: P0- Escola
Type - PredefinedType: STANDARD; Material: _Guix laminat- ENV 0.03 m, _Aillament 0.045 m
Type - Pset_WallCommon - IsExternal: no
Pset_QuantityTakeOff - Reference: REV- Guix Laminat Extradossat- Aillament- T1- 7,5 cm; sets with these values: 2
Pset_WallCommon - LoadBearing: no; ExtendToStructure: no; Reference: REV- Guix Laminat Extradossat- Aillament- T1- 7,5 cm
Name (Muro básico:REV- Guix Laminat Extradossat- Aillament- T1- 7,5 cm:...) | Group
100952 | Grupo de modelo:Grup aula:4934097
4940349 | Grupo de modelo:Grup aula:4940566
4940606 | Grupo de modelo:Grup aula:4940822

# IfcWallStandardCase: Muro básico:REV- Guix Laminat Extradossat- Aïllament- T1- 5 cm (5)
In: P0- Escola
Type - PredefinedType: STANDARD; Material: _Guix laminat- ENV 0.015 m, _Aillament 0.035 m
Type - Pset_WallCommon - IsExternal: no
Pset_QuantityTakeOff - Reference: REV- Guix Laminat Extradossat- Aïllament- T1- 5 cm; sets with these values: 2
Pset_WallCommon - LoadBearing: no; ExtendToStructure: no; Reference: REV- Guix Laminat Extradossat- Aïllament- T1- 5 cm
Name (Muro básico:REV- Guix Laminat Extradossat- Aïllament- T1- 5 cm:...)
101900
101901
102060 | Group: Grupo de modelo:FUS- Conjunt divisoria aules infantil:337545
341098 | Group: Grupo de modelo:FUS- Conjunt divisoria aules infantil:337581
342699

# IfcWallStandardCase: Muro básico:REV- Guix Laminat Extradossat- T1- 6,5 cm (13)
In: P0- Escola
Type - PredefinedType: STANDARD; Material: _Guix laminat- ENV 0.015 m, _Genèric perfils, muntants, rastrells 0.05 m
Type - Pset_WallCommon - IsExternal: no; ThermalTransmittance: 0.5 kg/K/s3
Pset_QuantityTakeOff - Reference: REV- Guix Laminat Extradossat- T1- 6,5 cm; sets with these values: 2
Pset_WallCommon - LoadBearing: no; ExtendToStructure: no; Reference: REV- Guix Laminat Extradossat- T1- 6,5 cm
Name (Muro básico:REV- Guix Laminat Extradossat- T1- 6,5 cm:...) | Group
100829 | Grupo de modelo:REV- grup revestiment pilar:100838
100835 | Grupo de modelo:REV- grup revestiment pilar:100838
100844 | Grupo de modelo:REV- grup revestiment pilar:100853
100850 | Grupo de modelo:REV- grup revestiment pilar:100853
101006 | Grupo de modelo:REV- grup revestiment pilar:101015
101012 | Grupo de modelo:REV- grup revestiment pilar:101015
101441
115713 | Grupo de modelo:REV- grup revestiment pilar:114974
115719 | Grupo de modelo:REV- grup revestiment pilar:114974
115732 | Grupo de modelo:REV- grup revestiment pilar:114959
115738 | Grupo de modelo:REV- grup revestiment pilar:114959
5387740
5387746

# IfcWallStandardCase: Muro básico:REV- Pissarra (3)
In: P0- Escola
Type - PredefinedType: STANDARD; Material: _Pissarra- T1- Rev 0.01 m
Type - Pset_WallCommon - IsExternal: yes
Pset_QuantityTakeOff - Reference: REV- Pissarra; sets with these values: 2
Pset_WallCommon - LoadBearing: no; ExtendToStructure: no; Reference: REV- Pissarra
Name (Muro básico:REV- Pissarra:...) | Group
462475 | Grupo de modelo:Grup aula:4934097
4940397 | Grupo de modelo:Grup aula:4940566
4940653 | Grupo de modelo:Grup aula:4940822

# IfcWallStandardCase: Muro básico:REV- Resines fenòloques- T1- 3,5 cm 2 (2)
In: P0- Escola
Type - PredefinedType: STANDARD; Material: _HPL- T1- REV 0.015 m, _Genèric perfils, muntants, rastrells 0.02 m
Type - Pset_WallCommon - IsExternal: no; ThermalTransmittance: 1.25 kg/K/s3
Pset_QuantityTakeOff - Reference: REV- Resines fenòloques- T1- 3,5 cm 2; sets with these values: 2
Pset_WallCommon - LoadBearing: no; ExtendToStructure: no; Reference: REV- Resines fenòloques- T1- 3,5 cm 2
Name (Muro básico:REV- Resines fenòloques- T1- 3,5 cm 2:...)
4815336
4815793

# IfcWallStandardCase: Muro básico:REV- Vinilic- T1- 1 cm (7)
In: P0- Escola
Type - PredefinedType: STANDARD; Material: _Vinílic- REV 0.01 m
Type - Pset_WallCommon - IsExternal: no
Pset_QuantityTakeOff - Reference: REV- Vinilic- T1- 1 cm; sets with these values: 2
Pset_WallCommon - LoadBearing: no; ExtendToStructure: no; Reference: REV- Vinilic- T1- 1 cm
Name (Muro básico:REV- Vinilic- T1- 1 cm:...) | Group
2326596 | Grupo de modelo:BANY PRESTATGE (elementos excluidos):2334870
5411349
5412722 | Grupo de modelo:BANY PRESTATGE (elementos excluidos):2334870
5412776
5412777
5412965 | Grupo de modelo:BANY PRESTATGE (elementos excluidos):2334870
5412966 | Grupo de modelo:BANY PRESTATGE (elementos excluidos):2334870

# IfcWallStandardCase: Muro básico:REV- Xapa + aillament (3)
In: P0- Escola
Type - PredefinedType: STANDARD; Material: _Alumini- T1- Perfil 0.01 m, _Aillament 0.06 m
Type - Pset_WallCommon - IsExternal: yes; ThermalTransmittance: 23000 kg/K/s3
Pset_QuantityTakeOff - Reference: REV- Xapa + aillament; sets with these values: 2
Pset_WallCommon - LoadBearing: no; ExtendToStructure: no; Reference: REV- Xapa + aillament
Name (Muro básico:REV- Xapa + aillament:...)
5425847
5426065
5426118

# IfcWindow: MC- Alu- Conjunt finestra basculant- 68x68 cm:MC- Alu- Conjunt finestra basculant- 68x68 cm (189)
Type - ParameterTakesPrecedence: no; Sizeable: no; Material: _Vidre, _Alumini- T1- Perfil
Type - Pset_WindowCommon - IsExternal: no
Pset_QuantityTakeOff - Reference: MC- Alu- Conjunt finestra basculant- 68x68 cm
Pset_WindowCommon - Reference: MC- Alu- Conjunt finestra basculant- 68x68 cm
Name (MC- Alu- Conjunt finestra basculant- 68x68 cm:MC- Alu- Conjunt finestra basculant- 68x68 cm:...) | In | OverallHeight (m) | OverallWidth (m) | Group
102308 | PS1- Vestuari | 1.5475 | 0.9775 | Pset_WindowCommon - IsExternal: yes
102303 | PS1- Vestuari | 1.5475 | 0.592 | Pset_WindowCommon - IsExternal: yes
102293 | PS1- Vestuari | 1.5475 | 0.592 | Pset_WindowCommon - IsExternal: yes
102288 | PS1- Vestuari | 1.5475 | 0.879 | Pset_WindowCommon - IsExternal: yes
102283 | PS1- Vestuari | 1.5475 | 0.79 | Pset_WindowCommon - IsExternal: yes
102273 | PS1- Vestuari | 1.5475 | 0.932 | Pset_WindowCommon - IsExternal: yes
102278 | PS1- Vestuari | 1.5475 | 0.907 | Pset_WindowCommon - IsExternal: yes
102263 | PS1- Vestuari | 1.5475 | 0.904 | Pset_WindowCommon - IsExternal: yes
102258 | PS1- Vestuari | 1.5475 | 0.904 | Pset_WindowCommon - IsExternal: yes
102253 | PS1- Vestuari | 1.5475 | 0.904 | Pset_WindowCommon - IsExternal: yes
102248 | PS1- Vestuari | 1.5475 | 0.904 | Pset_WindowCommon - IsExternal: yes
102243 | PS1- Vestuari | 1.5475 | 0.904 | Pset_WindowCommon - IsExternal: yes
102238 | PS1- Vestuari | 1.5475 | 0.904 | Pset_WindowCommon - IsExternal: yes
102233 | PS1- Vestuari | 1.5475 | 0.904 | Pset_WindowCommon - IsExternal: yes
102228 | PS1- Vestuari | 1.5475 | 0.916 | Pset_WindowCommon - IsExternal: yes
102218 | PS1- Vestuari | 1.5475 | 0.98 | Pset_WindowCommon - IsExternal: yes
102213 | PS1- Vestuari | 1.5475 | 1 | Pset_WindowCommon - IsExternal: yes
102203 | PS1- Vestuari | 1.5475 | 0.99 | Pset_WindowCommon - IsExternal: yes
102198 | PS1- Vestuari | 1.5475 | 0.99 | Pset_WindowCommon - IsExternal: yes
5318331 | PS1- Vestuari | 1.5475 | 0.916 | Pset_WindowCommon - IsExternal: yes
102152 | PS1- Vestuari | 1.5475 | 0.904 | Pset_WindowCommon - IsExternal: yes
102156 | PS1- Vestuari | 1.5475 | 0.904 | Pset_WindowCommon - IsExternal: yes
102160 | PS1- Vestuari | 1.5475 | 0.904 | Pset_WindowCommon - IsExternal: yes
102183 | PS1- Vestuari | 1.5475 | 0.904 | Pset_WindowCommon - IsExternal: yes
102178 | PS1- Vestuari | 1.5475 | 0.904 | Pset_WindowCommon - IsExternal: yes
102173 | PS1- Vestuari | 1.5475 | 0.904 | Pset_WindowCommon - IsExternal: yes
102168 | PS1- Vestuari | 1.5475 | 0.91 | Pset_WindowCommon - IsExternal: yes
5780713 | P0- Escola | 0.78875 | 0.97 | Grupo de modelo:Fa-:4013115
5780714 | P0- Escola | 0.78875 | 0.97 | Grupo de modelo:Fa-:4013115
5780715 | P0- Escola | 0.78875 | 0.97 | Grupo de modelo:Fa-:4013115
5780716 | P0- Escola | 0.78875 | 0.97 | Grupo de modelo:Fa-:4013115
5780722 | P0- Escola | 0.78875 | 0.97 | Grupo de modelo:Fa-:4013115
5780723 | P0- Escola | 0.78875 | 0.97 | Grupo de modelo:Fa-:4013115
5780724 | P0- Escola | 0.78875 | 0.97 | Grupo de modelo:Fa-:4013115
5780725 | P0- Escola | 0.78875 | 0.97 | Grupo de modelo:Fa-:4013115
5780731 | P0- Escola | 0.78875 | 0.97 | Grupo de modelo:Fa-:4013115
5780732 | P0- Escola | 0.78875 | 0.97 | Grupo de modelo:Fa-:4013115
5780733 | P0- Escola | 0.78875 | 0.97 | Grupo de modelo:Fa-:4013115
5780734 | P0- Escola | 0.78875 | 0.933748 | Grupo de modelo:Fa-:4013115
5786170 | P0- Escola | 0.875 | 0.97 | Grupo de modelo:Fa-:4013115
5786171 | P0- Escola | 0.875 | 0.97 | Grupo de modelo:Fa-:4013115
5786173 | P0- Escola | 0.875 | 0.645874 | Grupo de modelo:Fa-:4013115
5786176 | P0- Escola | 0.875 | 0.97 | Grupo de modelo:Fa-:4013115
5786177 | P0- Escola | 0.875 | 0.97 | Grupo de modelo:Fa-:4013115
5786178 | P0- Escola | 0.875 | 0.97 | Grupo de modelo:Fa-:4013115
5786180 | P0- Escola | 0.875 | 0.97 | Grupo de modelo:Fa-:4013115
5786181 | P0- Escola | 0.875 | 0.97 | Grupo de modelo:Fa-:4013115
5786182 | P0- Escola | 0.875 | 0.97 | Grupo de modelo:Fa-:4013115
5786185 | P0- Escola | 1.68375 | 0.492998 | Grupo de modelo:Fa-:4013115
6018030 | P0- Escola | 0.80875 | 0.97 | Grupo de modelo:Fa-:4013115
6018031 | P0- Escola | 0.80875 | 0.97 | Grupo de modelo:Fa-:4013115
6018033 | P0- Escola | 0.80875 | 0.645874 | Grupo de modelo:Fa-:4013115
6018036 | P0- Escola | 0.80875 | 0.97 | Grupo de modelo:Fa-:4013115
6018037 | P0- Escola | 0.80875 | 0.97 | Grupo de modelo:Fa-:4013115
6018038 | P0- Escola | 0.80875 | 0.97 | Grupo de modelo:Fa-:4013115
6018040 | P0- Escola | 0.80875 | 0.97 | Grupo de modelo:Fa-:4013115
6018041 | P0- Escola | 0.80875 | 0.97 | Grupo de modelo:Fa-:4013115
6018042 | P0- Escola | 0.80875 | 0.97 | Grupo de modelo:Fa-:4013115
5792042 | P0- Escola | 0.875 | 0.97 | Grupo de modelo:Fa-:4013115
5792047 | P0- Escola | 0.875 | 0.97 | Grupo de modelo:Fa-:4013115
5792052 | P0- Escola | 0.875 | 0.97 | Grupo de modelo:Fa-:4013115
6028681 | P0- Escola | 0.80875 | 0.97 | Grupo de modelo:Fa-:4013115
6028686 | P0- Escola | 0.80875 | 0.97 | Grupo de modelo:Fa-:4013115
6028691 | P0- Escola | 0.80875 | 0.97 | Grupo de modelo:Fa-:4013115
4791341 | P0- Escola | 1.0475 | 2.096
4791343 | P0- Escola | 1.0475 | 2.067
4791344 | P0- Escola | 1.0475 | 2.067
4791345 | P0- Escola | 1.0475 | 2.067
4791346 | P0- Escola | 1.0475 | 2.067
4791347 | P0- Escola | 1.0475 | 2.067
4791348 | P0- Escola | 1.0475 | 2.067
4791349 | P0- Escola | 1.0475 | 2.067
4791350 | P0- Escola | 1.0475 | 2.067
4791351 | P0- Escola | 1.0475 | 2.067
4791352 | P0- Escola | 1.0475 | 2.067
4791353 | P0- Escola | 1.0475 | 1.98934
4791941 | P0- Escola | 1.8175 | 2.04
5784638 | P0- Escola | 0.875 | 0.97 | Grupo de modelo:Fa-:4013115
5784639 | P0- Escola | 0.875 | 0.97 | Grupo de modelo:Fa-:4013115
5784641 | P0- Escola | 1.68375 | 0.619468 | Grupo de modelo:Fa-:4013115
5784642 | P0- Escola | 0.875 | 0.97 | Grupo de modelo:Fa-:4013115
5784644 | P0- Escola | 0.875 | 0.97 | Grupo de modelo:Fa-:4013115
5784645 | P0- Escola | 0.875 | 0.97 | Grupo de modelo:Fa-:4013115
5784647 | P0- Escola | 1.68375 | 0.641667 | Grupo de modelo:Fa-:4013115
5784648 | P0- Escola | 0.875 | 0.97 | Grupo de modelo:Fa-:4013115
5784650 | P0- Escola | 1.68375 | 0.651667 | Grupo de modelo:Fa-:4013115
5784653 | P0- Escola | 1.68375 | 0.5965 | Grupo de modelo:Fa-:4013115
5784654 | P0- Escola | 0.875 | 0.97 | Grupo de modelo:Fa-:4013115
5784655 | P0- Escola | 0.875 | 0.97 | Grupo de modelo:Fa-:4013115
5784657 | P0- Escola | 0.875 | 0.969236 | Grupo de modelo:Fa-:4013115
5784658 | P0- Escola | 1.68375 | 0.624264 | Grupo de modelo:Fa-:4013115
6008192 | P0- Escola | 0.80875 | 0.97 | Grupo de modelo:Fa-:4013115
6008193 | P0- Escola | 0.80875 | 0.97 | Grupo de modelo:Fa-:4013115
6008196 | P0- Escola | 0.80875 | 0.97 | Grupo de modelo:Fa-:4013115
6008198 | P0- Escola | 0.80875 | 0.97 | Grupo de modelo:Fa-:4013115
6008199 | P0- Escola | 0.80875 | 0.97 | Grupo de modelo:Fa-:4013115
6008202 | P0- Escola | 0.80875 | 0.97 | Grupo de modelo:Fa-:4013115
6008208 | P0- Escola | 0.80875 | 0.97 | Grupo de modelo:Fa-:4013115
6008209 | P0- Escola | 0.80875 | 0.97 | Grupo de modelo:Fa-:4013115
6008211 | P0- Escola | 0.80875 | 0.969236 | Grupo de modelo:Fa-:4013115
4824496 | P0- Escola | 0.54875 | 0.97 | Grupo de modelo:Fa-:4013115
4824497 | P0- Escola | 0.54875 | 0.97 | Grupo de modelo:Fa-:4013115
4824498 | P0- Escola | 0.54875 | 0.97 | Grupo de modelo:Fa-:4013115
4824499 | P0- Escola | 0.54875 | 0.97 | Grupo de modelo:Fa-:4013115
5783935 | P0- Escola | 0.875 | 0.97 | Grupo de modelo:Fa-:4013115
5783936 | P0- Escola | 0.875 | 0.97 | Grupo de modelo:Fa-:4013115
5783937 | P0- Escola | 0.875 | 0.97 | Grupo de modelo:Fa-:4013115
5783940 | P0- Escola | 0.875 | 0.967204 | Grupo de modelo:Fa-:4013115
5783941 | P0- Escola | 0.875 | 0.97 | Grupo de modelo:Fa-:4013115
6036053 | P0- Escola | 0.80875 | 0.97 | Grupo de modelo:Fa-:4013115
6036054 | P0- Escola | 0.80875 | 0.97 | Grupo de modelo:Fa-:4013115
6036055 | P0- Escola | 0.80875 | 0.97 | Grupo de modelo:Fa-:4013115
6036058 | P0- Escola | 0.80875 | 0.967204 | Grupo de modelo:Fa-:4013115
6036059 | P0- Escola | 0.80875 | 0.97 | Grupo de modelo:Fa-:4013115
4865677 | P0- Escola | 1.0475 | 2.10936
4865678 | P0- Escola | 1.0475 | 2.067
4865679 | P0- Escola | 1.0475 | 2.067
4865680 | P0- Escola | 1.0475 | 1.57
4873651 | P0- Escola | 1.0475 | 2.45141
4873653 | P0- Escola | 1.0475 | 2.067
4873654 | P0- Escola | 1.0475 | 2.067
4873655 | P0- Escola | 1.0475 | 1.17159
4909149 | P0- Escola | 0.9675 | 1.168
4911479 | P0- Escola | 0.9675 | 1.168
4911421 | P0- Escola | 0.9675 | 1.168
4911343 | P0- Escola | 0.9675 | 1.168
4911289 | P0- Escola | 0.9675 | 1.169
4911237 | P0- Escola | 0.9675 | 0.559
4924528 | PC- Coberta STR | 1.8675 | 1.125
5316674 | PC- Coberta STR | 1.8675 | 1.125
5316579 | PC- Coberta STR | 1.8675 | 1.125
5316581 | PC- Coberta STR | 1.8675 | 1.125
5316583 | PC- Coberta STR | 1.8675 | 1.125
5316585 | PC- Coberta STR | 1.8675 | 1.125
5791234 | P0- Escola | 0.875 | 0.97 | Grupo de modelo:Fa-:4013115
5791239 | P0- Escola | 0.875 | 0.97 | Grupo de modelo:Fa-:4013115
5791244 | P0- Escola | 0.875 | 0.97 | Grupo de modelo:Fa-:4013115
5791249 | P0- Escola | 0.875 | 0.84375 | Grupo de modelo:Fa-:4013115
6032821 | P0- Escola | 0.80875 | 0.97 | Grupo de modelo:Fa-:4013115
6032826 | P0- Escola | 0.80875 | 0.97 | Grupo de modelo:Fa-:4013115
6032831 | P0- Escola | 0.80875 | 0.97 | Grupo de modelo:Fa-:4013115
6032836 | P0- Escola | 0.80875 | 0.84375 | Grupo de modelo:Fa-:4013115
5793064 | P0- Escola | 1.52375 | 0.97 | Grupo de modelo:Fa-:4013115
5793069 | P0- Escola | 1.52375 | 0.97 | Grupo de modelo:Fa-:4013115
5793074 | P0- Escola | 1.52375 | 0.97 | Grupo de modelo:Fa-:4013115
6029405 | P0- Escola | 0.875 | 0.97 | Grupo de modelo:Fa-:4013115
6029406 | P0- Escola | 0.875 | 0.97 | Grupo de modelo:Fa-:4013115
6029408 | P0- Escola | 0.875 | 0.645874 | Grupo de modelo:Fa-:4013115
6029411 | P0- Escola | 0.875 | 0.97 | Grupo de modelo:Fa-:4013115
6029412 | P0- Escola | 0.875 | 0.97 | Grupo de modelo:Fa-:4013115
6029413 | P0- Escola | 0.875 | 0.97 | Grupo de modelo:Fa-:4013115
6029415 | P0- Escola | 0.875 | 0.97 | Grupo de modelo:Fa-:4013115
6029416 | P0- Escola | 0.875 | 0.97 | Grupo de modelo:Fa-:4013115
6029417 | P0- Escola | 0.875 | 0.97 | Grupo de modelo:Fa-:4013115
6029420 | P0- Escola | 1.68375 | 0.492998 | Grupo de modelo:Fa-:4013115
6029480 | P0- Escola | 0.80875 | 0.97 | Grupo de modelo:Fa-:4013115
6029481 | P0- Escola | 0.80875 | 0.97 | Grupo de modelo:Fa-:4013115
6029483 | P0- Escola | 0.80875 | 0.645874 | Grupo de modelo:Fa-:4013115
6029486 | P0- Escola | 0.80875 | 0.97 | Grupo de modelo:Fa-:4013115
6029487 | P0- Escola | 0.80875 | 0.97 | Grupo de modelo:Fa-:4013115
6029488 | P0- Escola | 0.80875 | 0.97 | Grupo de modelo:Fa-:4013115
6029490 | P0- Escola | 0.80875 | 0.97 | Grupo de modelo:Fa-:4013115
6029491 | P0- Escola | 0.80875 | 0.97 | Grupo de modelo:Fa-:4013115
6029492 | P0- Escola | 0.80875 | 0.97 | Grupo de modelo:Fa-:4013115
6029446 | P0- Escola | 0.875 | 0.97 | Grupo de modelo:Fa-:4013115
6029451 | P0- Escola | 0.875 | 0.97 | Grupo de modelo:Fa-:4013115
6029456 | P0- Escola | 0.875 | 0.97 | Grupo de modelo:Fa-:4013115
6029519 | P0- Escola | 0.80875 | 0.97 | Grupo de modelo:Fa-:4013115
6029524 | P0- Escola | 0.80875 | 0.97 | Grupo de modelo:Fa-:4013115
6029529 | P0- Escola | 0.80875 | 0.97 | Grupo de modelo:Fa-:4013115
6029657 | P0- Escola | 0.875 | 0.97 | Grupo de modelo:Fa-:4013115
6029658 | P0- Escola | 0.875 | 0.97 | Grupo de modelo:Fa-:4013115
6029660 | P0- Escola | 0.875 | 0.645874 | Grupo de modelo:Fa-:4013115
6029663 | P0- Escola | 0.875 | 0.97 | Grupo de modelo:Fa-:4013115
6029664 | P0- Escola | 0.875 | 0.97 | Grupo de modelo:Fa-:4013115
6029665 | P0- Escola | 0.875 | 0.97 | Grupo de modelo:Fa-:4013115
6029667 | P0- Escola | 0.875 | 0.97 | Grupo de modelo:Fa-:4013115
6029668 | P0- Escola | 0.875 | 0.97 | Grupo de modelo:Fa-:4013115
6029669 | P0- Escola | 0.875 | 0.97 | Grupo de modelo:Fa-:4013115
6029672 | P0- Escola | 1.68375 | 0.492998 | Grupo de modelo:Fa-:4013115
6029696 | P0- Escola | 0.80875 | 0.97 | Grupo de modelo:Fa-:4013115
6029697 | P0- Escola | 0.80875 | 0.97 | Grupo de modelo:Fa-:4013115
6029699 | P0- Escola | 0.80875 | 0.645874 | Grupo de modelo:Fa-:4013115
6029702 | P0- Escola | 0.80875 | 0.97 | Grupo de modelo:Fa-:4013115
6029703 | P0- Escola | 0.80875 | 0.97 | Grupo de modelo:Fa-:4013115
6029704 | P0- Escola | 0.80875 | 0.97 | Grupo de modelo:Fa-:4013115
6029706 | P0- Escola | 0.80875 | 0.97 | Grupo de modelo:Fa-:4013115
6029707 | P0- Escola | 0.80875 | 0.97 | Grupo de modelo:Fa-:4013115
6029708 | P0- Escola | 0.80875 | 0.97 | Grupo de modelo:Fa-:4013115

# IfcWindow: MC- Alu- Conjunt vidre fix revestiment:MC- Alu- Conjunt vidre fix revestiment (10)
Type - ParameterTakesPrecedence: no; Sizeable: no; Material: <Unnamed>, _Vidre, _Alumini- T1- Perfil
Type - Pset_WindowCommon - IsExternal: no
Pset_QuantityTakeOff - Reference: MC- Alu- Conjunt vidre fix revestiment
Pset_WindowCommon - Reference: MC- Alu- Conjunt vidre fix revestiment
Name (MC- Alu- Conjunt vidre fix revestiment:MC- Alu- Conjunt vidre fix revestiment:...) | In | OverallHeight (m) | OverallWidth (m)
4667046 | PS1- Gimnàs | 1.8915 | 0.44 | Pset_WindowCommon - IsExternal: yes
4667052 | PS1- Gimnàs | 1.8915 | 0.385 | Pset_WindowCommon - IsExternal: yes
4719488 | PS1- Gimnàs | 2.5 | 0.56775
4865633 | P0- Escola | 0.77 | 2.29036
4866109 | P0- Escola | 0.77 | 0.245
4865675 | P0- Escola | 1.0475 | 2.29036
4866110 | P0- Escola | 1.0475 | 0.245
4943402 | P0- Escola | 2.52375 | 0.97 | Group: Grupo de modelo:Fa-:4013115
4943422 | P0- Escola | 2.52375 | 0.97 | Group: Grupo de modelo:Fa-:4013115
4943457 | P0- Escola | 2.52375 | 0.97 | Group: Grupo de modelo:Fa-:4013115

# IfcWindow: MC- Alu- Conjunt vidre fix- 62x60 cm- +15cm:MC- Alu- Conjunt vidre fix- 62x60 cm- +15cm (7)
Type - ParameterTakesPrecedence: no; Sizeable: no; Material: _Alumini- T1- Perfil, _Vidre
Type - Pset_WindowCommon - IsExternal: no
Pset_QuantityTakeOff - Reference: MC- Alu- Conjunt vidre fix- 62x60 cm- +15cm
Pset_WindowCommon - Reference: MC- Alu- Conjunt vidre fix- 62x60 cm- +15cm
Name (MC- Alu- Conjunt vidre fix- 62x60 cm- +15cm:MC- Alu- Conjunt vidre fix- 62x60 cm- +15cm:...) | In | OverallHeight (m) | OverallWidth (m)
102317 | PS1- Vestuari | 2.20994 | 0.97945 | Pset_WindowCommon - IsExternal: yes
102323 | PS1- Vestuari | 2.20994 | 0.97945
102327 | PS1- Vestuari | 2.20994 | 0.907
102333 | PS1- Vestuari | 2.20994 | 0.592
102339 | PS1- Vestuari | 2.20994 | 0.592
4685243 | PS1- Gimnàs | 2.5 | 1.35375
4696965 | PS1- Gimnàs | 2.5027 | 0.77075

# IfcWindow: MC- Alu- Conjunt vidre fix- 62x60 cm:MC- Alu- Conjunt vidre fix- 62x60 cm (6)
In: PS1- Gimnàs
Type - ParameterTakesPrecedence: no; Sizeable: no; Material: _Alumini- T1- Perfil, _Vidre
Type - Pset_WindowCommon - IsExternal: no
OverallHeight: 2.3425 m
Pset_QuantityTakeOff - Reference: MC- Alu- Conjunt vidre fix- 62x60 cm
Pset_WindowCommon - Reference: MC- Alu- Conjunt vidre fix- 62x60 cm
Name (MC- Alu- Conjunt vidre fix- 62x60 cm:MC- Alu- Conjunt vidre fix- 62x60 cm:...) | OverallWidth (m)
4696811 | 1.16475
4697409 | 0.95
4697333 | 0.95
4697251 | 0.95
4697175 | 0.95
4696966 | 0.77075

# IfcWindow: MC- Alu- Conjunt vidre fix- 62x60 cm:MC- Alu- Conjunt vidre fix- 62x60 cm (236)
Type - ParameterTakesPrecedence: no; Sizeable: no; Material: _Vidre, _Alumini- T1- Perfil
Type - Pset_WindowCommon - IsExternal: no
Pset_QuantityTakeOff - Reference: MC- Alu- Conjunt vidre fix- 62x60 cm
Pset_WindowCommon - Reference: MC- Alu- Conjunt vidre fix- 62x60 cm
Name (MC- Alu- Conjunt vidre fix- 62x60 cm:MC- Alu- Conjunt vidre fix- 62x60 cm:...) | In | OverallHeight (m) | OverallWidth (m) | Group
895047 | P0- Escola | 0.735 | 1.309 | Pset_WindowCommon - IsExternal: yes
6041657 | P0- Escola | 0.735 | 1.334 | Pset_WindowCommon - IsExternal: yes
6040130 | P0- Escola | 0.735 | 0.725 | Pset_WindowCommon - IsExternal: yes
6041095 | P0- Escola | 1.2525 | 1.309 | Pset_WindowCommon - IsExternal: yes
6041658 | P0- Escola | 1.2525 | 1.334 | Pset_WindowCommon - IsExternal: yes
6041096 | P0- Escola | 1.2525 | 0.725 | Pset_WindowCommon - IsExternal: yes
5780872 | P0- Escola | 0.7877 | 0.548335 | Grupo de modelo:Fa-:4013115
2564645 | P0- Escola | 2.45145 | 0.97 | Grupo de modelo:Fa-:4013115
2564651 | P0- Escola | 0.7877 | 0.97 | Grupo de modelo:Fa-:4013115
2564804 | P0- Escola | 0.7877 | 0.97 | Grupo de modelo:Fa-:4013115
2564654 | P0- Escola | 0.7877 | 0.97 | Grupo de modelo:Fa-:4013115
2564657 | P0- Escola | 0.7877 | 0.97 | Grupo de modelo:Fa-:4013115
5780874 | P0- Escola | 0.7877 | 0.535 | Grupo de modelo:Fa-:4013115
2564685 | P0- Escola | 2.45145 | 0.97 | Grupo de modelo:Fa-:4013115
2564695 | P0- Escola | 0.7877 | 0.97 | Grupo de modelo:Fa-:4013115
2564700 | P0- Escola | 0.7877 | 0.97 | Grupo de modelo:Fa-:4013115
2564705 | P0- Escola | 0.7877 | 0.97 | Grupo de modelo:Fa-:4013115
2564710 | P0- Escola | 0.7877 | 0.97 | Grupo de modelo:Fa-:4013115
5780876 | P0- Escola | 0.7877 | 0.58715 | Grupo de modelo:Fa-:4013115
2564725 | P0- Escola | 2.45145 | 0.97 | Grupo de modelo:Fa-:4013115
2564735 | P0- Escola | 0.7877 | 0.97 | Grupo de modelo:Fa-:4013115
2564740 | P0- Escola | 0.7877 | 0.97 | Grupo de modelo:Fa-:4013115
2564745 | P0- Escola | 0.7877 | 0.97 | Grupo de modelo:Fa-:4013115
2564797 | P0- Escola | 0.7877 | 0.933748 | Grupo de modelo:Fa-:4013115
6034415 | P0- Escola | 1.66375 | 0.548335 | Grupo de modelo:Fa-:4013115
6034419 | P0- Escola | 0.875 | 0.97 | Grupo de modelo:Fa-:4013115
6034420 | P0- Escola | 0.875 | 0.97 | Grupo de modelo:Fa-:4013115
6034421 | P0- Escola | 0.875 | 0.97 | Grupo de modelo:Fa-:4013115
6034422 | P0- Escola | 0.875 | 0.97 | Grupo de modelo:Fa-:4013115
6034424 | P0- Escola | 1.66375 | 0.535 | Grupo de modelo:Fa-:4013115
6034428 | P0- Escola | 0.875 | 0.97 | Grupo de modelo:Fa-:4013115
6034429 | P0- Escola | 0.875 | 0.97 | Grupo de modelo:Fa-:4013115
6034430 | P0- Escola | 0.875 | 0.97 | Grupo de modelo:Fa-:4013115
6034431 | P0- Escola | 0.875 | 0.97 | Grupo de modelo:Fa-:4013115
6034433 | P0- Escola | 1.66375 | 0.58715 | Grupo de modelo:Fa-:4013115
6034437 | P0- Escola | 0.875 | 0.97 | Grupo de modelo:Fa-:4013115
6034438 | P0- Escola | 0.875 | 0.97 | Grupo de modelo:Fa-:4013115
6034439 | P0- Escola | 0.875 | 0.97 | Grupo de modelo:Fa-:4013115
6034440 | P0- Escola | 0.875 | 0.933748 | Grupo de modelo:Fa-:4013115
3336765 | P0- Escola | 0.7877 | 0.97 | Grupo de modelo:Fa-:4013115
3336770 | P0- Escola | 0.7877 | 0.97 | Grupo de modelo:Fa-:4013115
4587335 | P0- Escola | 0.7877 | 0.645874 | Grupo de modelo:Fa-:4013115
3336785 | P0- Escola | 0.7877 | 0.97 | Grupo de modelo:Fa-:4013115
3336790 | P0- Escola | 0.7877 | 0.97 | Grupo de modelo:Fa-:4013115
3336795 | P0- Escola | 0.7877 | 0.97 | Grupo de modelo:Fa-:4013115
3336825 | P0- Escola | 0.7877 | 0.97 | Grupo de modelo:Fa-:4013115
3336805 | P0- Escola | 0.7877 | 0.97 | Grupo de modelo:Fa-:4013115
3336810 | P0- Escola | 0.7877 | 0.97 | Grupo de modelo:Fa-:4013115
3336820 | P0- Escola | 0.7877 | 0.492998 | Grupo de modelo:Fa-:4013115
4012145 | P0- Escola | 0.56375 | 1.47683 | Grupo de modelo:Fa-:4013115
6028751 | P0- Escola | 2.47145 | 0.97 | Grupo de modelo:Fa-:4013115
4468973 | P0- Escola | 2.47145 | 0.97 | Grupo de modelo:Fa-:4013115
4468978 | P0- Escola | 2.47145 | 0.97 | Grupo de modelo:Fa-:4013115
4468983 | P0- Escola | 0.7877 | 0.97 | Grupo de modelo:Fa-:4013115
4469038 | P0- Escola | 2.47145 | 0.97 | Grupo de modelo:Fa-:4013115
4468993 | P0- Escola | 2.47145 | 0.97 | Grupo de modelo:Fa-:4013115
4468998 | P0- Escola | 2.47145 | 0.97 | Grupo de modelo:Fa-:4013115
4469003 | P0- Escola | 0.7877 | 0.97 | Grupo de modelo:Fa-:4013115
4469033 | P0- Escola | 2.47145 | 0.97 | Grupo de modelo:Fa-:4013115
4469013 | P0- Escola | 2.47145 | 0.97 | Grupo de modelo:Fa-:4013115
4469018 | P0- Escola | 2.47145 | 0.97 | Grupo de modelo:Fa-:4013115
4469023 | P0- Escola | 0.7877 | 0.97 | Grupo de modelo:Fa-:4013115
4510553 | P0- Escola | 2.47125 | 1.494 | Grupo de modelo:Fa-:4013115
4510561 | P0- Escola | 0.56375 | 1.54183 | Grupo de modelo:Fa-:4013115
4762229 | PS1- Gimnàs | 1.8915 | 0.551275
4667068 | PS1- Gimnàs | 1.8915 | 0.976275
4667055 | PS1- Gimnàs | 1.8915 | 0.976275
4667065 | PS1- Gimnàs | 1.8915 | 0.976275
4762489 | PS1- Gimnàs | 1.8915 | 0.591275
4667062 | PS1- Gimnàs | 1.8915 | 0.976275
4667049 | PS1- Gimnàs | 1.8915 | 0.976275
4667059 | PS1- Gimnàs | 1.8915 | 0.860025
4691685 | PS1- Gimnàs | 1.54556 | 1.35375
4691686 | PS1- Gimnàs | 1.54556 | 2.32599
4756195 | PS1- Gimnàs | 1.004 | 0.932019
4764299 | PS1- Gimnàs | 1.004 | 0.969519
4763946 | PS1- Gimnàs | 1.004 | 0.969519
4763312 | PS1- Gimnàs | 1.004 | 0.94375
4766203 | PS1- Gimnàs | 1.8475 | 0.932019
4766204 | PS1- Gimnàs | 1.8475 | 0.969519
4766205 | PS1- Gimnàs | 1.8475 | 0.969519
4766206 | PS1- Gimnàs | 1.8475 | 0.94375
4774201 | P0- Escola | 0.77 | 2.096
4784863 | P0- Escola | 0.77 | 2.067
4784719 | P0- Escola | 0.77 | 2.067
4784591 | P0- Escola | 0.77 | 2.067
4784519 | P0- Escola | 0.77 | 2.067
4784457 | P0- Escola | 0.77 | 2.067
4784381 | P0- Escola | 0.77 | 2.067
4784297 | P0- Escola | 0.77 | 2.067
4784186 | P0- Escola | 0.77 | 2.067
4784043 | P0- Escola | 0.77 | 2.067
4783334 | P0- Escola | 0.77 | 2.067
4776977 | P0- Escola | 0.77 | 1.98934
4792294 | P0- Escola | 2.415 | 2.485
4804566 | P0- Escola | 2.415 | 1.2075
4865348 | P0- Escola | 2.415 | 1.1825
5989266 | P0- Escola | 2.5 | 0.39
4874233 | P0- Escola | 0.592 | 2.1315
5990059 | P0- Escola | 2.5 | 0.39
4816831 | P0- Escola | 0.7877 | 0.97 | Grupo de modelo:Fa-:4013115
4816837 | P0- Escola | 0.7877 | 0.97 | Grupo de modelo:Fa-:4013115
4819014 | P0- Escola | 0.7877 | 0.619468 | Grupo de modelo:Fa-:4013115
4816847 | P0- Escola | 0.7877 | 0.97 | Grupo de modelo:Fa-:4013115
4816902 | P0- Escola | 0.7877 | 0.97 | Grupo de modelo:Fa-:4013115
4816857 | P0- Escola | 0.7877 | 0.97 | Grupo de modelo:Fa-:4013115
4817944 | P0- Escola | 0.7877 | 0.641667 | Grupo de modelo:Fa-:4013115
4816867 | P0- Escola | 0.7877 | 0.97 | Grupo de modelo:Fa-:4013115
4816897 | P0- Escola | 0.7877 | 0.651667 | Grupo de modelo:Fa-:4013115
4817818 | P0- Escola | 0.7877 | 0.5965 | Grupo de modelo:Fa-:4013115
4816882 | P0- Escola | 0.7877 | 0.97 | Grupo de modelo:Fa-:4013115
4816887 | P0- Escola | 0.7877 | 0.97 | Grupo de modelo:Fa-:4013115
4816892 | P0- Escola | 0.7877 | 0.969236 | Grupo de modelo:Fa-:4013115
4816912 | P0- Escola | 0.7877 | 0.624264 | Grupo de modelo:Fa-:4013115
4816977 | P0- Escola | 2.47125 | 1.494 | Grupo de modelo:Fa-:4013115
4816985 | P0- Escola | 0.56375 | 1.54183 | Grupo de modelo:Fa-:4013115
4820813 | P0- Escola | 0.7877 | 0.97 | Grupo de modelo:Fa-:4013115
4820818 | P0- Escola | 0.7877 | 0.97 | Grupo de modelo:Fa-:4013115
4820823 | P0- Escola | 0.7877 | 0.97 | Grupo de modelo:Fa-:4013115
4820828 | P0- Escola | 0.7877 | 0.967204 | Grupo de modelo:Fa-:4013115
4821516 | P0- Escola | 0.7877 | 0.97 | Grupo de modelo:Fa-:4013115
4825884 | P0- Escola | 0.56375 | 1.73183 | Grupo de modelo:Fa-:4013115
4865602 | P0- Escola | 0.77 | 3.15128
4865623 | P0- Escola | 0.77 | 2.10936
4865618 | P0- Escola | 0.77 | 2.067
4865613 | P0- Escola | 0.77 | 2.067
4865608 | P0- Escola | 0.77 | 1.57
4865668 | P0- Escola | 1.0475 | 3.15128
4868637 | P0- Escola | 0.765 | 1.834
4869245 | P0- Escola | 0.765 | 2.127
4869356 | P0- Escola | 0.765 | 2.127
4869428 | P0- Escola | 0.765 | 2.127
4869471 | P0- Escola | 0.765 | 2.127
4869510 | P0- Escola | 0.765 | 2.008
4869666 | P0- Escola | 1.0525 | 1.834
4869667 | P0- Escola | 1.0525 | 2.127
4869668 | P0- Escola | 1.0525 | 2.127
4869669 | P0- Escola | 1.0525 | 2.127
4869670 | P0- Escola | 1.0525 | 2.127
4869671 | P0- Escola | 1.0525 | 2.008
4873585 | P0- Escola | 0.77 | 2.45141
4873641 | P0- Escola | 0.77 | 2.067
4873636 | P0- Escola | 0.77 | 2.067
4873631 | P0- Escola | 0.77 | 1.17159
4889922 | P0- Escola | 0.592 | 2.1315
6042349 | P0- Escola | 1.0875 | 1.141
6042350 | P0- Escola | 1.0875 | 1.102
4899977 | P0- Escola | 2.4175 | 1.382
4899982 | P0- Escola | 2.4175 | 1.352
4908965 | P0- Escola | 0.9675 | 1.39
4935218 | P0- Escola | 0.56375 | 1.47683 | Grupo de modelo:Fa-:4013115
4935348 | P0- Escola | 2.47125 | 1.494 | Grupo de modelo:Fa-:4013115
4935356 | P0- Escola | 0.56375 | 1.54183 | Grupo de modelo:Fa-:4013115
4935627 | P0- Escola | 0.56375 | 1.47683 | Grupo de modelo:Fa-:4013115
6032894 | P0- Escola | 2.47145 | 0.97 | Grupo de modelo:Fa-:4013115
4935653 | P0- Escola | 2.47145 | 0.97 | Grupo de modelo:Fa-:4013115
4935658 | P0- Escola | 2.47145 | 0.97 | Grupo de modelo:Fa-:4013115
4935663 | P0- Escola | 0.7877 | 0.97 | Grupo de modelo:Fa-:4013115
4935718 | P0- Escola | 2.47145 | 0.97 | Grupo de modelo:Fa-:4013115
4935673 | P0- Escola | 2.47145 | 0.97 | Grupo de modelo:Fa-:4013115
4935678 | P0- Escola | 2.47145 | 0.97 | Grupo de modelo:Fa-:4013115
4935683 | P0- Escola | 0.7877 | 0.97 | Grupo de modelo:Fa-:4013115
4935713 | P0- Escola | 2.47145 | 0.97 | Grupo de modelo:Fa-:4013115
4935693 | P0- Escola | 2.47145 | 0.97 | Grupo de modelo:Fa-:4013115
4935698 | P0- Escola | 2.47145 | 0.97 | Grupo de modelo:Fa-:4013115
4935703 | P0- Escola | 0.7877 | 0.97 | Grupo de modelo:Fa-:4013115
4935708 | P0- Escola | 2.47145 | 0.97 | Grupo de modelo:Fa-:4013115
4937864 | P0- Escola | 2.47145 | 0.97 | Grupo de modelo:Fa-:4013115
4937965 | P0- Escola | 2.47145 | 0.97 | Grupo de modelo:Fa-:4013115
4938047 | P0- Escola | 0.7877 | 0.84375 | Grupo de modelo:Fa-:4013115
4935757 | P0- Escola | 2.47125 | 1.494 | Grupo de modelo:Fa-:4013115
4935765 | P0- Escola | 0.56375 | 1.54183 | Grupo de modelo:Fa-:4013115
4943377 | P0- Escola | 0.56375 | 1.47683 | Grupo de modelo:Fa-:4013115
4943465 | P0- Escola | 2.47145 | 0.97 | Grupo de modelo:Fa-:4013115
4943387 | P0- Escola | 2.47145 | 0.97 | Grupo de modelo:Fa-:4013115
4943392 | P0- Escola | 2.47145 | 0.97 | Grupo de modelo:Fa-:4013115
4943397 | P0- Escola | 0.9477 | 0.97 | Grupo de modelo:Fa-:4013115
4943452 | P0- Escola | 2.47145 | 0.97 | Grupo de modelo:Fa-:4013115
4943407 | P0- Escola | 2.47145 | 0.97 | Grupo de modelo:Fa-:4013115
4943412 | P0- Escola | 2.47145 | 0.97 | Grupo de modelo:Fa-:4013115
4943417 | P0- Escola | 0.9477 | 0.97 | Grupo de modelo:Fa-:4013115
4943447 | P0- Escola | 2.47145 | 0.97 | Grupo de modelo:Fa-:4013115
4943427 | P0- Escola | 2.47145 | 0.97 | Grupo de modelo:Fa-:4013115
4943432 | P0- Escola | 2.47145 | 0.97 | Grupo de modelo:Fa-:4013115
4943437 | P0- Escola | 0.9477 | 0.97 | Grupo de modelo:Fa-:4013115
5381534 | P0- Escola | 2.43875 | 0.8328 | Grupo de modelo:Fa-:4013115
5385646 | P0- Escola | 2.43875 | 0.8328 | Grupo de modelo:Fa-:4013115
5385648 | P0- Escola | 2.43875 | 0.8328 | Grupo de modelo:Fa-:4013115
5385650 | P0- Escola | 2.43875 | 0.8328 | Grupo de modelo:Fa-:4013115
5385652 | P0- Escola | 2.43875 | 0.8328 | Grupo de modelo:Fa-:4013115
5401886 | P0- Escola | 2.43875 | 0.8328 | Grupo de modelo:Fa-:4013115
5401892 | P0- Escola | 2.43875 | 0.8328 | Grupo de modelo:Fa-:4013115
5401894 | P0- Escola | 2.43875 | 0.8328 | Grupo de modelo:Fa-:4013115
5401896 | P0- Escola | 2.43875 | 0.8328 | Grupo de modelo:Fa-:4013115
5401898 | P0- Escola | 2.43875 | 0.8328 | Grupo de modelo:Fa-:4013115
5401915 | P0- Escola | 2.43875 | 0.8328 | Grupo de modelo:Fa-:4013115
5401921 | P0- Escola | 2.43875 | 0.8328 | Grupo de modelo:Fa-:4013115
5401923 | P0- Escola | 2.43875 | 0.8328 | Grupo de modelo:Fa-:4013115
5401925 | P0- Escola | 2.43875 | 0.8328 | Grupo de modelo:Fa-:4013115
5401927 | P0- Escola | 2.43875 | 0.8328 | Grupo de modelo:Fa-:4013115
5410566 | P0- Escola | 0.735 | 1.475
6041481 | P0- Escola | 0.735 | 1.475
6040569 | P0- Escola | 1.6825 | 1.475
6041482 | P0- Escola | 1.6825 | 1.475
6029256 | P0- Escola | 0.7877 | 0.97 | Grupo de modelo:Fa-:4013115
6029261 | P0- Escola | 0.7877 | 0.97 | Grupo de modelo:Fa-:4013115
6029400 | P0- Escola | 0.7877 | 0.645874 | Grupo de modelo:Fa-:4013115
6029274 | P0- Escola | 0.7877 | 0.97 | Grupo de modelo:Fa-:4013115
6029279 | P0- Escola | 0.7877 | 0.97 | Grupo de modelo:Fa-:4013115
6029284 | P0- Escola | 0.7877 | 0.97 | Grupo de modelo:Fa-:4013115
6029313 | P0- Escola | 0.7877 | 0.97 | Grupo de modelo:Fa-:4013115
6029293 | P0- Escola | 0.7877 | 0.97 | Grupo de modelo:Fa-:4013115
6029298 | P0- Escola | 0.7877 | 0.97 | Grupo de modelo:Fa-:4013115
6029308 | P0- Escola | 0.7877 | 0.492998 | Grupo de modelo:Fa-:4013115
6029549 | P0- Escola | 2.47145 | 0.97 | Grupo de modelo:Fa-:4013115
6029332 | P0- Escola | 2.47145 | 0.97 | Grupo de modelo:Fa-:4013115
6029337 | P0- Escola | 2.47145 | 0.97 | Grupo de modelo:Fa-:4013115
6029342 | P0- Escola | 0.7877 | 0.97 | Grupo de modelo:Fa-:4013115
6029392 | P0- Escola | 2.47145 | 0.97 | Grupo de modelo:Fa-:4013115
6029351 | P0- Escola | 2.47145 | 0.97 | Grupo de modelo:Fa-:4013115
6029356 | P0- Escola | 2.47145 | 0.97 | Grupo de modelo:Fa-:4013115
6029361 | P0- Escola | 0.7877 | 0.97 | Grupo de modelo:Fa-:4013115
6029388 | P0- Escola | 2.47145 | 0.97 | Grupo de modelo:Fa-:4013115
6029370 | P0- Escola | 2.47145 | 0.97 | Grupo de modelo:Fa-:4013115
6029375 | P0- Escola | 2.47145 | 0.97 | Grupo de modelo:Fa-:4013115
6029380 | P0- Escola | 0.7877 | 0.97 | Grupo de modelo:Fa-:4013115
6029580 | P0- Escola | 0.7877 | 0.97 | Grupo de modelo:Fa-:4013115
6029585 | P0- Escola | 0.7877 | 0.97 | Grupo de modelo:Fa-:4013115
6029652 | P0- Escola | 0.7877 | 0.645874 | Grupo de modelo:Fa-:4013115
6029598 | P0- Escola | 0.7877 | 0.97 | Grupo de modelo:Fa-:4013115
6029603 | P0- Escola | 0.7877 | 0.97 | Grupo de modelo:Fa-:4013115
6029608 | P0- Escola | 0.7877 | 0.97 | Grupo de modelo:Fa-:4013115
6029637 | P0- Escola | 0.7877 | 0.97 | Grupo de modelo:Fa-:4013115
6029617 | P0- Escola | 0.7877 | 0.97 | Grupo de modelo:Fa-:4013115
6029622 | P0- Escola | 0.7877 | 0.97 | Grupo de modelo:Fa-:4013115
6029632 | P0- Escola | 0.7877 | 0.492998 | Grupo de modelo:Fa-:4013115

# IfcWindow: MC- Fusta- Finestra ventilacio interior- Enva- Sencer:MC- Fusta- Finestra ventilacio interior- Enva- Sencer (3)
In: P0- Escola
Type - ParameterTakesPrecedence: no; Sizeable: no; Material: _Fusta massisa- T1- REV- PAV, _Aillament
Type - Pset_WindowCommon - IsExternal: no
OverallHeight: 2.505 m; OverallWidth: 0.715 m
Pset_QuantityTakeOff - Reference: MC- Fusta- Finestra ventilacio interior- Enva- Sencer
Pset_WindowCommon - Reference: MC- Fusta- Finestra ventilacio interior- Enva- Sencer
Name (MC- Fusta- Finestra ventilacio interior- Enva- Sencer:MC- Fusta- Finestra ventilacio interior- Enva- Sencer:...) | Group
462857 | Grupo de modelo:Grup aula:4934097 | Pset_WindowCommon - IsExternal: yes
4940465 | Grupo de modelo:Grup aula:4940566
4940721 | Grupo de modelo:Grup aula:4940822

# IfcWindow: MC- Fusta- Finestra ventilacio interior- Panell vidre:MC- Fusta- Finestra ventilacio interior- Panell vidre (2)
In: P0- Escola
Type - ParameterTakesPrecedence: no; Sizeable: no; Material: _Fusta massisa- T1- REV- PAV, _Vidre
Type - Pset_WindowCommon - IsExternal: no
OverallHeight: 2.475 m; OverallWidth: 0.955 m
Pset_QuantityTakeOff - Reference: MC- Fusta- Finestra ventilacio interior- Panell vidre
Pset_WindowCommon - IsExternal: yes; Reference: MC- Fusta- Finestra ventilacio interior- Panell vidre
Name (MC- Fusta- Finestra ventilacio interior- Panell vidre:MC- Fusta- Finestra ventilacio interior- Panell vidre:...)
361964
362270

# IfcWindow: MC- Fusta- Finestra ventilacio interior:MC- Fusta- Finestra ventilacio interior (11)
In: P0- Escola
Type - ParameterTakesPrecedence: no; Sizeable: no; Material: _Fusta massisa- T1- REV- PAV
Type - Pset_WindowCommon - IsExternal: no
OverallHeight: 2.46 m
Pset_QuantityTakeOff - Reference: MC- Fusta- Finestra ventilacio interior
Pset_WindowCommon - Reference: MC- Fusta- Finestra ventilacio interior
Name (MC- Fusta- Finestra ventilacio interior:MC- Fusta- Finestra ventilacio interior:...) | OverallWidth (m)
369291 | 0.94 | Pset_WindowCommon - IsExternal: yes
364800 | 0.94
365240 | 0.94
5825197 | 0.94
361758 | 0.955
361841 | 0.955
362062 | 0.94
369832 | 0.94
462852 | 0.939998 | Group: Grupo de modelo:Grup aula:4934097
4940460 | 0.939998 | Group: Grupo de modelo:Grup aula:4940566
4940716 | 0.939998 | Group: Grupo de modelo:Grup aula:4940822

# IfcWindow: MC- Fusta- vidre fix + part opaca- amb muntant inferior:MC- Fusta- vidre fix + part opaca- amb muntant inferior, MC- Fusta- vidre fix + part opaca- amb muntant inferior:MC- Fusta- vidre fix + part opaca- amb muntant inferior:362146
In: P0- Escola
Type - ParameterTakesPrecedence: no; Sizeable: no; Material: _Fusta massisa- T1, _Vidre
Type - Pset_WindowCommon - IsExternal: no
OverallHeight: 2.475 m; OverallWidth: 0.955 m
Pset_QuantityTakeOff - Reference: MC- Fusta- vidre fix + part opaca- amb muntant inferior
Pset_WindowCommon - IsExternal: yes; Reference: MC- Fusta- vidre fix + part opaca- amb muntant inferior

# IfcWindow: MC- Fusta- vidre fix + part opaca:MC- Fusta- vidre fix + part opaca, MC- Fusta- vidre fix + part opaca:MC- Fusta- vidre fix + part opaca:361921
In: P0- Escola
Type - ParameterTakesPrecedence: no; Sizeable: no; Material: _Fusta massisa- T1, _Vidre
Type - Pset_WindowCommon - IsExternal: no
OverallHeight: 2.475 m; OverallWidth: 0.955 m
Pset_QuantityTakeOff - Reference: MC- Fusta- vidre fix + part opaca
Pset_WindowCommon - IsExternal: yes; Reference: MC- Fusta- vidre fix + part opaca

# IfcWindow: MC- Fusta- vidre fix:MC- Fusta- vidre fix (49)
In: P0- Escola
Type - ParameterTakesPrecedence: no; Sizeable: no; Material: _Vidre
Type - Pset_WindowCommon - IsExternal: no
Pset_QuantityTakeOff - Reference: MC- Fusta- vidre fix
Pset_WindowCommon - Reference: MC- Fusta- vidre fix
Name (MC- Fusta- vidre fix:MC- Fusta- vidre fix:...) | OverallHeight (m) | OverallWidth (m) | Group
369353 | 2.46 | 0.9675 | Pset_WindowCommon - IsExternal: yes
338959 | 2.475 | 0.955
364684 | 2.475 | 0.97
364750 | 2.475 | 0.97
364957 | 2.475 | 0.97
364898 | 2.475 | 0.97
365099 | 2.475 | 0.97
365148 | 2.475 | 0.97
365183 | 2.475 | 0.97
365385 | 2.475 | 0.97
365448 | 2.475 | 0.97
365487 | 2.475 | 0.97
365524 | 2.475 | 0.97
365573 | 2.475 | 0.97
360233 | 2.475 | 0.97
361658 | 2.475 | 0.97
369615 | 2.475 | 0.94
369783 | 2.475 | 0.997499
462913 | 2.475 | 0.97 | Grupo de modelo:Grup aula:4934097
462901 | 2.46 | 0.955 | Grupo de modelo:Grup aula:4934097
462893 | 2.46 | 0.97 | Grupo de modelo:Grup aula:4934097
462889 | 2.475 | 0.97 | Grupo de modelo:Grup aula:4934097
462885 | 2.475 | 0.97 | Grupo de modelo:Grup aula:4934097
462877 | 2.475 | 0.97 | Grupo de modelo:Grup aula:4934097
462873 | 2.475 | 0.97 | Grupo de modelo:Grup aula:4934097
462869 | 2.475 | 0.97 | Grupo de modelo:Grup aula:4934097
462861 | 2.475 | 0.97 | Grupo de modelo:Grup aula:4934097
4901823 | 2.44726 | 1.01
4907966 | 2.44726 | 0.983
4908039 | 2.44726 | 1.05466
4940521 | 2.475 | 0.97 | Grupo de modelo:Grup aula:4940566
4940509 | 2.46 | 0.955 | Grupo de modelo:Grup aula:4940566
4940501 | 2.46 | 0.97 | Grupo de modelo:Grup aula:4940566
4940497 | 2.475 | 0.97 | Grupo de modelo:Grup aula:4940566
4940493 | 2.475 | 0.97 | Grupo de modelo:Grup aula:4940566
4940485 | 2.475 | 0.97 | Grupo de modelo:Grup aula:4940566
4940481 | 2.475 | 0.97 | Grupo de modelo:Grup aula:4940566
4940477 | 2.475 | 0.97 | Grupo de modelo:Grup aula:4940566
4940469 | 2.475 | 0.97 | Grupo de modelo:Grup aula:4940566
4940777 | 2.475 | 0.97 | Grupo de modelo:Grup aula:4940822
4940765 | 2.46 | 0.955 | Grupo de modelo:Grup aula:4940822
4940757 | 2.46 | 0.97 | Grupo de modelo:Grup aula:4940822
4940753 | 2.475 | 0.97 | Grupo de modelo:Grup aula:4940822
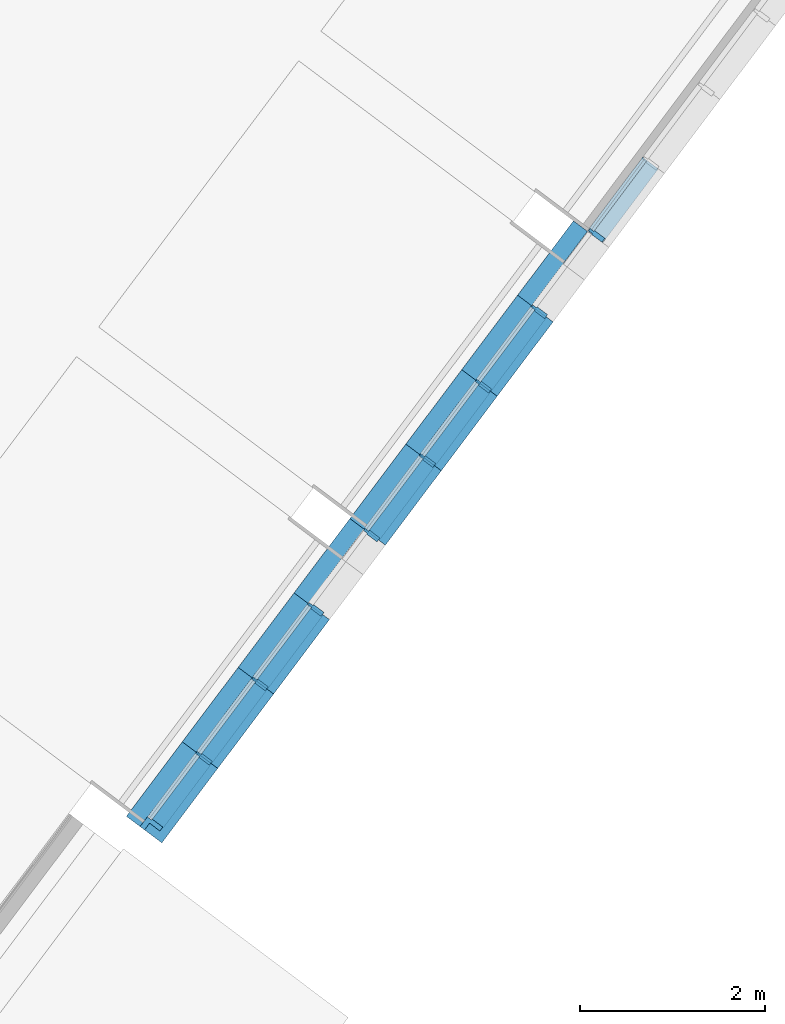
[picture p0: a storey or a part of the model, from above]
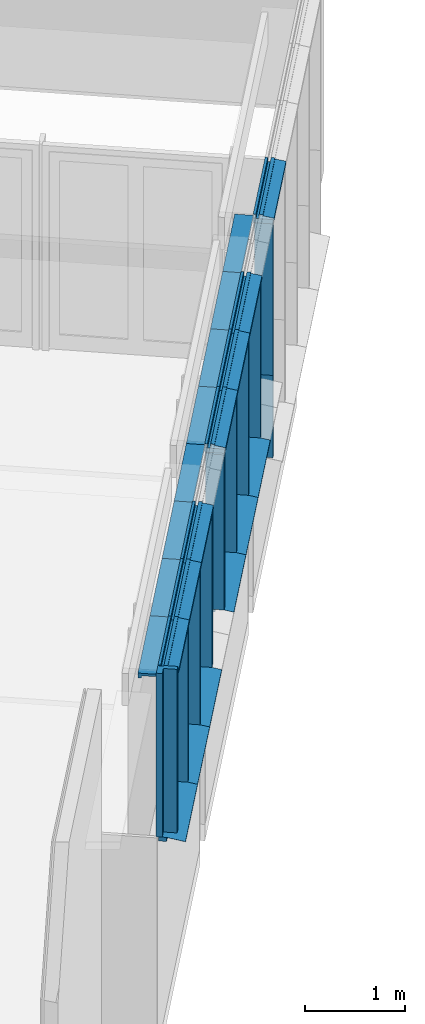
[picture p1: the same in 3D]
Properties of the parts of a building model (IFC2X3), part 6 of 6

# IfcWindow: MC- Fusta- vidre fix:MC- Fusta- vidre fix (49)
Name (MC- Fusta- vidre fix:MC- Fusta- vidre fix:...) | OverallHeight (m) | OverallWidth (m) | Group
4940749 | 2.475 | 0.97 | Grupo de modelo:Grup aula:4940822
4940741 | 2.475 | 0.97 | Grupo de modelo:Grup aula:4940822
4940737 | 2.475 | 0.97 | Grupo de modelo:Grup aula:4940822
4940733 | 2.475 | 0.97 | Grupo de modelo:Grup aula:4940822
4940725 | 2.475 | 0.97 | Grupo de modelo:Grup aula:4940822
5092980 | 2.46 | 0.38
